VERSION 5.8 ;
BUSBITCHARS "[]" ;
DIVIDERCHAR "/" ;
UNITS
    DATABASE MICRONS 1000 ;
END UNITS

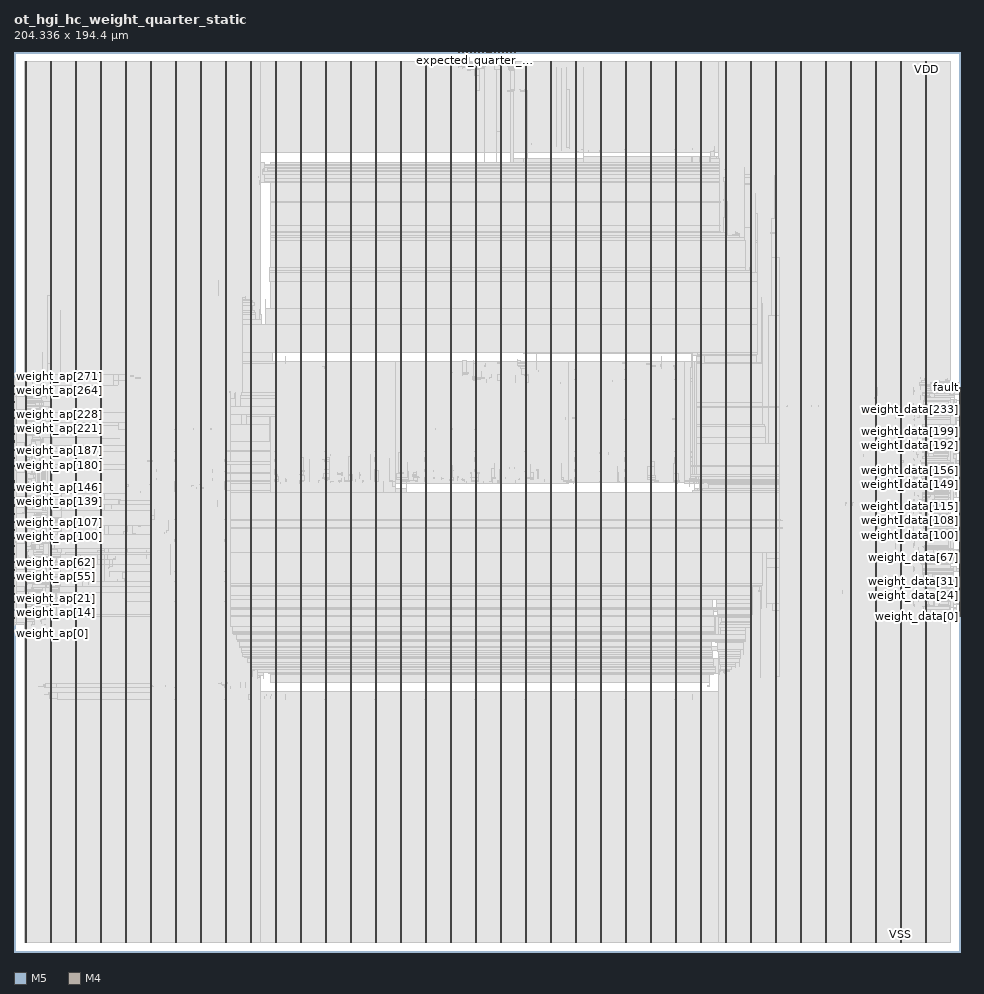
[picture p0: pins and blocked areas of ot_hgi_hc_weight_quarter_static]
MACRO ot_hgi_hc_weight_quarter_static
  FOREIGN ot_hgi_hc_weight_quarter_static 0 0 ;
  CLASS BLOCK ;
  SIZE 204.336 BY 194.4 ;
  PIN clk
    DIRECTION INPUT ;
    USE SIGNAL ;
    PORT
      LAYER M5 ;
        RECT  102.144 194.316 102.168 194.4 ;
    END
  END clk
  PIN expected_bank_id[0]
    DIRECTION INPUT ;
    USE SIGNAL ;
    PORT
      LAYER M5 ;
        RECT  96.096 194.316 96.12 194.4 ;
    END
  END expected_bank_id[0]
  PIN expected_bank_id[1]
    DIRECTION INPUT ;
    USE SIGNAL ;
    PORT
      LAYER M5 ;
        RECT  96.96 194.316 96.984 194.4 ;
    END
  END expected_bank_id[1]
  PIN expected_bank_id[2]
    DIRECTION INPUT ;
    USE SIGNAL ;
    PORT
      LAYER M5 ;
        RECT  97.824 194.316 97.848 194.4 ;
    END
  END expected_bank_id[2]
  PIN expected_quarter_id[0]
    DIRECTION INPUT ;
    USE SIGNAL ;
    PORT
      LAYER M5 ;
        RECT  98.688 194.316 98.712 194.4 ;
    END
  END expected_quarter_id[0]
  PIN expected_quarter_id[1]
    DIRECTION INPUT ;
    USE SIGNAL ;
    PORT
      LAYER M5 ;
        RECT  99.552 194.316 99.576 194.4 ;
    END
  END expected_quarter_id[1]
  PIN fault
    DIRECTION OUTPUT ;
    USE SIGNAL ;
    PORT
      LAYER M4 ;
        RECT  204.252 121.968 204.336 121.992 ;
    END
  END fault
  PIN read_row[0]
    DIRECTION INPUT ;
    USE SIGNAL ;
    PORT
      LAYER M5 ;
        RECT  102.576 194.316 102.6 194.4 ;
    END
  END read_row[0]
  PIN read_row[1]
    DIRECTION INPUT ;
    USE SIGNAL ;
    PORT
      LAYER M5 ;
        RECT  103.008 194.316 103.032 194.4 ;
    END
  END read_row[1]
  PIN read_row[2]
    DIRECTION INPUT ;
    USE SIGNAL ;
    PORT
      LAYER M5 ;
        RECT  103.872 194.316 103.896 194.4 ;
    END
  END read_row[2]
  PIN read_row[3]
    DIRECTION INPUT ;
    USE SIGNAL ;
    PORT
      LAYER M5 ;
        RECT  104.736 194.316 104.76 194.4 ;
    END
  END read_row[3]
  PIN read_row[4]
    DIRECTION INPUT ;
    USE SIGNAL ;
    PORT
      LAYER M5 ;
        RECT  105.6 194.316 105.624 194.4 ;
    END
  END read_row[4]
  PIN read_row[5]
    DIRECTION INPUT ;
    USE SIGNAL ;
    PORT
      LAYER M5 ;
        RECT  106.464 194.316 106.488 194.4 ;
    END
  END read_row[5]
  PIN read_row[6]
    DIRECTION INPUT ;
    USE SIGNAL ;
    PORT
      LAYER M5 ;
        RECT  107.328 194.316 107.352 194.4 ;
    END
  END read_row[6]
  PIN read_slot
    DIRECTION INPUT ;
    USE SIGNAL ;
    PORT
      LAYER M5 ;
        RECT  101.28 194.316 101.304 194.4 ;
    END
  END read_slot
  PIN read_v
    DIRECTION INPUT ;
    USE SIGNAL ;
    PORT
      LAYER M5 ;
        RECT  100.416 194.316 100.44 194.4 ;
    END
  END read_v
  PIN read_valid
    DIRECTION OUTPUT ;
    USE SIGNAL ;
    PORT
      LAYER M4 ;
        RECT  204.252 121.776 204.336 121.8 ;
    END
  END read_valid
  PIN rst_n
    DIRECTION INPUT ;
    USE SIGNAL ;
    PORT
      LAYER M5 ;
        RECT  108.192 194.316 108.216 194.4 ;
    END
  END rst_n
  PIN weight_ap[0]
    DIRECTION INPUT ;
    USE SIGNAL ;
    PORT
      LAYER M4 ;
        RECT  0 70.608 0.084 70.632 ;
    END
  END weight_ap[0]
  PIN weight_ap[100]
    DIRECTION INPUT ;
    USE SIGNAL ;
    PORT
      LAYER M4 ;
        RECT  0 89.808 0.084 89.832 ;
    END
  END weight_ap[100]
  PIN weight_ap[101]
    DIRECTION INPUT ;
    USE SIGNAL ;
    PORT
      LAYER M4 ;
        RECT  0 90 0.084 90.024 ;
    END
  END weight_ap[101]
  PIN weight_ap[102]
    DIRECTION INPUT ;
    USE SIGNAL ;
    PORT
      LAYER M4 ;
        RECT  0 90.192 0.084 90.216 ;
    END
  END weight_ap[102]
  PIN weight_ap[103]
    DIRECTION INPUT ;
    USE SIGNAL ;
    PORT
      LAYER M4 ;
        RECT  0 90.384 0.084 90.408 ;
    END
  END weight_ap[103]
  PIN weight_ap[104]
    DIRECTION INPUT ;
    USE SIGNAL ;
    PORT
      LAYER M4 ;
        RECT  0 90.576 0.084 90.6 ;
    END
  END weight_ap[104]
  PIN weight_ap[105]
    DIRECTION INPUT ;
    USE SIGNAL ;
    PORT
      LAYER M4 ;
        RECT  0 90.768 0.084 90.792 ;
    END
  END weight_ap[105]
  PIN weight_ap[106]
    DIRECTION INPUT ;
    USE SIGNAL ;
    PORT
      LAYER M4 ;
        RECT  0 90.96 0.084 90.984 ;
    END
  END weight_ap[106]
  PIN weight_ap[107]
    DIRECTION INPUT ;
    USE SIGNAL ;
    PORT
      LAYER M4 ;
        RECT  0 91.152 0.084 91.176 ;
    END
  END weight_ap[107]
  PIN weight_ap[108]
    DIRECTION INPUT ;
    USE SIGNAL ;
    PORT
      LAYER M4 ;
        RECT  0 91.344 0.084 91.368 ;
    END
  END weight_ap[108]
  PIN weight_ap[109]
    DIRECTION INPUT ;
    USE SIGNAL ;
    PORT
      LAYER M4 ;
        RECT  0 91.536 0.084 91.56 ;
    END
  END weight_ap[109]
  PIN weight_ap[10]
    DIRECTION INPUT ;
    USE SIGNAL ;
    PORT
      LAYER M4 ;
        RECT  0 72.528 0.084 72.552 ;
    END
  END weight_ap[10]
  PIN weight_ap[110]
    DIRECTION INPUT ;
    USE SIGNAL ;
    PORT
      LAYER M4 ;
        RECT  0 91.728 0.084 91.752 ;
    END
  END weight_ap[110]
  PIN weight_ap[111]
    DIRECTION INPUT ;
    USE SIGNAL ;
    PORT
      LAYER M4 ;
        RECT  0 91.92 0.084 91.944 ;
    END
  END weight_ap[111]
  PIN weight_ap[112]
    DIRECTION INPUT ;
    USE SIGNAL ;
    PORT
      LAYER M4 ;
        RECT  0 92.112 0.084 92.136 ;
    END
  END weight_ap[112]
  PIN weight_ap[113]
    DIRECTION INPUT ;
    USE SIGNAL ;
    PORT
      LAYER M4 ;
        RECT  0 92.304 0.084 92.328 ;
    END
  END weight_ap[113]
  PIN weight_ap[114]
    DIRECTION INPUT ;
    USE SIGNAL ;
    PORT
      LAYER M4 ;
        RECT  0 92.496 0.084 92.52 ;
    END
  END weight_ap[114]
  PIN weight_ap[115]
    DIRECTION INPUT ;
    USE SIGNAL ;
    PORT
      LAYER M4 ;
        RECT  0 92.688 0.084 92.712 ;
    END
  END weight_ap[115]
  PIN weight_ap[116]
    DIRECTION INPUT ;
    USE SIGNAL ;
    PORT
      LAYER M4 ;
        RECT  0 92.88 0.084 92.904 ;
    END
  END weight_ap[116]
  PIN weight_ap[117]
    DIRECTION INPUT ;
    USE SIGNAL ;
    PORT
      LAYER M4 ;
        RECT  0 93.072 0.084 93.096 ;
    END
  END weight_ap[117]
  PIN weight_ap[118]
    DIRECTION INPUT ;
    USE SIGNAL ;
    PORT
      LAYER M4 ;
        RECT  0 93.264 0.084 93.288 ;
    END
  END weight_ap[118]
  PIN weight_ap[119]
    DIRECTION INPUT ;
    USE SIGNAL ;
    PORT
      LAYER M4 ;
        RECT  0 93.456 0.084 93.48 ;
    END
  END weight_ap[119]
  PIN weight_ap[11]
    DIRECTION INPUT ;
    USE SIGNAL ;
    PORT
      LAYER M4 ;
        RECT  0 72.72 0.084 72.744 ;
    END
  END weight_ap[11]
  PIN weight_ap[120]
    DIRECTION INPUT ;
    USE SIGNAL ;
    PORT
      LAYER M4 ;
        RECT  0 93.648 0.084 93.672 ;
    END
  END weight_ap[120]
  PIN weight_ap[121]
    DIRECTION INPUT ;
    USE SIGNAL ;
    PORT
      LAYER M4 ;
        RECT  0 93.84 0.084 93.864 ;
    END
  END weight_ap[121]
  PIN weight_ap[122]
    DIRECTION INPUT ;
    USE SIGNAL ;
    PORT
      LAYER M4 ;
        RECT  0 94.032 0.084 94.056 ;
    END
  END weight_ap[122]
  PIN weight_ap[123]
    DIRECTION INPUT ;
    USE SIGNAL ;
    PORT
      LAYER M4 ;
        RECT  0 94.224 0.084 94.248 ;
    END
  END weight_ap[123]
  PIN weight_ap[124]
    DIRECTION INPUT ;
    USE SIGNAL ;
    PORT
      LAYER M4 ;
        RECT  0 94.416 0.084 94.44 ;
    END
  END weight_ap[124]
  PIN weight_ap[125]
    DIRECTION INPUT ;
    USE SIGNAL ;
    PORT
      LAYER M4 ;
        RECT  0 94.608 0.084 94.632 ;
    END
  END weight_ap[125]
  PIN weight_ap[126]
    DIRECTION INPUT ;
    USE SIGNAL ;
    PORT
      LAYER M4 ;
        RECT  0 94.8 0.084 94.824 ;
    END
  END weight_ap[126]
  PIN weight_ap[127]
    DIRECTION INPUT ;
    USE SIGNAL ;
    PORT
      LAYER M4 ;
        RECT  0 94.992 0.084 95.016 ;
    END
  END weight_ap[127]
  PIN weight_ap[128]
    DIRECTION INPUT ;
    USE SIGNAL ;
    PORT
      LAYER M4 ;
        RECT  0 95.184 0.084 95.208 ;
    END
  END weight_ap[128]
  PIN weight_ap[129]
    DIRECTION INPUT ;
    USE SIGNAL ;
    PORT
      LAYER M4 ;
        RECT  0 95.376 0.084 95.4 ;
    END
  END weight_ap[129]
  PIN weight_ap[12]
    DIRECTION INPUT ;
    USE SIGNAL ;
    PORT
      LAYER M4 ;
        RECT  0 72.912 0.084 72.936 ;
    END
  END weight_ap[12]
  PIN weight_ap[130]
    DIRECTION INPUT ;
    USE SIGNAL ;
    PORT
      LAYER M4 ;
        RECT  0 95.568 0.084 95.592 ;
    END
  END weight_ap[130]
  PIN weight_ap[131]
    DIRECTION INPUT ;
    USE SIGNAL ;
    PORT
      LAYER M4 ;
        RECT  0 95.76 0.084 95.784 ;
    END
  END weight_ap[131]
  PIN weight_ap[132]
    DIRECTION INPUT ;
    USE SIGNAL ;
    PORT
      LAYER M4 ;
        RECT  0 95.952 0.084 95.976 ;
    END
  END weight_ap[132]
  PIN weight_ap[133]
    DIRECTION INPUT ;
    USE SIGNAL ;
    PORT
      LAYER M4 ;
        RECT  0 96.144 0.084 96.168 ;
    END
  END weight_ap[133]
  PIN weight_ap[134]
    DIRECTION INPUT ;
    USE SIGNAL ;
    PORT
      LAYER M4 ;
        RECT  0 96.336 0.084 96.36 ;
    END
  END weight_ap[134]
  PIN weight_ap[135]
    DIRECTION INPUT ;
    USE SIGNAL ;
    PORT
      LAYER M4 ;
        RECT  0 96.528 0.084 96.552 ;
    END
  END weight_ap[135]
  PIN weight_ap[136]
    DIRECTION INPUT ;
    USE SIGNAL ;
    PORT
      LAYER M4 ;
        RECT  0 96.72 0.084 96.744 ;
    END
  END weight_ap[136]
  PIN weight_ap[137]
    DIRECTION INPUT ;
    USE SIGNAL ;
    PORT
      LAYER M4 ;
        RECT  0 96.912 0.084 96.936 ;
    END
  END weight_ap[137]
  PIN weight_ap[138]
    DIRECTION INPUT ;
    USE SIGNAL ;
    PORT
      LAYER M4 ;
        RECT  0 97.104 0.084 97.128 ;
    END
  END weight_ap[138]
  PIN weight_ap[139]
    DIRECTION INPUT ;
    USE SIGNAL ;
    PORT
      LAYER M4 ;
        RECT  0 97.296 0.084 97.32 ;
    END
  END weight_ap[139]
  PIN weight_ap[13]
    DIRECTION INPUT ;
    USE SIGNAL ;
    PORT
      LAYER M4 ;
        RECT  0 73.104 0.084 73.128 ;
    END
  END weight_ap[13]
  PIN weight_ap[140]
    DIRECTION INPUT ;
    USE SIGNAL ;
    PORT
      LAYER M4 ;
        RECT  0 97.488 0.084 97.512 ;
    END
  END weight_ap[140]
  PIN weight_ap[141]
    DIRECTION INPUT ;
    USE SIGNAL ;
    PORT
      LAYER M4 ;
        RECT  0 97.68 0.084 97.704 ;
    END
  END weight_ap[141]
  PIN weight_ap[142]
    DIRECTION INPUT ;
    USE SIGNAL ;
    PORT
      LAYER M4 ;
        RECT  0 97.872 0.084 97.896 ;
    END
  END weight_ap[142]
  PIN weight_ap[143]
    DIRECTION INPUT ;
    USE SIGNAL ;
    PORT
      LAYER M4 ;
        RECT  0 98.064 0.084 98.088 ;
    END
  END weight_ap[143]
  PIN weight_ap[144]
    DIRECTION INPUT ;
    USE SIGNAL ;
    PORT
      LAYER M4 ;
        RECT  0 98.256 0.084 98.28 ;
    END
  END weight_ap[144]
  PIN weight_ap[145]
    DIRECTION INPUT ;
    USE SIGNAL ;
    PORT
      LAYER M4 ;
        RECT  0 98.448 0.084 98.472 ;
    END
  END weight_ap[145]
  PIN weight_ap[146]
    DIRECTION INPUT ;
    USE SIGNAL ;
    PORT
      LAYER M4 ;
        RECT  0 98.64 0.084 98.664 ;
    END
  END weight_ap[146]
  PIN weight_ap[147]
    DIRECTION INPUT ;
    USE SIGNAL ;
    PORT
      LAYER M4 ;
        RECT  0 98.832 0.084 98.856 ;
    END
  END weight_ap[147]
  PIN weight_ap[148]
    DIRECTION INPUT ;
    USE SIGNAL ;
    PORT
      LAYER M4 ;
        RECT  0 99.024 0.084 99.048 ;
    END
  END weight_ap[148]
  PIN weight_ap[149]
    DIRECTION INPUT ;
    USE SIGNAL ;
    PORT
      LAYER M4 ;
        RECT  0 99.216 0.084 99.24 ;
    END
  END weight_ap[149]
  PIN weight_ap[14]
    DIRECTION INPUT ;
    USE SIGNAL ;
    PORT
      LAYER M4 ;
        RECT  0 73.296 0.084 73.32 ;
    END
  END weight_ap[14]
  PIN weight_ap[150]
    DIRECTION INPUT ;
    USE SIGNAL ;
    PORT
      LAYER M4 ;
        RECT  0 99.408 0.084 99.432 ;
    END
  END weight_ap[150]
  PIN weight_ap[151]
    DIRECTION INPUT ;
    USE SIGNAL ;
    PORT
      LAYER M4 ;
        RECT  0 99.6 0.084 99.624 ;
    END
  END weight_ap[151]
  PIN weight_ap[152]
    DIRECTION INPUT ;
    USE SIGNAL ;
    PORT
      LAYER M4 ;
        RECT  0 99.792 0.084 99.816 ;
    END
  END weight_ap[152]
  PIN weight_ap[153]
    DIRECTION INPUT ;
    USE SIGNAL ;
    PORT
      LAYER M4 ;
        RECT  0 99.984 0.084 100.008 ;
    END
  END weight_ap[153]
  PIN weight_ap[154]
    DIRECTION INPUT ;
    USE SIGNAL ;
    PORT
      LAYER M4 ;
        RECT  0 100.176 0.084 100.2 ;
    END
  END weight_ap[154]
  PIN weight_ap[155]
    DIRECTION INPUT ;
    USE SIGNAL ;
    PORT
      LAYER M4 ;
        RECT  0 100.368 0.084 100.392 ;
    END
  END weight_ap[155]
  PIN weight_ap[156]
    DIRECTION INPUT ;
    USE SIGNAL ;
    PORT
      LAYER M4 ;
        RECT  0 100.56 0.084 100.584 ;
    END
  END weight_ap[156]
  PIN weight_ap[157]
    DIRECTION INPUT ;
    USE SIGNAL ;
    PORT
      LAYER M4 ;
        RECT  0 100.752 0.084 100.776 ;
    END
  END weight_ap[157]
  PIN weight_ap[158]
    DIRECTION INPUT ;
    USE SIGNAL ;
    PORT
      LAYER M4 ;
        RECT  0 100.944 0.084 100.968 ;
    END
  END weight_ap[158]
  PIN weight_ap[159]
    DIRECTION INPUT ;
    USE SIGNAL ;
    PORT
      LAYER M4 ;
        RECT  0 101.136 0.084 101.16 ;
    END
  END weight_ap[159]
  PIN weight_ap[15]
    DIRECTION INPUT ;
    USE SIGNAL ;
    PORT
      LAYER M4 ;
        RECT  0 73.488 0.084 73.512 ;
    END
  END weight_ap[15]
  PIN weight_ap[160]
    DIRECTION INPUT ;
    USE SIGNAL ;
    PORT
      LAYER M4 ;
        RECT  0 101.328 0.084 101.352 ;
    END
  END weight_ap[160]
  PIN weight_ap[161]
    DIRECTION INPUT ;
    USE SIGNAL ;
    PORT
      LAYER M4 ;
        RECT  0 101.52 0.084 101.544 ;
    END
  END weight_ap[161]
  PIN weight_ap[162]
    DIRECTION INPUT ;
    USE SIGNAL ;
    PORT
      LAYER M4 ;
        RECT  0 101.712 0.084 101.736 ;
    END
  END weight_ap[162]
  PIN weight_ap[163]
    DIRECTION INPUT ;
    USE SIGNAL ;
    PORT
      LAYER M4 ;
        RECT  0 101.904 0.084 101.928 ;
    END
  END weight_ap[163]
  PIN weight_ap[164]
    DIRECTION INPUT ;
    USE SIGNAL ;
    PORT
      LAYER M4 ;
        RECT  0 102.096 0.084 102.12 ;
    END
  END weight_ap[164]
  PIN weight_ap[165]
    DIRECTION INPUT ;
    USE SIGNAL ;
    PORT
      LAYER M4 ;
        RECT  0 102.288 0.084 102.312 ;
    END
  END weight_ap[165]
  PIN weight_ap[166]
    DIRECTION INPUT ;
    USE SIGNAL ;
    PORT
      LAYER M4 ;
        RECT  0 102.48 0.084 102.504 ;
    END
  END weight_ap[166]
  PIN weight_ap[167]
    DIRECTION INPUT ;
    USE SIGNAL ;
    PORT
      LAYER M4 ;
        RECT  0 102.672 0.084 102.696 ;
    END
  END weight_ap[167]
  PIN weight_ap[168]
    DIRECTION INPUT ;
    USE SIGNAL ;
    PORT
      LAYER M4 ;
        RECT  0 102.864 0.084 102.888 ;
    END
  END weight_ap[168]
  PIN weight_ap[169]
    DIRECTION INPUT ;
    USE SIGNAL ;
    PORT
      LAYER M4 ;
        RECT  0 103.056 0.084 103.08 ;
    END
  END weight_ap[169]
  PIN weight_ap[16]
    DIRECTION INPUT ;
    USE SIGNAL ;
    PORT
      LAYER M4 ;
        RECT  0 73.68 0.084 73.704 ;
    END
  END weight_ap[16]
  PIN weight_ap[170]
    DIRECTION INPUT ;
    USE SIGNAL ;
    PORT
      LAYER M4 ;
        RECT  0 103.248 0.084 103.272 ;
    END
  END weight_ap[170]
  PIN weight_ap[171]
    DIRECTION INPUT ;
    USE SIGNAL ;
    PORT
      LAYER M4 ;
        RECT  0 103.44 0.084 103.464 ;
    END
  END weight_ap[171]
  PIN weight_ap[172]
    DIRECTION INPUT ;
    USE SIGNAL ;
    PORT
      LAYER M4 ;
        RECT  0 103.632 0.084 103.656 ;
    END
  END weight_ap[172]
  PIN weight_ap[173]
    DIRECTION INPUT ;
    USE SIGNAL ;
    PORT
      LAYER M4 ;
        RECT  0 103.824 0.084 103.848 ;
    END
  END weight_ap[173]
  PIN weight_ap[174]
    DIRECTION INPUT ;
    USE SIGNAL ;
    PORT
      LAYER M4 ;
        RECT  0 104.016 0.084 104.04 ;
    END
  END weight_ap[174]
  PIN weight_ap[175]
    DIRECTION INPUT ;
    USE SIGNAL ;
    PORT
      LAYER M4 ;
        RECT  0 104.208 0.084 104.232 ;
    END
  END weight_ap[175]
  PIN weight_ap[176]
    DIRECTION INPUT ;
    USE SIGNAL ;
    PORT
      LAYER M4 ;
        RECT  0 104.4 0.084 104.424 ;
    END
  END weight_ap[176]
  PIN weight_ap[177]
    DIRECTION INPUT ;
    USE SIGNAL ;
    PORT
      LAYER M4 ;
        RECT  0 104.592 0.084 104.616 ;
    END
  END weight_ap[177]
  PIN weight_ap[178]
    DIRECTION INPUT ;
    USE SIGNAL ;
    PORT
      LAYER M4 ;
        RECT  0 104.784 0.084 104.808 ;
    END
  END weight_ap[178]
  PIN weight_ap[179]
    DIRECTION INPUT ;
    USE SIGNAL ;
    PORT
      LAYER M4 ;
        RECT  0 104.976 0.084 105 ;
    END
  END weight_ap[179]
  PIN weight_ap[17]
    DIRECTION INPUT ;
    USE SIGNAL ;
    PORT
      LAYER M4 ;
        RECT  0 73.872 0.084 73.896 ;
    END
  END weight_ap[17]
  PIN weight_ap[180]
    DIRECTION INPUT ;
    USE SIGNAL ;
    PORT
      LAYER M4 ;
        RECT  0 105.168 0.084 105.192 ;
    END
  END weight_ap[180]
  PIN weight_ap[181]
    DIRECTION INPUT ;
    USE SIGNAL ;
    PORT
      LAYER M4 ;
        RECT  0 105.36 0.084 105.384 ;
    END
  END weight_ap[181]
  PIN weight_ap[182]
    DIRECTION INPUT ;
    USE SIGNAL ;
    PORT
      LAYER M4 ;
        RECT  0 105.552 0.084 105.576 ;
    END
  END weight_ap[182]
  PIN weight_ap[183]
    DIRECTION INPUT ;
    USE SIGNAL ;
    PORT
      LAYER M4 ;
        RECT  0 105.744 0.084 105.768 ;
    END
  END weight_ap[183]
  PIN weight_ap[184]
    DIRECTION INPUT ;
    USE SIGNAL ;
    PORT
      LAYER M4 ;
        RECT  0 105.936 0.084 105.96 ;
    END
  END weight_ap[184]
  PIN weight_ap[185]
    DIRECTION INPUT ;
    USE SIGNAL ;
    PORT
      LAYER M4 ;
        RECT  0 106.128 0.084 106.152 ;
    END
  END weight_ap[185]
  PIN weight_ap[186]
    DIRECTION INPUT ;
    USE SIGNAL ;
    PORT
      LAYER M4 ;
        RECT  0 106.32 0.084 106.344 ;
    END
  END weight_ap[186]
  PIN weight_ap[187]
    DIRECTION INPUT ;
    USE SIGNAL ;
    PORT
      LAYER M4 ;
        RECT  0 106.512 0.084 106.536 ;
    END
  END weight_ap[187]
  PIN weight_ap[188]
    DIRECTION INPUT ;
    USE SIGNAL ;
    PORT
      LAYER M4 ;
        RECT  0 106.704 0.084 106.728 ;
    END
  END weight_ap[188]
  PIN weight_ap[189]
    DIRECTION INPUT ;
    USE SIGNAL ;
    PORT
      LAYER M4 ;
        RECT  0 106.896 0.084 106.92 ;
    END
  END weight_ap[189]
  PIN weight_ap[18]
    DIRECTION INPUT ;
    USE SIGNAL ;
    PORT
      LAYER M4 ;
        RECT  0 74.064 0.084 74.088 ;
    END
  END weight_ap[18]
  PIN weight_ap[190]
    DIRECTION INPUT ;
    USE SIGNAL ;
    PORT
      LAYER M4 ;
        RECT  0 107.088 0.084 107.112 ;
    END
  END weight_ap[190]
  PIN weight_ap[191]
    DIRECTION INPUT ;
    USE SIGNAL ;
    PORT
      LAYER M4 ;
        RECT  0 107.28 0.084 107.304 ;
    END
  END weight_ap[191]
  PIN weight_ap[192]
    DIRECTION INPUT ;
    USE SIGNAL ;
    PORT
      LAYER M4 ;
        RECT  0 107.472 0.084 107.496 ;
    END
  END weight_ap[192]
  PIN weight_ap[193]
    DIRECTION INPUT ;
    USE SIGNAL ;
    PORT
      LAYER M4 ;
        RECT  0 107.664 0.084 107.688 ;
    END
  END weight_ap[193]
  PIN weight_ap[194]
    DIRECTION INPUT ;
    USE SIGNAL ;
    PORT
      LAYER M4 ;
        RECT  0 107.856 0.084 107.88 ;
    END
  END weight_ap[194]
  PIN weight_ap[195]
    DIRECTION INPUT ;
    USE SIGNAL ;
    PORT
      LAYER M4 ;
        RECT  0 108.048 0.084 108.072 ;
    END
  END weight_ap[195]
  PIN weight_ap[196]
    DIRECTION INPUT ;
    USE SIGNAL ;
    PORT
      LAYER M4 ;
        RECT  0 108.24 0.084 108.264 ;
    END
  END weight_ap[196]
  PIN weight_ap[197]
    DIRECTION INPUT ;
    USE SIGNAL ;
    PORT
      LAYER M4 ;
        RECT  0 108.432 0.084 108.456 ;
    END
  END weight_ap[197]
  PIN weight_ap[198]
    DIRECTION INPUT ;
    USE SIGNAL ;
    PORT
      LAYER M4 ;
        RECT  0 108.624 0.084 108.648 ;
    END
  END weight_ap[198]
  PIN weight_ap[199]
    DIRECTION INPUT ;
    USE SIGNAL ;
    PORT
      LAYER M4 ;
        RECT  0 108.816 0.084 108.84 ;
    END
  END weight_ap[199]
  PIN weight_ap[19]
    DIRECTION INPUT ;
    USE SIGNAL ;
    PORT
      LAYER M4 ;
        RECT  0 74.256 0.084 74.28 ;
    END
  END weight_ap[19]
  PIN weight_ap[1]
    DIRECTION INPUT ;
    USE SIGNAL ;
    PORT
      LAYER M4 ;
        RECT  0 70.8 0.084 70.824 ;
    END
  END weight_ap[1]
  PIN weight_ap[200]
    DIRECTION INPUT ;
    USE SIGNAL ;
    PORT
      LAYER M4 ;
        RECT  0 109.008 0.084 109.032 ;
    END
  END weight_ap[200]
  PIN weight_ap[201]
    DIRECTION INPUT ;
    USE SIGNAL ;
    PORT
      LAYER M4 ;
        RECT  0 109.2 0.084 109.224 ;
    END
  END weight_ap[201]
  PIN weight_ap[202]
    DIRECTION INPUT ;
    USE SIGNAL ;
    PORT
      LAYER M4 ;
        RECT  0 109.392 0.084 109.416 ;
    END
  END weight_ap[202]
  PIN weight_ap[203]
    DIRECTION INPUT ;
    USE SIGNAL ;
    PORT
      LAYER M4 ;
        RECT  0 109.584 0.084 109.608 ;
    END
  END weight_ap[203]
  PIN weight_ap[204]
    DIRECTION INPUT ;
    USE SIGNAL ;
    PORT
      LAYER M4 ;
        RECT  0 109.776 0.084 109.8 ;
    END
  END weight_ap[204]
  PIN weight_ap[205]
    DIRECTION INPUT ;
    USE SIGNAL ;
    PORT
      LAYER M4 ;
        RECT  0 109.968 0.084 109.992 ;
    END
  END weight_ap[205]
  PIN weight_ap[206]
    DIRECTION INPUT ;
    USE SIGNAL ;
    PORT
      LAYER M4 ;
        RECT  0 110.16 0.084 110.184 ;
    END
  END weight_ap[206]
  PIN weight_ap[207]
    DIRECTION INPUT ;
    USE SIGNAL ;
    PORT
      LAYER M4 ;
        RECT  0 110.352 0.084 110.376 ;
    END
  END weight_ap[207]
  PIN weight_ap[208]
    DIRECTION INPUT ;
    USE SIGNAL ;
    PORT
      LAYER M4 ;
        RECT  0 110.544 0.084 110.568 ;
    END
  END weight_ap[208]
  PIN weight_ap[209]
    DIRECTION INPUT ;
    USE SIGNAL ;
    PORT
      LAYER M4 ;
        RECT  0 110.736 0.084 110.76 ;
    END
  END weight_ap[209]
  PIN weight_ap[20]
    DIRECTION INPUT ;
    USE SIGNAL ;
    PORT
      LAYER M4 ;
        RECT  0 74.448 0.084 74.472 ;
    END
  END weight_ap[20]
  PIN weight_ap[210]
    DIRECTION INPUT ;
    USE SIGNAL ;
    PORT
      LAYER M4 ;
        RECT  0 110.928 0.084 110.952 ;
    END
  END weight_ap[210]
  PIN weight_ap[211]
    DIRECTION INPUT ;
    USE SIGNAL ;
    PORT
      LAYER M4 ;
        RECT  0 111.12 0.084 111.144 ;
    END
  END weight_ap[211]
  PIN weight_ap[212]
    DIRECTION INPUT ;
    USE SIGNAL ;
    PORT
      LAYER M4 ;
        RECT  0 111.312 0.084 111.336 ;
    END
  END weight_ap[212]
  PIN weight_ap[213]
    DIRECTION INPUT ;
    USE SIGNAL ;
    PORT
      LAYER M4 ;
        RECT  0 111.504 0.084 111.528 ;
    END
  END weight_ap[213]
  PIN weight_ap[214]
    DIRECTION INPUT ;
    USE SIGNAL ;
    PORT
      LAYER M4 ;
        RECT  0 111.696 0.084 111.72 ;
    END
  END weight_ap[214]
  PIN weight_ap[215]
    DIRECTION INPUT ;
    USE SIGNAL ;
    PORT
      LAYER M4 ;
        RECT  0 111.888 0.084 111.912 ;
    END
  END weight_ap[215]
  PIN weight_ap[216]
    DIRECTION INPUT ;
    USE SIGNAL ;
    PORT
      LAYER M4 ;
        RECT  0 112.08 0.084 112.104 ;
    END
  END weight_ap[216]
  PIN weight_ap[217]
    DIRECTION INPUT ;
    USE SIGNAL ;
    PORT
      LAYER M4 ;
        RECT  0 112.272 0.084 112.296 ;
    END
  END weight_ap[217]
  PIN weight_ap[218]
    DIRECTION INPUT ;
    USE SIGNAL ;
    PORT
      LAYER M4 ;
        RECT  0 112.464 0.084 112.488 ;
    END
  END weight_ap[218]
  PIN weight_ap[219]
    DIRECTION INPUT ;
    USE SIGNAL ;
    PORT
      LAYER M4 ;
        RECT  0 112.656 0.084 112.68 ;
    END
  END weight_ap[219]
  PIN weight_ap[21]
    DIRECTION INPUT ;
    USE SIGNAL ;
    PORT
      LAYER M4 ;
        RECT  0 74.64 0.084 74.664 ;
    END
  END weight_ap[21]
  PIN weight_ap[220]
    DIRECTION INPUT ;
    USE SIGNAL ;
    PORT
      LAYER M4 ;
        RECT  0 112.848 0.084 112.872 ;
    END
  END weight_ap[220]
  PIN weight_ap[221]
    DIRECTION INPUT ;
    USE SIGNAL ;
    PORT
      LAYER M4 ;
        RECT  0 113.04 0.084 113.064 ;
    END
  END weight_ap[221]
  PIN weight_ap[222]
    DIRECTION INPUT ;
    USE SIGNAL ;
    PORT
      LAYER M4 ;
        RECT  0 113.232 0.084 113.256 ;
    END
  END weight_ap[222]
  PIN weight_ap[223]
    DIRECTION INPUT ;
    USE SIGNAL ;
    PORT
      LAYER M4 ;
        RECT  0 113.424 0.084 113.448 ;
    END
  END weight_ap[223]
  PIN weight_ap[224]
    DIRECTION INPUT ;
    USE SIGNAL ;
    PORT
      LAYER M4 ;
        RECT  0 113.616 0.084 113.64 ;
    END
  END weight_ap[224]
  PIN weight_ap[225]
    DIRECTION INPUT ;
    USE SIGNAL ;
    PORT
      LAYER M4 ;
        RECT  0 113.808 0.084 113.832 ;
    END
  END weight_ap[225]
  PIN weight_ap[226]
    DIRECTION INPUT ;
    USE SIGNAL ;
    PORT
      LAYER M4 ;
        RECT  0 114 0.084 114.024 ;
    END
  END weight_ap[226]
  PIN weight_ap[227]
    DIRECTION INPUT ;
    USE SIGNAL ;
    PORT
      LAYER M4 ;
        RECT  0 114.192 0.084 114.216 ;
    END
  END weight_ap[227]
  PIN weight_ap[228]
    DIRECTION INPUT ;
    USE SIGNAL ;
    PORT
      LAYER M4 ;
        RECT  0 114.384 0.084 114.408 ;
    END
  END weight_ap[228]
  PIN weight_ap[229]
    DIRECTION INPUT ;
    USE SIGNAL ;
    PORT
      LAYER M4 ;
        RECT  0 114.576 0.084 114.6 ;
    END
  END weight_ap[229]
  PIN weight_ap[22]
    DIRECTION INPUT ;
    USE SIGNAL ;
    PORT
      LAYER M4 ;
        RECT  0 74.832 0.084 74.856 ;
    END
  END weight_ap[22]
  PIN weight_ap[230]
    DIRECTION INPUT ;
    USE SIGNAL ;
    PORT
      LAYER M4 ;
        RECT  0 114.768 0.084 114.792 ;
    END
  END weight_ap[230]
  PIN weight_ap[231]
    DIRECTION INPUT ;
    USE SIGNAL ;
    PORT
      LAYER M4 ;
        RECT  0 114.96 0.084 114.984 ;
    END
  END weight_ap[231]
  PIN weight_ap[232]
    DIRECTION INPUT ;
    USE SIGNAL ;
    PORT
      LAYER M4 ;
        RECT  0 115.152 0.084 115.176 ;
    END
  END weight_ap[232]
  PIN weight_ap[233]
    DIRECTION INPUT ;
    USE SIGNAL ;
    PORT
      LAYER M4 ;
        RECT  0 115.344 0.084 115.368 ;
    END
  END weight_ap[233]
  PIN weight_ap[234]
    DIRECTION INPUT ;
    USE SIGNAL ;
    PORT
      LAYER M4 ;
        RECT  0 115.536 0.084 115.56 ;
    END
  END weight_ap[234]
  PIN weight_ap[235]
    DIRECTION INPUT ;
    USE SIGNAL ;
    PORT
      LAYER M4 ;
        RECT  0 115.728 0.084 115.752 ;
    END
  END weight_ap[235]
  PIN weight_ap[236]
    DIRECTION INPUT ;
    USE SIGNAL ;
    PORT
      LAYER M4 ;
        RECT  0 115.92 0.084 115.944 ;
    END
  END weight_ap[236]
  PIN weight_ap[237]
    DIRECTION INPUT ;
    USE SIGNAL ;
    PORT
      LAYER M4 ;
        RECT  0 116.112 0.084 116.136 ;
    END
  END weight_ap[237]
  PIN weight_ap[238]
    DIRECTION INPUT ;
    USE SIGNAL ;
    PORT
      LAYER M4 ;
        RECT  0 116.304 0.084 116.328 ;
    END
  END weight_ap[238]
  PIN weight_ap[239]
    DIRECTION INPUT ;
    USE SIGNAL ;
    PORT
      LAYER M4 ;
        RECT  0 116.496 0.084 116.52 ;
    END
  END weight_ap[239]
  PIN weight_ap[23]
    DIRECTION INPUT ;
    USE SIGNAL ;
    PORT
      LAYER M4 ;
        RECT  0 75.024 0.084 75.048 ;
    END
  END weight_ap[23]
  PIN weight_ap[240]
    DIRECTION INPUT ;
    USE SIGNAL ;
    PORT
      LAYER M4 ;
        RECT  0 116.688 0.084 116.712 ;
    END
  END weight_ap[240]
  PIN weight_ap[241]
    DIRECTION INPUT ;
    USE SIGNAL ;
    PORT
      LAYER M4 ;
        RECT  0 116.88 0.084 116.904 ;
    END
  END weight_ap[241]
  PIN weight_ap[242]
    DIRECTION INPUT ;
    USE SIGNAL ;
    PORT
      LAYER M4 ;
        RECT  0 117.072 0.084 117.096 ;
    END
  END weight_ap[242]
  PIN weight_ap[243]
    DIRECTION INPUT ;
    USE SIGNAL ;
    PORT
      LAYER M4 ;
        RECT  0 117.264 0.084 117.288 ;
    END
  END weight_ap[243]
  PIN weight_ap[244]
    DIRECTION INPUT ;
    USE SIGNAL ;
    PORT
      LAYER M4 ;
        RECT  0 117.456 0.084 117.48 ;
    END
  END weight_ap[244]
  PIN weight_ap[245]
    DIRECTION INPUT ;
    USE SIGNAL ;
    PORT
      LAYER M4 ;
        RECT  0 117.648 0.084 117.672 ;
    END
  END weight_ap[245]
  PIN weight_ap[246]
    DIRECTION INPUT ;
    USE SIGNAL ;
    PORT
      LAYER M4 ;
        RECT  0 117.84 0.084 117.864 ;
    END
  END weight_ap[246]
  PIN weight_ap[247]
    DIRECTION INPUT ;
    USE SIGNAL ;
    PORT
      LAYER M4 ;
        RECT  0 118.032 0.084 118.056 ;
    END
  END weight_ap[247]
  PIN weight_ap[248]
    DIRECTION INPUT ;
    USE SIGNAL ;
    PORT
      LAYER M4 ;
        RECT  0 118.224 0.084 118.248 ;
    END
  END weight_ap[248]
  PIN weight_ap[249]
    DIRECTION INPUT ;
    USE SIGNAL ;
    PORT
      LAYER M4 ;
        RECT  0 118.416 0.084 118.44 ;
    END
  END weight_ap[249]
  PIN weight_ap[24]
    DIRECTION INPUT ;
    USE SIGNAL ;
    PORT
      LAYER M4 ;
        RECT  0 75.216 0.084 75.24 ;
    END
  END weight_ap[24]
  PIN weight_ap[250]
    DIRECTION INPUT ;
    USE SIGNAL ;
    PORT
      LAYER M4 ;
        RECT  0 118.608 0.084 118.632 ;
    END
  END weight_ap[250]
  PIN weight_ap[251]
    DIRECTION INPUT ;
    USE SIGNAL ;
    PORT
      LAYER M4 ;
        RECT  0 118.8 0.084 118.824 ;
    END
  END weight_ap[251]
  PIN weight_ap[252]
    DIRECTION INPUT ;
    USE SIGNAL ;
    PORT
      LAYER M4 ;
        RECT  0 118.992 0.084 119.016 ;
    END
  END weight_ap[252]
  PIN weight_ap[253]
    DIRECTION INPUT ;
    USE SIGNAL ;
    PORT
      LAYER M4 ;
        RECT  0 119.184 0.084 119.208 ;
    END
  END weight_ap[253]
  PIN weight_ap[254]
    DIRECTION INPUT ;
    USE SIGNAL ;
    PORT
      LAYER M4 ;
        RECT  0 119.376 0.084 119.4 ;
    END
  END weight_ap[254]
  PIN weight_ap[255]
    DIRECTION INPUT ;
    USE SIGNAL ;
    PORT
      LAYER M4 ;
        RECT  0 119.568 0.084 119.592 ;
    END
  END weight_ap[255]
  PIN weight_ap[256]
    DIRECTION INPUT ;
    USE SIGNAL ;
    PORT
      LAYER M4 ;
        RECT  0 119.76 0.084 119.784 ;
    END
  END weight_ap[256]
  PIN weight_ap[257]
    DIRECTION INPUT ;
    USE SIGNAL ;
    PORT
      LAYER M4 ;
        RECT  0 119.952 0.084 119.976 ;
    END
  END weight_ap[257]
  PIN weight_ap[258]
    DIRECTION INPUT ;
    USE SIGNAL ;
    PORT
      LAYER M4 ;
        RECT  0 120.144 0.084 120.168 ;
    END
  END weight_ap[258]
  PIN weight_ap[259]
    DIRECTION INPUT ;
    USE SIGNAL ;
    PORT
      LAYER M4 ;
        RECT  0 120.336 0.084 120.36 ;
    END
  END weight_ap[259]
  PIN weight_ap[25]
    DIRECTION INPUT ;
    USE SIGNAL ;
    PORT
      LAYER M4 ;
        RECT  0 75.408 0.084 75.432 ;
    END
  END weight_ap[25]
  PIN weight_ap[260]
    DIRECTION INPUT ;
    USE SIGNAL ;
    PORT
      LAYER M4 ;
        RECT  0 120.528 0.084 120.552 ;
    END
  END weight_ap[260]
  PIN weight_ap[261]
    DIRECTION INPUT ;
    USE SIGNAL ;
    PORT
      LAYER M4 ;
        RECT  0 120.72 0.084 120.744 ;
    END
  END weight_ap[261]
  PIN weight_ap[262]
    DIRECTION INPUT ;
    USE SIGNAL ;
    PORT
      LAYER M4 ;
        RECT  0 120.912 0.084 120.936 ;
    END
  END weight_ap[262]
  PIN weight_ap[263]
    DIRECTION INPUT ;
    USE SIGNAL ;
    PORT
      LAYER M4 ;
        RECT  0 121.104 0.084 121.128 ;
    END
  END weight_ap[263]
  PIN weight_ap[264]
    DIRECTION INPUT ;
    USE SIGNAL ;
    PORT
      LAYER M4 ;
        RECT  0 121.296 0.084 121.32 ;
    END
  END weight_ap[264]
  PIN weight_ap[265]
    DIRECTION INPUT ;
    USE SIGNAL ;
    PORT
      LAYER M4 ;
        RECT  0 121.488 0.084 121.512 ;
    END
  END weight_ap[265]
  PIN weight_ap[266]
    DIRECTION INPUT ;
    USE SIGNAL ;
    PORT
      LAYER M4 ;
        RECT  0 121.68 0.084 121.704 ;
    END
  END weight_ap[266]
  PIN weight_ap[267]
    DIRECTION INPUT ;
    USE SIGNAL ;
    PORT
      LAYER M4 ;
        RECT  0 121.872 0.084 121.896 ;
    END
  END weight_ap[267]
  PIN weight_ap[268]
    DIRECTION INPUT ;
    USE SIGNAL ;
    PORT
      LAYER M4 ;
        RECT  0 122.064 0.084 122.088 ;
    END
  END weight_ap[268]
  PIN weight_ap[269]
    DIRECTION INPUT ;
    USE SIGNAL ;
    PORT
      LAYER M4 ;
        RECT  0 122.256 0.084 122.28 ;
    END
  END weight_ap[269]
  PIN weight_ap[26]
    DIRECTION INPUT ;
    USE SIGNAL ;
    PORT
      LAYER M4 ;
        RECT  0 75.6 0.084 75.624 ;
    END
  END weight_ap[26]
  PIN weight_ap[270]
    DIRECTION INPUT ;
    USE SIGNAL ;
    PORT
      LAYER M4 ;
        RECT  0 122.448 0.084 122.472 ;
    END
  END weight_ap[270]
  PIN weight_ap[271]
    DIRECTION INPUT ;
    USE SIGNAL ;
    PORT
      LAYER M4 ;
        RECT  0 122.64 0.084 122.664 ;
    END
  END weight_ap[271]
  PIN weight_ap[272]
    DIRECTION INPUT ;
    USE SIGNAL ;
    PORT
      LAYER M4 ;
        RECT  0 122.832 0.084 122.856 ;
    END
  END weight_ap[272]
  PIN weight_ap[273]
    DIRECTION INPUT ;
    USE SIGNAL ;
    PORT
      LAYER M4 ;
        RECT  0 123.024 0.084 123.048 ;
    END
  END weight_ap[273]
  PIN weight_ap[274]
    DIRECTION INPUT ;
    USE SIGNAL ;
    PORT
      LAYER M4 ;
        RECT  0 123.216 0.084 123.24 ;
    END
  END weight_ap[274]
  PIN weight_ap[275]
    DIRECTION INPUT ;
    USE SIGNAL ;
    PORT
      LAYER M4 ;
        RECT  0 123.408 0.084 123.432 ;
    END
  END weight_ap[275]
  PIN weight_ap[276]
    DIRECTION INPUT ;
    USE SIGNAL ;
    PORT
      LAYER M4 ;
        RECT  0 123.6 0.084 123.624 ;
    END
  END weight_ap[276]
  PIN weight_ap[277]
    DIRECTION INPUT ;
    USE SIGNAL ;
    PORT
      LAYER M4 ;
        RECT  0 123.792 0.084 123.816 ;
    END
  END weight_ap[277]
  PIN weight_ap[27]
    DIRECTION INPUT ;
    USE SIGNAL ;
    PORT
      LAYER M4 ;
        RECT  0 75.792 0.084 75.816 ;
    END
  END weight_ap[27]
  PIN weight_ap[28]
    DIRECTION INPUT ;
    USE SIGNAL ;
    PORT
      LAYER M4 ;
        RECT  0 75.984 0.084 76.008 ;
    END
  END weight_ap[28]
  PIN weight_ap[29]
    DIRECTION INPUT ;
    USE SIGNAL ;
    PORT
      LAYER M4 ;
        RECT  0 76.176 0.084 76.2 ;
    END
  END weight_ap[29]
  PIN weight_ap[2]
    DIRECTION INPUT ;
    USE SIGNAL ;
    PORT
      LAYER M4 ;
        RECT  0 70.992 0.084 71.016 ;
    END
  END weight_ap[2]
  PIN weight_ap[30]
    DIRECTION INPUT ;
    USE SIGNAL ;
    PORT
      LAYER M4 ;
        RECT  0 76.368 0.084 76.392 ;
    END
  END weight_ap[30]
  PIN weight_ap[31]
    DIRECTION INPUT ;
    USE SIGNAL ;
    PORT
      LAYER M4 ;
        RECT  0 76.56 0.084 76.584 ;
    END
  END weight_ap[31]
  PIN weight_ap[32]
    DIRECTION INPUT ;
    USE SIGNAL ;
    PORT
      LAYER M4 ;
        RECT  0 76.752 0.084 76.776 ;
    END
  END weight_ap[32]
  PIN weight_ap[33]
    DIRECTION INPUT ;
    USE SIGNAL ;
    PORT
      LAYER M4 ;
        RECT  0 76.944 0.084 76.968 ;
    END
  END weight_ap[33]
  PIN weight_ap[34]
    DIRECTION INPUT ;
    USE SIGNAL ;
    PORT
      LAYER M4 ;
        RECT  0 77.136 0.084 77.16 ;
    END
  END weight_ap[34]
  PIN weight_ap[35]
    DIRECTION INPUT ;
    USE SIGNAL ;
    PORT
      LAYER M4 ;
        RECT  0 77.328 0.084 77.352 ;
    END
  END weight_ap[35]
  PIN weight_ap[36]
    DIRECTION INPUT ;
    USE SIGNAL ;
    PORT
      LAYER M4 ;
        RECT  0 77.52 0.084 77.544 ;
    END
  END weight_ap[36]
  PIN weight_ap[37]
    DIRECTION INPUT ;
    USE SIGNAL ;
    PORT
      LAYER M4 ;
        RECT  0 77.712 0.084 77.736 ;
    END
  END weight_ap[37]
  PIN weight_ap[38]
    DIRECTION INPUT ;
    USE SIGNAL ;
    PORT
      LAYER M4 ;
        RECT  0 77.904 0.084 77.928 ;
    END
  END weight_ap[38]
  PIN weight_ap[39]
    DIRECTION INPUT ;
    USE SIGNAL ;
    PORT
      LAYER M4 ;
        RECT  0 78.096 0.084 78.12 ;
    END
  END weight_ap[39]
  PIN weight_ap[3]
    DIRECTION INPUT ;
    USE SIGNAL ;
    PORT
      LAYER M4 ;
        RECT  0 71.184 0.084 71.208 ;
    END
  END weight_ap[3]
  PIN weight_ap[40]
    DIRECTION INPUT ;
    USE SIGNAL ;
    PORT
      LAYER M4 ;
        RECT  0 78.288 0.084 78.312 ;
    END
  END weight_ap[40]
  PIN weight_ap[41]
    DIRECTION INPUT ;
    USE SIGNAL ;
    PORT
      LAYER M4 ;
        RECT  0 78.48 0.084 78.504 ;
    END
  END weight_ap[41]
  PIN weight_ap[42]
    DIRECTION INPUT ;
    USE SIGNAL ;
    PORT
      LAYER M4 ;
        RECT  0 78.672 0.084 78.696 ;
    END
  END weight_ap[42]
  PIN weight_ap[43]
    DIRECTION INPUT ;
    USE SIGNAL ;
    PORT
      LAYER M4 ;
        RECT  0 78.864 0.084 78.888 ;
    END
  END weight_ap[43]
  PIN weight_ap[44]
    DIRECTION INPUT ;
    USE SIGNAL ;
    PORT
      LAYER M4 ;
        RECT  0 79.056 0.084 79.08 ;
    END
  END weight_ap[44]
  PIN weight_ap[45]
    DIRECTION INPUT ;
    USE SIGNAL ;
    PORT
      LAYER M4 ;
        RECT  0 79.248 0.084 79.272 ;
    END
  END weight_ap[45]
  PIN weight_ap[46]
    DIRECTION INPUT ;
    USE SIGNAL ;
    PORT
      LAYER M4 ;
        RECT  0 79.44 0.084 79.464 ;
    END
  END weight_ap[46]
  PIN weight_ap[47]
    DIRECTION INPUT ;
    USE SIGNAL ;
    PORT
      LAYER M4 ;
        RECT  0 79.632 0.084 79.656 ;
    END
  END weight_ap[47]
  PIN weight_ap[48]
    DIRECTION INPUT ;
    USE SIGNAL ;
    PORT
      LAYER M4 ;
        RECT  0 79.824 0.084 79.848 ;
    END
  END weight_ap[48]
  PIN weight_ap[49]
    DIRECTION INPUT ;
    USE SIGNAL ;
    PORT
      LAYER M4 ;
        RECT  0 80.016 0.084 80.04 ;
    END
  END weight_ap[49]
  PIN weight_ap[4]
    DIRECTION INPUT ;
    USE SIGNAL ;
    PORT
      LAYER M4 ;
        RECT  0 71.376 0.084 71.4 ;
    END
  END weight_ap[4]
  PIN weight_ap[50]
    DIRECTION INPUT ;
    USE SIGNAL ;
    PORT
      LAYER M4 ;
        RECT  0 80.208 0.084 80.232 ;
    END
  END weight_ap[50]
  PIN weight_ap[51]
    DIRECTION INPUT ;
    USE SIGNAL ;
    PORT
      LAYER M4 ;
        RECT  0 80.4 0.084 80.424 ;
    END
  END weight_ap[51]
  PIN weight_ap[52]
    DIRECTION INPUT ;
    USE SIGNAL ;
    PORT
      LAYER M4 ;
        RECT  0 80.592 0.084 80.616 ;
    END
  END weight_ap[52]
  PIN weight_ap[53]
    DIRECTION INPUT ;
    USE SIGNAL ;
    PORT
      LAYER M4 ;
        RECT  0 80.784 0.084 80.808 ;
    END
  END weight_ap[53]
  PIN weight_ap[54]
    DIRECTION INPUT ;
    USE SIGNAL ;
    PORT
      LAYER M4 ;
        RECT  0 80.976 0.084 81 ;
    END
  END weight_ap[54]
  PIN weight_ap[55]
    DIRECTION INPUT ;
    USE SIGNAL ;
    PORT
      LAYER M4 ;
        RECT  0 81.168 0.084 81.192 ;
    END
  END weight_ap[55]
  PIN weight_ap[56]
    DIRECTION INPUT ;
    USE SIGNAL ;
    PORT
      LAYER M4 ;
        RECT  0 81.36 0.084 81.384 ;
    END
  END weight_ap[56]
  PIN weight_ap[57]
    DIRECTION INPUT ;
    USE SIGNAL ;
    PORT
      LAYER M4 ;
        RECT  0 81.552 0.084 81.576 ;
    END
  END weight_ap[57]
  PIN weight_ap[58]
    DIRECTION INPUT ;
    USE SIGNAL ;
    PORT
      LAYER M4 ;
        RECT  0 81.744 0.084 81.768 ;
    END
  END weight_ap[58]
  PIN weight_ap[59]
    DIRECTION INPUT ;
    USE SIGNAL ;
    PORT
      LAYER M4 ;
        RECT  0 81.936 0.084 81.96 ;
    END
  END weight_ap[59]
  PIN weight_ap[5]
    DIRECTION INPUT ;
    USE SIGNAL ;
    PORT
      LAYER M4 ;
        RECT  0 71.568 0.084 71.592 ;
    END
  END weight_ap[5]
  PIN weight_ap[60]
    DIRECTION INPUT ;
    USE SIGNAL ;
    PORT
      LAYER M4 ;
        RECT  0 82.128 0.084 82.152 ;
    END
  END weight_ap[60]
  PIN weight_ap[61]
    DIRECTION INPUT ;
    USE SIGNAL ;
    PORT
      LAYER M4 ;
        RECT  0 82.32 0.084 82.344 ;
    END
  END weight_ap[61]
  PIN weight_ap[62]
    DIRECTION INPUT ;
    USE SIGNAL ;
    PORT
      LAYER M4 ;
        RECT  0 82.512 0.084 82.536 ;
    END
  END weight_ap[62]
  PIN weight_ap[63]
    DIRECTION INPUT ;
    USE SIGNAL ;
    PORT
      LAYER M4 ;
        RECT  0 82.704 0.084 82.728 ;
    END
  END weight_ap[63]
  PIN weight_ap[64]
    DIRECTION INPUT ;
    USE SIGNAL ;
    PORT
      LAYER M4 ;
        RECT  0 82.896 0.084 82.92 ;
    END
  END weight_ap[64]
  PIN weight_ap[65]
    DIRECTION INPUT ;
    USE SIGNAL ;
    PORT
      LAYER M4 ;
        RECT  0 83.088 0.084 83.112 ;
    END
  END weight_ap[65]
  PIN weight_ap[66]
    DIRECTION INPUT ;
    USE SIGNAL ;
    PORT
      LAYER M4 ;
        RECT  0 83.28 0.084 83.304 ;
    END
  END weight_ap[66]
  PIN weight_ap[67]
    DIRECTION INPUT ;
    USE SIGNAL ;
    PORT
      LAYER M4 ;
        RECT  0 83.472 0.084 83.496 ;
    END
  END weight_ap[67]
  PIN weight_ap[68]
    DIRECTION INPUT ;
    USE SIGNAL ;
    PORT
      LAYER M4 ;
        RECT  0 83.664 0.084 83.688 ;
    END
  END weight_ap[68]
  PIN weight_ap[69]
    DIRECTION INPUT ;
    USE SIGNAL ;
    PORT
      LAYER M4 ;
        RECT  0 83.856 0.084 83.88 ;
    END
  END weight_ap[69]
  PIN weight_ap[6]
    DIRECTION INPUT ;
    USE SIGNAL ;
    PORT
      LAYER M4 ;
        RECT  0 71.76 0.084 71.784 ;
    END
  END weight_ap[6]
  PIN weight_ap[70]
    DIRECTION INPUT ;
    USE SIGNAL ;
    PORT
      LAYER M4 ;
        RECT  0 84.048 0.084 84.072 ;
    END
  END weight_ap[70]
  PIN weight_ap[71]
    DIRECTION INPUT ;
    USE SIGNAL ;
    PORT
      LAYER M4 ;
        RECT  0 84.24 0.084 84.264 ;
    END
  END weight_ap[71]
  PIN weight_ap[72]
    DIRECTION INPUT ;
    USE SIGNAL ;
    PORT
      LAYER M4 ;
        RECT  0 84.432 0.084 84.456 ;
    END
  END weight_ap[72]
  PIN weight_ap[73]
    DIRECTION INPUT ;
    USE SIGNAL ;
    PORT
      LAYER M4 ;
        RECT  0 84.624 0.084 84.648 ;
    END
  END weight_ap[73]
  PIN weight_ap[74]
    DIRECTION INPUT ;
    USE SIGNAL ;
    PORT
      LAYER M4 ;
        RECT  0 84.816 0.084 84.84 ;
    END
  END weight_ap[74]
  PIN weight_ap[75]
    DIRECTION INPUT ;
    USE SIGNAL ;
    PORT
      LAYER M4 ;
        RECT  0 85.008 0.084 85.032 ;
    END
  END weight_ap[75]
  PIN weight_ap[76]
    DIRECTION INPUT ;
    USE SIGNAL ;
    PORT
      LAYER M4 ;
        RECT  0 85.2 0.084 85.224 ;
    END
  END weight_ap[76]
  PIN weight_ap[77]
    DIRECTION INPUT ;
    USE SIGNAL ;
    PORT
      LAYER M4 ;
        RECT  0 85.392 0.084 85.416 ;
    END
  END weight_ap[77]
  PIN weight_ap[78]
    DIRECTION INPUT ;
    USE SIGNAL ;
    PORT
      LAYER M4 ;
        RECT  0 85.584 0.084 85.608 ;
    END
  END weight_ap[78]
  PIN weight_ap[79]
    DIRECTION INPUT ;
    USE SIGNAL ;
    PORT
      LAYER M4 ;
        RECT  0 85.776 0.084 85.8 ;
    END
  END weight_ap[79]
  PIN weight_ap[7]
    DIRECTION INPUT ;
    USE SIGNAL ;
    PORT
      LAYER M4 ;
        RECT  0 71.952 0.084 71.976 ;
    END
  END weight_ap[7]
  PIN weight_ap[80]
    DIRECTION INPUT ;
    USE SIGNAL ;
    PORT
      LAYER M4 ;
        RECT  0 85.968 0.084 85.992 ;
    END
  END weight_ap[80]
  PIN weight_ap[81]
    DIRECTION INPUT ;
    USE SIGNAL ;
    PORT
      LAYER M4 ;
        RECT  0 86.16 0.084 86.184 ;
    END
  END weight_ap[81]
  PIN weight_ap[82]
    DIRECTION INPUT ;
    USE SIGNAL ;
    PORT
      LAYER M4 ;
        RECT  0 86.352 0.084 86.376 ;
    END
  END weight_ap[82]
  PIN weight_ap[83]
    DIRECTION INPUT ;
    USE SIGNAL ;
    PORT
      LAYER M4 ;
        RECT  0 86.544 0.084 86.568 ;
    END
  END weight_ap[83]
  PIN weight_ap[84]
    DIRECTION INPUT ;
    USE SIGNAL ;
    PORT
      LAYER M4 ;
        RECT  0 86.736 0.084 86.76 ;
    END
  END weight_ap[84]
  PIN weight_ap[85]
    DIRECTION INPUT ;
    USE SIGNAL ;
    PORT
      LAYER M4 ;
        RECT  0 86.928 0.084 86.952 ;
    END
  END weight_ap[85]
  PIN weight_ap[86]
    DIRECTION INPUT ;
    USE SIGNAL ;
    PORT
      LAYER M4 ;
        RECT  0 87.12 0.084 87.144 ;
    END
  END weight_ap[86]
  PIN weight_ap[87]
    DIRECTION INPUT ;
    USE SIGNAL ;
    PORT
      LAYER M4 ;
        RECT  0 87.312 0.084 87.336 ;
    END
  END weight_ap[87]
  PIN weight_ap[88]
    DIRECTION INPUT ;
    USE SIGNAL ;
    PORT
      LAYER M4 ;
        RECT  0 87.504 0.084 87.528 ;
    END
  END weight_ap[88]
  PIN weight_ap[89]
    DIRECTION INPUT ;
    USE SIGNAL ;
    PORT
      LAYER M4 ;
        RECT  0 87.696 0.084 87.72 ;
    END
  END weight_ap[89]
  PIN weight_ap[8]
    DIRECTION INPUT ;
    USE SIGNAL ;
    PORT
      LAYER M4 ;
        RECT  0 72.144 0.084 72.168 ;
    END
  END weight_ap[8]
  PIN weight_ap[90]
    DIRECTION INPUT ;
    USE SIGNAL ;
    PORT
      LAYER M4 ;
        RECT  0 87.888 0.084 87.912 ;
    END
  END weight_ap[90]
  PIN weight_ap[91]
    DIRECTION INPUT ;
    USE SIGNAL ;
    PORT
      LAYER M4 ;
        RECT  0 88.08 0.084 88.104 ;
    END
  END weight_ap[91]
  PIN weight_ap[92]
    DIRECTION INPUT ;
    USE SIGNAL ;
    PORT
      LAYER M4 ;
        RECT  0 88.272 0.084 88.296 ;
    END
  END weight_ap[92]
  PIN weight_ap[93]
    DIRECTION INPUT ;
    USE SIGNAL ;
    PORT
      LAYER M4 ;
        RECT  0 88.464 0.084 88.488 ;
    END
  END weight_ap[93]
  PIN weight_ap[94]
    DIRECTION INPUT ;
    USE SIGNAL ;
    PORT
      LAYER M4 ;
        RECT  0 88.656 0.084 88.68 ;
    END
  END weight_ap[94]
  PIN weight_ap[95]
    DIRECTION INPUT ;
    USE SIGNAL ;
    PORT
      LAYER M4 ;
        RECT  0 88.848 0.084 88.872 ;
    END
  END weight_ap[95]
  PIN weight_ap[96]
    DIRECTION INPUT ;
    USE SIGNAL ;
    PORT
      LAYER M4 ;
        RECT  0 89.04 0.084 89.064 ;
    END
  END weight_ap[96]
  PIN weight_ap[97]
    DIRECTION INPUT ;
    USE SIGNAL ;
    PORT
      LAYER M4 ;
        RECT  0 89.232 0.084 89.256 ;
    END
  END weight_ap[97]
  PIN weight_ap[98]
    DIRECTION INPUT ;
    USE SIGNAL ;
    PORT
      LAYER M4 ;
        RECT  0 89.424 0.084 89.448 ;
    END
  END weight_ap[98]
  PIN weight_ap[99]
    DIRECTION INPUT ;
    USE SIGNAL ;
    PORT
      LAYER M4 ;
        RECT  0 89.616 0.084 89.64 ;
    END
  END weight_ap[99]
  PIN weight_ap[9]
    DIRECTION INPUT ;
    USE SIGNAL ;
    PORT
      LAYER M4 ;
        RECT  0 72.336 0.084 72.36 ;
    END
  END weight_ap[9]
  PIN weight_data[0]
    DIRECTION OUTPUT ;
    USE SIGNAL ;
    PORT
      LAYER M4 ;
        RECT  204.252 72.432 204.336 72.456 ;
    END
  END weight_data[0]
  PIN weight_data[100]
    DIRECTION OUTPUT ;
    USE SIGNAL ;
    PORT
      LAYER M4 ;
        RECT  204.252 91.632 204.336 91.656 ;
    END
  END weight_data[100]
  PIN weight_data[101]
    DIRECTION OUTPUT ;
    USE SIGNAL ;
    PORT
      LAYER M4 ;
        RECT  204.252 91.824 204.336 91.848 ;
    END
  END weight_data[101]
  PIN weight_data[102]
    DIRECTION OUTPUT ;
    USE SIGNAL ;
    PORT
      LAYER M4 ;
        RECT  204.252 92.016 204.336 92.04 ;
    END
  END weight_data[102]
  PIN weight_data[103]
    DIRECTION OUTPUT ;
    USE SIGNAL ;
    PORT
      LAYER M4 ;
        RECT  204.252 92.208 204.336 92.232 ;
    END
  END weight_data[103]
  PIN weight_data[104]
    DIRECTION OUTPUT ;
    USE SIGNAL ;
    PORT
      LAYER M4 ;
        RECT  204.252 92.4 204.336 92.424 ;
    END
  END weight_data[104]
  PIN weight_data[105]
    DIRECTION OUTPUT ;
    USE SIGNAL ;
    PORT
      LAYER M4 ;
        RECT  204.252 92.592 204.336 92.616 ;
    END
  END weight_data[105]
  PIN weight_data[106]
    DIRECTION OUTPUT ;
    USE SIGNAL ;
    PORT
      LAYER M4 ;
        RECT  204.252 92.784 204.336 92.808 ;
    END
  END weight_data[106]
  PIN weight_data[107]
    DIRECTION OUTPUT ;
    USE SIGNAL ;
    PORT
      LAYER M4 ;
        RECT  204.252 92.976 204.336 93 ;
    END
  END weight_data[107]
  PIN weight_data[108]
    DIRECTION OUTPUT ;
    USE SIGNAL ;
    PORT
      LAYER M4 ;
        RECT  204.252 93.168 204.336 93.192 ;
    END
  END weight_data[108]
  PIN weight_data[109]
    DIRECTION OUTPUT ;
    USE SIGNAL ;
    PORT
      LAYER M4 ;
        RECT  204.252 93.36 204.336 93.384 ;
    END
  END weight_data[109]
  PIN weight_data[10]
    DIRECTION OUTPUT ;
    USE SIGNAL ;
    PORT
      LAYER M4 ;
        RECT  204.252 74.352 204.336 74.376 ;
    END
  END weight_data[10]
  PIN weight_data[110]
    DIRECTION OUTPUT ;
    USE SIGNAL ;
    PORT
      LAYER M4 ;
        RECT  204.252 93.552 204.336 93.576 ;
    END
  END weight_data[110]
  PIN weight_data[111]
    DIRECTION OUTPUT ;
    USE SIGNAL ;
    PORT
      LAYER M4 ;
        RECT  204.252 93.744 204.336 93.768 ;
    END
  END weight_data[111]
  PIN weight_data[112]
    DIRECTION OUTPUT ;
    USE SIGNAL ;
    PORT
      LAYER M4 ;
        RECT  204.252 93.936 204.336 93.96 ;
    END
  END weight_data[112]
  PIN weight_data[113]
    DIRECTION OUTPUT ;
    USE SIGNAL ;
    PORT
      LAYER M4 ;
        RECT  204.252 94.128 204.336 94.152 ;
    END
  END weight_data[113]
  PIN weight_data[114]
    DIRECTION OUTPUT ;
    USE SIGNAL ;
    PORT
      LAYER M4 ;
        RECT  204.252 94.32 204.336 94.344 ;
    END
  END weight_data[114]
  PIN weight_data[115]
    DIRECTION OUTPUT ;
    USE SIGNAL ;
    PORT
      LAYER M4 ;
        RECT  204.252 94.512 204.336 94.536 ;
    END
  END weight_data[115]
  PIN weight_data[116]
    DIRECTION OUTPUT ;
    USE SIGNAL ;
    PORT
      LAYER M4 ;
        RECT  204.252 94.704 204.336 94.728 ;
    END
  END weight_data[116]
  PIN weight_data[117]
    DIRECTION OUTPUT ;
    USE SIGNAL ;
    PORT
      LAYER M4 ;
        RECT  204.252 94.896 204.336 94.92 ;
    END
  END weight_data[117]
  PIN weight_data[118]
    DIRECTION OUTPUT ;
    USE SIGNAL ;
    PORT
      LAYER M4 ;
        RECT  204.252 95.088 204.336 95.112 ;
    END
  END weight_data[118]
  PIN weight_data[119]
    DIRECTION OUTPUT ;
    USE SIGNAL ;
    PORT
      LAYER M4 ;
        RECT  204.252 95.28 204.336 95.304 ;
    END
  END weight_data[119]
  PIN weight_data[11]
    DIRECTION OUTPUT ;
    USE SIGNAL ;
    PORT
      LAYER M4 ;
        RECT  204.252 74.544 204.336 74.568 ;
    END
  END weight_data[11]
  PIN weight_data[120]
    DIRECTION OUTPUT ;
    USE SIGNAL ;
    PORT
      LAYER M4 ;
        RECT  204.252 95.472 204.336 95.496 ;
    END
  END weight_data[120]
  PIN weight_data[121]
    DIRECTION OUTPUT ;
    USE SIGNAL ;
    PORT
      LAYER M4 ;
        RECT  204.252 95.664 204.336 95.688 ;
    END
  END weight_data[121]
  PIN weight_data[122]
    DIRECTION OUTPUT ;
    USE SIGNAL ;
    PORT
      LAYER M4 ;
        RECT  204.252 95.856 204.336 95.88 ;
    END
  END weight_data[122]
  PIN weight_data[123]
    DIRECTION OUTPUT ;
    USE SIGNAL ;
    PORT
      LAYER M4 ;
        RECT  204.252 96.048 204.336 96.072 ;
    END
  END weight_data[123]
  PIN weight_data[124]
    DIRECTION OUTPUT ;
    USE SIGNAL ;
    PORT
      LAYER M4 ;
        RECT  204.252 96.24 204.336 96.264 ;
    END
  END weight_data[124]
  PIN weight_data[125]
    DIRECTION OUTPUT ;
    USE SIGNAL ;
    PORT
      LAYER M4 ;
        RECT  204.252 96.432 204.336 96.456 ;
    END
  END weight_data[125]
  PIN weight_data[126]
    DIRECTION OUTPUT ;
    USE SIGNAL ;
    PORT
      LAYER M4 ;
        RECT  204.252 96.624 204.336 96.648 ;
    END
  END weight_data[126]
  PIN weight_data[127]
    DIRECTION OUTPUT ;
    USE SIGNAL ;
    PORT
      LAYER M4 ;
        RECT  204.252 96.816 204.336 96.84 ;
    END
  END weight_data[127]
  PIN weight_data[128]
    DIRECTION OUTPUT ;
    USE SIGNAL ;
    PORT
      LAYER M4 ;
        RECT  204.252 97.008 204.336 97.032 ;
    END
  END weight_data[128]
  PIN weight_data[129]
    DIRECTION OUTPUT ;
    USE SIGNAL ;
    PORT
      LAYER M4 ;
        RECT  204.252 97.2 204.336 97.224 ;
    END
  END weight_data[129]
  PIN weight_data[12]
    DIRECTION OUTPUT ;
    USE SIGNAL ;
    PORT
      LAYER M4 ;
        RECT  204.252 74.736 204.336 74.76 ;
    END
  END weight_data[12]
  PIN weight_data[130]
    DIRECTION OUTPUT ;
    USE SIGNAL ;
    PORT
      LAYER M4 ;
        RECT  204.252 97.392 204.336 97.416 ;
    END
  END weight_data[130]
  PIN weight_data[131]
    DIRECTION OUTPUT ;
    USE SIGNAL ;
    PORT
      LAYER M4 ;
        RECT  204.252 97.584 204.336 97.608 ;
    END
  END weight_data[131]
  PIN weight_data[132]
    DIRECTION OUTPUT ;
    USE SIGNAL ;
    PORT
      LAYER M4 ;
        RECT  204.252 97.776 204.336 97.8 ;
    END
  END weight_data[132]
  PIN weight_data[133]
    DIRECTION OUTPUT ;
    USE SIGNAL ;
    PORT
      LAYER M4 ;
        RECT  204.252 97.968 204.336 97.992 ;
    END
  END weight_data[133]
  PIN weight_data[134]
    DIRECTION OUTPUT ;
    USE SIGNAL ;
    PORT
      LAYER M4 ;
        RECT  204.252 98.16 204.336 98.184 ;
    END
  END weight_data[134]
  PIN weight_data[135]
    DIRECTION OUTPUT ;
    USE SIGNAL ;
    PORT
      LAYER M4 ;
        RECT  204.252 98.352 204.336 98.376 ;
    END
  END weight_data[135]
  PIN weight_data[136]
    DIRECTION OUTPUT ;
    USE SIGNAL ;
    PORT
      LAYER M4 ;
        RECT  204.252 98.544 204.336 98.568 ;
    END
  END weight_data[136]
  PIN weight_data[137]
    DIRECTION OUTPUT ;
    USE SIGNAL ;
    PORT
      LAYER M4 ;
        RECT  204.252 98.736 204.336 98.76 ;
    END
  END weight_data[137]
  PIN weight_data[138]
    DIRECTION OUTPUT ;
    USE SIGNAL ;
    PORT
      LAYER M4 ;
        RECT  204.252 98.928 204.336 98.952 ;
    END
  END weight_data[138]
  PIN weight_data[139]
    DIRECTION OUTPUT ;
    USE SIGNAL ;
    PORT
      LAYER M4 ;
        RECT  204.252 99.12 204.336 99.144 ;
    END
  END weight_data[139]
  PIN weight_data[13]
    DIRECTION OUTPUT ;
    USE SIGNAL ;
    PORT
      LAYER M4 ;
        RECT  204.252 74.928 204.336 74.952 ;
    END
  END weight_data[13]
  PIN weight_data[140]
    DIRECTION OUTPUT ;
    USE SIGNAL ;
    PORT
      LAYER M4 ;
        RECT  204.252 99.312 204.336 99.336 ;
    END
  END weight_data[140]
  PIN weight_data[141]
    DIRECTION OUTPUT ;
    USE SIGNAL ;
    PORT
      LAYER M4 ;
        RECT  204.252 99.504 204.336 99.528 ;
    END
  END weight_data[141]
  PIN weight_data[142]
    DIRECTION OUTPUT ;
    USE SIGNAL ;
    PORT
      LAYER M4 ;
        RECT  204.252 99.696 204.336 99.72 ;
    END
  END weight_data[142]
  PIN weight_data[143]
    DIRECTION OUTPUT ;
    USE SIGNAL ;
    PORT
      LAYER M4 ;
        RECT  204.252 99.888 204.336 99.912 ;
    END
  END weight_data[143]
  PIN weight_data[144]
    DIRECTION OUTPUT ;
    USE SIGNAL ;
    PORT
      LAYER M4 ;
        RECT  204.252 100.08 204.336 100.104 ;
    END
  END weight_data[144]
  PIN weight_data[145]
    DIRECTION OUTPUT ;
    USE SIGNAL ;
    PORT
      LAYER M4 ;
        RECT  204.252 100.272 204.336 100.296 ;
    END
  END weight_data[145]
  PIN weight_data[146]
    DIRECTION OUTPUT ;
    USE SIGNAL ;
    PORT
      LAYER M4 ;
        RECT  204.252 100.464 204.336 100.488 ;
    END
  END weight_data[146]
  PIN weight_data[147]
    DIRECTION OUTPUT ;
    USE SIGNAL ;
    PORT
      LAYER M4 ;
        RECT  204.252 100.656 204.336 100.68 ;
    END
  END weight_data[147]
  PIN weight_data[148]
    DIRECTION OUTPUT ;
    USE SIGNAL ;
    PORT
      LAYER M4 ;
        RECT  204.252 100.848 204.336 100.872 ;
    END
  END weight_data[148]
  PIN weight_data[149]
    DIRECTION OUTPUT ;
    USE SIGNAL ;
    PORT
      LAYER M4 ;
        RECT  204.252 101.04 204.336 101.064 ;
    END
  END weight_data[149]
  PIN weight_data[14]
    DIRECTION OUTPUT ;
    USE SIGNAL ;
    PORT
      LAYER M4 ;
        RECT  204.252 75.12 204.336 75.144 ;
    END
  END weight_data[14]
  PIN weight_data[150]
    DIRECTION OUTPUT ;
    USE SIGNAL ;
    PORT
      LAYER M4 ;
        RECT  204.252 101.232 204.336 101.256 ;
    END
  END weight_data[150]
  PIN weight_data[151]
    DIRECTION OUTPUT ;
    USE SIGNAL ;
    PORT
      LAYER M4 ;
        RECT  204.252 101.424 204.336 101.448 ;
    END
  END weight_data[151]
  PIN weight_data[152]
    DIRECTION OUTPUT ;
    USE SIGNAL ;
    PORT
      LAYER M4 ;
        RECT  204.252 101.616 204.336 101.64 ;
    END
  END weight_data[152]
  PIN weight_data[153]
    DIRECTION OUTPUT ;
    USE SIGNAL ;
    PORT
      LAYER M4 ;
        RECT  204.252 101.808 204.336 101.832 ;
    END
  END weight_data[153]
  PIN weight_data[154]
    DIRECTION OUTPUT ;
    USE SIGNAL ;
    PORT
      LAYER M4 ;
        RECT  204.252 102 204.336 102.024 ;
    END
  END weight_data[154]
  PIN weight_data[155]
    DIRECTION OUTPUT ;
    USE SIGNAL ;
    PORT
      LAYER M4 ;
        RECT  204.252 102.192 204.336 102.216 ;
    END
  END weight_data[155]
  PIN weight_data[156]
    DIRECTION OUTPUT ;
    USE SIGNAL ;
    PORT
      LAYER M4 ;
        RECT  204.252 102.384 204.336 102.408 ;
    END
  END weight_data[156]
  PIN weight_data[157]
    DIRECTION OUTPUT ;
    USE SIGNAL ;
    PORT
      LAYER M4 ;
        RECT  204.252 102.576 204.336 102.6 ;
    END
  END weight_data[157]
  PIN weight_data[158]
    DIRECTION OUTPUT ;
    USE SIGNAL ;
    PORT
      LAYER M4 ;
        RECT  204.252 102.768 204.336 102.792 ;
    END
  END weight_data[158]
  PIN weight_data[159]
    DIRECTION OUTPUT ;
    USE SIGNAL ;
    PORT
      LAYER M4 ;
        RECT  204.252 102.96 204.336 102.984 ;
    END
  END weight_data[159]
  PIN weight_data[15]
    DIRECTION OUTPUT ;
    USE SIGNAL ;
    PORT
      LAYER M4 ;
        RECT  204.252 75.312 204.336 75.336 ;
    END
  END weight_data[15]
  PIN weight_data[160]
    DIRECTION OUTPUT ;
    USE SIGNAL ;
    PORT
      LAYER M4 ;
        RECT  204.252 103.152 204.336 103.176 ;
    END
  END weight_data[160]
  PIN weight_data[161]
    DIRECTION OUTPUT ;
    USE SIGNAL ;
    PORT
      LAYER M4 ;
        RECT  204.252 103.344 204.336 103.368 ;
    END
  END weight_data[161]
  PIN weight_data[162]
    DIRECTION OUTPUT ;
    USE SIGNAL ;
    PORT
      LAYER M4 ;
        RECT  204.252 103.536 204.336 103.56 ;
    END
  END weight_data[162]
  PIN weight_data[163]
    DIRECTION OUTPUT ;
    USE SIGNAL ;
    PORT
      LAYER M4 ;
        RECT  204.252 103.728 204.336 103.752 ;
    END
  END weight_data[163]
  PIN weight_data[164]
    DIRECTION OUTPUT ;
    USE SIGNAL ;
    PORT
      LAYER M4 ;
        RECT  204.252 103.92 204.336 103.944 ;
    END
  END weight_data[164]
  PIN weight_data[165]
    DIRECTION OUTPUT ;
    USE SIGNAL ;
    PORT
      LAYER M4 ;
        RECT  204.252 104.112 204.336 104.136 ;
    END
  END weight_data[165]
  PIN weight_data[166]
    DIRECTION OUTPUT ;
    USE SIGNAL ;
    PORT
      LAYER M4 ;
        RECT  204.252 104.304 204.336 104.328 ;
    END
  END weight_data[166]
  PIN weight_data[167]
    DIRECTION OUTPUT ;
    USE SIGNAL ;
    PORT
      LAYER M4 ;
        RECT  204.252 104.496 204.336 104.52 ;
    END
  END weight_data[167]
  PIN weight_data[168]
    DIRECTION OUTPUT ;
    USE SIGNAL ;
    PORT
      LAYER M4 ;
        RECT  204.252 104.688 204.336 104.712 ;
    END
  END weight_data[168]
  PIN weight_data[169]
    DIRECTION OUTPUT ;
    USE SIGNAL ;
    PORT
      LAYER M4 ;
        RECT  204.252 104.88 204.336 104.904 ;
    END
  END weight_data[169]
  PIN weight_data[16]
    DIRECTION OUTPUT ;
    USE SIGNAL ;
    PORT
      LAYER M4 ;
        RECT  204.252 75.504 204.336 75.528 ;
    END
  END weight_data[16]
  PIN weight_data[170]
    DIRECTION OUTPUT ;
    USE SIGNAL ;
    PORT
      LAYER M4 ;
        RECT  204.252 105.072 204.336 105.096 ;
    END
  END weight_data[170]
  PIN weight_data[171]
    DIRECTION OUTPUT ;
    USE SIGNAL ;
    PORT
      LAYER M4 ;
        RECT  204.252 105.264 204.336 105.288 ;
    END
  END weight_data[171]
  PIN weight_data[172]
    DIRECTION OUTPUT ;
    USE SIGNAL ;
    PORT
      LAYER M4 ;
        RECT  204.252 105.456 204.336 105.48 ;
    END
  END weight_data[172]
  PIN weight_data[173]
    DIRECTION OUTPUT ;
    USE SIGNAL ;
    PORT
      LAYER M4 ;
        RECT  204.252 105.648 204.336 105.672 ;
    END
  END weight_data[173]
  PIN weight_data[174]
    DIRECTION OUTPUT ;
    USE SIGNAL ;
    PORT
      LAYER M4 ;
        RECT  204.252 105.84 204.336 105.864 ;
    END
  END weight_data[174]
  PIN weight_data[175]
    DIRECTION OUTPUT ;
    USE SIGNAL ;
    PORT
      LAYER M4 ;
        RECT  204.252 106.032 204.336 106.056 ;
    END
  END weight_data[175]
  PIN weight_data[176]
    DIRECTION OUTPUT ;
    USE SIGNAL ;
    PORT
      LAYER M4 ;
        RECT  204.252 106.224 204.336 106.248 ;
    END
  END weight_data[176]
  PIN weight_data[177]
    DIRECTION OUTPUT ;
    USE SIGNAL ;
    PORT
      LAYER M4 ;
        RECT  204.252 106.416 204.336 106.44 ;
    END
  END weight_data[177]
  PIN weight_data[178]
    DIRECTION OUTPUT ;
    USE SIGNAL ;
    PORT
      LAYER M4 ;
        RECT  204.252 106.608 204.336 106.632 ;
    END
  END weight_data[178]
  PIN weight_data[179]
    DIRECTION OUTPUT ;
    USE SIGNAL ;
    PORT
      LAYER M4 ;
        RECT  204.252 106.8 204.336 106.824 ;
    END
  END weight_data[179]
  PIN weight_data[17]
    DIRECTION OUTPUT ;
    USE SIGNAL ;
    PORT
      LAYER M4 ;
        RECT  204.252 75.696 204.336 75.72 ;
    END
  END weight_data[17]
  PIN weight_data[180]
    DIRECTION OUTPUT ;
    USE SIGNAL ;
    PORT
      LAYER M4 ;
        RECT  204.252 106.992 204.336 107.016 ;
    END
  END weight_data[180]
  PIN weight_data[181]
    DIRECTION OUTPUT ;
    USE SIGNAL ;
    PORT
      LAYER M4 ;
        RECT  204.252 107.184 204.336 107.208 ;
    END
  END weight_data[181]
  PIN weight_data[182]
    DIRECTION OUTPUT ;
    USE SIGNAL ;
    PORT
      LAYER M4 ;
        RECT  204.252 107.376 204.336 107.4 ;
    END
  END weight_data[182]
  PIN weight_data[183]
    DIRECTION OUTPUT ;
    USE SIGNAL ;
    PORT
      LAYER M4 ;
        RECT  204.252 107.568 204.336 107.592 ;
    END
  END weight_data[183]
  PIN weight_data[184]
    DIRECTION OUTPUT ;
    USE SIGNAL ;
    PORT
      LAYER M4 ;
        RECT  204.252 107.76 204.336 107.784 ;
    END
  END weight_data[184]
  PIN weight_data[185]
    DIRECTION OUTPUT ;
    USE SIGNAL ;
    PORT
      LAYER M4 ;
        RECT  204.252 107.952 204.336 107.976 ;
    END
  END weight_data[185]
  PIN weight_data[186]
    DIRECTION OUTPUT ;
    USE SIGNAL ;
    PORT
      LAYER M4 ;
        RECT  204.252 108.144 204.336 108.168 ;
    END
  END weight_data[186]
  PIN weight_data[187]
    DIRECTION OUTPUT ;
    USE SIGNAL ;
    PORT
      LAYER M4 ;
        RECT  204.252 108.336 204.336 108.36 ;
    END
  END weight_data[187]
  PIN weight_data[188]
    DIRECTION OUTPUT ;
    USE SIGNAL ;
    PORT
      LAYER M4 ;
        RECT  204.252 108.528 204.336 108.552 ;
    END
  END weight_data[188]
  PIN weight_data[189]
    DIRECTION OUTPUT ;
    USE SIGNAL ;
    PORT
      LAYER M4 ;
        RECT  204.252 108.72 204.336 108.744 ;
    END
  END weight_data[189]
  PIN weight_data[18]
    DIRECTION OUTPUT ;
    USE SIGNAL ;
    PORT
      LAYER M4 ;
        RECT  204.252 75.888 204.336 75.912 ;
    END
  END weight_data[18]
  PIN weight_data[190]
    DIRECTION OUTPUT ;
    USE SIGNAL ;
    PORT
      LAYER M4 ;
        RECT  204.252 108.912 204.336 108.936 ;
    END
  END weight_data[190]
  PIN weight_data[191]
    DIRECTION OUTPUT ;
    USE SIGNAL ;
    PORT
      LAYER M4 ;
        RECT  204.252 109.104 204.336 109.128 ;
    END
  END weight_data[191]
  PIN weight_data[192]
    DIRECTION OUTPUT ;
    USE SIGNAL ;
    PORT
      LAYER M4 ;
        RECT  204.252 109.296 204.336 109.32 ;
    END
  END weight_data[192]
  PIN weight_data[193]
    DIRECTION OUTPUT ;
    USE SIGNAL ;
    PORT
      LAYER M4 ;
        RECT  204.252 109.488 204.336 109.512 ;
    END
  END weight_data[193]
  PIN weight_data[194]
    DIRECTION OUTPUT ;
    USE SIGNAL ;
    PORT
      LAYER M4 ;
        RECT  204.252 109.68 204.336 109.704 ;
    END
  END weight_data[194]
  PIN weight_data[195]
    DIRECTION OUTPUT ;
    USE SIGNAL ;
    PORT
      LAYER M4 ;
        RECT  204.252 109.872 204.336 109.896 ;
    END
  END weight_data[195]
  PIN weight_data[196]
    DIRECTION OUTPUT ;
    USE SIGNAL ;
    PORT
      LAYER M4 ;
        RECT  204.252 110.064 204.336 110.088 ;
    END
  END weight_data[196]
  PIN weight_data[197]
    DIRECTION OUTPUT ;
    USE SIGNAL ;
    PORT
      LAYER M4 ;
        RECT  204.252 110.256 204.336 110.28 ;
    END
  END weight_data[197]
  PIN weight_data[198]
    DIRECTION OUTPUT ;
    USE SIGNAL ;
    PORT
      LAYER M4 ;
        RECT  204.252 110.448 204.336 110.472 ;
    END
  END weight_data[198]
  PIN weight_data[199]
    DIRECTION OUTPUT ;
    USE SIGNAL ;
    PORT
      LAYER M4 ;
        RECT  204.252 110.64 204.336 110.664 ;
    END
  END weight_data[199]
  PIN weight_data[19]
    DIRECTION OUTPUT ;
    USE SIGNAL ;
    PORT
      LAYER M4 ;
        RECT  204.252 76.08 204.336 76.104 ;
    END
  END weight_data[19]
  PIN weight_data[1]
    DIRECTION OUTPUT ;
    USE SIGNAL ;
    PORT
      LAYER M4 ;
        RECT  204.252 72.624 204.336 72.648 ;
    END
  END weight_data[1]
  PIN weight_data[200]
    DIRECTION OUTPUT ;
    USE SIGNAL ;
    PORT
      LAYER M4 ;
        RECT  204.252 110.832 204.336 110.856 ;
    END
  END weight_data[200]
  PIN weight_data[201]
    DIRECTION OUTPUT ;
    USE SIGNAL ;
    PORT
      LAYER M4 ;
        RECT  204.252 111.024 204.336 111.048 ;
    END
  END weight_data[201]
  PIN weight_data[202]
    DIRECTION OUTPUT ;
    USE SIGNAL ;
    PORT
      LAYER M4 ;
        RECT  204.252 111.216 204.336 111.24 ;
    END
  END weight_data[202]
  PIN weight_data[203]
    DIRECTION OUTPUT ;
    USE SIGNAL ;
    PORT
      LAYER M4 ;
        RECT  204.252 111.408 204.336 111.432 ;
    END
  END weight_data[203]
  PIN weight_data[204]
    DIRECTION OUTPUT ;
    USE SIGNAL ;
    PORT
      LAYER M4 ;
        RECT  204.252 111.6 204.336 111.624 ;
    END
  END weight_data[204]
  PIN weight_data[205]
    DIRECTION OUTPUT ;
    USE SIGNAL ;
    PORT
      LAYER M4 ;
        RECT  204.252 111.792 204.336 111.816 ;
    END
  END weight_data[205]
  PIN weight_data[206]
    DIRECTION OUTPUT ;
    USE SIGNAL ;
    PORT
      LAYER M4 ;
        RECT  204.252 111.984 204.336 112.008 ;
    END
  END weight_data[206]
  PIN weight_data[207]
    DIRECTION OUTPUT ;
    USE SIGNAL ;
    PORT
      LAYER M4 ;
        RECT  204.252 112.176 204.336 112.2 ;
    END
  END weight_data[207]
  PIN weight_data[208]
    DIRECTION OUTPUT ;
    USE SIGNAL ;
    PORT
      LAYER M4 ;
        RECT  204.252 112.368 204.336 112.392 ;
    END
  END weight_data[208]
  PIN weight_data[209]
    DIRECTION OUTPUT ;
    USE SIGNAL ;
    PORT
      LAYER M4 ;
        RECT  204.252 112.56 204.336 112.584 ;
    END
  END weight_data[209]
  PIN weight_data[20]
    DIRECTION OUTPUT ;
    USE SIGNAL ;
    PORT
      LAYER M4 ;
        RECT  204.252 76.272 204.336 76.296 ;
    END
  END weight_data[20]
  PIN weight_data[210]
    DIRECTION OUTPUT ;
    USE SIGNAL ;
    PORT
      LAYER M4 ;
        RECT  204.252 112.752 204.336 112.776 ;
    END
  END weight_data[210]
  PIN weight_data[211]
    DIRECTION OUTPUT ;
    USE SIGNAL ;
    PORT
      LAYER M4 ;
        RECT  204.252 112.944 204.336 112.968 ;
    END
  END weight_data[211]
  PIN weight_data[212]
    DIRECTION OUTPUT ;
    USE SIGNAL ;
    PORT
      LAYER M4 ;
        RECT  204.252 113.136 204.336 113.16 ;
    END
  END weight_data[212]
  PIN weight_data[213]
    DIRECTION OUTPUT ;
    USE SIGNAL ;
    PORT
      LAYER M4 ;
        RECT  204.252 113.328 204.336 113.352 ;
    END
  END weight_data[213]
  PIN weight_data[214]
    DIRECTION OUTPUT ;
    USE SIGNAL ;
    PORT
      LAYER M4 ;
        RECT  204.252 113.52 204.336 113.544 ;
    END
  END weight_data[214]
  PIN weight_data[215]
    DIRECTION OUTPUT ;
    USE SIGNAL ;
    PORT
      LAYER M4 ;
        RECT  204.252 113.712 204.336 113.736 ;
    END
  END weight_data[215]
  PIN weight_data[216]
    DIRECTION OUTPUT ;
    USE SIGNAL ;
    PORT
      LAYER M4 ;
        RECT  204.252 113.904 204.336 113.928 ;
    END
  END weight_data[216]
  PIN weight_data[217]
    DIRECTION OUTPUT ;
    USE SIGNAL ;
    PORT
      LAYER M4 ;
        RECT  204.252 114.096 204.336 114.12 ;
    END
  END weight_data[217]
  PIN weight_data[218]
    DIRECTION OUTPUT ;
    USE SIGNAL ;
    PORT
      LAYER M4 ;
        RECT  204.252 114.288 204.336 114.312 ;
    END
  END weight_data[218]
  PIN weight_data[219]
    DIRECTION OUTPUT ;
    USE SIGNAL ;
    PORT
      LAYER M4 ;
        RECT  204.252 114.48 204.336 114.504 ;
    END
  END weight_data[219]
  PIN weight_data[21]
    DIRECTION OUTPUT ;
    USE SIGNAL ;
    PORT
      LAYER M4 ;
        RECT  204.252 76.464 204.336 76.488 ;
    END
  END weight_data[21]
  PIN weight_data[220]
    DIRECTION OUTPUT ;
    USE SIGNAL ;
    PORT
      LAYER M4 ;
        RECT  204.252 114.672 204.336 114.696 ;
    END
  END weight_data[220]
  PIN weight_data[221]
    DIRECTION OUTPUT ;
    USE SIGNAL ;
    PORT
      LAYER M4 ;
        RECT  204.252 114.864 204.336 114.888 ;
    END
  END weight_data[221]
  PIN weight_data[222]
    DIRECTION OUTPUT ;
    USE SIGNAL ;
    PORT
      LAYER M4 ;
        RECT  204.252 115.056 204.336 115.08 ;
    END
  END weight_data[222]
  PIN weight_data[223]
    DIRECTION OUTPUT ;
    USE SIGNAL ;
    PORT
      LAYER M4 ;
        RECT  204.252 115.248 204.336 115.272 ;
    END
  END weight_data[223]
  PIN weight_data[224]
    DIRECTION OUTPUT ;
    USE SIGNAL ;
    PORT
      LAYER M4 ;
        RECT  204.252 115.44 204.336 115.464 ;
    END
  END weight_data[224]
  PIN weight_data[225]
    DIRECTION OUTPUT ;
    USE SIGNAL ;
    PORT
      LAYER M4 ;
        RECT  204.252 115.632 204.336 115.656 ;
    END
  END weight_data[225]
  PIN weight_data[226]
    DIRECTION OUTPUT ;
    USE SIGNAL ;
    PORT
      LAYER M4 ;
        RECT  204.252 115.824 204.336 115.848 ;
    END
  END weight_data[226]
  PIN weight_data[227]
    DIRECTION OUTPUT ;
    USE SIGNAL ;
    PORT
      LAYER M4 ;
        RECT  204.252 116.016 204.336 116.04 ;
    END
  END weight_data[227]
  PIN weight_data[228]
    DIRECTION OUTPUT ;
    USE SIGNAL ;
    PORT
      LAYER M4 ;
        RECT  204.252 116.208 204.336 116.232 ;
    END
  END weight_data[228]
  PIN weight_data[229]
    DIRECTION OUTPUT ;
    USE SIGNAL ;
    PORT
      LAYER M4 ;
        RECT  204.252 116.4 204.336 116.424 ;
    END
  END weight_data[229]
  PIN weight_data[22]
    DIRECTION OUTPUT ;
    USE SIGNAL ;
    PORT
      LAYER M4 ;
        RECT  204.252 76.656 204.336 76.68 ;
    END
  END weight_data[22]
  PIN weight_data[230]
    DIRECTION OUTPUT ;
    USE SIGNAL ;
    PORT
      LAYER M4 ;
        RECT  204.252 116.592 204.336 116.616 ;
    END
  END weight_data[230]
  PIN weight_data[231]
    DIRECTION OUTPUT ;
    USE SIGNAL ;
    PORT
      LAYER M4 ;
        RECT  204.252 116.784 204.336 116.808 ;
    END
  END weight_data[231]
  PIN weight_data[232]
    DIRECTION OUTPUT ;
    USE SIGNAL ;
    PORT
      LAYER M4 ;
        RECT  204.252 116.976 204.336 117 ;
    END
  END weight_data[232]
  PIN weight_data[233]
    DIRECTION OUTPUT ;
    USE SIGNAL ;
    PORT
      LAYER M4 ;
        RECT  204.252 117.168 204.336 117.192 ;
    END
  END weight_data[233]
  PIN weight_data[234]
    DIRECTION OUTPUT ;
    USE SIGNAL ;
    PORT
      LAYER M4 ;
        RECT  204.252 117.36 204.336 117.384 ;
    END
  END weight_data[234]
  PIN weight_data[235]
    DIRECTION OUTPUT ;
    USE SIGNAL ;
    PORT
      LAYER M4 ;
        RECT  204.252 117.552 204.336 117.576 ;
    END
  END weight_data[235]
  PIN weight_data[236]
    DIRECTION OUTPUT ;
    USE SIGNAL ;
    PORT
      LAYER M4 ;
        RECT  204.252 117.744 204.336 117.768 ;
    END
  END weight_data[236]
  PIN weight_data[237]
    DIRECTION OUTPUT ;
    USE SIGNAL ;
    PORT
      LAYER M4 ;
        RECT  204.252 117.936 204.336 117.96 ;
    END
  END weight_data[237]
  PIN weight_data[238]
    DIRECTION OUTPUT ;
    USE SIGNAL ;
    PORT
      LAYER M4 ;
        RECT  204.252 118.128 204.336 118.152 ;
    END
  END weight_data[238]
  PIN weight_data[239]
    DIRECTION OUTPUT ;
    USE SIGNAL ;
    PORT
      LAYER M4 ;
        RECT  204.252 118.32 204.336 118.344 ;
    END
  END weight_data[239]
  PIN weight_data[23]
    DIRECTION OUTPUT ;
    USE SIGNAL ;
    PORT
      LAYER M4 ;
        RECT  204.252 76.848 204.336 76.872 ;
    END
  END weight_data[23]
  PIN weight_data[240]
    DIRECTION OUTPUT ;
    USE SIGNAL ;
    PORT
      LAYER M4 ;
        RECT  204.252 118.512 204.336 118.536 ;
    END
  END weight_data[240]
  PIN weight_data[241]
    DIRECTION OUTPUT ;
    USE SIGNAL ;
    PORT
      LAYER M4 ;
        RECT  204.252 118.704 204.336 118.728 ;
    END
  END weight_data[241]
  PIN weight_data[242]
    DIRECTION OUTPUT ;
    USE SIGNAL ;
    PORT
      LAYER M4 ;
        RECT  204.252 118.896 204.336 118.92 ;
    END
  END weight_data[242]
  PIN weight_data[243]
    DIRECTION OUTPUT ;
    USE SIGNAL ;
    PORT
      LAYER M4 ;
        RECT  204.252 119.088 204.336 119.112 ;
    END
  END weight_data[243]
  PIN weight_data[244]
    DIRECTION OUTPUT ;
    USE SIGNAL ;
    PORT
      LAYER M4 ;
        RECT  204.252 119.28 204.336 119.304 ;
    END
  END weight_data[244]
  PIN weight_data[245]
    DIRECTION OUTPUT ;
    USE SIGNAL ;
    PORT
      LAYER M4 ;
        RECT  204.252 119.472 204.336 119.496 ;
    END
  END weight_data[245]
  PIN weight_data[246]
    DIRECTION OUTPUT ;
    USE SIGNAL ;
    PORT
      LAYER M4 ;
        RECT  204.252 119.664 204.336 119.688 ;
    END
  END weight_data[246]
  PIN weight_data[247]
    DIRECTION OUTPUT ;
    USE SIGNAL ;
    PORT
      LAYER M4 ;
        RECT  204.252 119.856 204.336 119.88 ;
    END
  END weight_data[247]
  PIN weight_data[248]
    DIRECTION OUTPUT ;
    USE SIGNAL ;
    PORT
      LAYER M4 ;
        RECT  204.252 120.048 204.336 120.072 ;
    END
  END weight_data[248]
  PIN weight_data[249]
    DIRECTION OUTPUT ;
    USE SIGNAL ;
    PORT
      LAYER M4 ;
        RECT  204.252 120.24 204.336 120.264 ;
    END
  END weight_data[249]
  PIN weight_data[24]
    DIRECTION OUTPUT ;
    USE SIGNAL ;
    PORT
      LAYER M4 ;
        RECT  204.252 77.04 204.336 77.064 ;
    END
  END weight_data[24]
  PIN weight_data[250]
    DIRECTION OUTPUT ;
    USE SIGNAL ;
    PORT
      LAYER M4 ;
        RECT  204.252 120.432 204.336 120.456 ;
    END
  END weight_data[250]
  PIN weight_data[251]
    DIRECTION OUTPUT ;
    USE SIGNAL ;
    PORT
      LAYER M4 ;
        RECT  204.252 120.624 204.336 120.648 ;
    END
  END weight_data[251]
  PIN weight_data[252]
    DIRECTION OUTPUT ;
    USE SIGNAL ;
    PORT
      LAYER M4 ;
        RECT  204.252 120.816 204.336 120.84 ;
    END
  END weight_data[252]
  PIN weight_data[253]
    DIRECTION OUTPUT ;
    USE SIGNAL ;
    PORT
      LAYER M4 ;
        RECT  204.252 121.008 204.336 121.032 ;
    END
  END weight_data[253]
  PIN weight_data[254]
    DIRECTION OUTPUT ;
    USE SIGNAL ;
    PORT
      LAYER M4 ;
        RECT  204.252 121.2 204.336 121.224 ;
    END
  END weight_data[254]
  PIN weight_data[255]
    DIRECTION OUTPUT ;
    USE SIGNAL ;
    PORT
      LAYER M4 ;
        RECT  204.252 121.392 204.336 121.416 ;
    END
  END weight_data[255]
  PIN weight_data[25]
    DIRECTION OUTPUT ;
    USE SIGNAL ;
    PORT
      LAYER M4 ;
        RECT  204.252 77.232 204.336 77.256 ;
    END
  END weight_data[25]
  PIN weight_data[26]
    DIRECTION OUTPUT ;
    USE SIGNAL ;
    PORT
      LAYER M4 ;
        RECT  204.252 77.424 204.336 77.448 ;
    END
  END weight_data[26]
  PIN weight_data[27]
    DIRECTION OUTPUT ;
    USE SIGNAL ;
    PORT
      LAYER M4 ;
        RECT  204.252 77.616 204.336 77.64 ;
    END
  END weight_data[27]
  PIN weight_data[28]
    DIRECTION OUTPUT ;
    USE SIGNAL ;
    PORT
      LAYER M4 ;
        RECT  204.252 77.808 204.336 77.832 ;
    END
  END weight_data[28]
  PIN weight_data[29]
    DIRECTION OUTPUT ;
    USE SIGNAL ;
    PORT
      LAYER M4 ;
        RECT  204.252 78 204.336 78.024 ;
    END
  END weight_data[29]
  PIN weight_data[2]
    DIRECTION OUTPUT ;
    USE SIGNAL ;
    PORT
      LAYER M4 ;
        RECT  204.252 72.816 204.336 72.84 ;
    END
  END weight_data[2]
  PIN weight_data[30]
    DIRECTION OUTPUT ;
    USE SIGNAL ;
    PORT
      LAYER M4 ;
        RECT  204.252 78.192 204.336 78.216 ;
    END
  END weight_data[30]
  PIN weight_data[31]
    DIRECTION OUTPUT ;
    USE SIGNAL ;
    PORT
      LAYER M4 ;
        RECT  204.252 78.384 204.336 78.408 ;
    END
  END weight_data[31]
  PIN weight_data[32]
    DIRECTION OUTPUT ;
    USE SIGNAL ;
    PORT
      LAYER M4 ;
        RECT  204.252 78.576 204.336 78.6 ;
    END
  END weight_data[32]
  PIN weight_data[33]
    DIRECTION OUTPUT ;
    USE SIGNAL ;
    PORT
      LAYER M4 ;
        RECT  204.252 78.768 204.336 78.792 ;
    END
  END weight_data[33]
  PIN weight_data[34]
    DIRECTION OUTPUT ;
    USE SIGNAL ;
    PORT
      LAYER M4 ;
        RECT  204.252 78.96 204.336 78.984 ;
    END
  END weight_data[34]
  PIN weight_data[35]
    DIRECTION OUTPUT ;
    USE SIGNAL ;
    PORT
      LAYER M4 ;
        RECT  204.252 79.152 204.336 79.176 ;
    END
  END weight_data[35]
  PIN weight_data[36]
    DIRECTION OUTPUT ;
    USE SIGNAL ;
    PORT
      LAYER M4 ;
        RECT  204.252 79.344 204.336 79.368 ;
    END
  END weight_data[36]
  PIN weight_data[37]
    DIRECTION OUTPUT ;
    USE SIGNAL ;
    PORT
      LAYER M4 ;
        RECT  204.252 79.536 204.336 79.56 ;
    END
  END weight_data[37]
  PIN weight_data[38]
    DIRECTION OUTPUT ;
    USE SIGNAL ;
    PORT
      LAYER M4 ;
        RECT  204.252 79.728 204.336 79.752 ;
    END
  END weight_data[38]
  PIN weight_data[39]
    DIRECTION OUTPUT ;
    USE SIGNAL ;
    PORT
      LAYER M4 ;
        RECT  204.252 79.92 204.336 79.944 ;
    END
  END weight_data[39]
  PIN weight_data[3]
    DIRECTION OUTPUT ;
    USE SIGNAL ;
    PORT
      LAYER M4 ;
        RECT  204.252 73.008 204.336 73.032 ;
    END
  END weight_data[3]
  PIN weight_data[40]
    DIRECTION OUTPUT ;
    USE SIGNAL ;
    PORT
      LAYER M4 ;
        RECT  204.252 80.112 204.336 80.136 ;
    END
  END weight_data[40]
  PIN weight_data[41]
    DIRECTION OUTPUT ;
    USE SIGNAL ;
    PORT
      LAYER M4 ;
        RECT  204.252 80.304 204.336 80.328 ;
    END
  END weight_data[41]
  PIN weight_data[42]
    DIRECTION OUTPUT ;
    USE SIGNAL ;
    PORT
      LAYER M4 ;
        RECT  204.252 80.496 204.336 80.52 ;
    END
  END weight_data[42]
  PIN weight_data[43]
    DIRECTION OUTPUT ;
    USE SIGNAL ;
    PORT
      LAYER M4 ;
        RECT  204.252 80.688 204.336 80.712 ;
    END
  END weight_data[43]
  PIN weight_data[44]
    DIRECTION OUTPUT ;
    USE SIGNAL ;
    PORT
      LAYER M4 ;
        RECT  204.252 80.88 204.336 80.904 ;
    END
  END weight_data[44]
  PIN weight_data[45]
    DIRECTION OUTPUT ;
    USE SIGNAL ;
    PORT
      LAYER M4 ;
        RECT  204.252 81.072 204.336 81.096 ;
    END
  END weight_data[45]
  PIN weight_data[46]
    DIRECTION OUTPUT ;
    USE SIGNAL ;
    PORT
      LAYER M4 ;
        RECT  204.252 81.264 204.336 81.288 ;
    END
  END weight_data[46]
  PIN weight_data[47]
    DIRECTION OUTPUT ;
    USE SIGNAL ;
    PORT
      LAYER M4 ;
        RECT  204.252 81.456 204.336 81.48 ;
    END
  END weight_data[47]
  PIN weight_data[48]
    DIRECTION OUTPUT ;
    USE SIGNAL ;
    PORT
      LAYER M4 ;
        RECT  204.252 81.648 204.336 81.672 ;
    END
  END weight_data[48]
  PIN weight_data[49]
    DIRECTION OUTPUT ;
    USE SIGNAL ;
    PORT
      LAYER M4 ;
        RECT  204.252 81.84 204.336 81.864 ;
    END
  END weight_data[49]
  PIN weight_data[4]
    DIRECTION OUTPUT ;
    USE SIGNAL ;
    PORT
      LAYER M4 ;
        RECT  204.252 73.2 204.336 73.224 ;
    END
  END weight_data[4]
  PIN weight_data[50]
    DIRECTION OUTPUT ;
    USE SIGNAL ;
    PORT
      LAYER M4 ;
        RECT  204.252 82.032 204.336 82.056 ;
    END
  END weight_data[50]
  PIN weight_data[51]
    DIRECTION OUTPUT ;
    USE SIGNAL ;
    PORT
      LAYER M4 ;
        RECT  204.252 82.224 204.336 82.248 ;
    END
  END weight_data[51]
  PIN weight_data[52]
    DIRECTION OUTPUT ;
    USE SIGNAL ;
    PORT
      LAYER M4 ;
        RECT  204.252 82.416 204.336 82.44 ;
    END
  END weight_data[52]
  PIN weight_data[53]
    DIRECTION OUTPUT ;
    USE SIGNAL ;
    PORT
      LAYER M4 ;
        RECT  204.252 82.608 204.336 82.632 ;
    END
  END weight_data[53]
  PIN weight_data[54]
    DIRECTION OUTPUT ;
    USE SIGNAL ;
    PORT
      LAYER M4 ;
        RECT  204.252 82.8 204.336 82.824 ;
    END
  END weight_data[54]
  PIN weight_data[55]
    DIRECTION OUTPUT ;
    USE SIGNAL ;
    PORT
      LAYER M4 ;
        RECT  204.252 82.992 204.336 83.016 ;
    END
  END weight_data[55]
  PIN weight_data[56]
    DIRECTION OUTPUT ;
    USE SIGNAL ;
    PORT
      LAYER M4 ;
        RECT  204.252 83.184 204.336 83.208 ;
    END
  END weight_data[56]
  PIN weight_data[57]
    DIRECTION OUTPUT ;
    USE SIGNAL ;
    PORT
      LAYER M4 ;
        RECT  204.252 83.376 204.336 83.4 ;
    END
  END weight_data[57]
  PIN weight_data[58]
    DIRECTION OUTPUT ;
    USE SIGNAL ;
    PORT
      LAYER M4 ;
        RECT  204.252 83.568 204.336 83.592 ;
    END
  END weight_data[58]
  PIN weight_data[59]
    DIRECTION OUTPUT ;
    USE SIGNAL ;
    PORT
      LAYER M4 ;
        RECT  204.252 83.76 204.336 83.784 ;
    END
  END weight_data[59]
  PIN weight_data[5]
    DIRECTION OUTPUT ;
    USE SIGNAL ;
    PORT
      LAYER M4 ;
        RECT  204.252 73.392 204.336 73.416 ;
    END
  END weight_data[5]
  PIN weight_data[60]
    DIRECTION OUTPUT ;
    USE SIGNAL ;
    PORT
      LAYER M4 ;
        RECT  204.252 83.952 204.336 83.976 ;
    END
  END weight_data[60]
  PIN weight_data[61]
    DIRECTION OUTPUT ;
    USE SIGNAL ;
    PORT
      LAYER M4 ;
        RECT  204.252 84.144 204.336 84.168 ;
    END
  END weight_data[61]
  PIN weight_data[62]
    DIRECTION OUTPUT ;
    USE SIGNAL ;
    PORT
      LAYER M4 ;
        RECT  204.252 84.336 204.336 84.36 ;
    END
  END weight_data[62]
  PIN weight_data[63]
    DIRECTION OUTPUT ;
    USE SIGNAL ;
    PORT
      LAYER M4 ;
        RECT  204.252 84.528 204.336 84.552 ;
    END
  END weight_data[63]
  PIN weight_data[64]
    DIRECTION OUTPUT ;
    USE SIGNAL ;
    PORT
      LAYER M4 ;
        RECT  204.252 84.72 204.336 84.744 ;
    END
  END weight_data[64]
  PIN weight_data[65]
    DIRECTION OUTPUT ;
    USE SIGNAL ;
    PORT
      LAYER M4 ;
        RECT  204.252 84.912 204.336 84.936 ;
    END
  END weight_data[65]
  PIN weight_data[66]
    DIRECTION OUTPUT ;
    USE SIGNAL ;
    PORT
      LAYER M4 ;
        RECT  204.252 85.104 204.336 85.128 ;
    END
  END weight_data[66]
  PIN weight_data[67]
    DIRECTION OUTPUT ;
    USE SIGNAL ;
    PORT
      LAYER M4 ;
        RECT  204.252 85.296 204.336 85.32 ;
    END
  END weight_data[67]
  PIN weight_data[68]
    DIRECTION OUTPUT ;
    USE SIGNAL ;
    PORT
      LAYER M4 ;
        RECT  204.252 85.488 204.336 85.512 ;
    END
  END weight_data[68]
  PIN weight_data[69]
    DIRECTION OUTPUT ;
    USE SIGNAL ;
    PORT
      LAYER M4 ;
        RECT  204.252 85.68 204.336 85.704 ;
    END
  END weight_data[69]
  PIN weight_data[6]
    DIRECTION OUTPUT ;
    USE SIGNAL ;
    PORT
      LAYER M4 ;
        RECT  204.252 73.584 204.336 73.608 ;
    END
  END weight_data[6]
  PIN weight_data[70]
    DIRECTION OUTPUT ;
    USE SIGNAL ;
    PORT
      LAYER M4 ;
        RECT  204.252 85.872 204.336 85.896 ;
    END
  END weight_data[70]
  PIN weight_data[71]
    DIRECTION OUTPUT ;
    USE SIGNAL ;
    PORT
      LAYER M4 ;
        RECT  204.252 86.064 204.336 86.088 ;
    END
  END weight_data[71]
  PIN weight_data[72]
    DIRECTION OUTPUT ;
    USE SIGNAL ;
    PORT
      LAYER M4 ;
        RECT  204.252 86.256 204.336 86.28 ;
    END
  END weight_data[72]
  PIN weight_data[73]
    DIRECTION OUTPUT ;
    USE SIGNAL ;
    PORT
      LAYER M4 ;
        RECT  204.252 86.448 204.336 86.472 ;
    END
  END weight_data[73]
  PIN weight_data[74]
    DIRECTION OUTPUT ;
    USE SIGNAL ;
    PORT
      LAYER M4 ;
        RECT  204.252 86.64 204.336 86.664 ;
    END
  END weight_data[74]
  PIN weight_data[75]
    DIRECTION OUTPUT ;
    USE SIGNAL ;
    PORT
      LAYER M4 ;
        RECT  204.252 86.832 204.336 86.856 ;
    END
  END weight_data[75]
  PIN weight_data[76]
    DIRECTION OUTPUT ;
    USE SIGNAL ;
    PORT
      LAYER M4 ;
        RECT  204.252 87.024 204.336 87.048 ;
    END
  END weight_data[76]
  PIN weight_data[77]
    DIRECTION OUTPUT ;
    USE SIGNAL ;
    PORT
      LAYER M4 ;
        RECT  204.252 87.216 204.336 87.24 ;
    END
  END weight_data[77]
  PIN weight_data[78]
    DIRECTION OUTPUT ;
    USE SIGNAL ;
    PORT
      LAYER M4 ;
        RECT  204.252 87.408 204.336 87.432 ;
    END
  END weight_data[78]
  PIN weight_data[79]
    DIRECTION OUTPUT ;
    USE SIGNAL ;
    PORT
      LAYER M4 ;
        RECT  204.252 87.6 204.336 87.624 ;
    END
  END weight_data[79]
  PIN weight_data[7]
    DIRECTION OUTPUT ;
    USE SIGNAL ;
    PORT
      LAYER M4 ;
        RECT  204.252 73.776 204.336 73.8 ;
    END
  END weight_data[7]
  PIN weight_data[80]
    DIRECTION OUTPUT ;
    USE SIGNAL ;
    PORT
      LAYER M4 ;
        RECT  204.252 87.792 204.336 87.816 ;
    END
  END weight_data[80]
  PIN weight_data[81]
    DIRECTION OUTPUT ;
    USE SIGNAL ;
    PORT
      LAYER M4 ;
        RECT  204.252 87.984 204.336 88.008 ;
    END
  END weight_data[81]
  PIN weight_data[82]
    DIRECTION OUTPUT ;
    USE SIGNAL ;
    PORT
      LAYER M4 ;
        RECT  204.252 88.176 204.336 88.2 ;
    END
  END weight_data[82]
  PIN weight_data[83]
    DIRECTION OUTPUT ;
    USE SIGNAL ;
    PORT
      LAYER M4 ;
        RECT  204.252 88.368 204.336 88.392 ;
    END
  END weight_data[83]
  PIN weight_data[84]
    DIRECTION OUTPUT ;
    USE SIGNAL ;
    PORT
      LAYER M4 ;
        RECT  204.252 88.56 204.336 88.584 ;
    END
  END weight_data[84]
  PIN weight_data[85]
    DIRECTION OUTPUT ;
    USE SIGNAL ;
    PORT
      LAYER M4 ;
        RECT  204.252 88.752 204.336 88.776 ;
    END
  END weight_data[85]
  PIN weight_data[86]
    DIRECTION OUTPUT ;
    USE SIGNAL ;
    PORT
      LAYER M4 ;
        RECT  204.252 88.944 204.336 88.968 ;
    END
  END weight_data[86]
  PIN weight_data[87]
    DIRECTION OUTPUT ;
    USE SIGNAL ;
    PORT
      LAYER M4 ;
        RECT  204.252 89.136 204.336 89.16 ;
    END
  END weight_data[87]
  PIN weight_data[88]
    DIRECTION OUTPUT ;
    USE SIGNAL ;
    PORT
      LAYER M4 ;
        RECT  204.252 89.328 204.336 89.352 ;
    END
  END weight_data[88]
  PIN weight_data[89]
    DIRECTION OUTPUT ;
    USE SIGNAL ;
    PORT
      LAYER M4 ;
        RECT  204.252 89.52 204.336 89.544 ;
    END
  END weight_data[89]
  PIN weight_data[8]
    DIRECTION OUTPUT ;
    USE SIGNAL ;
    PORT
      LAYER M4 ;
        RECT  204.252 73.968 204.336 73.992 ;
    END
  END weight_data[8]
  PIN weight_data[90]
    DIRECTION OUTPUT ;
    USE SIGNAL ;
    PORT
      LAYER M4 ;
        RECT  204.252 89.712 204.336 89.736 ;
    END
  END weight_data[90]
  PIN weight_data[91]
    DIRECTION OUTPUT ;
    USE SIGNAL ;
    PORT
      LAYER M4 ;
        RECT  204.252 89.904 204.336 89.928 ;
    END
  END weight_data[91]
  PIN weight_data[92]
    DIRECTION OUTPUT ;
    USE SIGNAL ;
    PORT
      LAYER M4 ;
        RECT  204.252 90.096 204.336 90.12 ;
    END
  END weight_data[92]
  PIN weight_data[93]
    DIRECTION OUTPUT ;
    USE SIGNAL ;
    PORT
      LAYER M4 ;
        RECT  204.252 90.288 204.336 90.312 ;
    END
  END weight_data[93]
  PIN weight_data[94]
    DIRECTION OUTPUT ;
    USE SIGNAL ;
    PORT
      LAYER M4 ;
        RECT  204.252 90.48 204.336 90.504 ;
    END
  END weight_data[94]
  PIN weight_data[95]
    DIRECTION OUTPUT ;
    USE SIGNAL ;
    PORT
      LAYER M4 ;
        RECT  204.252 90.672 204.336 90.696 ;
    END
  END weight_data[95]
  PIN weight_data[96]
    DIRECTION OUTPUT ;
    USE SIGNAL ;
    PORT
      LAYER M4 ;
        RECT  204.252 90.864 204.336 90.888 ;
    END
  END weight_data[96]
  PIN weight_data[97]
    DIRECTION OUTPUT ;
    USE SIGNAL ;
    PORT
      LAYER M4 ;
        RECT  204.252 91.056 204.336 91.08 ;
    END
  END weight_data[97]
  PIN weight_data[98]
    DIRECTION OUTPUT ;
    USE SIGNAL ;
    PORT
      LAYER M4 ;
        RECT  204.252 91.248 204.336 91.272 ;
    END
  END weight_data[98]
  PIN weight_data[99]
    DIRECTION OUTPUT ;
    USE SIGNAL ;
    PORT
      LAYER M4 ;
        RECT  204.252 91.44 204.336 91.464 ;
    END
  END weight_data[99]
  PIN weight_data[9]
    DIRECTION OUTPUT ;
    USE SIGNAL ;
    PORT
      LAYER M4 ;
        RECT  204.252 74.16 204.336 74.184 ;
    END
  END weight_data[9]
  PIN write_done
    DIRECTION OUTPUT ;
    USE SIGNAL ;
    PORT
      LAYER M4 ;
        RECT  204.252 121.584 204.336 121.608 ;
    END
  END write_done
  PIN VDD
    DIRECTION INOUT ;
    USE POWER ;
    PORT
      LAYER M5 ;
        RECT  196.992 2.151 197.112 192.249 ;
        RECT  191.592 2.151 191.712 192.249 ;
        RECT  186.192 2.151 186.312 192.249 ;
        RECT  180.792 2.151 180.912 192.249 ;
        RECT  175.392 2.151 175.512 192.249 ;
        RECT  169.992 2.151 170.112 192.249 ;
        RECT  164.592 2.151 164.712 192.249 ;
        RECT  159.192 2.151 159.312 192.249 ;
        RECT  153.792 2.151 153.912 192.249 ;
        RECT  148.392 2.151 148.512 192.249 ;
        RECT  142.992 2.151 143.112 192.249 ;
        RECT  137.592 2.151 137.712 192.249 ;
        RECT  132.192 2.151 132.312 192.249 ;
        RECT  126.792 2.151 126.912 192.249 ;
        RECT  121.392 2.151 121.512 192.249 ;
        RECT  115.992 2.151 116.112 192.249 ;
        RECT  110.592 2.151 110.712 192.249 ;
        RECT  105.192 2.151 105.312 192.249 ;
        RECT  99.792 2.151 99.912 192.249 ;
        RECT  94.392 2.151 94.512 192.249 ;
        RECT  88.992 2.151 89.112 192.249 ;
        RECT  83.592 2.151 83.712 192.249 ;
        RECT  78.192 2.151 78.312 192.249 ;
        RECT  72.792 2.151 72.912 192.249 ;
        RECT  67.392 2.151 67.512 192.249 ;
        RECT  61.992 2.151 62.112 192.249 ;
        RECT  56.592 2.151 56.712 192.249 ;
        RECT  51.192 2.151 51.312 192.249 ;
        RECT  45.792 2.151 45.912 192.249 ;
        RECT  40.392 2.151 40.512 192.249 ;
        RECT  34.992 2.151 35.112 192.249 ;
        RECT  29.592 2.151 29.712 192.249 ;
        RECT  24.192 2.151 24.312 192.249 ;
        RECT  18.792 2.151 18.912 192.249 ;
        RECT  13.392 2.151 13.512 192.249 ;
        RECT  7.992 2.151 8.112 192.249 ;
        RECT  2.592 2.151 2.712 192.249 ;
    END
  END VDD
  PIN VSS
    DIRECTION INOUT ;
    USE GROUND ;
    PORT
      LAYER M5 ;
        RECT  196.8 2.137 196.92 192.263 ;
        RECT  191.4 2.137 191.52 192.263 ;
        RECT  186 2.137 186.12 192.263 ;
        RECT  180.6 2.137 180.72 192.263 ;
        RECT  175.2 2.137 175.32 192.263 ;
        RECT  169.8 2.137 169.92 192.263 ;
        RECT  164.4 2.137 164.52 192.263 ;
        RECT  159 2.137 159.12 192.263 ;
        RECT  153.6 2.137 153.72 192.263 ;
        RECT  148.2 2.137 148.32 192.263 ;
        RECT  142.8 2.137 142.92 192.263 ;
        RECT  137.4 2.137 137.52 192.263 ;
        RECT  132 2.137 132.12 192.263 ;
        RECT  126.6 2.137 126.72 192.263 ;
        RECT  121.2 2.137 121.32 192.263 ;
        RECT  115.8 2.137 115.92 192.263 ;
        RECT  110.4 2.137 110.52 192.263 ;
        RECT  105 2.137 105.12 192.263 ;
        RECT  99.6 2.137 99.72 192.263 ;
        RECT  94.2 2.137 94.32 192.263 ;
        RECT  88.8 2.137 88.92 192.263 ;
        RECT  83.4 2.137 83.52 192.263 ;
        RECT  78 2.137 78.12 192.263 ;
        RECT  72.6 2.137 72.72 192.263 ;
        RECT  67.2 2.137 67.32 192.263 ;
        RECT  61.8 2.137 61.92 192.263 ;
        RECT  56.4 2.137 56.52 192.263 ;
        RECT  51 2.137 51.12 192.263 ;
        RECT  45.6 2.137 45.72 192.263 ;
        RECT  40.2 2.137 40.32 192.263 ;
        RECT  34.8 2.137 34.92 192.263 ;
        RECT  29.4 2.137 29.52 192.263 ;
        RECT  24 2.137 24.12 192.263 ;
        RECT  18.6 2.137 18.72 192.263 ;
        RECT  13.2 2.137 13.32 192.263 ;
        RECT  7.8 2.137 7.92 192.263 ;
        RECT  2.4 2.137 2.52 192.263 ;
    END
  END VSS
  # OT_OBS_CLOSED layer=M5 d_um=1.536 added=107
  OBS
    LAYER RVTN ;
     RECT  2.16 2.16 202.176 2.295 ;
     RECT  2.16 2.565 202.176 2.835 ;
     RECT  2.16 3.105 202.176 3.375 ;
     RECT  2.16 3.645 202.176 3.915 ;
     RECT  2.16 4.185 202.176 4.455 ;
     RECT  2.16 4.725 202.176 4.995 ;
     RECT  2.16 5.265 202.176 5.535 ;
     RECT  2.16 5.805 202.176 6.075 ;
     RECT  2.16 6.345 202.176 6.615 ;
     RECT  2.16 6.885 202.176 7.155 ;
     RECT  2.16 7.425 202.176 7.695 ;
     RECT  2.16 7.965 202.176 8.235 ;
     RECT  2.16 8.505 202.176 8.775 ;
     RECT  2.16 9.045 202.176 9.315 ;
     RECT  2.16 9.585 202.176 9.855 ;
     RECT  2.16 10.125 202.176 10.395 ;
     RECT  2.16 10.665 202.176 10.935 ;
     RECT  2.16 11.205 202.176 11.475 ;
     RECT  2.16 11.745 202.176 12.015 ;
     RECT  2.16 12.285 202.176 12.555 ;
     RECT  2.16 12.825 202.176 13.095 ;
     RECT  2.16 13.365 202.176 13.635 ;
     RECT  2.16 13.905 202.176 14.175 ;
     RECT  2.16 14.445 202.176 14.715 ;
     RECT  2.16 14.985 202.176 15.255 ;
     RECT  2.16 15.525 202.176 15.795 ;
     RECT  2.16 16.065 202.176 16.335 ;
     RECT  2.16 16.605 202.176 16.875 ;
     RECT  2.16 17.145 202.176 17.415 ;
     RECT  2.16 17.685 202.176 17.955 ;
     RECT  2.16 18.225 202.176 18.495 ;
     RECT  2.16 18.765 202.176 19.035 ;
     RECT  2.16 19.305 202.176 19.575 ;
     RECT  2.16 19.845 202.176 20.115 ;
     RECT  2.16 20.385 202.176 20.655 ;
     RECT  2.16 20.925 202.176 21.195 ;
     RECT  2.16 21.465 202.176 21.735 ;
     RECT  2.16 22.005 202.176 22.275 ;
     RECT  2.16 22.545 202.176 22.815 ;
     RECT  2.16 23.085 202.176 23.355 ;
     RECT  2.16 23.625 202.176 23.895 ;
     RECT  2.16 24.165 202.176 24.435 ;
     RECT  2.16 24.705 202.176 24.975 ;
     RECT  2.16 25.245 202.176 25.515 ;
     RECT  2.16 25.785 202.176 26.055 ;
     RECT  2.16 26.325 202.176 26.595 ;
     RECT  2.16 26.865 202.176 27.135 ;
     RECT  2.16 27.405 202.176 27.675 ;
     RECT  2.16 27.945 202.176 28.215 ;
     RECT  2.16 28.485 202.176 28.755 ;
     RECT  2.16 29.025 202.176 29.295 ;
     RECT  2.16 29.565 202.176 29.835 ;
     RECT  2.16 30.105 202.176 30.375 ;
     RECT  2.16 30.645 202.176 30.915 ;
     RECT  2.16 31.185 202.176 31.455 ;
     RECT  2.16 31.725 202.176 31.995 ;
     RECT  2.16 32.265 202.176 32.535 ;
     RECT  2.16 32.805 202.176 33.075 ;
     RECT  2.16 33.345 202.176 33.615 ;
     RECT  2.16 33.885 202.176 34.155 ;
     RECT  2.16 34.425 202.176 34.695 ;
     RECT  2.16 34.965 202.176 35.235 ;
     RECT  2.16 35.505 202.176 35.775 ;
     RECT  2.16 36.045 202.176 36.315 ;
     RECT  2.16 36.585 202.176 36.855 ;
     RECT  2.16 37.125 202.176 37.395 ;
     RECT  2.16 37.665 202.176 37.935 ;
     RECT  2.16 38.205 202.176 38.475 ;
     RECT  2.16 38.745 202.176 39.015 ;
     RECT  2.16 39.285 202.176 39.555 ;
     RECT  2.16 39.825 202.176 40.095 ;
     RECT  2.16 40.365 202.176 40.635 ;
     RECT  2.16 40.905 202.176 41.175 ;
     RECT  2.16 41.445 202.176 41.715 ;
     RECT  2.16 41.985 202.176 42.255 ;
     RECT  2.16 42.525 202.176 42.795 ;
     RECT  2.16 43.065 202.176 43.335 ;
     RECT  2.16 43.605 202.176 43.875 ;
     RECT  2.16 44.145 202.176 44.415 ;
     RECT  2.16 44.685 202.176 44.955 ;
     RECT  2.16 45.225 202.176 45.495 ;
     RECT  2.16 45.765 202.176 46.035 ;
     RECT  2.16 46.305 202.176 46.575 ;
     RECT  2.16 46.845 202.176 47.115 ;
     RECT  2.16 47.385 202.176 47.655 ;
     RECT  2.16 47.925 202.176 48.195 ;
     RECT  2.16 48.465 202.176 48.735 ;
     RECT  2.16 49.005 202.176 49.275 ;
     RECT  2.16 49.545 202.176 49.815 ;
     RECT  2.16 50.085 202.176 50.355 ;
     RECT  2.16 50.625 202.176 50.895 ;
     RECT  2.16 51.165 202.176 51.435 ;
     RECT  2.16 51.705 202.176 51.975 ;
     RECT  2.16 52.245 202.176 52.515 ;
     RECT  2.16 52.785 202.176 53.055 ;
     RECT  2.16 53.325 202.176 53.595 ;
     RECT  2.16 53.865 202.176 54.135 ;
     RECT  2.16 54.405 202.176 54.675 ;
     RECT  2.16 54.945 202.176 55.215 ;
     RECT  2.16 55.485 202.176 55.755 ;
     RECT  2.16 56.025 202.176 56.16 ;
     RECT  2.16 56.16 53.244 56.295 ;
     RECT  152.172 56.16 202.176 56.295 ;
     RECT  2.16 56.565 53.244 56.835 ;
     RECT  152.172 56.565 202.176 56.835 ;
     RECT  2.16 57.105 53.244 57.375 ;
     RECT  152.172 57.105 202.176 57.375 ;
     RECT  2.16 57.645 53.244 57.915 ;
     RECT  152.172 57.645 202.176 57.915 ;
     RECT  2.16 58.185 53.244 58.455 ;
     RECT  152.172 58.185 202.176 58.455 ;
     RECT  2.16 58.725 53.244 58.995 ;
     RECT  152.172 58.725 202.176 58.995 ;
     RECT  2.16 59.265 53.244 59.535 ;
     RECT  152.172 59.265 202.176 59.535 ;
     RECT  2.16 59.805 53.244 60.075 ;
     RECT  152.172 59.805 202.176 60.075 ;
     RECT  2.16 60.345 53.244 60.615 ;
     RECT  152.172 60.345 202.176 60.615 ;
     RECT  2.16 60.885 53.244 61.155 ;
     RECT  152.172 60.885 202.176 61.155 ;
     RECT  2.16 61.425 53.244 61.695 ;
     RECT  152.172 61.425 202.176 61.695 ;
     RECT  2.16 61.965 53.244 62.235 ;
     RECT  152.172 61.965 202.176 62.235 ;
     RECT  2.16 62.505 53.244 62.775 ;
     RECT  152.172 62.505 202.176 62.775 ;
     RECT  2.16 63.045 53.244 63.315 ;
     RECT  152.172 63.045 202.176 63.315 ;
     RECT  2.16 63.585 53.244 63.855 ;
     RECT  152.172 63.585 202.176 63.855 ;
     RECT  2.16 64.125 53.244 64.395 ;
     RECT  152.172 64.125 202.176 64.395 ;
     RECT  2.16 64.665 53.244 64.935 ;
     RECT  152.172 64.665 202.176 64.935 ;
     RECT  2.16 65.205 53.244 65.475 ;
     RECT  152.172 65.205 202.176 65.475 ;
     RECT  2.16 65.745 53.244 66.015 ;
     RECT  152.172 65.745 202.176 66.015 ;
     RECT  2.16 66.285 53.244 66.555 ;
     RECT  152.172 66.285 202.176 66.555 ;
     RECT  2.16 66.825 53.244 67.095 ;
     RECT  152.172 66.825 202.176 67.095 ;
     RECT  2.16 67.365 53.244 67.635 ;
     RECT  152.172 67.365 202.176 67.635 ;
     RECT  2.16 67.905 53.244 68.175 ;
     RECT  152.172 67.905 202.176 68.175 ;
     RECT  2.16 68.445 53.244 68.715 ;
     RECT  152.172 68.445 202.176 68.715 ;
     RECT  2.16 68.985 53.244 69.255 ;
     RECT  152.172 68.985 202.176 69.255 ;
     RECT  2.16 69.525 53.244 69.795 ;
     RECT  152.172 69.525 202.176 69.795 ;
     RECT  2.16 70.065 53.244 70.335 ;
     RECT  152.172 70.065 202.176 70.335 ;
     RECT  2.16 70.605 53.244 70.875 ;
     RECT  152.172 70.605 202.176 70.875 ;
     RECT  2.16 71.145 53.244 71.415 ;
     RECT  152.172 71.145 202.176 71.415 ;
     RECT  2.16 71.685 53.244 71.955 ;
     RECT  152.172 71.685 202.176 71.955 ;
     RECT  2.16 72.225 53.244 72.495 ;
     RECT  152.172 72.225 202.176 72.495 ;
     RECT  2.16 72.765 53.244 73.035 ;
     RECT  152.172 72.765 202.176 73.035 ;
     RECT  2.16 73.305 53.244 73.575 ;
     RECT  152.172 73.305 202.176 73.575 ;
     RECT  2.16 73.845 53.244 74.115 ;
     RECT  152.172 73.845 202.176 74.115 ;
     RECT  2.16 74.385 53.244 74.655 ;
     RECT  152.172 74.385 202.176 74.655 ;
     RECT  2.16 74.925 53.244 75.195 ;
     RECT  152.172 74.925 202.176 75.195 ;
     RECT  2.16 75.465 53.244 75.735 ;
     RECT  152.172 75.465 202.176 75.735 ;
     RECT  2.16 76.005 53.244 76.275 ;
     RECT  152.172 76.005 202.176 76.275 ;
     RECT  2.16 76.545 53.244 76.815 ;
     RECT  152.172 76.545 202.176 76.815 ;
     RECT  2.16 77.085 53.244 77.355 ;
     RECT  152.172 77.085 202.176 77.355 ;
     RECT  2.16 77.625 53.244 77.895 ;
     RECT  152.172 77.625 202.176 77.895 ;
     RECT  2.16 78.165 53.244 78.435 ;
     RECT  152.172 78.165 202.176 78.435 ;
     RECT  2.16 78.705 53.244 78.975 ;
     RECT  152.172 78.705 202.176 78.975 ;
     RECT  2.16 79.245 53.244 79.515 ;
     RECT  152.172 79.245 202.176 79.515 ;
     RECT  2.16 79.785 53.244 80.055 ;
     RECT  152.172 79.785 202.176 80.055 ;
     RECT  2.16 80.325 53.244 80.595 ;
     RECT  152.172 80.325 202.176 80.595 ;
     RECT  2.16 80.865 53.244 81.135 ;
     RECT  152.172 80.865 202.176 81.135 ;
     RECT  2.16 81.405 53.244 81.675 ;
     RECT  152.172 81.405 202.176 81.675 ;
     RECT  2.16 81.945 53.244 82.215 ;
     RECT  152.172 81.945 202.176 82.215 ;
     RECT  2.16 82.485 53.244 82.755 ;
     RECT  152.172 82.485 202.176 82.755 ;
     RECT  2.16 83.025 53.244 83.295 ;
     RECT  152.172 83.025 202.176 83.295 ;
     RECT  2.16 83.565 53.244 83.835 ;
     RECT  152.172 83.565 202.176 83.835 ;
     RECT  2.16 84.105 53.244 84.375 ;
     RECT  152.172 84.105 202.176 84.375 ;
     RECT  2.16 84.645 53.244 84.915 ;
     RECT  152.172 84.645 202.176 84.915 ;
     RECT  2.16 85.185 53.244 85.455 ;
     RECT  152.172 85.185 202.176 85.455 ;
     RECT  2.16 85.725 53.244 85.995 ;
     RECT  152.172 85.725 202.176 85.995 ;
     RECT  2.16 86.265 53.244 86.535 ;
     RECT  152.172 86.265 202.176 86.535 ;
     RECT  2.16 86.805 53.244 87.075 ;
     RECT  152.172 86.805 202.176 87.075 ;
     RECT  2.16 87.345 53.244 87.615 ;
     RECT  152.172 87.345 202.176 87.615 ;
     RECT  2.16 87.885 53.244 88.155 ;
     RECT  152.172 87.885 202.176 88.155 ;
     RECT  2.16 88.425 53.244 88.695 ;
     RECT  152.172 88.425 202.176 88.695 ;
     RECT  2.16 88.965 53.244 89.235 ;
     RECT  152.172 88.965 202.176 89.235 ;
     RECT  2.16 89.505 53.244 89.775 ;
     RECT  152.172 89.505 202.176 89.775 ;
     RECT  2.16 90.045 53.244 90.315 ;
     RECT  152.172 90.045 202.176 90.315 ;
     RECT  2.16 90.585 53.244 90.855 ;
     RECT  152.172 90.585 202.176 90.855 ;
     RECT  2.16 91.125 53.244 91.395 ;
     RECT  152.172 91.125 202.176 91.395 ;
     RECT  2.16 91.665 53.244 91.935 ;
     RECT  152.172 91.665 202.176 91.935 ;
     RECT  2.16 92.205 53.244 92.475 ;
     RECT  152.172 92.205 202.176 92.475 ;
     RECT  2.16 92.745 53.244 93.015 ;
     RECT  152.172 92.745 202.176 93.015 ;
     RECT  2.16 93.285 53.244 93.555 ;
     RECT  152.172 93.285 202.176 93.555 ;
     RECT  2.16 93.825 53.244 94.095 ;
     RECT  152.172 93.825 202.176 94.095 ;
     RECT  2.16 94.365 53.244 94.635 ;
     RECT  152.172 94.365 202.176 94.635 ;
     RECT  2.16 94.905 53.244 95.175 ;
     RECT  152.172 94.905 202.176 95.175 ;
     RECT  2.16 95.445 53.244 95.715 ;
     RECT  152.172 95.445 202.176 95.715 ;
     RECT  2.16 95.985 53.244 96.255 ;
     RECT  152.172 95.985 202.176 96.255 ;
     RECT  2.16 96.525 53.244 96.795 ;
     RECT  152.172 96.525 202.176 96.795 ;
     RECT  2.16 97.065 53.244 97.335 ;
     RECT  152.172 97.065 202.176 97.335 ;
     RECT  2.16 97.605 53.244 97.875 ;
     RECT  152.172 97.605 202.176 97.875 ;
     RECT  2.16 98.145 53.244 98.415 ;
     RECT  152.172 98.145 202.176 98.415 ;
     RECT  2.16 98.685 53.244 98.955 ;
     RECT  152.172 98.685 202.176 98.955 ;
     RECT  2.16 99.225 53.244 99.495 ;
     RECT  152.172 99.225 202.176 99.495 ;
     RECT  2.16 99.765 53.244 100.035 ;
     RECT  152.172 99.765 202.176 100.035 ;
     RECT  2.16 100.305 53.244 100.575 ;
     RECT  152.172 100.305 202.176 100.575 ;
     RECT  2.16 100.845 53.244 101.115 ;
     RECT  152.172 100.845 202.176 101.115 ;
     RECT  2.16 101.385 53.244 101.52 ;
     RECT  152.172 101.385 202.176 101.52 ;
     RECT  2.16 101.52 202.176 101.655 ;
     RECT  2.16 101.925 202.176 102.195 ;
     RECT  2.16 102.465 202.176 102.735 ;
     RECT  2.16 103.005 202.176 103.275 ;
     RECT  2.16 103.545 202.176 103.815 ;
     RECT  2.16 104.085 202.176 104.355 ;
     RECT  2.16 104.625 202.176 104.895 ;
     RECT  2.16 105.165 202.176 105.435 ;
     RECT  2.16 105.705 202.176 105.975 ;
     RECT  2.16 106.245 202.176 106.515 ;
     RECT  2.16 106.785 202.176 107.055 ;
     RECT  2.16 107.325 202.176 107.595 ;
     RECT  2.16 107.865 202.176 108.135 ;
     RECT  2.16 108.405 202.176 108.675 ;
     RECT  2.16 108.945 202.176 109.215 ;
     RECT  2.16 109.485 202.176 109.755 ;
     RECT  2.16 110.025 202.176 110.295 ;
     RECT  2.16 110.565 202.176 110.835 ;
     RECT  2.16 111.105 202.176 111.375 ;
     RECT  2.16 111.645 202.176 111.915 ;
     RECT  2.16 112.185 202.176 112.455 ;
     RECT  2.16 112.725 202.176 112.995 ;
     RECT  2.16 113.265 202.176 113.535 ;
     RECT  2.16 113.805 202.176 114.075 ;
     RECT  2.16 114.345 202.176 114.615 ;
     RECT  2.16 114.885 202.176 115.155 ;
     RECT  2.16 115.425 202.176 115.695 ;
     RECT  2.16 115.965 202.176 116.235 ;
     RECT  2.16 116.505 202.176 116.775 ;
     RECT  2.16 117.045 202.176 117.315 ;
     RECT  2.16 117.585 202.176 117.855 ;
     RECT  2.16 118.125 202.176 118.395 ;
     RECT  2.16 118.665 202.176 118.935 ;
     RECT  2.16 119.205 202.176 119.475 ;
     RECT  2.16 119.745 202.176 120.015 ;
     RECT  2.16 120.285 202.176 120.555 ;
     RECT  2.16 120.825 202.176 121.095 ;
     RECT  2.16 121.365 202.176 121.635 ;
     RECT  2.16 121.905 202.176 122.175 ;
     RECT  2.16 122.445 202.176 122.715 ;
     RECT  2.16 122.985 202.176 123.255 ;
     RECT  2.16 123.525 202.176 123.795 ;
     RECT  2.16 124.065 202.176 124.335 ;
     RECT  2.16 124.605 202.176 124.875 ;
     RECT  2.16 125.145 202.176 125.415 ;
     RECT  2.16 125.685 202.176 125.955 ;
     RECT  2.16 126.225 202.176 126.495 ;
     RECT  2.16 126.765 202.176 127.035 ;
     RECT  2.16 127.305 202.176 127.44 ;
     RECT  2.16 127.44 53.244 127.575 ;
     RECT  152.172 127.44 202.176 127.575 ;
     RECT  2.16 127.845 53.244 128.115 ;
     RECT  152.172 127.845 202.176 128.115 ;
     RECT  2.16 128.385 53.244 128.655 ;
     RECT  152.172 128.385 202.176 128.655 ;
     RECT  2.16 128.925 53.244 129.195 ;
     RECT  152.172 128.925 202.176 129.195 ;
     RECT  2.16 129.465 53.244 129.735 ;
     RECT  152.172 129.465 202.176 129.735 ;
     RECT  2.16 130.005 53.244 130.275 ;
     RECT  152.172 130.005 202.176 130.275 ;
     RECT  2.16 130.545 53.244 130.815 ;
     RECT  152.172 130.545 202.176 130.815 ;
     RECT  2.16 131.085 53.244 131.355 ;
     RECT  152.172 131.085 202.176 131.355 ;
     RECT  2.16 131.625 53.244 131.895 ;
     RECT  152.172 131.625 202.176 131.895 ;
     RECT  2.16 132.165 53.244 132.435 ;
     RECT  152.172 132.165 202.176 132.435 ;
     RECT  2.16 132.705 53.244 132.975 ;
     RECT  152.172 132.705 202.176 132.975 ;
     RECT  2.16 133.245 53.244 133.515 ;
     RECT  152.172 133.245 202.176 133.515 ;
     RECT  2.16 133.785 53.244 134.055 ;
     RECT  152.172 133.785 202.176 134.055 ;
     RECT  2.16 134.325 53.244 134.595 ;
     RECT  152.172 134.325 202.176 134.595 ;
     RECT  2.16 134.865 53.244 135.135 ;
     RECT  152.172 134.865 202.176 135.135 ;
     RECT  2.16 135.405 53.244 135.675 ;
     RECT  152.172 135.405 202.176 135.675 ;
     RECT  2.16 135.945 53.244 136.215 ;
     RECT  152.172 135.945 202.176 136.215 ;
     RECT  2.16 136.485 53.244 136.755 ;
     RECT  152.172 136.485 202.176 136.755 ;
     RECT  2.16 137.025 53.244 137.295 ;
     RECT  152.172 137.025 202.176 137.295 ;
     RECT  2.16 137.565 53.244 137.835 ;
     RECT  152.172 137.565 202.176 137.835 ;
     RECT  2.16 138.105 53.244 138.375 ;
     RECT  152.172 138.105 202.176 138.375 ;
     RECT  2.16 138.645 53.244 138.915 ;
     RECT  152.172 138.645 202.176 138.915 ;
     RECT  2.16 139.185 53.244 139.455 ;
     RECT  152.172 139.185 202.176 139.455 ;
     RECT  2.16 139.725 53.244 139.995 ;
     RECT  152.172 139.725 202.176 139.995 ;
     RECT  2.16 140.265 53.244 140.535 ;
     RECT  152.172 140.265 202.176 140.535 ;
     RECT  2.16 140.805 53.244 141.075 ;
     RECT  152.172 140.805 202.176 141.075 ;
     RECT  2.16 141.345 53.244 141.615 ;
     RECT  152.172 141.345 202.176 141.615 ;
     RECT  2.16 141.885 53.244 142.155 ;
     RECT  152.172 141.885 202.176 142.155 ;
     RECT  2.16 142.425 53.244 142.695 ;
     RECT  152.172 142.425 202.176 142.695 ;
     RECT  2.16 142.965 53.244 143.235 ;
     RECT  152.172 142.965 202.176 143.235 ;
     RECT  2.16 143.505 53.244 143.775 ;
     RECT  152.172 143.505 202.176 143.775 ;
     RECT  2.16 144.045 53.244 144.315 ;
     RECT  152.172 144.045 202.176 144.315 ;
     RECT  2.16 144.585 53.244 144.855 ;
     RECT  152.172 144.585 202.176 144.855 ;
     RECT  2.16 145.125 53.244 145.395 ;
     RECT  152.172 145.125 202.176 145.395 ;
     RECT  2.16 145.665 53.244 145.935 ;
     RECT  152.172 145.665 202.176 145.935 ;
     RECT  2.16 146.205 53.244 146.475 ;
     RECT  152.172 146.205 202.176 146.475 ;
     RECT  2.16 146.745 53.244 147.015 ;
     RECT  152.172 146.745 202.176 147.015 ;
     RECT  2.16 147.285 53.244 147.555 ;
     RECT  152.172 147.285 202.176 147.555 ;
     RECT  2.16 147.825 53.244 148.095 ;
     RECT  152.172 147.825 202.176 148.095 ;
     RECT  2.16 148.365 53.244 148.635 ;
     RECT  152.172 148.365 202.176 148.635 ;
     RECT  2.16 148.905 53.244 149.175 ;
     RECT  152.172 148.905 202.176 149.175 ;
     RECT  2.16 149.445 53.244 149.715 ;
     RECT  152.172 149.445 202.176 149.715 ;
     RECT  2.16 149.985 53.244 150.255 ;
     RECT  152.172 149.985 202.176 150.255 ;
     RECT  2.16 150.525 53.244 150.795 ;
     RECT  152.172 150.525 202.176 150.795 ;
     RECT  2.16 151.065 53.244 151.335 ;
     RECT  152.172 151.065 202.176 151.335 ;
     RECT  2.16 151.605 53.244 151.875 ;
     RECT  152.172 151.605 202.176 151.875 ;
     RECT  2.16 152.145 53.244 152.415 ;
     RECT  152.172 152.145 202.176 152.415 ;
     RECT  2.16 152.685 53.244 152.955 ;
     RECT  152.172 152.685 202.176 152.955 ;
     RECT  2.16 153.225 53.244 153.495 ;
     RECT  152.172 153.225 202.176 153.495 ;
     RECT  2.16 153.765 53.244 154.035 ;
     RECT  152.172 153.765 202.176 154.035 ;
     RECT  2.16 154.305 53.244 154.575 ;
     RECT  152.172 154.305 202.176 154.575 ;
     RECT  2.16 154.845 53.244 155.115 ;
     RECT  152.172 154.845 202.176 155.115 ;
     RECT  2.16 155.385 53.244 155.655 ;
     RECT  152.172 155.385 202.176 155.655 ;
     RECT  2.16 155.925 53.244 156.195 ;
     RECT  152.172 155.925 202.176 156.195 ;
     RECT  2.16 156.465 53.244 156.735 ;
     RECT  152.172 156.465 202.176 156.735 ;
     RECT  2.16 157.005 53.244 157.275 ;
     RECT  152.172 157.005 202.176 157.275 ;
     RECT  2.16 157.545 53.244 157.815 ;
     RECT  152.172 157.545 202.176 157.815 ;
     RECT  2.16 158.085 53.244 158.355 ;
     RECT  152.172 158.085 202.176 158.355 ;
     RECT  2.16 158.625 53.244 158.895 ;
     RECT  152.172 158.625 202.176 158.895 ;
     RECT  2.16 159.165 53.244 159.435 ;
     RECT  152.172 159.165 202.176 159.435 ;
     RECT  2.16 159.705 53.244 159.975 ;
     RECT  152.172 159.705 202.176 159.975 ;
     RECT  2.16 160.245 53.244 160.515 ;
     RECT  152.172 160.245 202.176 160.515 ;
     RECT  2.16 160.785 53.244 161.055 ;
     RECT  152.172 160.785 202.176 161.055 ;
     RECT  2.16 161.325 53.244 161.595 ;
     RECT  152.172 161.325 202.176 161.595 ;
     RECT  2.16 161.865 53.244 162.135 ;
     RECT  152.172 161.865 202.176 162.135 ;
     RECT  2.16 162.405 53.244 162.675 ;
     RECT  152.172 162.405 202.176 162.675 ;
     RECT  2.16 162.945 53.244 163.215 ;
     RECT  152.172 162.945 202.176 163.215 ;
     RECT  2.16 163.485 53.244 163.755 ;
     RECT  152.172 163.485 202.176 163.755 ;
     RECT  2.16 164.025 53.244 164.295 ;
     RECT  152.172 164.025 202.176 164.295 ;
     RECT  2.16 164.565 53.244 164.835 ;
     RECT  152.172 164.565 202.176 164.835 ;
     RECT  2.16 165.105 53.244 165.375 ;
     RECT  152.172 165.105 202.176 165.375 ;
     RECT  2.16 165.645 53.244 165.915 ;
     RECT  152.172 165.645 202.176 165.915 ;
     RECT  2.16 166.185 53.244 166.455 ;
     RECT  152.172 166.185 202.176 166.455 ;
     RECT  2.16 166.725 53.244 166.995 ;
     RECT  152.172 166.725 202.176 166.995 ;
     RECT  2.16 167.265 53.244 167.535 ;
     RECT  152.172 167.265 202.176 167.535 ;
     RECT  2.16 167.805 53.244 168.075 ;
     RECT  152.172 167.805 202.176 168.075 ;
     RECT  2.16 168.345 53.244 168.615 ;
     RECT  152.172 168.345 202.176 168.615 ;
     RECT  2.16 168.885 53.244 169.155 ;
     RECT  152.172 168.885 202.176 169.155 ;
     RECT  2.16 169.425 53.244 169.695 ;
     RECT  152.172 169.425 202.176 169.695 ;
     RECT  2.16 169.965 53.244 170.235 ;
     RECT  152.172 169.965 202.176 170.235 ;
     RECT  2.16 170.505 53.244 170.775 ;
     RECT  152.172 170.505 202.176 170.775 ;
     RECT  2.16 171.045 53.244 171.315 ;
     RECT  152.172 171.045 202.176 171.315 ;
     RECT  2.16 171.585 53.244 171.855 ;
     RECT  152.172 171.585 202.176 171.855 ;
     RECT  2.16 172.125 53.244 172.395 ;
     RECT  152.172 172.125 202.176 172.395 ;
     RECT  2.16 172.665 53.244 172.8 ;
     RECT  152.172 172.665 202.176 172.8 ;
     RECT  2.16 172.8 202.176 172.935 ;
     RECT  2.16 173.205 202.176 173.475 ;
     RECT  2.16 173.745 202.176 174.015 ;
     RECT  2.16 174.285 202.176 174.555 ;
     RECT  2.16 174.825 202.176 175.095 ;
     RECT  2.16 175.365 202.176 175.635 ;
     RECT  2.16 175.905 202.176 176.175 ;
     RECT  2.16 176.445 202.176 176.715 ;
     RECT  2.16 176.985 202.176 177.255 ;
     RECT  2.16 177.525 202.176 177.795 ;
     RECT  2.16 178.065 202.176 178.335 ;
     RECT  2.16 178.605 202.176 178.875 ;
     RECT  2.16 179.145 202.176 179.415 ;
     RECT  2.16 179.685 202.176 179.955 ;
     RECT  2.16 180.225 202.176 180.495 ;
     RECT  2.16 180.765 202.176 181.035 ;
     RECT  2.16 181.305 202.176 181.575 ;
     RECT  2.16 181.845 202.176 182.115 ;
     RECT  2.16 182.385 202.176 182.655 ;
     RECT  2.16 182.925 202.176 183.195 ;
     RECT  2.16 183.465 202.176 183.735 ;
     RECT  2.16 184.005 202.176 184.275 ;
     RECT  2.16 184.545 202.176 184.815 ;
     RECT  2.16 185.085 202.176 185.355 ;
     RECT  2.16 185.625 202.176 185.895 ;
     RECT  2.16 186.165 202.176 186.435 ;
     RECT  2.16 186.705 202.176 186.975 ;
     RECT  2.16 187.245 202.176 187.515 ;
     RECT  2.16 187.785 202.176 188.055 ;
     RECT  2.16 188.325 202.176 188.595 ;
     RECT  2.16 188.865 202.176 189.135 ;
     RECT  2.16 189.405 202.176 189.675 ;
     RECT  2.16 189.945 202.176 190.215 ;
     RECT  2.16 190.485 202.176 190.755 ;
     RECT  2.16 191.025 202.176 191.295 ;
     RECT  2.16 191.565 202.176 191.835 ;
     RECT  2.16 192.105 202.176 192.24 ;
    LAYER RVTP ;
     RECT  2.16 2.295 202.176 2.565 ;
     RECT  2.16 2.835 202.176 3.105 ;
     RECT  2.16 3.375 202.176 3.645 ;
     RECT  2.16 3.915 202.176 4.185 ;
     RECT  2.16 4.455 202.176 4.725 ;
     RECT  2.16 4.995 202.176 5.265 ;
     RECT  2.16 5.535 202.176 5.805 ;
     RECT  2.16 6.075 202.176 6.345 ;
     RECT  2.16 6.615 202.176 6.885 ;
     RECT  2.16 7.155 202.176 7.425 ;
     RECT  2.16 7.695 202.176 7.965 ;
     RECT  2.16 8.235 202.176 8.505 ;
     RECT  2.16 8.775 202.176 9.045 ;
     RECT  2.16 9.315 202.176 9.585 ;
     RECT  2.16 9.855 202.176 10.125 ;
     RECT  2.16 10.395 202.176 10.665 ;
     RECT  2.16 10.935 202.176 11.205 ;
     RECT  2.16 11.475 202.176 11.745 ;
     RECT  2.16 12.015 202.176 12.285 ;
     RECT  2.16 12.555 202.176 12.825 ;
     RECT  2.16 13.095 202.176 13.365 ;
     RECT  2.16 13.635 202.176 13.905 ;
     RECT  2.16 14.175 202.176 14.445 ;
     RECT  2.16 14.715 202.176 14.985 ;
     RECT  2.16 15.255 202.176 15.525 ;
     RECT  2.16 15.795 202.176 16.065 ;
     RECT  2.16 16.335 202.176 16.605 ;
     RECT  2.16 16.875 202.176 17.145 ;
     RECT  2.16 17.415 202.176 17.685 ;
     RECT  2.16 17.955 202.176 18.225 ;
     RECT  2.16 18.495 202.176 18.765 ;
     RECT  2.16 19.035 202.176 19.305 ;
     RECT  2.16 19.575 202.176 19.845 ;
     RECT  2.16 20.115 202.176 20.385 ;
     RECT  2.16 20.655 202.176 20.925 ;
     RECT  2.16 21.195 202.176 21.465 ;
     RECT  2.16 21.735 202.176 22.005 ;
     RECT  2.16 22.275 202.176 22.545 ;
     RECT  2.16 22.815 202.176 23.085 ;
     RECT  2.16 23.355 202.176 23.625 ;
     RECT  2.16 23.895 202.176 24.165 ;
     RECT  2.16 24.435 202.176 24.705 ;
     RECT  2.16 24.975 202.176 25.245 ;
     RECT  2.16 25.515 202.176 25.785 ;
     RECT  2.16 26.055 202.176 26.325 ;
     RECT  2.16 26.595 202.176 26.865 ;
     RECT  2.16 27.135 202.176 27.405 ;
     RECT  2.16 27.675 202.176 27.945 ;
     RECT  2.16 28.215 202.176 28.485 ;
     RECT  2.16 28.755 202.176 29.025 ;
     RECT  2.16 29.295 202.176 29.565 ;
     RECT  2.16 29.835 202.176 30.105 ;
     RECT  2.16 30.375 202.176 30.645 ;
     RECT  2.16 30.915 202.176 31.185 ;
     RECT  2.16 31.455 202.176 31.725 ;
     RECT  2.16 31.995 202.176 32.265 ;
     RECT  2.16 32.535 202.176 32.805 ;
     RECT  2.16 33.075 202.176 33.345 ;
     RECT  2.16 33.615 202.176 33.885 ;
     RECT  2.16 34.155 202.176 34.425 ;
     RECT  2.16 34.695 202.176 34.965 ;
     RECT  2.16 35.235 202.176 35.505 ;
     RECT  2.16 35.775 202.176 36.045 ;
     RECT  2.16 36.315 202.176 36.585 ;
     RECT  2.16 36.855 202.176 37.125 ;
     RECT  2.16 37.395 202.176 37.665 ;
     RECT  2.16 37.935 202.176 38.205 ;
     RECT  2.16 38.475 202.176 38.745 ;
     RECT  2.16 39.015 202.176 39.285 ;
     RECT  2.16 39.555 202.176 39.825 ;
     RECT  2.16 40.095 202.176 40.365 ;
     RECT  2.16 40.635 202.176 40.905 ;
     RECT  2.16 41.175 202.176 41.445 ;
     RECT  2.16 41.715 202.176 41.985 ;
     RECT  2.16 42.255 202.176 42.525 ;
     RECT  2.16 42.795 202.176 43.065 ;
     RECT  2.16 43.335 202.176 43.605 ;
     RECT  2.16 43.875 202.176 44.145 ;
     RECT  2.16 44.415 202.176 44.685 ;
     RECT  2.16 44.955 202.176 45.225 ;
     RECT  2.16 45.495 202.176 45.765 ;
     RECT  2.16 46.035 202.176 46.305 ;
     RECT  2.16 46.575 202.176 46.845 ;
     RECT  2.16 47.115 202.176 47.385 ;
     RECT  2.16 47.655 202.176 47.925 ;
     RECT  2.16 48.195 202.176 48.465 ;
     RECT  2.16 48.735 202.176 49.005 ;
     RECT  2.16 49.275 202.176 49.545 ;
     RECT  2.16 49.815 202.176 50.085 ;
     RECT  2.16 50.355 202.176 50.625 ;
     RECT  2.16 50.895 202.176 51.165 ;
     RECT  2.16 51.435 202.176 51.705 ;
     RECT  2.16 51.975 202.176 52.245 ;
     RECT  2.16 52.515 202.176 52.785 ;
     RECT  2.16 53.055 202.176 53.325 ;
     RECT  2.16 53.595 202.176 53.865 ;
     RECT  2.16 54.135 202.176 54.405 ;
     RECT  2.16 54.675 202.176 54.945 ;
     RECT  2.16 55.215 202.176 55.485 ;
     RECT  2.16 55.755 202.176 56.025 ;
     RECT  2.16 56.295 53.244 56.565 ;
     RECT  152.172 56.295 202.176 56.565 ;
     RECT  2.16 56.835 53.244 57.105 ;
     RECT  152.172 56.835 202.176 57.105 ;
     RECT  2.16 57.375 53.244 57.645 ;
     RECT  152.172 57.375 202.176 57.645 ;
     RECT  2.16 57.915 53.244 58.185 ;
     RECT  152.172 57.915 202.176 58.185 ;
     RECT  2.16 58.455 53.244 58.725 ;
     RECT  152.172 58.455 202.176 58.725 ;
     RECT  2.16 58.995 53.244 59.265 ;
     RECT  152.172 58.995 202.176 59.265 ;
     RECT  2.16 59.535 53.244 59.805 ;
     RECT  152.172 59.535 202.176 59.805 ;
     RECT  2.16 60.075 53.244 60.345 ;
     RECT  152.172 60.075 202.176 60.345 ;
     RECT  2.16 60.615 53.244 60.885 ;
     RECT  152.172 60.615 202.176 60.885 ;
     RECT  2.16 61.155 53.244 61.425 ;
     RECT  152.172 61.155 202.176 61.425 ;
     RECT  2.16 61.695 53.244 61.965 ;
     RECT  152.172 61.695 202.176 61.965 ;
     RECT  2.16 62.235 53.244 62.505 ;
     RECT  152.172 62.235 202.176 62.505 ;
     RECT  2.16 62.775 53.244 63.045 ;
     RECT  152.172 62.775 202.176 63.045 ;
     RECT  2.16 63.315 53.244 63.585 ;
     RECT  152.172 63.315 202.176 63.585 ;
     RECT  2.16 63.855 53.244 64.125 ;
     RECT  152.172 63.855 202.176 64.125 ;
     RECT  2.16 64.395 53.244 64.665 ;
     RECT  152.172 64.395 202.176 64.665 ;
     RECT  2.16 64.935 53.244 65.205 ;
     RECT  152.172 64.935 202.176 65.205 ;
     RECT  2.16 65.475 53.244 65.745 ;
     RECT  152.172 65.475 202.176 65.745 ;
     RECT  2.16 66.015 53.244 66.285 ;
     RECT  152.172 66.015 202.176 66.285 ;
     RECT  2.16 66.555 53.244 66.825 ;
     RECT  152.172 66.555 202.176 66.825 ;
     RECT  2.16 67.095 53.244 67.365 ;
     RECT  152.172 67.095 202.176 67.365 ;
     RECT  2.16 67.635 53.244 67.905 ;
     RECT  152.172 67.635 202.176 67.905 ;
     RECT  2.16 68.175 53.244 68.445 ;
     RECT  152.172 68.175 202.176 68.445 ;
     RECT  2.16 68.715 53.244 68.985 ;
     RECT  152.172 68.715 202.176 68.985 ;
     RECT  2.16 69.255 53.244 69.525 ;
     RECT  152.172 69.255 202.176 69.525 ;
     RECT  2.16 69.795 53.244 70.065 ;
     RECT  152.172 69.795 202.176 70.065 ;
     RECT  2.16 70.335 53.244 70.605 ;
     RECT  152.172 70.335 202.176 70.605 ;
     RECT  2.16 70.875 53.244 71.145 ;
     RECT  152.172 70.875 202.176 71.145 ;
     RECT  2.16 71.415 53.244 71.685 ;
     RECT  152.172 71.415 202.176 71.685 ;
     RECT  2.16 71.955 53.244 72.225 ;
     RECT  152.172 71.955 202.176 72.225 ;
     RECT  2.16 72.495 53.244 72.765 ;
     RECT  152.172 72.495 202.176 72.765 ;
     RECT  2.16 73.035 53.244 73.305 ;
     RECT  152.172 73.035 202.176 73.305 ;
     RECT  2.16 73.575 53.244 73.845 ;
     RECT  152.172 73.575 202.176 73.845 ;
     RECT  2.16 74.115 53.244 74.385 ;
     RECT  152.172 74.115 202.176 74.385 ;
     RECT  2.16 74.655 53.244 74.925 ;
     RECT  152.172 74.655 202.176 74.925 ;
     RECT  2.16 75.195 53.244 75.465 ;
     RECT  152.172 75.195 202.176 75.465 ;
     RECT  2.16 75.735 53.244 76.005 ;
     RECT  152.172 75.735 202.176 76.005 ;
     RECT  2.16 76.275 53.244 76.545 ;
     RECT  152.172 76.275 202.176 76.545 ;
     RECT  2.16 76.815 53.244 77.085 ;
     RECT  152.172 76.815 202.176 77.085 ;
     RECT  2.16 77.355 53.244 77.625 ;
     RECT  152.172 77.355 202.176 77.625 ;
     RECT  2.16 77.895 53.244 78.165 ;
     RECT  152.172 77.895 202.176 78.165 ;
     RECT  2.16 78.435 53.244 78.705 ;
     RECT  152.172 78.435 202.176 78.705 ;
     RECT  2.16 78.975 53.244 79.245 ;
     RECT  152.172 78.975 202.176 79.245 ;
     RECT  2.16 79.515 53.244 79.785 ;
     RECT  152.172 79.515 202.176 79.785 ;
     RECT  2.16 80.055 53.244 80.325 ;
     RECT  152.172 80.055 202.176 80.325 ;
     RECT  2.16 80.595 53.244 80.865 ;
     RECT  152.172 80.595 202.176 80.865 ;
     RECT  2.16 81.135 53.244 81.405 ;
     RECT  152.172 81.135 202.176 81.405 ;
     RECT  2.16 81.675 53.244 81.945 ;
     RECT  152.172 81.675 202.176 81.945 ;
     RECT  2.16 82.215 53.244 82.485 ;
     RECT  152.172 82.215 202.176 82.485 ;
     RECT  2.16 82.755 53.244 83.025 ;
     RECT  152.172 82.755 202.176 83.025 ;
     RECT  2.16 83.295 53.244 83.565 ;
     RECT  152.172 83.295 202.176 83.565 ;
     RECT  2.16 83.835 53.244 84.105 ;
     RECT  152.172 83.835 202.176 84.105 ;
     RECT  2.16 84.375 53.244 84.645 ;
     RECT  152.172 84.375 202.176 84.645 ;
     RECT  2.16 84.915 53.244 85.185 ;
     RECT  152.172 84.915 202.176 85.185 ;
     RECT  2.16 85.455 53.244 85.725 ;
     RECT  152.172 85.455 202.176 85.725 ;
     RECT  2.16 85.995 53.244 86.265 ;
     RECT  152.172 85.995 202.176 86.265 ;
     RECT  2.16 86.535 53.244 86.805 ;
     RECT  152.172 86.535 202.176 86.805 ;
     RECT  2.16 87.075 53.244 87.345 ;
     RECT  152.172 87.075 202.176 87.345 ;
     RECT  2.16 87.615 53.244 87.885 ;
     RECT  152.172 87.615 202.176 87.885 ;
     RECT  2.16 88.155 53.244 88.425 ;
     RECT  152.172 88.155 202.176 88.425 ;
     RECT  2.16 88.695 53.244 88.965 ;
     RECT  152.172 88.695 202.176 88.965 ;
     RECT  2.16 89.235 53.244 89.505 ;
     RECT  152.172 89.235 202.176 89.505 ;
     RECT  2.16 89.775 53.244 90.045 ;
     RECT  152.172 89.775 202.176 90.045 ;
     RECT  2.16 90.315 53.244 90.585 ;
     RECT  152.172 90.315 202.176 90.585 ;
     RECT  2.16 90.855 53.244 91.125 ;
     RECT  152.172 90.855 202.176 91.125 ;
     RECT  2.16 91.395 53.244 91.665 ;
     RECT  152.172 91.395 202.176 91.665 ;
     RECT  2.16 91.935 53.244 92.205 ;
     RECT  152.172 91.935 202.176 92.205 ;
     RECT  2.16 92.475 53.244 92.745 ;
     RECT  152.172 92.475 202.176 92.745 ;
     RECT  2.16 93.015 53.244 93.285 ;
     RECT  152.172 93.015 202.176 93.285 ;
     RECT  2.16 93.555 53.244 93.825 ;
     RECT  152.172 93.555 202.176 93.825 ;
     RECT  2.16 94.095 53.244 94.365 ;
     RECT  152.172 94.095 202.176 94.365 ;
     RECT  2.16 94.635 53.244 94.905 ;
     RECT  152.172 94.635 202.176 94.905 ;
     RECT  2.16 95.175 53.244 95.445 ;
     RECT  152.172 95.175 202.176 95.445 ;
     RECT  2.16 95.715 53.244 95.985 ;
     RECT  152.172 95.715 202.176 95.985 ;
     RECT  2.16 96.255 53.244 96.525 ;
     RECT  152.172 96.255 202.176 96.525 ;
     RECT  2.16 96.795 53.244 97.065 ;
     RECT  152.172 96.795 202.176 97.065 ;
     RECT  2.16 97.335 53.244 97.605 ;
     RECT  152.172 97.335 202.176 97.605 ;
     RECT  2.16 97.875 53.244 98.145 ;
     RECT  152.172 97.875 202.176 98.145 ;
     RECT  2.16 98.415 53.244 98.685 ;
     RECT  152.172 98.415 202.176 98.685 ;
     RECT  2.16 98.955 53.244 99.225 ;
     RECT  152.172 98.955 202.176 99.225 ;
     RECT  2.16 99.495 53.244 99.765 ;
     RECT  152.172 99.495 202.176 99.765 ;
     RECT  2.16 100.035 53.244 100.305 ;
     RECT  152.172 100.035 202.176 100.305 ;
     RECT  2.16 100.575 53.244 100.845 ;
     RECT  152.172 100.575 202.176 100.845 ;
     RECT  2.16 101.115 53.244 101.385 ;
     RECT  152.172 101.115 202.176 101.385 ;
     RECT  2.16 101.655 202.176 101.925 ;
     RECT  2.16 102.195 202.176 102.465 ;
     RECT  2.16 102.735 202.176 103.005 ;
     RECT  2.16 103.275 202.176 103.545 ;
     RECT  2.16 103.815 202.176 104.085 ;
     RECT  2.16 104.355 202.176 104.625 ;
     RECT  2.16 104.895 202.176 105.165 ;
     RECT  2.16 105.435 202.176 105.705 ;
     RECT  2.16 105.975 202.176 106.245 ;
     RECT  2.16 106.515 202.176 106.785 ;
     RECT  2.16 107.055 202.176 107.325 ;
     RECT  2.16 107.595 202.176 107.865 ;
     RECT  2.16 108.135 202.176 108.405 ;
     RECT  2.16 108.675 202.176 108.945 ;
     RECT  2.16 109.215 202.176 109.485 ;
     RECT  2.16 109.755 202.176 110.025 ;
     RECT  2.16 110.295 202.176 110.565 ;
     RECT  2.16 110.835 202.176 111.105 ;
     RECT  2.16 111.375 202.176 111.645 ;
     RECT  2.16 111.915 202.176 112.185 ;
     RECT  2.16 112.455 202.176 112.725 ;
     RECT  2.16 112.995 202.176 113.265 ;
     RECT  2.16 113.535 202.176 113.805 ;
     RECT  2.16 114.075 202.176 114.345 ;
     RECT  2.16 114.615 202.176 114.885 ;
     RECT  2.16 115.155 202.176 115.425 ;
     RECT  2.16 115.695 202.176 115.965 ;
     RECT  2.16 116.235 202.176 116.505 ;
     RECT  2.16 116.775 202.176 117.045 ;
     RECT  2.16 117.315 202.176 117.585 ;
     RECT  2.16 117.855 202.176 118.125 ;
     RECT  2.16 118.395 202.176 118.665 ;
     RECT  2.16 118.935 202.176 119.205 ;
     RECT  2.16 119.475 202.176 119.745 ;
     RECT  2.16 120.015 202.176 120.285 ;
     RECT  2.16 120.555 202.176 120.825 ;
     RECT  2.16 121.095 202.176 121.365 ;
     RECT  2.16 121.635 202.176 121.905 ;
     RECT  2.16 122.175 202.176 122.445 ;
     RECT  2.16 122.715 202.176 122.985 ;
     RECT  2.16 123.255 202.176 123.525 ;
     RECT  2.16 123.795 202.176 124.065 ;
     RECT  2.16 124.335 202.176 124.605 ;
     RECT  2.16 124.875 202.176 125.145 ;
     RECT  2.16 125.415 202.176 125.685 ;
     RECT  2.16 125.955 202.176 126.225 ;
     RECT  2.16 126.495 202.176 126.765 ;
     RECT  2.16 127.035 202.176 127.305 ;
     RECT  2.16 127.575 53.244 127.845 ;
     RECT  152.172 127.575 202.176 127.845 ;
     RECT  2.16 128.115 53.244 128.385 ;
     RECT  152.172 128.115 202.176 128.385 ;
     RECT  2.16 128.655 53.244 128.925 ;
     RECT  152.172 128.655 202.176 128.925 ;
     RECT  2.16 129.195 53.244 129.465 ;
     RECT  152.172 129.195 202.176 129.465 ;
     RECT  2.16 129.735 53.244 130.005 ;
     RECT  152.172 129.735 202.176 130.005 ;
     RECT  2.16 130.275 53.244 130.545 ;
     RECT  152.172 130.275 202.176 130.545 ;
     RECT  2.16 130.815 53.244 131.085 ;
     RECT  152.172 130.815 202.176 131.085 ;
     RECT  2.16 131.355 53.244 131.625 ;
     RECT  152.172 131.355 202.176 131.625 ;
     RECT  2.16 131.895 53.244 132.165 ;
     RECT  152.172 131.895 202.176 132.165 ;
     RECT  2.16 132.435 53.244 132.705 ;
     RECT  152.172 132.435 202.176 132.705 ;
     RECT  2.16 132.975 53.244 133.245 ;
     RECT  152.172 132.975 202.176 133.245 ;
     RECT  2.16 133.515 53.244 133.785 ;
     RECT  152.172 133.515 202.176 133.785 ;
     RECT  2.16 134.055 53.244 134.325 ;
     RECT  152.172 134.055 202.176 134.325 ;
     RECT  2.16 134.595 53.244 134.865 ;
     RECT  152.172 134.595 202.176 134.865 ;
     RECT  2.16 135.135 53.244 135.405 ;
     RECT  152.172 135.135 202.176 135.405 ;
     RECT  2.16 135.675 53.244 135.945 ;
     RECT  152.172 135.675 202.176 135.945 ;
     RECT  2.16 136.215 53.244 136.485 ;
     RECT  152.172 136.215 202.176 136.485 ;
     RECT  2.16 136.755 53.244 137.025 ;
     RECT  152.172 136.755 202.176 137.025 ;
     RECT  2.16 137.295 53.244 137.565 ;
     RECT  152.172 137.295 202.176 137.565 ;
     RECT  2.16 137.835 53.244 138.105 ;
     RECT  152.172 137.835 202.176 138.105 ;
     RECT  2.16 138.375 53.244 138.645 ;
     RECT  152.172 138.375 202.176 138.645 ;
     RECT  2.16 138.915 53.244 139.185 ;
     RECT  152.172 138.915 202.176 139.185 ;
     RECT  2.16 139.455 53.244 139.725 ;
     RECT  152.172 139.455 202.176 139.725 ;
     RECT  2.16 139.995 53.244 140.265 ;
     RECT  152.172 139.995 202.176 140.265 ;
     RECT  2.16 140.535 53.244 140.805 ;
     RECT  152.172 140.535 202.176 140.805 ;
     RECT  2.16 141.075 53.244 141.345 ;
     RECT  152.172 141.075 202.176 141.345 ;
     RECT  2.16 141.615 53.244 141.885 ;
     RECT  152.172 141.615 202.176 141.885 ;
     RECT  2.16 142.155 53.244 142.425 ;
     RECT  152.172 142.155 202.176 142.425 ;
     RECT  2.16 142.695 53.244 142.965 ;
     RECT  152.172 142.695 202.176 142.965 ;
     RECT  2.16 143.235 53.244 143.505 ;
     RECT  152.172 143.235 202.176 143.505 ;
     RECT  2.16 143.775 53.244 144.045 ;
     RECT  152.172 143.775 202.176 144.045 ;
     RECT  2.16 144.315 53.244 144.585 ;
     RECT  152.172 144.315 202.176 144.585 ;
     RECT  2.16 144.855 53.244 145.125 ;
     RECT  152.172 144.855 202.176 145.125 ;
     RECT  2.16 145.395 53.244 145.665 ;
     RECT  152.172 145.395 202.176 145.665 ;
     RECT  2.16 145.935 53.244 146.205 ;
     RECT  152.172 145.935 202.176 146.205 ;
     RECT  2.16 146.475 53.244 146.745 ;
     RECT  152.172 146.475 202.176 146.745 ;
     RECT  2.16 147.015 53.244 147.285 ;
     RECT  152.172 147.015 202.176 147.285 ;
     RECT  2.16 147.555 53.244 147.825 ;
     RECT  152.172 147.555 202.176 147.825 ;
     RECT  2.16 148.095 53.244 148.365 ;
     RECT  152.172 148.095 202.176 148.365 ;
     RECT  2.16 148.635 53.244 148.905 ;
     RECT  152.172 148.635 202.176 148.905 ;
     RECT  2.16 149.175 53.244 149.445 ;
     RECT  152.172 149.175 202.176 149.445 ;
     RECT  2.16 149.715 53.244 149.985 ;
     RECT  152.172 149.715 202.176 149.985 ;
     RECT  2.16 150.255 53.244 150.525 ;
     RECT  152.172 150.255 202.176 150.525 ;
     RECT  2.16 150.795 53.244 151.065 ;
     RECT  152.172 150.795 202.176 151.065 ;
     RECT  2.16 151.335 53.244 151.605 ;
     RECT  152.172 151.335 202.176 151.605 ;
     RECT  2.16 151.875 53.244 152.145 ;
     RECT  152.172 151.875 202.176 152.145 ;
     RECT  2.16 152.415 53.244 152.685 ;
     RECT  152.172 152.415 202.176 152.685 ;
     RECT  2.16 152.955 53.244 153.225 ;
     RECT  152.172 152.955 202.176 153.225 ;
     RECT  2.16 153.495 53.244 153.765 ;
     RECT  152.172 153.495 202.176 153.765 ;
     RECT  2.16 154.035 53.244 154.305 ;
     RECT  152.172 154.035 202.176 154.305 ;
     RECT  2.16 154.575 53.244 154.845 ;
     RECT  152.172 154.575 202.176 154.845 ;
     RECT  2.16 155.115 53.244 155.385 ;
     RECT  152.172 155.115 202.176 155.385 ;
     RECT  2.16 155.655 53.244 155.925 ;
     RECT  152.172 155.655 202.176 155.925 ;
     RECT  2.16 156.195 53.244 156.465 ;
     RECT  152.172 156.195 202.176 156.465 ;
     RECT  2.16 156.735 53.244 157.005 ;
     RECT  152.172 156.735 202.176 157.005 ;
     RECT  2.16 157.275 53.244 157.545 ;
     RECT  152.172 157.275 202.176 157.545 ;
     RECT  2.16 157.815 53.244 158.085 ;
     RECT  152.172 157.815 202.176 158.085 ;
     RECT  2.16 158.355 53.244 158.625 ;
     RECT  152.172 158.355 202.176 158.625 ;
     RECT  2.16 158.895 53.244 159.165 ;
     RECT  152.172 158.895 202.176 159.165 ;
     RECT  2.16 159.435 53.244 159.705 ;
     RECT  152.172 159.435 202.176 159.705 ;
     RECT  2.16 159.975 53.244 160.245 ;
     RECT  152.172 159.975 202.176 160.245 ;
     RECT  2.16 160.515 53.244 160.785 ;
     RECT  152.172 160.515 202.176 160.785 ;
     RECT  2.16 161.055 53.244 161.325 ;
     RECT  152.172 161.055 202.176 161.325 ;
     RECT  2.16 161.595 53.244 161.865 ;
     RECT  152.172 161.595 202.176 161.865 ;
     RECT  2.16 162.135 53.244 162.405 ;
     RECT  152.172 162.135 202.176 162.405 ;
     RECT  2.16 162.675 53.244 162.945 ;
     RECT  152.172 162.675 202.176 162.945 ;
     RECT  2.16 163.215 53.244 163.485 ;
     RECT  152.172 163.215 202.176 163.485 ;
     RECT  2.16 163.755 53.244 164.025 ;
     RECT  152.172 163.755 202.176 164.025 ;
     RECT  2.16 164.295 53.244 164.565 ;
     RECT  152.172 164.295 202.176 164.565 ;
     RECT  2.16 164.835 53.244 165.105 ;
     RECT  152.172 164.835 202.176 165.105 ;
     RECT  2.16 165.375 53.244 165.645 ;
     RECT  152.172 165.375 202.176 165.645 ;
     RECT  2.16 165.915 53.244 166.185 ;
     RECT  152.172 165.915 202.176 166.185 ;
     RECT  2.16 166.455 53.244 166.725 ;
     RECT  152.172 166.455 202.176 166.725 ;
     RECT  2.16 166.995 53.244 167.265 ;
     RECT  152.172 166.995 202.176 167.265 ;
     RECT  2.16 167.535 53.244 167.805 ;
     RECT  152.172 167.535 202.176 167.805 ;
     RECT  2.16 168.075 53.244 168.345 ;
     RECT  152.172 168.075 202.176 168.345 ;
     RECT  2.16 168.615 53.244 168.885 ;
     RECT  152.172 168.615 202.176 168.885 ;
     RECT  2.16 169.155 53.244 169.425 ;
     RECT  152.172 169.155 202.176 169.425 ;
     RECT  2.16 169.695 53.244 169.965 ;
     RECT  152.172 169.695 202.176 169.965 ;
     RECT  2.16 170.235 53.244 170.505 ;
     RECT  152.172 170.235 202.176 170.505 ;
     RECT  2.16 170.775 53.244 171.045 ;
     RECT  152.172 170.775 202.176 171.045 ;
     RECT  2.16 171.315 53.244 171.585 ;
     RECT  152.172 171.315 202.176 171.585 ;
     RECT  2.16 171.855 53.244 172.125 ;
     RECT  152.172 171.855 202.176 172.125 ;
     RECT  2.16 172.395 53.244 172.665 ;
     RECT  152.172 172.395 202.176 172.665 ;
     RECT  2.16 172.935 202.176 173.205 ;
     RECT  2.16 173.475 202.176 173.745 ;
     RECT  2.16 174.015 202.176 174.285 ;
     RECT  2.16 174.555 202.176 174.825 ;
     RECT  2.16 175.095 202.176 175.365 ;
     RECT  2.16 175.635 202.176 175.905 ;
     RECT  2.16 176.175 202.176 176.445 ;
     RECT  2.16 176.715 202.176 176.985 ;
     RECT  2.16 177.255 202.176 177.525 ;
     RECT  2.16 177.795 202.176 178.065 ;
     RECT  2.16 178.335 202.176 178.605 ;
     RECT  2.16 178.875 202.176 179.145 ;
     RECT  2.16 179.415 202.176 179.685 ;
     RECT  2.16 179.955 202.176 180.225 ;
     RECT  2.16 180.495 202.176 180.765 ;
     RECT  2.16 181.035 202.176 181.305 ;
     RECT  2.16 181.575 202.176 181.845 ;
     RECT  2.16 182.115 202.176 182.385 ;
     RECT  2.16 182.655 202.176 182.925 ;
     RECT  2.16 183.195 202.176 183.465 ;
     RECT  2.16 183.735 202.176 184.005 ;
     RECT  2.16 184.275 202.176 184.545 ;
     RECT  2.16 184.815 202.176 185.085 ;
     RECT  2.16 185.355 202.176 185.625 ;
     RECT  2.16 185.895 202.176 186.165 ;
     RECT  2.16 186.435 202.176 186.705 ;
     RECT  2.16 186.975 202.176 187.245 ;
     RECT  2.16 187.515 202.176 187.785 ;
     RECT  2.16 188.055 202.176 188.325 ;
     RECT  2.16 188.595 202.176 188.865 ;
     RECT  2.16 189.135 202.176 189.405 ;
     RECT  2.16 189.675 202.176 189.945 ;
     RECT  2.16 190.215 202.176 190.485 ;
     RECT  2.16 190.755 202.176 191.025 ;
     RECT  2.16 191.295 202.176 191.565 ;
     RECT  2.16 191.835 202.176 192.105 ;
    LAYER M1 ;
     RECT  2.16 2.151 202.176 56.169 ;
     RECT  55.296 58.32 150.12 99.36 ;
     RECT  2.16 56.169 53.244 101.511 ;
     RECT  152.172 56.169 202.176 101.511 ;
     RECT  2.16 101.511 202.176 127.449 ;
     RECT  55.296 129.6 150.12 170.64 ;
     RECT  2.16 127.449 53.244 172.791 ;
     RECT  152.172 127.449 202.176 172.791 ;
     RECT  2.16 172.791 202.176 192.249 ;
    LAYER M2 ;
     RECT  0.103 70.812 0.139 72.72 ;
     RECT  0.103 73.512 0.139 78.93 ;
     RECT  0.103 106.992 0.139 123.48 ;
     RECT  0.139 70.65 0.535 72.72 ;
     RECT  0.139 73.476 0.535 78.93 ;
     RECT  0.103 79.722 0.535 90.81 ;
     RECT  0.103 92.142 0.535 99.99 ;
     RECT  0.103 100.782 0.535 105.93 ;
     RECT  0.139 106.992 0.535 123.858 ;
     RECT  0.535 70.65 2.16 90.81 ;
     RECT  0.535 92.142 2.16 123.858 ;
     RECT  2.16 2.151 53.244 192.249 ;
     RECT  53.244 89.712 53.699 100.224 ;
     RECT  53.244 101.088 53.879 127.449 ;
     RECT  53.699 90.9 53.915 100.224 ;
     RECT  53.244 76.176 53.951 76.644 ;
     RECT  53.915 91.296 53.951 100.224 ;
     RECT  53.951 93.762 54.023 100.224 ;
     RECT  53.244 88.776 54.059 88.956 ;
     RECT  54.023 93.762 54.095 98.64 ;
     RECT  53.244 166.194 54.131 170.46 ;
     RECT  54.095 95.994 54.167 98.64 ;
     RECT  54.095 93.762 54.383 95.166 ;
     RECT  53.244 81.378 54.455 81.9 ;
     RECT  54.455 81.378 54.491 81.396 ;
     RECT  53.244 82.836 54.527 83.754 ;
     RECT  53.244 85.968 54.563 86.526 ;
     RECT  54.023 99.468 54.679 100.224 ;
     RECT  54.059 88.776 54.823 88.884 ;
     RECT  53.951 91.296 54.859 92.664 ;
     RECT  54.167 96.804 54.859 98.64 ;
     RECT  54.679 99.468 54.859 100.296 ;
     RECT  54.859 96.804 55.111 100.296 ;
     RECT  53.879 101.16 55.111 127.449 ;
     RECT  53.244 70.686 55.296 71.208 ;
     RECT  53.244 73.512 55.296 73.53 ;
     RECT  53.244 74.322 55.296 74.34 ;
     RECT  53.951 76.626 55.296 76.644 ;
     RECT  53.244 77.562 55.296 77.58 ;
     RECT  53.244 79.686 55.296 79.704 ;
     RECT  53.244 80.532 55.296 80.55 ;
     RECT  54.527 82.836 55.296 83.52 ;
     RECT  53.244 84.546 55.296 84.564 ;
     RECT  54.563 85.968 55.296 86.49 ;
     RECT  54.823 88.776 55.296 88.956 ;
     RECT  53.699 89.712 55.296 89.766 ;
     RECT  54.859 91.296 55.296 92.889 ;
     RECT  54.383 93.996 55.296 95.166 ;
     RECT  54.167 95.994 55.296 96.012 ;
     RECT  55.111 96.804 55.296 127.449 ;
     RECT  54.679 129.096 55.296 129.114 ;
     RECT  55.075 130.554 55.296 130.644 ;
     RECT  55.075 134.298 55.296 134.316 ;
     RECT  54.131 166.194 55.296 170.154 ;
     RECT  55.296 129.096 55.895 170.64 ;
     RECT  55.296 58.32 82.499 127.449 ;
     RECT  82.499 58.32 83.687 100.062 ;
     RECT  83.687 58.32 84.875 100.026 ;
     RECT  55.895 129.6 107.167 170.64 ;
     RECT  107.167 129.6 107.851 171.306 ;
     RECT  107.851 129.6 109.975 171.342 ;
     RECT  82.499 101.16 119.759 127.449 ;
     RECT  109.975 129.366 123.079 171.342 ;
     RECT  119.759 101.394 144.823 127.449 ;
     RECT  144.823 101.322 144.895 127.449 ;
     RECT  123.079 129.366 146.335 171.846 ;
     RECT  146.335 128.781 146.471 171.846 ;
     RECT  84.875 58.32 146.479 99.36 ;
     RECT  144.895 101.286 146.911 127.449 ;
     RECT  146.479 58.32 146.983 99.684 ;
     RECT  146.911 101.16 147.487 127.449 ;
     RECT  146.983 58.32 147.631 99.792 ;
     RECT  147.487 101.16 147.991 127.566 ;
     RECT  147.991 100.89 148.099 127.566 ;
     RECT  147.631 58.32 148.135 100.062 ;
     RECT  148.099 100.854 148.135 127.566 ;
     RECT  148.135 58.32 148.171 127.566 ;
     RECT  146.471 128.826 148.171 171.846 ;
     RECT  148.171 58.32 150.12 171.846 ;
     RECT  149.791 57.456 150.251 57.474 ;
     RECT  150.12 91.332 150.287 93.159 ;
     RECT  150.12 88.47 150.323 89.802 ;
     RECT  150.12 134.991 150.323 137.754 ;
     RECT  150.12 142.056 150.323 142.614 ;
     RECT  150.12 153.972 150.323 153.99 ;
     RECT  150.12 71.658 150.359 72.522 ;
     RECT  150.12 74.511 150.359 74.88 ;
     RECT  150.12 77.058 150.359 77.076 ;
     RECT  150.287 92.871 150.359 93.159 ;
     RECT  150.12 130.941 150.359 131.652 ;
     RECT  150.12 133.956 150.359 134.118 ;
     RECT  150.12 149.724 150.359 149.814 ;
     RECT  150.12 84.852 150.395 85.518 ;
     RECT  150.12 87.354 150.395 87.444 ;
     RECT  150.323 134.991 150.395 137.709 ;
     RECT  150.12 144.756 150.395 144.774 ;
     RECT  150.395 84.924 150.431 85.518 ;
     RECT  150.287 91.332 150.431 91.656 ;
     RECT  150.12 94.14 150.431 98.406 ;
     RECT  150.12 80.946 150.467 81.162 ;
     RECT  150.431 84.924 150.467 85.014 ;
     RECT  150.323 88.506 150.467 89.802 ;
     RECT  150.359 92.916 150.467 93.159 ;
     RECT  150.395 134.991 150.467 135.936 ;
     RECT  150.467 80.946 150.503 81.054 ;
     RECT  150.467 89.361 150.503 89.802 ;
     RECT  150.12 99.396 150.503 129.834 ;
     RECT  150.395 136.692 150.503 137.709 ;
     RECT  150.503 80.946 150.539 80.964 ;
     RECT  150.12 60.048 150.575 61.794 ;
     RECT  150.503 99.396 150.575 127.674 ;
     RECT  150.359 74.862 150.611 74.88 ;
     RECT  150.12 156.744 150.611 156.762 ;
     RECT  150.12 164.691 150.611 164.709 ;
     RECT  150.575 99.621 150.827 127.674 ;
     RECT  150.12 148.176 150.827 148.932 ;
     RECT  150.431 96.381 150.863 98.406 ;
     RECT  150.12 82.386 150.871 82.404 ;
     RECT  150.12 140.778 150.871 140.796 ;
     RECT  150.467 92.916 150.899 93.006 ;
     RECT  150.827 99.621 150.899 127.602 ;
     RECT  150.467 134.991 150.907 135.324 ;
     RECT  150.899 92.916 150.935 92.934 ;
     RECT  150.323 142.596 150.943 142.614 ;
     RECT  150.12 146.916 150.979 147.204 ;
     RECT  150.943 152.622 150.979 152.64 ;
     RECT  150.12 145.836 151.015 146.034 ;
     RECT  150.359 149.796 151.015 149.814 ;
     RECT  150.943 150.876 151.015 150.894 ;
     RECT  150.979 152.622 151.043 152.874 ;
     RECT  150.12 62.946 151.051 63.504 ;
     RECT  150.503 128.592 151.051 129.834 ;
     RECT  150.575 60.156 151.087 61.794 ;
     RECT  151.051 62.676 151.087 63.504 ;
     RECT  150.12 69.156 151.087 69.174 ;
     RECT  151.051 70.776 151.087 70.794 ;
     RECT  150.359 71.856 151.087 72.522 ;
     RECT  151.051 73.656 151.087 73.674 ;
     RECT  150.359 131.292 151.087 131.652 ;
     RECT  150.12 132.516 151.087 132.804 ;
     RECT  151.051 68.346 151.123 68.364 ;
     RECT  151.087 69.156 151.123 69.624 ;
     RECT  151.087 70.776 151.159 72.522 ;
     RECT  151.123 68.346 151.195 69.714 ;
     RECT  150.863 96.381 151.195 98.244 ;
     RECT  150.395 87.354 151.231 87.372 ;
     RECT  150.467 88.506 151.231 88.524 ;
     RECT  150.907 134.874 151.231 135.324 ;
     RECT  151.195 68.346 151.267 69.984 ;
     RECT  151.159 70.776 151.267 72.756 ;
     RECT  151.015 145.17 151.339 146.034 ;
     RECT  151.231 134.766 151.367 135.36 ;
     RECT  150.359 133.956 151.375 133.974 ;
     RECT  151.367 134.766 151.375 135.324 ;
     RECT  151.267 84.654 151.411 85.014 ;
     RECT  151.231 87.354 151.411 88.524 ;
     RECT  151.411 87.084 151.483 88.524 ;
     RECT  150.907 83.196 151.519 83.214 ;
     RECT  151.267 68.346 151.591 72.756 ;
     RECT  151.087 131.292 151.591 132.804 ;
     RECT  151.375 133.956 151.591 135.324 ;
     RECT  150.12 143.856 151.591 143.964 ;
     RECT  151.483 86.346 151.663 88.524 ;
     RECT  150.899 99.621 151.771 127.566 ;
     RECT  151.735 92.871 151.807 92.889 ;
     RECT  150.12 79.488 151.843 79.506 ;
     RECT  150.503 136.692 151.879 137.214 ;
     RECT  151.807 92.286 151.915 92.889 ;
     RECT  151.771 99.576 151.915 127.566 ;
     RECT  151.519 156.978 151.915 156.996 ;
     RECT  151.915 92.286 151.951 93.006 ;
     RECT  151.339 145.17 151.951 146.124 ;
     RECT  151.915 76.986 151.987 77.004 ;
     RECT  151.879 77.904 151.987 77.922 ;
     RECT  150.431 91.332 151.987 91.35 ;
     RECT  151.519 83.196 152.023 83.862 ;
     RECT  151.411 84.654 152.023 85.059 ;
     RECT  151.987 90.666 152.023 91.35 ;
     RECT  150.943 142.596 152.023 142.884 ;
     RECT  151.591 143.856 152.023 144.036 ;
     RECT  151.843 79.146 152.059 79.506 ;
     RECT  151.879 136.494 152.059 137.214 ;
     RECT  151.987 139.896 152.059 139.914 ;
     RECT  150.871 140.778 152.059 141.264 ;
     RECT  150.12 154.926 152.059 155.304 ;
     RECT  152.023 83.196 152.095 85.446 ;
     RECT  152.023 89.946 152.095 91.35 ;
     RECT  151.591 131.292 152.095 135.324 ;
     RECT  152.059 136.296 152.095 137.214 ;
     RECT  152.023 138.042 152.095 138.06 ;
     RECT  150.979 146.916 152.095 147.348 ;
     RECT  150.827 148.176 152.095 148.464 ;
     RECT  152.095 89.856 152.131 91.35 ;
     RECT  150.431 94.14 152.131 95.238 ;
     RECT  151.195 96.3 152.131 98.244 ;
     RECT  151.015 149.796 152.131 150.894 ;
     RECT  151.043 152.766 152.131 152.874 ;
     RECT  150.871 81.846 152.167 82.404 ;
     RECT  152.095 83.196 152.167 85.518 ;
     RECT  151.663 86.346 152.167 88.758 ;
     RECT  152.131 152.766 152.167 153.414 ;
     RECT  152.059 154.512 152.167 155.304 ;
     RECT  53.244 2.151 152.172 56.169 ;
     RECT  151.087 60.156 152.172 63.504 ;
     RECT  150.12 65.106 152.172 65.934 ;
     RECT  150.12 67.032 152.172 67.05 ;
     RECT  151.591 68.256 152.172 72.756 ;
     RECT  151.087 73.656 152.172 74.412 ;
     RECT  151.987 76.986 152.172 77.922 ;
     RECT  152.059 79.146 152.172 79.704 ;
     RECT  151.699 80.946 152.172 80.964 ;
     RECT  152.167 81.846 152.172 88.758 ;
     RECT  152.131 89.586 152.172 91.35 ;
     RECT  151.951 92.178 152.172 93.006 ;
     RECT  152.131 94.14 152.172 98.244 ;
     RECT  151.915 99.126 152.172 127.566 ;
     RECT  151.051 128.592 152.172 129.996 ;
     RECT  152.095 131.292 152.172 137.214 ;
     RECT  152.095 138.042 152.172 138.132 ;
     RECT  151.879 138.996 152.172 139.014 ;
     RECT  152.059 139.896 152.172 141.264 ;
     RECT  152.023 142.596 152.172 144.036 ;
     RECT  151.951 145.026 152.172 146.124 ;
     RECT  152.095 146.916 152.172 148.464 ;
     RECT  152.131 149.796 152.172 151.164 ;
     RECT  152.167 151.956 152.172 151.974 ;
     RECT  152.167 152.766 152.172 155.304 ;
     RECT  151.915 156.906 152.172 156.996 ;
     RECT  150.12 158.436 152.172 158.454 ;
     RECT  151.519 160.722 152.172 160.74 ;
     RECT  150.12 167.616 152.172 167.634 ;
     RECT  151.627 168.696 152.172 168.714 ;
     RECT  150.12 171.288 152.172 171.846 ;
     RECT  53.244 172.791 152.172 192.249 ;
     RECT  152.172 2.151 202.176 192.249 ;
     RECT  202.176 122.652 202.271 123.444 ;
     RECT  202.176 74.394 202.343 96.822 ;
     RECT  202.176 120.186 202.343 121.122 ;
     RECT  202.271 122.652 202.343 123.282 ;
     RECT  202.343 74.394 202.379 88.92 ;
     RECT  202.343 120.456 202.883 121.122 ;
     RECT  202.379 74.394 202.919 83.214 ;
     RECT  202.379 84.006 202.919 88.92 ;
     RECT  202.343 89.676 202.919 94.194 ;
     RECT  202.343 95.256 202.919 96.822 ;
     RECT  202.176 97.578 202.919 100.026 ;
     RECT  202.176 101.286 202.919 104.274 ;
     RECT  202.176 117.558 202.919 119.394 ;
     RECT  202.343 122.652 202.919 123.174 ;
     RECT  202.176 71.892 202.955 73.224 ;
     RECT  202.919 81.576 202.955 83.214 ;
     RECT  202.919 85.266 202.955 88.92 ;
     RECT  202.919 96.156 202.955 96.822 ;
     RECT  202.919 97.776 202.955 99.684 ;
     RECT  202.883 120.456 202.955 121.014 ;
     RECT  202.955 96.696 202.991 96.714 ;
     RECT  202.919 89.676 203.459 93.816 ;
     RECT  202.919 103.716 203.459 104.274 ;
     RECT  202.176 105.174 203.459 116.694 ;
     RECT  202.919 75.006 203.495 76.608 ;
     RECT  202.919 77.634 203.495 80.784 ;
     RECT  202.955 82.296 203.495 83.214 ;
     RECT  202.955 85.266 203.495 86.994 ;
     RECT  202.955 88.776 203.495 88.884 ;
     RECT  203.459 89.676 203.495 93.744 ;
     RECT  202.919 95.256 203.495 95.364 ;
     RECT  202.955 98.118 203.495 99.684 ;
     RECT  202.919 101.286 203.495 101.754 ;
     RECT  203.459 103.716 203.495 103.734 ;
     RECT  203.459 105.174 203.495 106.434 ;
     RECT  203.459 107.406 203.495 116.694 ;
     RECT  202.919 117.666 203.495 119.394 ;
     RECT  202.955 71.892 203.531 72.864 ;
     RECT  203.495 75.096 203.531 76.032 ;
     RECT  203.495 79.326 203.531 80.244 ;
     RECT  203.495 85.266 203.531 85.644 ;
     RECT  203.495 91.944 203.531 92.736 ;
     RECT  203.495 98.118 203.531 98.244 ;
     RECT  203.495 107.946 203.531 113.454 ;
     RECT  203.495 116.586 203.531 116.604 ;
     RECT  203.531 71.892 203.567 72.45 ;
     RECT  203.567 72.432 203.603 72.45 ;
     RECT  203.495 77.634 204.179 78.354 ;
     RECT  203.495 101.466 204.179 101.754 ;
     RECT  202.919 102.636 204.179 102.924 ;
     RECT  203.531 108.306 204.179 111.024 ;
     RECT  203.531 75.816 204.215 76.032 ;
     RECT  204.179 77.634 204.215 78.084 ;
     RECT  203.531 79.326 204.215 80.154 ;
     RECT  203.495 82.296 204.215 82.782 ;
     RECT  202.919 84.006 204.215 84.204 ;
     RECT  203.531 85.356 204.215 85.644 ;
     RECT  203.495 86.778 204.215 86.994 ;
     RECT  203.495 90.216 204.215 90.846 ;
     RECT  203.531 91.98 204.215 92.394 ;
     RECT  204.179 101.466 204.215 101.484 ;
     RECT  204.179 102.636 204.215 102.726 ;
     RECT  204.179 108.306 204.215 108.396 ;
     RECT  204.179 109.566 204.215 111.024 ;
     RECT  203.531 111.816 204.215 113.454 ;
     RECT  202.955 120.456 204.215 120.924 ;
     RECT  202.919 122.652 204.215 123.012 ;
     RECT  204.215 75.816 204.251 75.834 ;
     RECT  204.215 78.066 204.251 78.084 ;
     RECT  204.215 79.326 204.251 79.344 ;
     RECT  204.215 80.136 204.251 80.154 ;
     RECT  204.215 82.296 204.251 82.314 ;
     RECT  204.215 84.006 204.251 84.024 ;
     RECT  204.215 85.356 204.251 85.374 ;
     RECT  204.215 86.976 204.251 86.994 ;
     RECT  203.495 88.776 204.251 88.794 ;
     RECT  204.215 90.216 204.251 90.234 ;
     RECT  204.215 92.376 204.251 92.394 ;
     RECT  203.495 95.256 204.251 95.274 ;
     RECT  203.531 98.118 204.251 98.136 ;
     RECT  204.215 102.708 204.251 102.726 ;
     RECT  203.495 105.516 204.251 106.164 ;
     RECT  204.215 108.378 204.251 108.396 ;
     RECT  204.215 109.566 204.251 110.124 ;
     RECT  204.215 111.006 204.251 111.024 ;
     RECT  204.215 112.086 204.251 113.454 ;
     RECT  203.495 114.786 204.251 115.524 ;
     RECT  203.495 117.756 204.251 117.774 ;
     RECT  203.495 119.106 204.251 119.124 ;
     RECT  204.215 120.906 204.251 120.924 ;
     RECT  204.215 122.994 204.251 123.012 ;
    LAYER M3 ;
     RECT  2.415 2.143 2.505 2.413 ;
     RECT  7.815 2.143 7.905 2.413 ;
     RECT  13.215 2.143 13.305 2.413 ;
     RECT  18.615 2.143 18.705 2.413 ;
     RECT  24.015 2.143 24.105 2.413 ;
     RECT  29.415 2.143 29.505 2.413 ;
     RECT  34.815 2.143 34.905 2.413 ;
     RECT  40.215 2.143 40.305 2.413 ;
     RECT  45.615 2.143 45.705 2.413 ;
     RECT  51.015 2.143 51.105 2.413 ;
     RECT  56.415 2.143 56.505 2.413 ;
     RECT  61.815 2.143 61.905 2.413 ;
     RECT  67.215 2.143 67.305 2.413 ;
     RECT  72.615 2.143 72.705 2.413 ;
     RECT  78.015 2.143 78.105 2.413 ;
     RECT  83.415 2.143 83.505 2.413 ;
     RECT  88.815 2.143 88.905 2.413 ;
     RECT  94.215 2.143 94.305 2.413 ;
     RECT  99.615 2.143 99.705 2.413 ;
     RECT  105.015 2.143 105.105 2.413 ;
     RECT  110.415 2.143 110.505 2.413 ;
     RECT  115.815 2.143 115.905 2.413 ;
     RECT  121.215 2.143 121.305 2.413 ;
     RECT  126.615 2.143 126.705 2.413 ;
     RECT  132.015 2.143 132.105 2.413 ;
     RECT  137.415 2.143 137.505 2.413 ;
     RECT  142.815 2.143 142.905 2.413 ;
     RECT  148.215 2.143 148.305 2.413 ;
     RECT  153.615 2.143 153.705 2.413 ;
     RECT  159.015 2.143 159.105 2.413 ;
     RECT  164.415 2.143 164.505 2.413 ;
     RECT  169.815 2.143 169.905 2.413 ;
     RECT  175.215 2.143 175.305 2.413 ;
     RECT  180.615 2.143 180.705 2.413 ;
     RECT  186.015 2.143 186.105 2.413 ;
     RECT  191.415 2.143 191.505 2.413 ;
     RECT  196.815 2.143 196.905 2.413 ;
     RECT  34.815 2.413 35.097 54.565 ;
     RECT  110.415 2.413 110.697 54.565 ;
     RECT  13.215 2.413 13.497 54.571 ;
     RECT  24.015 2.413 24.297 54.571 ;
     RECT  45.615 2.413 45.897 54.571 ;
     RECT  51.015 2.413 51.297 54.571 ;
     RECT  67.215 2.413 67.497 54.571 ;
     RECT  78.015 2.413 78.297 54.571 ;
     RECT  88.815 2.413 89.097 54.571 ;
     RECT  99.615 2.413 99.897 54.571 ;
     RECT  121.215 2.413 121.497 54.571 ;
     RECT  132.015 2.413 132.297 54.571 ;
     RECT  142.815 2.413 143.097 54.571 ;
     RECT  34.704 54.565 35.097 54.605 ;
     RECT  110.304 54.565 110.697 54.605 ;
     RECT  13.104 54.571 13.497 54.608 ;
     RECT  23.904 54.571 24.297 54.608 ;
     RECT  45.504 54.571 45.897 54.608 ;
     RECT  67.104 54.571 67.497 54.608 ;
     RECT  77.904 54.571 78.297 54.608 ;
     RECT  88.704 54.571 89.097 54.608 ;
     RECT  99.504 54.571 99.897 54.608 ;
     RECT  121.104 54.571 121.497 54.608 ;
     RECT  131.904 54.571 132.297 54.608 ;
     RECT  142.704 54.571 143.097 54.608 ;
     RECT  54.144 54.667 54.162 55.184 ;
     RECT  55.368 54.667 55.386 55.184 ;
     RECT  50.724 54.571 51.297 55.517 ;
     RECT  58.68 54.571 58.698 55.517 ;
     RECT  146.484 54.571 146.502 55.517 ;
     RECT  54.468 55.483 54.486 55.709 ;
     RECT  55.584 55.48 55.602 55.715 ;
     RECT  56.415 2.413 56.697 55.907 ;
     RECT  61.815 2.413 62.097 55.907 ;
     RECT  67.215 54.608 67.497 55.907 ;
     RECT  72.615 2.413 72.897 55.907 ;
     RECT  78.015 54.608 78.297 55.907 ;
     RECT  83.415 2.413 83.697 55.907 ;
     RECT  88.815 54.608 89.097 55.907 ;
     RECT  94.215 2.413 94.497 55.907 ;
     RECT  99.615 54.608 99.897 55.907 ;
     RECT  105.015 2.413 105.297 55.907 ;
     RECT  110.415 54.605 110.697 55.907 ;
     RECT  115.815 2.413 116.097 55.907 ;
     RECT  121.215 54.608 121.497 55.907 ;
     RECT  126.615 2.413 126.897 55.907 ;
     RECT  132.015 54.608 132.297 55.907 ;
     RECT  137.415 2.413 137.697 55.907 ;
     RECT  142.815 54.608 143.097 55.907 ;
     RECT  148.215 2.413 148.497 55.907 ;
     RECT  54.144 55.957 54.162 55.997 ;
     RECT  55.368 55.957 55.386 55.997 ;
     RECT  56.415 55.907 56.505 56.177 ;
     RECT  61.815 55.907 61.905 56.177 ;
     RECT  67.215 55.907 67.305 56.177 ;
     RECT  72.615 55.907 72.705 56.177 ;
     RECT  78.015 55.907 78.105 56.177 ;
     RECT  83.415 55.907 83.505 56.177 ;
     RECT  88.815 55.907 88.905 56.177 ;
     RECT  94.215 55.907 94.305 56.177 ;
     RECT  99.615 55.907 99.705 56.177 ;
     RECT  105.015 55.907 105.105 56.177 ;
     RECT  110.415 55.907 110.505 56.177 ;
     RECT  115.815 55.907 115.905 56.177 ;
     RECT  121.215 55.907 121.305 56.177 ;
     RECT  126.615 55.907 126.705 56.177 ;
     RECT  132.015 55.907 132.105 56.177 ;
     RECT  137.415 55.907 137.505 56.177 ;
     RECT  142.815 55.907 142.905 56.177 ;
     RECT  148.215 55.907 148.305 56.177 ;
     RECT  13.215 54.608 13.497 57.163 ;
     RECT  24.015 54.608 24.297 57.163 ;
     RECT  34.815 54.605 35.097 57.163 ;
     RECT  45.615 54.608 45.897 57.163 ;
     RECT  13.104 57.163 13.497 57.209 ;
     RECT  23.904 57.163 24.297 57.209 ;
     RECT  34.704 57.163 35.097 57.209 ;
     RECT  29.415 2.413 29.697 57.271 ;
     RECT  46.764 56.827 46.782 57.299 ;
     RECT  29.415 57.271 30.042 57.307 ;
     RECT  28.908 57.307 30.042 57.341 ;
     RECT  30.852 57.343 30.87 57.389 ;
     RECT  31.968 57.271 31.986 57.389 ;
     RECT  33.876 57.403 33.894 57.443 ;
     RECT  32.76 57.403 32.778 57.479 ;
     RECT  149.796 57.451 150.246 57.488 ;
     RECT  28.908 57.341 29.934 57.541 ;
     RECT  28.8 57.541 29.934 57.581 ;
     RECT  45.504 57.163 45.897 57.595 ;
     RECT  44.964 57.595 45.897 57.691 ;
     RECT  50.076 57.067 50.094 57.811 ;
     RECT  44.748 57.691 45.897 57.839 ;
     RECT  48.168 57.811 48.186 57.869 ;
     RECT  47.052 57.835 47.07 57.875 ;
     RECT  48.96 57.163 48.978 57.883 ;
     RECT  50.004 57.811 50.094 57.917 ;
     RECT  44.748 57.839 44.766 57.919 ;
     RECT  48.888 57.883 48.978 57.92 ;
     RECT  45.615 57.839 45.897 57.931 ;
     RECT  44.244 57.919 44.766 57.965 ;
     RECT  150.192 57.488 150.246 58.075 ;
     RECT  44.748 57.965 44.766 58.109 ;
     RECT  45.615 57.931 46.17 58.109 ;
     RECT  48.96 57.92 48.978 58.109 ;
     RECT  50.076 57.917 50.094 58.109 ;
     RECT  150.192 58.075 150.282 58.32 ;
     RECT  52.596 59.179 52.614 59.275 ;
     RECT  51.015 55.517 51.297 59.467 ;
     RECT  51.015 59.467 51.39 59.563 ;
     RECT  164.415 2.413 164.697 59.563 ;
     RECT  52.596 59.275 52.938 59.755 ;
     RECT  53.856 59.083 53.874 59.755 ;
     RECT  55.296 58.32 150.282 60.037 ;
     RECT  151.056 59.947 151.074 60.037 ;
     RECT  153.615 2.413 153.897 60.151 ;
     RECT  55.296 60.037 151.074 60.235 ;
     RECT  55.044 60.235 151.614 60.331 ;
     RECT  153.432 60.151 153.897 60.331 ;
     RECT  153.432 60.331 153.954 60.385 ;
     RECT  52.596 59.755 53.874 60.427 ;
     RECT  54.684 60.331 151.614 60.427 ;
     RECT  153.324 60.385 153.954 60.619 ;
     RECT  152.424 60.007 152.442 60.691 ;
     RECT  51.015 59.563 51.57 60.811 ;
     RECT  152.424 60.691 152.586 60.907 ;
     RECT  153.324 60.619 154.494 60.907 ;
     RECT  152.424 60.907 154.494 60.961 ;
     RECT  152.424 60.961 154.926 61.079 ;
     RECT  51.015 60.811 51.858 61.099 ;
     RECT  52.596 60.427 151.614 61.099 ;
     RECT  152.496 61.079 154.926 61.099 ;
     RECT  51.015 61.099 151.614 61.529 ;
     RECT  51.015 61.529 151.578 61.691 ;
     RECT  152.496 61.099 155.07 61.735 ;
     RECT  155.808 61.501 155.826 61.735 ;
     RECT  51.015 61.691 151.11 62.159 ;
     RECT  152.496 61.735 155.826 62.203 ;
     RECT  51.015 62.159 151.074 62.491 ;
     RECT  50.472 62.491 151.074 62.539 ;
     RECT  152.388 62.203 155.826 62.581 ;
     RECT  156.672 61.771 156.69 62.581 ;
     RECT  152.388 62.581 156.69 63.391 ;
     RECT  50.4 62.539 151.074 63.419 ;
     RECT  50.4 63.419 150.786 63.547 ;
     RECT  152.388 63.391 156.834 63.787 ;
     RECT  49.824 63.547 150.786 63.883 ;
     RECT  152.208 63.787 156.834 64.171 ;
     RECT  49.284 63.883 150.786 64.363 ;
     RECT  49.248 64.363 150.786 64.603 ;
     RECT  152.208 64.171 156.87 64.939 ;
     RECT  49.212 64.603 150.786 65.129 ;
     RECT  151.884 64.939 156.87 65.371 ;
     RECT  157.644 64.327 157.662 65.371 ;
     RECT  49.212 65.129 150.75 65.755 ;
     RECT  48.708 65.755 150.75 66.043 ;
     RECT  151.884 65.371 157.662 66.859 ;
     RECT  48.636 66.043 150.75 67.051 ;
     RECT  151.596 66.859 157.662 67.051 ;
     RECT  48.636 67.051 157.662 67.147 ;
     RECT  48.204 67.147 157.662 67.171 ;
     RECT  48.204 67.171 158.094 67.339 ;
     RECT  48.168 67.339 158.094 67.579 ;
     RECT  48.132 67.579 158.094 68.477 ;
     RECT  48.132 68.477 151.29 68.683 ;
     RECT  47.484 68.683 151.29 68.875 ;
     RECT  47.232 68.875 151.29 68.923 ;
     RECT  47.124 68.923 151.29 69.259 ;
     RECT  152.532 68.477 158.094 69.359 ;
     RECT  152.604 69.359 158.094 70.069 ;
     RECT  159.015 2.413 159.297 70.069 ;
     RECT  152.604 70.069 159.297 70.123 ;
     RECT  47.088 69.259 151.326 70.219 ;
     RECT  3.708 70.501 3.726 70.637 ;
     RECT  152.208 70.123 159.297 70.709 ;
     RECT  0.144 70.603 0.162 70.795 ;
     RECT  152.64 70.709 159.297 71.213 ;
     RECT  0.108 70.795 0.162 71.371 ;
     RECT  152.712 71.213 159.297 71.375 ;
     RECT  3.888 70.645 4.482 71.455 ;
     RECT  2.415 2.413 2.697 71.491 ;
     RECT  3.636 71.455 4.482 71.491 ;
     RECT  5.976 70.951 5.994 71.491 ;
     RECT  0.108 71.371 0.558 71.717 ;
     RECT  2.415 71.491 4.482 71.755 ;
     RECT  5.652 71.491 5.994 71.761 ;
     RECT  7.815 2.413 8.097 71.761 ;
     RECT  201.24 71.491 201.834 71.761 ;
     RECT  5.652 71.761 6.714 71.887 ;
     RECT  200.988 71.761 201.834 71.995 ;
     RECT  2.304 71.755 4.482 72.031 ;
     RECT  203.544 71.887 203.562 72.031 ;
     RECT  2.304 72.031 4.626 72.265 ;
     RECT  5.58 71.887 6.714 72.265 ;
     RECT  199.728 72.031 199.746 72.265 ;
     RECT  2.304 72.265 6.714 72.301 ;
     RECT  152.748 71.375 159.297 72.331 ;
     RECT  152.388 72.331 159.297 72.379 ;
     RECT  199.548 72.265 199.746 72.379 ;
     RECT  46.656 70.219 151.326 72.427 ;
     RECT  152.316 72.379 159.297 72.427 ;
     RECT  200.52 71.995 201.834 72.427 ;
     RECT  202.932 72.031 203.562 72.427 ;
     RECT  0.108 71.717 0.126 72.523 ;
     RECT  46.656 72.427 159.297 72.761 ;
     RECT  198.972 72.379 199.746 72.769 ;
     RECT  200.52 72.427 201.87 72.769 ;
     RECT  196.815 2.413 197.097 72.841 ;
     RECT  151.848 72.761 159.297 72.931 ;
     RECT  196.488 72.841 197.097 72.931 ;
     RECT  198.972 72.769 201.87 72.931 ;
     RECT  9.216 72.571 9.234 72.955 ;
     RECT  195.084 72.955 195.102 72.995 ;
     RECT  198.864 72.931 201.87 73.003 ;
     RECT  198.036 72.931 198.054 73.075 ;
     RECT  196.092 72.931 197.097 73.265 ;
     RECT  196.344 73.265 197.097 73.345 ;
     RECT  197.82 73.075 198.054 73.345 ;
     RECT  0.108 72.523 0.558 73.373 ;
     RECT  198.864 73.003 201.942 73.381 ;
     RECT  193.824 72.931 193.842 73.409 ;
     RECT  202.932 72.427 203.598 73.421 ;
     RECT  0.108 73.373 0.162 73.517 ;
     RECT  2.304 72.301 6.966 73.531 ;
     RECT  2.304 73.531 7.002 73.607 ;
     RECT  164.415 59.563 165.33 73.849 ;
     RECT  196.344 73.345 198.054 73.885 ;
     RECT  198.864 73.381 202.05 73.885 ;
     RECT  2.376 73.607 7.002 73.921 ;
     RECT  7.815 71.761 8.406 73.921 ;
     RECT  46.656 72.761 151.11 73.921 ;
     RECT  151.848 72.931 159.426 73.921 ;
     RECT  161.136 59.275 161.154 74.119 ;
     RECT  202.932 73.421 203.526 74.155 ;
     RECT  46.656 73.921 159.426 74.281 ;
     RECT  46.656 74.281 159.462 74.417 ;
     RECT  202.896 74.155 203.526 74.417 ;
     RECT  151.632 74.417 159.462 74.453 ;
     RECT  196.344 73.885 202.05 74.573 ;
     RECT  196.344 74.573 201.978 74.587 ;
     RECT  9.216 72.955 9.27 74.623 ;
     RECT  2.376 73.921 8.406 74.635 ;
     RECT  196.164 74.587 201.978 74.669 ;
     RECT  9.18 74.623 9.27 74.683 ;
     RECT  196.815 74.669 201.978 74.687 ;
     RECT  199.584 74.687 201.978 74.765 ;
     RECT  9.18 74.683 9.414 74.849 ;
     RECT  196.815 74.687 198.81 74.849 ;
     RECT  9.18 74.849 9.27 74.885 ;
     RECT  194.436 74.731 194.454 74.929 ;
     RECT  199.584 74.765 201.87 74.957 ;
     RECT  2.304 74.635 8.406 75.001 ;
     RECT  9.18 74.885 9.234 75.001 ;
     RECT  194.364 74.929 194.454 75.029 ;
     RECT  203.472 74.417 203.526 75.115 ;
     RECT  196.815 74.849 197.802 75.119 ;
     RECT  162.54 74.425 162.558 75.235 ;
     RECT  163.728 73.849 165.33 75.235 ;
     RECT  203.472 75.115 204.246 75.341 ;
     RECT  151.632 74.453 159.426 75.361 ;
     RECT  24.015 57.209 24.297 75.631 ;
     RECT  34.815 57.209 35.097 75.631 ;
     RECT  45.615 58.109 45.897 75.631 ;
     RECT  2.304 75.001 9.234 75.659 ;
     RECT  24.015 75.631 24.822 75.677 ;
     RECT  34.704 75.631 35.097 75.677 ;
     RECT  45.504 75.631 45.897 75.677 ;
     RECT  199.944 74.957 201.87 75.775 ;
     RECT  190.404 75.667 190.422 75.803 ;
     RECT  196.815 75.119 197.622 75.811 ;
     RECT  199.62 75.775 201.87 75.811 ;
     RECT  204.192 75.341 204.246 75.839 ;
     RECT  199.584 75.811 201.978 75.929 ;
     RECT  2.304 75.659 4.77 75.965 ;
     RECT  196.632 75.811 197.622 76.009 ;
     RECT  0.108 73.517 0.126 76.027 ;
     RECT  204.192 75.839 204.21 76.037 ;
     RECT  46.656 74.417 150.894 76.075 ;
     RECT  151.632 75.361 159.462 76.075 ;
     RECT  202.896 75.499 202.914 76.075 ;
     RECT  194.364 75.029 194.382 76.081 ;
     RECT  198.612 74.849 198.81 76.081 ;
     RECT  199.584 75.929 201.87 76.081 ;
     RECT  194.364 76.081 194.454 76.109 ;
     RECT  25.776 76.081 25.794 76.199 ;
     RECT  2.415 75.965 4.77 76.235 ;
     RECT  194.436 76.109 194.454 76.235 ;
     RECT  195.3 75.775 195.318 76.315 ;
     RECT  5.508 75.659 9.234 76.363 ;
     RECT  5.508 76.363 9.918 76.469 ;
     RECT  202.896 76.075 203.49 76.613 ;
     RECT  3.708 76.235 4.77 76.621 ;
     RECT  5.508 76.469 9.234 76.621 ;
     RECT  196.632 76.009 197.802 76.621 ;
     RECT  202.896 76.613 202.914 76.651 ;
     RECT  0.108 76.027 0.198 76.747 ;
     RECT  3.708 76.621 9.234 76.811 ;
     RECT  0.108 76.747 0.558 76.847 ;
     RECT  195.3 76.315 195.462 76.891 ;
     RECT  196.236 76.621 197.802 76.891 ;
     RECT  195.3 76.891 197.802 76.981 ;
     RECT  198.612 76.081 201.87 76.981 ;
     RECT  202.86 76.651 202.914 77.009 ;
     RECT  46.656 76.075 159.462 77.017 ;
     RECT  2.415 76.235 2.862 77.089 ;
     RECT  194.436 76.981 194.454 77.089 ;
     RECT  195.3 76.981 201.87 77.117 ;
     RECT  194.436 77.089 194.49 77.125 ;
     RECT  202.86 77.009 202.878 77.153 ;
     RECT  2.415 77.089 3.15 77.323 ;
     RECT  204.228 76.843 204.246 77.419 ;
     RECT  194.364 77.125 194.49 77.515 ;
     RECT  195.3 77.117 201.834 77.515 ;
     RECT  194.364 77.515 201.834 77.549 ;
     RECT  204.192 77.419 204.246 77.611 ;
     RECT  4.032 76.811 9.234 77.701 ;
     RECT  2.376 77.323 3.15 77.791 ;
     RECT  4.032 77.701 9.738 77.791 ;
     RECT  194.364 77.549 195.21 77.819 ;
     RECT  196.704 77.549 201.834 77.819 ;
     RECT  161.136 74.119 161.442 77.863 ;
     RECT  199.872 77.819 201.834 77.899 ;
     RECT  202.896 77.803 202.914 77.899 ;
     RECT  160.704 77.863 161.442 77.999 ;
     RECT  178.992 77.395 179.01 77.999 ;
     RECT  194.436 77.819 195.21 77.999 ;
     RECT  199.872 77.899 202.914 78.029 ;
     RECT  2.376 77.791 9.738 78.125 ;
     RECT  202.896 78.029 202.914 78.187 ;
     RECT  204.156 77.611 204.246 78.187 ;
     RECT  2.415 78.125 9.738 78.359 ;
     RECT  202.896 78.187 204.246 78.359 ;
     RECT  195.192 77.999 195.21 78.395 ;
     RECT  199.872 78.029 202.05 78.601 ;
     RECT  196.704 77.819 199.098 78.619 ;
     RECT  3.816 78.359 9.738 78.629 ;
     RECT  3.816 78.629 8.097 78.665 ;
     RECT  0.108 76.847 0.126 78.667 ;
     RECT  196.596 78.619 199.098 78.745 ;
     RECT  3.816 78.665 6.966 78.773 ;
     RECT  196.488 78.745 199.098 78.781 ;
     RECT  199.836 78.601 202.05 78.781 ;
     RECT  202.896 78.359 203.49 78.781 ;
     RECT  3.852 78.773 6.966 78.809 ;
     RECT  196.488 78.781 203.49 78.899 ;
     RECT  46.656 77.017 159.498 78.979 ;
     RECT  2.415 78.359 2.697 79.051 ;
     RECT  46.656 78.979 160.218 79.051 ;
     RECT  161.1 77.999 161.442 79.051 ;
     RECT  8.928 78.629 9.738 79.141 ;
     RECT  191.415 2.413 191.697 79.177 ;
     RECT  196.596 78.899 202.95 79.181 ;
     RECT  196.596 79.181 201.906 79.205 ;
     RECT  8.928 79.141 9.954 79.229 ;
     RECT  46.656 79.051 161.442 79.249 ;
     RECT  202.932 79.181 202.95 79.373 ;
     RECT  2.304 79.051 2.697 79.411 ;
     RECT  2.304 79.411 2.934 79.475 ;
     RECT  4.068 78.809 6.966 79.483 ;
     RECT  7.704 78.665 8.097 79.483 ;
     RECT  0.108 78.667 0.558 79.547 ;
     RECT  2.376 79.475 2.934 79.591 ;
     RECT  4.068 79.483 8.097 79.591 ;
     RECT  8.928 79.229 9.738 79.591 ;
     RECT  46.656 79.249 161.622 79.591 ;
     RECT  2.376 79.591 9.738 79.619 ;
     RECT  190.944 79.177 191.697 79.619 ;
     RECT  196.74 79.205 201.906 79.709 ;
     RECT  204.228 78.359 204.246 79.723 ;
     RECT  0.108 79.547 0.162 79.757 ;
     RECT  3.42 79.619 9.738 79.757 ;
     RECT  13.215 57.209 13.497 79.951 ;
     RECT  24.015 75.677 24.297 79.951 ;
     RECT  34.815 75.677 35.097 79.951 ;
     RECT  45.615 75.677 45.897 79.951 ;
     RECT  198.396 79.709 201.906 79.951 ;
     RECT  196.74 79.709 197.55 79.987 ;
     RECT  13.104 79.951 13.497 79.997 ;
     RECT  34.704 79.951 35.097 79.997 ;
     RECT  45.504 79.951 45.897 79.997 ;
     RECT  14.832 78.871 14.85 80.015 ;
     RECT  204.192 79.723 204.246 80.107 ;
     RECT  18.615 2.413 18.897 80.131 ;
     RECT  198.396 79.951 201.942 80.131 ;
     RECT  203.472 80.107 204.246 80.159 ;
     RECT  195.948 79.987 197.55 80.285 ;
     RECT  22.392 80.221 22.41 80.519 ;
     RECT  203.472 80.159 203.526 80.525 ;
     RECT  2.376 79.619 2.697 80.555 ;
     RECT  23.904 79.951 24.297 80.671 ;
     RECT  196.344 80.285 197.55 80.671 ;
     RECT  198.396 80.131 201.978 80.671 ;
     RECT  188.676 80.023 188.694 80.699 ;
     RECT  196.344 80.671 201.978 80.789 ;
     RECT  203.472 80.525 203.49 80.789 ;
     RECT  3.564 79.757 9.738 80.905 ;
     RECT  2.415 80.555 2.697 80.941 ;
     RECT  3.564 80.905 9.99 80.941 ;
     RECT  184.68 80.401 184.698 80.969 ;
     RECT  2.415 80.941 9.99 81.211 ;
     RECT  10.836 80.941 10.854 81.329 ;
     RECT  14.832 81.211 14.85 81.329 ;
     RECT  15.984 79.483 16.002 81.365 ;
     RECT  198.324 80.789 201.978 81.451 ;
     RECT  202.896 81.259 202.914 81.451 ;
     RECT  2.415 81.211 10.026 81.485 ;
     RECT  194.436 81.409 194.454 81.509 ;
     RECT  198.324 81.451 202.914 81.571 ;
     RECT  196.344 80.789 197.586 81.607 ;
     RECT  198.324 81.571 202.95 81.677 ;
     RECT  196.308 81.607 197.586 81.715 ;
     RECT  198.324 81.677 202.914 81.715 ;
     RECT  23.4 80.671 24.297 81.905 ;
     RECT  196.308 81.715 202.914 81.985 ;
     RECT  23.652 81.905 24.297 82.049 ;
     RECT  13.215 79.997 13.497 82.111 ;
     RECT  20.592 81.211 20.61 82.111 ;
     RECT  34.815 79.997 35.097 82.111 ;
     RECT  45.615 79.997 45.897 82.111 ;
     RECT  20.592 82.111 20.862 82.157 ;
     RECT  23.904 82.049 24.297 82.157 ;
     RECT  34.704 82.111 35.097 82.157 ;
     RECT  45.504 82.111 45.897 82.157 ;
     RECT  20.592 82.157 20.61 82.175 ;
     RECT  204.228 82.027 204.246 82.219 ;
     RECT  204.192 82.219 204.246 82.319 ;
     RECT  194.364 82.291 194.382 82.381 ;
     RECT  196.164 81.985 202.914 82.411 ;
     RECT  196.164 82.411 202.95 82.517 ;
     RECT  2.415 81.485 9.99 82.699 ;
     RECT  196.308 82.517 202.95 82.751 ;
     RECT  204.192 82.319 204.21 82.787 ;
     RECT  20.34 82.831 20.358 82.949 ;
     RECT  162.54 75.235 165.33 82.957 ;
     RECT  0.108 79.757 0.126 83.029 ;
     RECT  162.504 82.957 165.33 83.057 ;
     RECT  0.108 83.029 0.558 83.117 ;
     RECT  194.364 82.381 194.454 83.129 ;
     RECT  20.52 83.101 20.538 83.191 ;
     RECT  17.1 82.381 17.118 83.219 ;
     RECT  194.364 83.129 194.382 83.219 ;
     RECT  203.472 82.987 203.49 83.219 ;
     RECT  2.304 82.699 9.99 83.255 ;
     RECT  204.228 83.179 204.246 83.563 ;
     RECT  2.415 83.255 7.038 83.597 ;
     RECT  10.764 83.497 10.782 83.597 ;
     RECT  18.615 80.131 19.458 83.641 ;
     RECT  20.52 83.191 21.222 83.641 ;
     RECT  196.308 82.751 202.338 83.641 ;
     RECT  7.776 83.255 9.99 83.731 ;
     RECT  196.308 83.641 202.374 83.767 ;
     RECT  20.52 83.641 21.438 83.789 ;
     RECT  196.056 83.767 202.374 83.789 ;
     RECT  2.415 83.597 3.294 83.795 ;
     RECT  14.832 82.651 14.85 83.795 ;
     RECT  196.056 83.789 201.942 83.875 ;
     RECT  12.564 82.111 13.497 83.939 ;
     RECT  0.108 83.117 0.162 84.077 ;
     RECT  195.84 83.875 201.942 84.145 ;
     RECT  195.732 84.145 201.942 84.173 ;
     RECT  4.068 83.597 7.038 84.181 ;
     RECT  7.776 83.731 10.206 84.181 ;
     RECT  194.436 84.109 194.454 84.181 ;
     RECT  194.364 84.181 194.454 84.271 ;
     RECT  195.732 84.173 195.858 84.299 ;
     RECT  4.068 84.181 10.206 84.331 ;
     RECT  4.068 84.331 10.458 84.365 ;
     RECT  9.972 84.365 10.458 84.371 ;
     RECT  192.672 84.307 192.69 84.479 ;
     RECT  4.068 84.365 9.234 84.605 ;
     RECT  2.415 83.795 3.258 84.619 ;
     RECT  20.52 83.789 21.222 84.677 ;
     RECT  194.364 84.271 194.958 84.713 ;
     RECT  2.304 84.619 3.258 84.721 ;
     RECT  4.068 84.605 4.482 84.721 ;
     RECT  17.928 83.641 19.458 84.721 ;
     RECT  20.52 84.677 20.538 84.721 ;
     RECT  21.456 84.685 21.474 84.721 ;
     RECT  17.928 84.721 20.538 84.749 ;
     RECT  194.364 84.713 194.454 84.749 ;
     RECT  2.304 84.721 4.482 84.839 ;
     RECT  17.928 84.749 20.286 84.839 ;
     RECT  194.364 84.749 194.382 84.839 ;
     RECT  196.668 84.173 201.942 84.875 ;
     RECT  196.704 84.875 201.942 84.907 ;
     RECT  202.896 83.947 202.914 84.911 ;
     RECT  21.456 84.721 21.978 84.941 ;
     RECT  162.54 83.057 165.33 84.955 ;
     RECT  2.304 84.839 3.654 85.145 ;
     RECT  0.108 84.077 0.126 85.195 ;
     RECT  5.292 84.605 9.234 85.261 ;
     RECT  9.972 84.371 9.99 85.261 ;
     RECT  204.192 83.563 204.246 85.261 ;
     RECT  2.415 85.145 3.654 85.289 ;
     RECT  2.415 85.289 3.222 85.379 ;
     RECT  0.108 85.195 0.162 85.415 ;
     RECT  21.96 84.941 21.978 85.415 ;
     RECT  4.392 84.839 4.482 85.423 ;
     RECT  5.292 85.261 9.99 85.423 ;
     RECT  2.415 85.379 3.186 85.649 ;
     RECT  14.256 85.387 14.274 85.649 ;
     RECT  195.516 85.531 195.534 85.657 ;
     RECT  203.508 85.261 204.246 85.675 ;
     RECT  196.704 84.907 202.05 85.757 ;
     RECT  4.392 85.423 9.99 85.765 ;
     RECT  190.404 85.657 190.422 85.793 ;
     RECT  17.928 84.839 19.458 85.801 ;
     RECT  20.268 84.839 20.286 85.801 ;
     RECT  202.896 85.675 204.246 85.829 ;
     RECT  2.415 85.649 2.826 85.963 ;
     RECT  196.704 85.757 201.942 85.991 ;
     RECT  24.015 82.157 24.297 86.071 ;
     RECT  17.928 85.801 20.286 86.197 ;
     RECT  17.928 86.197 20.358 86.225 ;
     RECT  11.196 86.197 11.214 86.237 ;
     RECT  46.656 79.591 161.766 86.251 ;
     RECT  162.54 84.955 165.366 86.251 ;
     RECT  4.14 85.765 9.99 86.297 ;
     RECT  195.3 85.657 195.534 86.305 ;
     RECT  20.34 86.225 20.358 86.341 ;
     RECT  20.34 86.341 20.43 86.369 ;
     RECT  10.188 86.341 10.206 86.431 ;
     RECT  195.3 86.305 195.57 86.459 ;
     RECT  202.932 85.829 204.246 86.459 ;
     RECT  24.015 86.071 24.57 86.495 ;
     RECT  2.376 85.963 2.826 86.539 ;
     RECT  2.304 86.539 2.826 86.611 ;
     RECT  202.932 86.459 202.95 86.669 ;
     RECT  10.188 86.431 10.278 86.729 ;
     RECT  28.512 85.081 28.53 86.729 ;
     RECT  17.928 86.225 19.458 86.765 ;
     RECT  4.14 86.297 9.306 86.837 ;
     RECT  204.156 86.459 204.246 86.873 ;
     RECT  2.304 86.611 3.042 86.881 ;
     RECT  4.14 86.837 4.698 86.881 ;
     RECT  199.404 85.991 201.942 86.881 ;
     RECT  202.896 86.827 202.914 86.881 ;
     RECT  196.704 85.991 198.594 86.971 ;
     RECT  199.404 86.881 202.914 86.971 ;
     RECT  204.228 86.873 204.246 86.999 ;
     RECT  11.628 86.881 11.646 87.035 ;
     RECT  196.704 86.971 202.914 87.053 ;
     RECT  24.015 86.495 24.534 87.305 ;
     RECT  196.704 87.053 201.87 87.307 ;
     RECT  195.3 86.459 195.318 87.341 ;
     RECT  190.44 87.241 190.458 87.413 ;
     RECT  0.108 85.415 0.126 87.499 ;
     RECT  196.344 87.307 201.87 87.511 ;
     RECT  2.304 86.881 4.698 87.539 ;
     RECT  202.896 87.053 202.914 87.583 ;
     RECT  0.108 87.499 0.162 87.611 ;
     RECT  196.272 87.511 201.87 87.611 ;
     RECT  5.508 86.837 9.306 87.691 ;
     RECT  194.364 87.349 194.382 87.781 ;
     RECT  3.456 87.539 4.698 87.809 ;
     RECT  196.704 87.611 201.87 87.869 ;
     RECT  3.744 87.809 4.698 87.961 ;
     RECT  33.876 81.607 33.894 88.079 ;
     RECT  194.364 87.781 194.454 88.187 ;
     RECT  5.508 87.691 9.414 88.231 ;
     RECT  10.188 86.729 10.206 88.231 ;
     RECT  40.215 2.413 40.497 88.231 ;
     RECT  190.404 87.547 190.422 88.259 ;
     RECT  202.896 87.583 202.95 88.259 ;
     RECT  5.508 88.231 10.206 88.349 ;
     RECT  3.744 87.961 4.734 88.393 ;
     RECT  5.508 88.349 9.414 88.393 ;
     RECT  0.108 87.611 0.126 88.459 ;
     RECT  10.188 88.349 10.206 88.591 ;
     RECT  13.215 83.939 13.497 88.591 ;
     RECT  24.015 87.305 24.297 88.591 ;
     RECT  34.815 82.157 35.097 88.591 ;
     RECT  45.615 82.157 45.897 88.591 ;
     RECT  2.304 87.539 2.697 88.655 ;
     RECT  25.56 87.421 25.578 88.663 ;
     RECT  10.188 88.591 10.854 88.691 ;
     RECT  22.824 88.591 22.842 88.691 ;
     RECT  0.108 88.459 0.558 88.727 ;
     RECT  202.932 88.259 202.95 88.747 ;
     RECT  3.744 88.393 9.414 88.771 ;
     RECT  194.436 88.187 194.454 88.799 ;
     RECT  204.228 88.171 204.246 88.799 ;
     RECT  40.215 88.231 40.554 88.889 ;
     RECT  2.376 88.655 2.697 88.925 ;
     RECT  202.932 88.747 203.49 88.973 ;
     RECT  196.815 87.869 201.87 89.005 ;
     RECT  2.415 88.925 2.697 89.041 ;
     RECT  3.636 88.771 9.414 89.041 ;
     RECT  34.704 88.591 35.097 89.165 ;
     RECT  13.104 88.591 13.497 89.168 ;
     RECT  23.904 88.591 24.297 89.168 ;
     RECT  45.504 88.591 45.897 89.168 ;
     RECT  0.108 88.727 0.162 89.261 ;
     RECT  195.084 89.269 195.102 89.309 ;
     RECT  196.815 89.005 201.942 89.515 ;
     RECT  196.815 89.515 202.338 89.581 ;
     RECT  196.668 89.581 202.338 89.609 ;
     RECT  2.415 89.041 9.414 89.707 ;
     RECT  10.188 88.691 10.206 89.707 ;
     RECT  2.415 89.707 10.206 89.744 ;
     RECT  25.56 88.663 25.65 89.779 ;
     RECT  194.364 89.707 194.382 89.879 ;
     RECT  24.015 89.168 24.297 90.013 ;
     RECT  2.415 89.744 9.414 90.077 ;
     RECT  203.472 88.973 203.49 90.091 ;
     RECT  204.228 89.899 204.246 90.091 ;
     RECT  13.215 89.168 13.497 90.211 ;
     RECT  196.668 89.609 202.05 90.235 ;
     RECT  2.415 90.077 6.606 90.239 ;
     RECT  203.472 90.091 204.246 90.239 ;
     RECT  196.596 90.235 202.05 90.391 ;
     RECT  25.56 89.779 26.262 90.419 ;
     RECT  196.164 90.391 202.05 90.419 ;
     RECT  196.164 90.419 201.87 90.481 ;
     RECT  5.652 90.239 6.606 90.509 ;
     RECT  2.415 90.239 4.914 90.545 ;
     RECT  32.58 90.391 32.598 90.545 ;
     RECT  2.415 90.545 4.806 90.617 ;
     RECT  196.092 90.481 201.87 90.653 ;
     RECT  11.412 89.851 11.43 90.689 ;
     RECT  193.248 90.553 193.266 90.689 ;
     RECT  23.724 90.013 24.297 90.787 ;
     RECT  0.108 89.261 0.126 90.815 ;
     RECT  14.832 89.473 14.85 90.815 ;
     RECT  195.084 90.619 195.102 90.815 ;
     RECT  203.472 90.239 204.21 90.851 ;
     RECT  7.776 90.077 9.414 90.895 ;
     RECT  23.724 90.787 24.498 90.923 ;
     RECT  7.704 90.895 9.414 90.931 ;
     RECT  10.188 89.744 10.206 90.931 ;
     RECT  2.415 90.617 2.898 90.955 ;
     RECT  5.76 90.509 6.606 91.021 ;
     RECT  7.524 90.931 10.206 91.021 ;
     RECT  33.012 90.661 33.03 91.021 ;
     RECT  186.015 2.413 186.297 91.057 ;
     RECT  5.76 91.021 10.206 91.085 ;
     RECT  13.215 90.211 13.698 91.085 ;
     RECT  33.012 91.021 33.282 91.085 ;
     RECT  196.02 90.931 196.038 91.085 ;
     RECT  186.015 91.057 187.002 91.229 ;
     RECT  196.815 90.653 201.87 91.243 ;
     RECT  3.744 90.617 4.806 91.291 ;
     RECT  5.76 91.085 6.858 91.291 ;
     RECT  17.676 90.553 17.694 91.355 ;
     RECT  46.656 86.251 165.366 91.387 ;
     RECT  2.304 90.955 2.898 91.435 ;
     RECT  3.744 91.291 6.858 91.435 ;
     RECT  196.815 91.243 202.338 91.435 ;
     RECT  203.472 90.851 203.49 91.435 ;
     RECT  196.815 91.435 203.49 91.471 ;
     RECT  46.656 91.387 165.618 91.561 ;
     RECT  2.304 91.435 6.858 91.625 ;
     RECT  46.656 91.561 165.906 91.661 ;
     RECT  196.488 91.471 203.49 91.819 ;
     RECT  204.228 91.627 204.246 91.819 ;
     RECT  14.256 91.669 14.274 91.895 ;
     RECT  27.36 91.903 27.378 92.011 ;
     RECT  5.544 91.625 6.858 92.039 ;
     RECT  0.108 91.627 0.126 92.107 ;
     RECT  5.544 92.039 6.822 92.129 ;
     RECT  196.488 91.819 204.246 92.237 ;
     RECT  196.488 92.237 201.834 92.245 ;
     RECT  24.015 90.923 24.498 92.371 ;
     RECT  203.436 92.237 204.246 92.399 ;
     RECT  196.308 92.245 201.834 92.435 ;
     RECT  24.015 92.371 24.75 92.471 ;
     RECT  186.015 91.229 186.426 92.471 ;
     RECT  0.108 92.107 0.162 92.491 ;
     RECT  188.676 92.137 188.694 92.543 ;
     RECT  194.364 91.057 194.382 92.579 ;
     RECT  2.304 91.625 4.806 92.669 ;
     RECT  26.784 92.011 27.378 92.705 ;
     RECT  0.108 92.491 0.558 92.777 ;
     RECT  203.436 92.399 203.526 92.813 ;
     RECT  27.36 92.705 27.378 92.939 ;
     RECT  25.56 90.419 25.578 92.947 ;
     RECT  203.436 92.813 203.49 92.971 ;
     RECT  5.544 92.129 6.606 92.983 ;
     RECT  7.632 91.085 10.206 92.983 ;
     RECT  29.415 57.581 29.697 92.983 ;
     RECT  196.815 92.435 201.834 92.983 ;
     RECT  7.488 92.983 10.206 93.019 ;
     RECT  34.815 89.165 35.097 93.019 ;
     RECT  3.564 92.669 4.806 93.055 ;
     RECT  5.544 92.983 6.678 93.055 ;
     RECT  3.564 93.055 6.678 93.091 ;
     RECT  7.488 93.019 10.854 93.091 ;
     RECT  196.815 92.983 201.87 93.091 ;
     RECT  2.304 92.669 2.826 93.119 ;
     RECT  3.564 93.091 10.854 93.119 ;
     RECT  46.656 91.661 165.366 93.181 ;
     RECT  196.815 93.091 201.942 93.181 ;
     RECT  33.264 91.085 33.282 93.209 ;
     RECT  196.668 93.181 201.942 93.209 ;
     RECT  195.66 93.055 195.678 93.217 ;
     RECT  28.62 93.091 28.638 93.245 ;
     RECT  196.668 93.209 201.87 93.253 ;
     RECT  46.656 93.181 165.906 93.293 ;
     RECT  3.564 93.119 10.242 93.317 ;
     RECT  194.436 93.091 194.454 93.325 ;
     RECT  46.656 93.293 165.618 93.341 ;
     RECT  194.364 93.325 194.454 93.353 ;
     RECT  29.415 92.983 29.754 93.361 ;
     RECT  202.896 92.971 203.49 93.389 ;
     RECT  34.776 93.019 35.097 93.445 ;
     RECT  13.215 91.085 13.497 93.451 ;
     RECT  24.015 92.471 24.297 93.451 ;
     RECT  45.615 89.168 45.897 93.451 ;
     RECT  194.364 93.353 194.382 93.479 ;
     RECT  196.488 93.253 201.87 93.479 ;
     RECT  34.704 93.445 35.097 93.485 ;
     RECT  13.104 93.451 13.497 93.488 ;
     RECT  23.904 93.451 24.297 93.488 ;
     RECT  45.504 93.451 45.897 93.488 ;
     RECT  3.636 93.317 10.242 93.515 ;
     RECT  196.668 93.479 201.87 93.515 ;
     RECT  3.852 93.515 10.242 93.587 ;
     RECT  187.524 93.325 187.542 93.659 ;
     RECT  25.56 92.947 25.686 93.749 ;
     RECT  203.436 93.389 203.49 93.749 ;
     RECT  4.032 93.587 10.242 93.785 ;
     RECT  25.56 93.749 25.578 93.785 ;
     RECT  203.436 93.749 203.454 93.821 ;
     RECT  0.108 92.777 0.126 93.835 ;
     RECT  195.516 93.217 195.678 93.901 ;
     RECT  4.212 93.785 10.242 93.931 ;
     RECT  196.704 93.515 201.87 93.965 ;
     RECT  195.516 93.901 195.858 94.019 ;
     RECT  0.108 93.835 0.162 94.055 ;
     RECT  34.776 93.485 35.097 94.055 ;
     RECT  196.812 93.965 201.87 94.135 ;
     RECT  202.896 94.123 202.914 94.135 ;
     RECT  4.212 93.931 10.854 94.199 ;
     RECT  196.812 94.135 202.914 94.199 ;
     RECT  29.415 93.361 30.438 94.289 ;
     RECT  196.812 94.199 202.374 94.325 ;
     RECT  196.815 94.325 202.374 94.349 ;
     RECT  2.304 93.119 2.697 94.411 ;
     RECT  4.32 94.199 10.854 94.469 ;
     RECT  196.815 94.349 202.338 94.559 ;
     RECT  2.304 94.411 2.754 94.567 ;
     RECT  32.508 94.441 32.526 94.595 ;
     RECT  195.66 94.019 195.858 94.675 ;
     RECT  198.36 94.559 202.338 94.739 ;
     RECT  1.728 94.567 2.754 94.829 ;
     RECT  195.66 94.675 196.074 94.829 ;
     RECT  196.815 94.559 197.406 94.829 ;
     RECT  2.415 94.829 2.754 94.909 ;
     RECT  20.412 86.369 20.43 94.925 ;
     RECT  4.32 94.469 10.206 94.939 ;
     RECT  4.104 94.939 10.206 94.945 ;
     RECT  194.364 94.711 194.382 94.973 ;
     RECT  2.415 94.909 2.862 94.981 ;
     RECT  4.068 94.945 10.206 94.981 ;
     RECT  0.108 94.055 0.126 95.179 ;
     RECT  204.228 95.083 204.246 95.279 ;
     RECT  196.815 94.829 197.37 95.369 ;
     RECT  203.472 94.891 203.49 95.369 ;
     RECT  0.108 95.179 0.558 95.477 ;
     RECT  198.36 94.739 201.798 95.485 ;
     RECT  30.42 94.289 30.438 95.513 ;
     RECT  198.36 95.485 201.834 95.521 ;
     RECT  198.144 95.521 201.834 95.639 ;
     RECT  198.144 95.639 201.798 95.647 ;
     RECT  2.415 94.981 10.206 95.675 ;
     RECT  196.815 95.369 197.19 95.683 ;
     RECT  3.924 95.675 10.206 95.945 ;
     RECT  194.436 95.791 194.454 95.953 ;
     RECT  195.66 94.829 195.858 95.989 ;
     RECT  196.668 95.683 197.19 95.989 ;
     RECT  194.364 95.953 194.454 96.025 ;
     RECT  194.364 96.025 194.49 96.089 ;
     RECT  202.896 95.851 202.914 96.151 ;
     RECT  195.66 95.989 197.19 96.179 ;
     RECT  194.472 96.089 194.49 96.215 ;
     RECT  196.02 96.179 197.19 96.221 ;
     RECT  196.815 96.221 197.19 96.331 ;
     RECT  198 95.647 201.798 96.331 ;
     RECT  196.815 96.331 201.798 96.365 ;
     RECT  180.615 2.413 180.897 96.421 ;
     RECT  198.468 96.365 201.798 96.421 ;
     RECT  198.468 96.421 201.978 96.485 ;
     RECT  198.684 96.485 201.978 96.493 ;
     RECT  202.896 96.151 202.95 96.493 ;
     RECT  198.684 96.493 202.95 96.653 ;
     RECT  202.896 96.653 202.95 96.691 ;
     RECT  0.108 95.477 0.126 96.715 ;
     RECT  198.684 96.653 201.978 96.791 ;
     RECT  2.415 95.675 2.862 96.871 ;
     RECT  179.532 96.421 179.55 96.871 ;
     RECT  0.108 96.715 0.162 96.907 ;
     RECT  2.415 96.871 3.186 96.907 ;
     RECT  4.176 95.945 10.206 96.907 ;
     RECT  2.415 96.907 10.206 96.989 ;
     RECT  21.096 95.881 21.114 96.989 ;
     RECT  196.815 96.365 197.658 96.989 ;
     RECT  180.615 96.421 181.098 96.997 ;
     RECT  179.532 96.871 179.838 97.037 ;
     RECT  202.896 96.691 202.986 97.037 ;
     RECT  24.015 93.488 24.297 97.051 ;
     RECT  178.488 96.997 178.506 97.069 ;
     RECT  180.615 96.997 181.17 97.069 ;
     RECT  24.015 97.051 24.39 97.097 ;
     RECT  178.416 97.069 178.506 97.097 ;
     RECT  192.672 96.529 192.69 97.133 ;
     RECT  178.416 97.097 178.434 97.169 ;
     RECT  180.615 97.069 181.242 97.169 ;
     RECT  13.215 93.488 13.497 97.231 ;
     RECT  198.684 96.791 201.87 97.231 ;
     RECT  196.815 96.989 197.514 97.259 ;
     RECT  2.415 96.989 2.697 97.291 ;
     RECT  195.336 96.997 195.354 97.375 ;
     RECT  22.968 97.231 22.986 97.411 ;
     RECT  196.815 97.259 197.37 97.411 ;
     RECT  195.192 97.375 195.354 97.435 ;
     RECT  195.192 97.435 195.642 97.469 ;
     RECT  195.624 97.469 195.642 97.501 ;
     RECT  196.668 97.411 197.37 97.501 ;
     RECT  43.884 96.187 43.902 97.529 ;
     RECT  2.376 97.291 2.697 97.565 ;
     RECT  194.364 97.501 194.382 97.609 ;
     RECT  198.324 97.231 201.87 97.673 ;
     RECT  194.364 97.609 194.454 97.709 ;
     RECT  22.644 97.411 22.986 97.765 ;
     RECT  202.896 97.037 202.914 97.765 ;
     RECT  22.572 97.765 22.986 97.799 ;
     RECT  22.572 97.799 22.59 97.805 ;
     RECT  202.896 97.765 202.95 97.805 ;
     RECT  13.104 97.231 13.497 97.808 ;
     RECT  3.528 96.989 10.206 97.835 ;
     RECT  195.624 97.501 197.37 97.835 ;
     RECT  0.108 96.907 0.558 97.901 ;
     RECT  2.415 97.565 2.697 97.951 ;
     RECT  3.528 97.835 4.986 97.951 ;
     RECT  204.228 97.963 204.246 98.141 ;
     RECT  196.164 97.835 197.37 98.149 ;
     RECT  198.9 97.673 201.87 98.149 ;
     RECT  203.472 98.155 203.49 98.221 ;
     RECT  198.9 98.149 202.338 98.249 ;
     RECT  203.472 98.221 203.526 98.381 ;
     RECT  198.9 98.249 201.87 98.419 ;
     RECT  2.415 97.951 4.986 98.443 ;
     RECT  196.164 98.149 197.838 98.491 ;
     RECT  195.3 98.491 195.318 98.581 ;
     RECT  195.156 98.581 195.318 98.609 ;
     RECT  195.156 98.609 195.174 98.621 ;
     RECT  2.304 98.443 4.986 98.635 ;
     RECT  5.724 97.835 10.206 98.635 ;
     RECT  196.164 98.491 197.91 98.725 ;
     RECT  198.72 98.419 201.87 98.725 ;
     RECT  203.472 98.381 203.49 98.731 ;
     RECT  0.108 97.901 0.126 98.827 ;
     RECT  0.108 98.827 0.162 98.987 ;
     RECT  196.164 98.725 201.87 99.031 ;
     RECT  196.164 99.031 202.374 99.149 ;
     RECT  2.304 98.635 10.206 99.157 ;
     RECT  196.164 99.149 201.87 99.185 ;
     RECT  1.728 99.157 10.206 99.245 ;
     RECT  2.304 99.245 10.206 99.257 ;
     RECT  194.436 98.653 194.454 99.329 ;
     RECT  46.656 93.341 165.366 99.36 ;
     RECT  13.215 97.808 13.497 99.391 ;
     RECT  24.015 97.097 24.297 99.391 ;
     RECT  34.815 94.055 35.097 99.391 ;
     RECT  27.252 99.259 27.27 99.419 ;
     RECT  28.368 99.451 28.386 99.491 ;
     RECT  196.815 99.185 201.87 99.491 ;
     RECT  42.768 99.403 42.786 99.533 ;
     RECT  46.656 99.36 55.494 99.599 ;
     RECT  45.615 93.488 45.897 99.661 ;
     RECT  46.656 99.599 55.422 99.661 ;
     RECT  203.436 98.731 203.49 99.689 ;
     RECT  45.615 99.661 55.422 99.725 ;
     RECT  146.484 99.36 165.366 99.725 ;
     RECT  198.54 99.491 201.87 99.725 ;
     RECT  146.988 99.725 165.366 99.761 ;
     RECT  2.415 99.257 10.206 99.773 ;
     RECT  202.896 99.691 202.914 99.883 ;
     RECT  45.615 99.725 45.897 99.931 ;
     RECT  2.415 99.773 10.062 99.979 ;
     RECT  2.304 99.979 10.062 99.995 ;
     RECT  202.86 99.883 202.914 100.031 ;
     RECT  146.988 99.761 147.654 100.067 ;
     RECT  40.215 88.889 40.497 100.075 ;
     RECT  148.788 99.761 165.366 100.109 ;
     RECT  0.108 98.987 0.126 100.111 ;
     RECT  149.904 100.109 165.366 100.157 ;
     RECT  0.108 100.111 0.558 100.205 ;
     RECT  148.788 100.109 148.806 100.205 ;
     RECT  2.304 99.995 9.306 100.229 ;
     RECT  39.348 100.075 39.366 100.229 ;
     RECT  40.215 100.075 41.022 100.229 ;
     RECT  2.304 100.229 4.806 100.237 ;
     RECT  195.012 100.201 195.03 100.237 ;
     RECT  20.988 100.201 21.006 100.253 ;
     RECT  5.544 100.229 9.306 100.265 ;
     RECT  22.104 100.219 22.122 100.265 ;
     RECT  196.815 99.491 197.802 100.267 ;
     RECT  204.228 100.075 204.246 100.267 ;
     RECT  1.728 100.237 4.806 100.301 ;
     RECT  146.988 100.067 147.042 100.301 ;
     RECT  195.012 100.237 195.102 100.373 ;
     RECT  1.728 100.301 2.697 100.397 ;
     RECT  204.192 100.267 204.246 100.459 ;
     RECT  196.272 100.267 197.802 100.507 ;
     RECT  3.6 100.301 4.806 100.535 ;
     RECT  23.904 99.391 24.297 100.555 ;
     RECT  195.3 100.381 195.318 100.571 ;
     RECT  82.476 100.579 82.494 100.615 ;
     RECT  196.164 100.507 197.802 100.651 ;
     RECT  198.576 99.725 201.87 100.651 ;
     RECT  22.824 100.555 22.986 100.685 ;
     RECT  38.304 100.603 38.322 100.699 ;
     RECT  22.896 100.685 22.986 100.733 ;
     RECT  38.304 100.699 38.754 100.769 ;
     RECT  196.164 100.651 202.338 100.805 ;
     RECT  148.14 100.603 148.194 100.849 ;
     RECT  22.896 100.733 22.914 100.877 ;
     RECT  23.904 100.555 24.714 100.877 ;
     RECT  148.104 100.849 148.194 100.885 ;
     RECT  18.615 86.765 19.458 100.921 ;
     RECT  29.415 94.289 29.697 100.921 ;
     RECT  40.215 100.229 40.497 100.921 ;
     RECT  0.108 100.205 0.126 100.939 ;
     RECT  18.504 100.921 19.458 100.973 ;
     RECT  29.304 100.921 29.697 100.973 ;
     RECT  40.104 100.921 40.497 100.973 ;
     RECT  3.6 100.535 4.662 101.039 ;
     RECT  149.94 100.157 165.366 101.083 ;
     RECT  147.996 100.885 148.194 101.131 ;
     RECT  2.304 100.397 2.697 101.155 ;
     RECT  147.024 100.301 147.042 101.155 ;
     RECT  5.868 100.265 9.306 101.219 ;
     RECT  149.904 101.083 165.366 101.236 ;
     RECT  5.868 101.219 9.198 101.281 ;
     RECT  46.656 99.725 55.422 101.281 ;
     RECT  203.472 100.459 204.246 101.309 ;
     RECT  144.9 101.281 144.918 101.317 ;
     RECT  147.996 101.131 148.914 101.371 ;
     RECT  149.868 101.236 165.366 101.371 ;
     RECT  3.852 101.039 4.662 101.389 ;
     RECT  119.736 101.155 119.754 101.389 ;
     RECT  120.852 101.131 120.87 101.389 ;
     RECT  3.852 101.389 4.734 101.416 ;
     RECT  2.304 101.155 2.79 101.425 ;
     RECT  119.736 101.389 120.87 101.425 ;
     RECT  119.304 101.425 120.87 101.461 ;
     RECT  147.996 101.371 165.366 101.461 ;
     RECT  61.56 101.236 61.578 101.467 ;
     RECT  146.916 101.155 147.042 101.467 ;
     RECT  57.564 101.191 57.582 101.489 ;
     RECT  61.56 101.467 61.686 101.503 ;
     RECT  67.356 100.795 67.374 101.503 ;
     RECT  83.664 99.36 83.682 101.503 ;
     RECT  104.4 101.461 104.418 101.503 ;
     RECT  143.28 101.227 143.298 101.503 ;
     RECT  56.415 101.503 56.505 101.551 ;
     RECT  61.56 101.503 61.905 101.551 ;
     RECT  68.436 101.467 68.454 101.551 ;
     RECT  72.615 101.503 72.705 101.551 ;
     RECT  78.015 101.503 78.105 101.551 ;
     RECT  88.815 101.503 88.905 101.551 ;
     RECT  99.615 101.503 99.705 101.551 ;
     RECT  126.615 101.503 126.705 101.551 ;
     RECT  132.015 101.503 132.105 101.551 ;
     RECT  67.215 101.503 67.374 101.563 ;
     RECT  2.304 101.425 3.114 101.579 ;
     RECT  65.736 101.467 65.754 101.579 ;
     RECT  68.436 101.551 69.066 101.579 ;
     RECT  79.812 99.36 79.83 101.579 ;
     RECT  81.792 100.615 82.494 101.579 ;
     RECT  97.668 101.323 97.686 101.579 ;
     RECT  101.412 101.461 101.43 101.579 ;
     RECT  119.304 101.461 121.41 101.579 ;
     RECT  196.524 100.805 202.338 101.579 ;
     RECT  75.312 101.461 75.33 101.587 ;
     RECT  77.904 101.551 78.21 101.587 ;
     RECT  103.284 101.275 103.302 101.587 ;
     RECT  196.524 101.579 197.514 101.587 ;
     RECT  13.104 99.391 13.497 101.597 ;
     RECT  23.904 100.877 24.297 101.597 ;
     RECT  34.704 99.391 35.097 101.597 ;
     RECT  45.504 99.931 45.897 101.597 ;
     RECT  60.624 101.551 60.642 101.597 ;
     RECT  64.62 101.551 64.638 101.597 ;
     RECT  144.828 101.317 144.918 101.611 ;
     RECT  198.36 101.579 202.338 101.611 ;
     RECT  196.272 101.587 197.514 101.615 ;
     RECT  130.68 101.551 130.698 101.623 ;
     RECT  138.312 101.551 138.33 101.623 ;
     RECT  139.104 101.461 139.194 101.623 ;
     RECT  145.908 100.651 145.926 101.623 ;
     RECT  146.808 101.467 147.042 101.623 ;
     RECT  69.048 101.579 69.066 101.645 ;
     RECT  126.54 101.551 126.705 101.651 ;
     RECT  130.608 101.623 130.698 101.651 ;
     RECT  198.36 101.611 202.914 101.651 ;
     RECT  45.615 101.597 45.897 101.659 ;
     RECT  46.656 101.281 55.458 101.659 ;
     RECT  70.344 101.515 70.362 101.659 ;
     RECT  83.415 101.503 83.682 101.659 ;
     RECT  84.852 99.36 84.87 101.659 ;
     RECT  104.4 101.503 105.105 101.659 ;
     RECT  144.828 101.611 145.062 101.659 ;
     RECT  145.908 101.623 147.042 101.659 ;
     RECT  102.672 101.587 103.302 101.687 ;
     RECT  70.344 101.659 70.722 101.695 ;
     RECT  72.576 101.551 72.705 101.695 ;
     RECT  142.815 101.503 143.298 101.695 ;
     RECT  99.504 101.551 99.81 101.707 ;
     RECT  144.828 101.659 147.042 101.707 ;
     RECT  147.888 101.461 165.366 101.707 ;
     RECT  126.612 101.651 126.705 101.723 ;
     RECT  130.608 101.651 130.626 101.723 ;
     RECT  138.312 101.623 139.266 101.723 ;
     RECT  58.716 101.587 58.734 101.731 ;
     RECT  72.072 101.695 72.705 101.731 ;
     RECT  81.792 101.579 81.81 101.731 ;
     RECT  83.415 101.659 84.87 101.731 ;
     RECT  87.084 101.587 87.102 101.731 ;
     RECT  88.704 101.551 89.01 101.731 ;
     RECT  94.215 101.503 94.305 101.731 ;
     RECT  99.504 101.707 100.314 101.731 ;
     RECT  119.304 101.579 120.366 101.731 ;
     RECT  142.815 101.695 143.406 101.731 ;
     RECT  67.215 101.563 67.41 101.755 ;
     RECT  61.56 101.551 62.55 101.759 ;
     RECT  104.328 101.659 105.105 101.759 ;
     RECT  204.156 101.309 204.246 101.759 ;
     RECT  104.832 101.759 105.105 101.773 ;
     RECT  110.415 101.503 110.505 101.773 ;
     RECT  115.815 101.503 115.905 101.773 ;
     RECT  121.104 101.579 121.41 101.773 ;
     RECT  126.615 101.723 126.705 101.773 ;
     RECT  131.904 101.551 132.21 101.773 ;
     RECT  137.415 101.503 137.505 101.773 ;
     RECT  138.312 101.723 139.122 101.773 ;
     RECT  144.828 101.707 165.366 101.789 ;
     RECT  24.015 101.597 24.297 101.803 ;
     RECT  29.415 100.973 29.697 101.803 ;
     RECT  34.815 101.597 35.097 101.803 ;
     RECT  40.215 100.973 40.497 101.803 ;
     RECT  67.215 101.755 67.59 101.803 ;
     RECT  71.46 101.731 72.99 101.803 ;
     RECT  83.415 101.731 85.482 101.821 ;
     RECT  86.688 101.731 87.21 101.821 ;
     RECT  97.2 101.731 97.218 101.821 ;
     RECT  18.615 100.973 19.458 101.837 ;
     RECT  137.415 101.773 139.122 101.837 ;
     RECT  65.808 101.731 65.826 101.848 ;
     RECT  24.015 101.803 24.39 101.849 ;
     RECT  29.415 101.803 29.79 101.849 ;
     RECT  34.815 101.803 35.19 101.849 ;
     RECT  40.215 101.803 40.59 101.849 ;
     RECT  45.615 101.659 55.458 101.849 ;
     RECT  70.02 101.695 70.722 101.849 ;
     RECT  71.46 101.803 73.062 101.849 ;
     RECT  81.18 101.731 81.81 101.849 ;
     RECT  98.856 101.731 100.314 101.849 ;
     RECT  108.252 101.179 108.27 101.849 ;
     RECT  118.584 101.731 120.366 101.849 ;
     RECT  137.415 101.837 138.618 101.849 ;
     RECT  142.488 101.731 143.73 101.849 ;
     RECT  114.588 101.731 114.606 101.857 ;
     RECT  144.828 101.789 145.134 101.857 ;
     RECT  64.944 101.821 64.962 101.885 ;
     RECT  65.808 101.848 66.078 101.885 ;
     RECT  70.164 101.849 70.722 101.885 ;
     RECT  75.312 101.587 75.402 101.885 ;
     RECT  83.415 101.821 87.21 101.885 ;
     RECT  119.844 101.849 120.366 101.885 ;
     RECT  144.792 101.857 145.134 101.885 ;
     RECT  196.272 101.615 197.442 101.885 ;
     RECT  42.912 101.857 42.93 101.899 ;
     RECT  46.656 101.849 55.458 101.921 ;
     RECT  65.808 101.885 65.826 101.921 ;
     RECT  61.815 101.759 62.55 101.929 ;
     RECT  94.215 101.731 94.59 101.929 ;
     RECT  144.792 101.885 144.99 101.933 ;
     RECT  0.108 100.939 0.558 101.957 ;
     RECT  42.768 101.899 42.93 101.957 ;
     RECT  58.716 101.731 58.77 101.957 ;
     RECT  96.804 101.821 97.218 101.957 ;
     RECT  114.588 101.857 114.678 101.957 ;
     RECT  120.276 101.885 120.366 101.957 ;
     RECT  144.792 101.933 144.918 101.957 ;
     RECT  73.836 101.731 73.854 101.981 ;
     RECT  3.852 101.416 4.77 102.001 ;
     RECT  67.215 101.803 67.662 102.001 ;
     RECT  83.415 101.885 85.158 102.001 ;
     RECT  94.104 101.929 94.842 102.001 ;
     RECT  96.804 101.957 96.966 102.001 ;
     RECT  118.584 101.849 118.602 102.001 ;
     RECT  137.415 101.849 138.582 102.001 ;
     RECT  42.768 101.957 42.858 102.029 ;
     RECT  94.104 102.001 94.986 102.029 ;
     RECT  120.348 101.957 120.366 102.029 ;
     RECT  145.908 101.789 165.366 102.029 ;
     RECT  199.584 101.651 202.914 102.029 ;
     RECT  3.636 102.001 4.77 102.043 ;
     RECT  5.508 101.281 9.198 102.043 ;
     RECT  67.215 102.001 68.13 102.043 ;
     RECT  108.936 102.001 108.954 102.091 ;
     RECT  112.248 102.091 112.266 102.127 ;
     RECT  56.304 101.551 57.042 102.128 ;
     RECT  10.836 101.119 10.854 102.155 ;
     RECT  96.732 102.001 96.966 102.155 ;
     RECT  108.936 102.091 109.206 102.155 ;
     RECT  3.636 102.043 9.198 102.173 ;
     RECT  110.415 101.773 110.697 102.187 ;
     RECT  111.636 102.127 112.266 102.187 ;
     RECT  92.412 102.127 92.43 102.199 ;
     RECT  2.304 101.579 2.898 102.221 ;
     RECT  30.78 102.091 30.798 102.221 ;
     RECT  42.768 102.029 42.786 102.221 ;
     RECT  199.584 102.029 202.374 102.221 ;
     RECT  109.188 102.155 109.206 102.227 ;
     RECT  194.436 102.163 194.454 102.235 ;
     RECT  196.272 101.885 197.097 102.235 ;
     RECT  67.104 102.043 68.13 102.271 ;
     RECT  90.684 102.187 90.702 102.271 ;
     RECT  92.34 102.199 92.43 102.271 ;
     RECT  95.76 101.821 95.778 102.271 ;
     RECT  194.436 102.235 195.102 102.271 ;
     RECT  58.716 101.957 58.734 102.299 ;
     RECT  70.704 101.885 70.722 102.299 ;
     RECT  96.876 102.155 96.966 102.299 ;
     RECT  145.908 102.029 147.114 102.299 ;
     RECT  88.704 101.731 89.19 102.317 ;
     RECT  92.34 102.271 92.826 102.317 ;
     RECT  103.212 101.687 103.302 102.361 ;
     RECT  196.164 102.235 197.097 102.361 ;
     RECT  74.664 102.199 74.682 102.379 ;
     RECT  92.34 102.317 92.43 102.389 ;
     RECT  94.215 102.029 94.986 102.389 ;
     RECT  110.415 102.187 112.266 102.389 ;
     RECT  86.184 101.885 87.21 102.397 ;
     RECT  106.092 102.235 106.11 102.397 ;
     RECT  71.46 101.849 71.478 102.413 ;
     RECT  4.248 102.173 9.198 102.425 ;
     RECT  90.684 102.271 90.81 102.425 ;
     RECT  95.724 102.271 95.778 102.425 ;
     RECT  194.364 102.271 195.102 102.425 ;
     RECT  95.76 102.425 95.778 102.433 ;
     RECT  98.856 101.849 100.278 102.433 ;
     RECT  106.092 102.397 106.182 102.433 ;
     RECT  113.112 102.361 113.31 102.433 ;
     RECT  82.584 102.001 85.158 102.461 ;
     RECT  110.415 102.389 110.79 102.497 ;
     RECT  198.36 101.651 198.738 102.505 ;
     RECT  66.708 102.271 68.13 102.509 ;
     RECT  0.108 101.957 0.162 102.533 ;
     RECT  198.144 102.505 198.738 102.541 ;
     RECT  199.584 102.221 201.978 102.541 ;
     RECT  74.628 102.379 74.682 102.557 ;
     RECT  86.184 102.397 87.534 102.569 ;
     RECT  88.704 102.317 89.097 102.569 ;
     RECT  90.684 102.425 90.702 102.569 ;
     RECT  98.604 102.433 100.278 102.569 ;
     RECT  103.212 102.361 103.95 102.569 ;
     RECT  106.092 102.433 106.254 102.569 ;
     RECT  113.112 102.433 113.346 102.569 ;
     RECT  118.224 102.001 118.602 102.569 ;
     RECT  121.104 101.773 121.497 102.569 ;
     RECT  131.904 101.773 132.297 102.569 ;
     RECT  134.532 102.433 134.55 102.569 ;
     RECT  136.8 102.001 138.582 102.569 ;
     RECT  204.192 101.759 204.246 102.571 ;
     RECT  110.415 102.497 110.754 102.605 ;
     RECT  113.112 102.569 113.31 102.605 ;
     RECT  86.184 102.569 87.39 102.619 ;
     RECT  5.508 102.425 9.198 102.659 ;
     RECT  198.144 102.541 201.978 102.659 ;
     RECT  196.092 102.361 197.097 102.667 ;
     RECT  198.144 102.659 201.87 102.667 ;
     RECT  196.092 102.667 201.87 102.695 ;
     RECT  95.76 102.433 95.994 102.731 ;
     RECT  204.156 102.571 204.246 102.731 ;
     RECT  56.415 102.128 57.042 102.767 ;
     RECT  95.76 102.731 95.778 102.767 ;
     RECT  86.112 102.619 87.39 102.803 ;
     RECT  144.792 101.957 144.882 102.811 ;
     RECT  146.196 102.299 147.114 102.811 ;
     RECT  147.888 102.029 165.366 102.811 ;
     RECT  136.8 102.569 138.474 102.845 ;
     RECT  61.815 101.929 62.73 102.859 ;
     RECT  74.664 102.557 74.682 102.859 ;
     RECT  86.112 102.803 86.922 102.901 ;
     RECT  204.156 102.731 204.174 102.929 ;
     RECT  72.324 101.849 73.062 102.955 ;
     RECT  74.664 102.859 74.79 102.973 ;
     RECT  58.896 102.859 58.914 102.989 ;
     RECT  61.815 102.859 62.802 102.989 ;
     RECT  10.8 102.901 10.818 103.001 ;
     RECT  18.615 101.837 18.897 103.009 ;
     RECT  86.076 102.901 86.922 103.037 ;
     RECT  72.324 102.955 73.098 103.051 ;
     RECT  144.792 102.811 144.918 103.073 ;
     RECT  196.164 102.695 201.87 103.073 ;
     RECT  4.248 102.425 4.626 103.081 ;
     RECT  56.415 102.767 57.006 103.081 ;
     RECT  61.815 102.989 62.55 103.081 ;
     RECT  74.664 102.973 74.826 103.085 ;
     RECT  86.112 103.037 86.922 103.085 ;
     RECT  98.856 102.569 98.874 103.085 ;
     RECT  56.304 103.081 57.006 103.109 ;
     RECT  72.324 103.051 73.206 103.109 ;
     RECT  144.792 103.073 144.846 103.109 ;
     RECT  146.196 102.811 165.366 103.109 ;
     RECT  202.896 102.955 202.914 103.147 ;
     RECT  4.14 103.081 4.626 103.171 ;
     RECT  130.428 101.731 130.59 103.171 ;
     RECT  61.704 103.081 62.55 103.181 ;
     RECT  74.664 103.085 74.682 103.181 ;
     RECT  70.74 102.859 70.866 103.243 ;
     RECT  82.584 102.461 83.697 103.271 ;
     RECT  66.744 102.509 68.13 103.277 ;
     RECT  99.615 102.569 100.278 103.291 ;
     RECT  142.488 101.849 143.478 103.307 ;
     RECT  202.896 103.147 203.49 103.307 ;
     RECT  82.944 103.271 83.697 103.315 ;
     RECT  144.792 103.109 144.81 103.325 ;
     RECT  74.628 103.291 74.646 103.339 ;
     RECT  66.852 103.277 68.13 103.373 ;
     RECT  69.912 103.243 70.866 103.373 ;
     RECT  194.364 102.425 194.454 103.379 ;
     RECT  0.108 102.533 0.126 103.435 ;
     RECT  3.564 103.171 4.626 103.441 ;
     RECT  5.652 102.659 9.198 103.441 ;
     RECT  45.615 101.849 45.897 103.441 ;
     RECT  46.656 101.921 55.422 103.441 ;
     RECT  69.912 103.373 69.93 103.469 ;
     RECT  82.944 103.315 84.078 103.469 ;
     RECT  86.256 103.085 86.922 103.469 ;
     RECT  70.704 103.373 70.866 103.477 ;
     RECT  111.636 102.389 112.266 103.505 ;
     RECT  196.344 103.073 201.87 103.513 ;
     RECT  45.615 103.441 55.422 103.517 ;
     RECT  70.704 103.477 71.046 103.517 ;
     RECT  74.52 103.339 74.646 103.517 ;
     RECT  98.604 103.291 98.73 103.517 ;
     RECT  99.615 103.291 100.458 103.517 ;
     RECT  130.428 103.171 130.626 103.541 ;
     RECT  2.304 102.221 2.826 103.621 ;
     RECT  3.564 103.441 9.198 103.621 ;
     RECT  86.652 103.469 86.922 103.649 ;
     RECT  13.215 101.597 13.497 103.711 ;
     RECT  24.015 101.849 24.297 103.711 ;
     RECT  45.615 103.517 45.897 103.711 ;
     RECT  88.815 102.569 89.097 103.711 ;
     RECT  99.615 103.517 99.897 103.711 ;
     RECT  121.215 102.569 121.497 103.711 ;
     RECT  132.015 102.569 132.297 103.711 ;
     RECT  61.815 103.181 62.55 103.723 ;
     RECT  110.415 102.605 110.697 103.723 ;
     RECT  126.615 101.773 126.897 103.723 ;
     RECT  13.104 103.711 13.497 103.757 ;
     RECT  23.904 103.711 24.297 103.757 ;
     RECT  45.504 103.711 45.897 103.757 ;
     RECT  196.344 103.513 202.374 103.757 ;
     RECT  94.215 102.389 94.662 103.771 ;
     RECT  2.304 103.621 9.198 103.775 ;
     RECT  10.044 99.995 10.062 103.775 ;
     RECT  86.904 103.649 86.922 103.811 ;
     RECT  110.304 103.723 110.697 103.811 ;
     RECT  126.504 103.723 126.897 103.811 ;
     RECT  18.615 103.009 19.422 103.847 ;
     RECT  84.888 102.461 85.158 103.847 ;
     RECT  61.815 103.723 62.73 103.901 ;
     RECT  77.904 101.587 78.678 103.901 ;
     RECT  90.648 103.771 90.666 103.901 ;
     RECT  94.215 103.771 94.698 103.963 ;
     RECT  94.215 103.963 94.986 104.009 ;
     RECT  31.68 103.981 31.698 104.045 ;
     RECT  32.796 104.008 32.814 104.045 ;
     RECT  95.76 104.053 95.778 104.093 ;
     RECT  113.112 102.605 113.202 104.107 ;
     RECT  0.108 103.435 0.558 104.117 ;
     RECT  104.832 101.773 105.297 104.141 ;
     RECT  196.668 103.757 202.374 104.141 ;
     RECT  67.215 103.373 68.13 104.152 ;
     RECT  10.836 104.059 10.854 104.189 ;
     RECT  22.824 104.059 22.842 104.189 ;
     RECT  30.78 103.723 30.798 104.189 ;
     RECT  42.768 103.477 42.786 104.189 ;
     RECT  112.86 104.107 113.202 104.285 ;
     RECT  56.304 103.109 56.697 104.288 ;
     RECT  67.104 104.152 68.13 104.288 ;
     RECT  77.904 103.901 78.297 104.288 ;
     RECT  88.704 103.711 89.097 104.288 ;
     RECT  99.504 103.711 99.897 104.288 ;
     RECT  121.104 103.711 121.497 104.288 ;
     RECT  131.904 103.711 132.297 104.288 ;
     RECT  2.415 103.775 9.198 104.323 ;
     RECT  103.212 102.569 103.734 104.423 ;
     RECT  2.415 104.323 9.234 104.477 ;
     RECT  4.536 104.477 9.234 104.549 ;
     RECT  106.956 104.395 106.974 104.549 ;
     RECT  108.072 104.395 108.09 104.549 ;
     RECT  196.668 104.141 201.87 104.557 ;
     RECT  4.536 104.549 8.694 104.657 ;
     RECT  196.488 104.557 201.87 104.657 ;
     RECT  0.108 104.117 0.162 104.729 ;
     RECT  146.196 103.109 146.466 104.923 ;
     RECT  147.312 103.109 165.366 104.923 ;
     RECT  136.8 102.845 138.33 104.927 ;
     RECT  196.488 104.657 197.406 104.935 ;
     RECT  130.428 103.541 130.446 104.963 ;
     RECT  94.215 104.009 94.662 104.971 ;
     RECT  94.215 104.971 94.734 105.089 ;
     RECT  194.436 103.379 194.454 105.097 ;
     RECT  146.196 104.923 165.366 105.101 ;
     RECT  2.415 104.477 3.618 105.125 ;
     RECT  194.436 105.097 194.49 105.169 ;
     RECT  111.636 103.505 111.654 105.197 ;
     RECT  203.436 103.307 203.49 105.197 ;
     RECT  198.36 104.657 201.87 105.259 ;
     RECT  4.536 104.657 8.514 105.269 ;
     RECT  194.364 105.169 194.49 105.269 ;
     RECT  4.536 105.269 4.734 105.331 ;
     RECT  45.615 103.757 45.897 105.331 ;
     RECT  46.656 103.517 55.422 105.331 ;
     RECT  2.415 105.125 2.862 105.355 ;
     RECT  194.94 105.307 194.958 105.359 ;
     RECT  203.436 105.197 203.454 105.359 ;
     RECT  198.36 105.259 202.338 105.451 ;
     RECT  5.472 105.269 8.514 105.467 ;
     RECT  142.488 103.307 143.097 105.467 ;
     RECT  5.472 105.467 8.118 105.503 ;
     RECT  118.224 102.569 118.242 105.503 ;
     RECT  195.912 104.935 197.406 105.511 ;
     RECT  198.36 105.451 202.914 105.511 ;
     RECT  103.716 104.423 103.734 105.533 ;
     RECT  188.352 102.163 188.37 105.539 ;
     RECT  195.912 105.511 202.914 105.665 ;
     RECT  84.888 103.847 84.906 105.737 ;
     RECT  7.815 105.503 8.118 105.773 ;
     RECT  191.415 79.619 191.697 105.781 ;
     RECT  196.776 105.665 202.914 105.809 ;
     RECT  13.215 103.757 13.497 105.871 ;
     RECT  24.015 103.757 24.297 105.871 ;
     RECT  29.415 101.849 29.697 105.871 ;
     RECT  34.815 101.849 35.097 105.871 ;
     RECT  45.615 105.331 55.422 105.871 ;
     RECT  56.415 104.288 56.697 105.871 ;
     RECT  67.215 104.288 68.13 105.871 ;
     RECT  78.015 104.288 78.297 105.871 ;
     RECT  88.815 104.288 89.097 105.871 ;
     RECT  99.615 104.288 99.897 105.871 ;
     RECT  121.215 104.288 121.497 105.871 ;
     RECT  132.015 104.288 132.297 105.871 ;
     RECT  3.672 105.331 4.734 105.899 ;
     RECT  45.504 105.871 55.422 105.899 ;
     RECT  146.196 105.101 146.502 105.917 ;
     RECT  2.376 105.355 2.862 105.931 ;
     RECT  0.108 104.729 0.126 105.935 ;
     RECT  5.472 105.503 6.858 106.027 ;
     RECT  137.415 104.927 138.33 106.043 ;
     RECT  3.672 105.899 4.626 106.061 ;
     RECT  191.415 105.781 192.114 106.079 ;
     RECT  196.776 105.809 202.338 106.079 ;
     RECT  196.776 106.079 201.798 106.157 ;
     RECT  5.4 106.027 6.858 106.169 ;
     RECT  10.8 106.051 10.818 106.169 ;
     RECT  196.776 106.157 201.654 106.169 ;
     RECT  204.228 105.067 204.246 106.169 ;
     RECT  195.876 106.051 195.894 106.171 ;
     RECT  28.764 105.871 29.898 106.205 ;
     RECT  195.732 106.171 195.894 106.211 ;
     RECT  0.54 106.123 0.558 106.277 ;
     RECT  5.436 106.169 6.858 106.285 ;
     RECT  63.72 101.731 63.738 106.301 ;
     RECT  2.304 105.931 2.862 106.321 ;
     RECT  5.436 106.285 6.966 106.321 ;
     RECT  7.815 105.773 8.097 106.321 ;
     RECT  194.436 106.249 194.454 106.321 ;
     RECT  194.364 106.321 194.454 106.349 ;
     RECT  67.104 105.871 68.13 106.411 ;
     RECT  34.704 105.871 35.097 106.445 ;
     RECT  13.104 105.871 13.497 106.448 ;
     RECT  23.904 105.871 24.297 106.448 ;
     RECT  45.504 105.899 45.897 106.448 ;
     RECT  56.304 105.871 56.697 106.448 ;
     RECT  66.6 106.411 68.13 106.448 ;
     RECT  5.436 106.321 8.097 106.475 ;
     RECT  81.18 101.849 81.198 106.493 ;
     RECT  194.364 106.349 194.382 106.511 ;
     RECT  196.776 106.169 201.546 106.591 ;
     RECT  203.436 106.219 203.49 106.603 ;
     RECT  61.815 103.901 62.55 106.781 ;
     RECT  146.196 105.917 146.466 106.843 ;
     RECT  2.304 106.321 3.402 106.861 ;
     RECT  67.215 106.448 68.13 106.877 ;
     RECT  77.904 105.871 78.297 106.889 ;
     RECT  88.704 105.871 89.097 106.889 ;
     RECT  99.504 105.871 99.897 106.889 ;
     RECT  121.104 105.871 121.497 106.889 ;
     RECT  131.904 105.871 132.297 106.889 ;
     RECT  142.704 105.467 143.097 106.889 ;
     RECT  190.44 106.717 190.458 106.889 ;
     RECT  5.472 106.475 8.097 106.979 ;
     RECT  196.2 106.591 201.546 107.015 ;
     RECT  146.196 106.843 146.502 107.021 ;
     RECT  72.324 103.109 72.897 107.069 ;
     RECT  198.612 107.015 201.546 107.095 ;
     RECT  2.304 106.861 3.51 107.131 ;
     RECT  4.284 106.061 4.626 107.131 ;
     RECT  78.015 106.889 78.297 107.227 ;
     RECT  198.612 107.095 201.798 107.249 ;
     RECT  0.108 106.699 0.126 107.365 ;
     RECT  202.896 106.603 203.49 107.393 ;
     RECT  195.228 106.747 195.246 107.401 ;
     RECT  77.076 102.001 77.094 107.405 ;
     RECT  78.015 107.227 78.39 107.405 ;
     RECT  5.544 106.979 8.097 107.429 ;
     RECT  183.564 106.951 183.582 107.429 ;
     RECT  195.228 107.401 195.426 107.491 ;
     RECT  0.108 107.365 0.558 107.501 ;
     RECT  68.364 107.323 68.382 107.519 ;
     RECT  194.904 107.491 195.426 107.519 ;
     RECT  2.304 107.131 4.662 107.555 ;
     RECT  67.215 106.877 67.59 107.555 ;
     RECT  194.904 107.519 195.246 107.555 ;
     RECT  202.932 107.393 203.49 107.597 ;
     RECT  5.544 107.429 6.318 107.741 ;
     RECT  3.852 107.555 4.662 107.755 ;
     RECT  5.544 107.741 6.066 107.755 ;
     RECT  203.436 107.597 203.49 107.755 ;
     RECT  204.228 106.987 204.246 107.755 ;
     RECT  126.615 103.811 126.897 107.761 ;
     RECT  196.704 107.015 197.622 107.761 ;
     RECT  198.612 107.249 201.762 107.761 ;
     RECT  128.376 107.371 128.394 107.789 ;
     RECT  126.54 107.761 126.897 107.837 ;
     RECT  203.436 107.755 204.246 107.861 ;
     RECT  196.704 107.761 201.762 107.869 ;
     RECT  82.944 103.469 83.697 107.885 ;
     RECT  146.196 107.021 146.466 107.899 ;
     RECT  196.56 107.869 201.762 107.899 ;
     RECT  194.904 107.555 194.922 107.969 ;
     RECT  13.215 106.448 13.497 108.031 ;
     RECT  24.015 106.448 24.297 108.031 ;
     RECT  34.815 106.445 35.097 108.031 ;
     RECT  56.415 106.448 56.697 108.031 ;
     RECT  67.215 107.555 67.497 108.031 ;
     RECT  78.015 107.405 78.297 108.031 ;
     RECT  88.815 106.889 89.097 108.031 ;
     RECT  99.615 106.889 99.897 108.031 ;
     RECT  110.415 103.811 110.697 108.031 ;
     RECT  121.215 106.889 121.497 108.031 ;
     RECT  132.015 106.889 132.297 108.031 ;
     RECT  142.815 106.889 143.097 108.031 ;
     RECT  196.308 107.899 201.762 108.059 ;
     RECT  13.104 108.031 13.497 108.077 ;
     RECT  23.904 108.031 24.297 108.077 ;
     RECT  34.704 108.031 35.097 108.077 ;
     RECT  56.304 108.031 56.697 108.077 ;
     RECT  67.104 108.031 67.497 108.077 ;
     RECT  77.904 108.031 78.297 108.077 ;
     RECT  88.704 108.031 89.097 108.077 ;
     RECT  99.504 108.031 99.897 108.077 ;
     RECT  110.304 108.031 110.697 108.077 ;
     RECT  121.104 108.031 121.497 108.077 ;
     RECT  131.904 108.031 132.297 108.077 ;
     RECT  142.704 108.031 143.097 108.077 ;
     RECT  146.196 107.899 146.502 108.077 ;
     RECT  191.415 106.079 191.697 108.103 ;
     RECT  45.615 106.448 45.897 108.139 ;
     RECT  46.656 105.899 55.422 108.139 ;
     RECT  42.768 108.043 42.786 108.173 ;
     RECT  198.36 108.059 201.762 108.211 ;
     RECT  45.615 108.139 55.422 108.239 ;
     RECT  194.364 108.103 194.382 108.239 ;
     RECT  2.304 107.555 2.697 108.301 ;
     RECT  3.852 107.755 6.066 108.301 ;
     RECT  46.656 108.239 55.422 108.329 ;
     RECT  186.015 92.471 186.297 108.409 ;
     RECT  190.944 108.103 191.697 108.509 ;
     RECT  7.092 107.429 8.097 108.619 ;
     RECT  6.84 108.619 8.37 108.749 ;
     RECT  196.308 108.059 197.622 108.841 ;
     RECT  198.36 108.211 201.87 108.841 ;
     RECT  7.128 108.749 8.37 108.869 ;
     RECT  9.144 108.751 9.162 108.869 ;
     RECT  2.304 108.301 6.066 108.905 ;
     RECT  203.472 107.861 204.246 108.907 ;
     RECT  2.415 108.905 6.066 109.139 ;
     RECT  203.436 108.907 204.246 109.139 ;
     RECT  5.58 109.139 6.066 109.175 ;
     RECT  0.108 107.501 0.126 109.195 ;
     RECT  0.108 109.195 0.162 109.291 ;
     RECT  196.308 108.841 201.87 109.291 ;
     RECT  0.108 109.291 0.558 109.421 ;
     RECT  0.108 109.421 0.162 109.445 ;
     RECT  2.415 109.139 4.806 109.445 ;
     RECT  196.308 109.291 202.302 109.445 ;
     RECT  196.308 109.445 201.87 109.561 ;
     RECT  186.015 108.409 187.002 109.589 ;
     RECT  3.42 109.445 4.77 109.679 ;
     RECT  203.436 109.139 203.454 109.679 ;
     RECT  196.092 109.561 201.87 109.787 ;
     RECT  147.312 105.101 165.366 109.823 ;
     RECT  196.092 109.787 201.762 109.859 ;
     RECT  13.215 108.077 13.497 110.191 ;
     RECT  195.12 109.993 195.138 110.219 ;
     RECT  13.104 110.191 13.497 110.237 ;
     RECT  202.896 110.059 202.914 110.251 ;
     RECT  46.656 108.329 55.35 110.291 ;
     RECT  17.856 110.183 17.874 110.335 ;
     RECT  18.615 103.847 18.897 110.335 ;
     RECT  6.984 110.371 7.002 110.488 ;
     RECT  7.815 108.869 8.097 110.488 ;
     RECT  6.984 110.488 8.097 110.525 ;
     RECT  3.708 109.679 4.734 110.587 ;
     RECT  5.688 109.175 6.066 110.587 ;
     RECT  202.824 110.251 202.914 110.597 ;
     RECT  3.708 110.587 6.066 110.621 ;
     RECT  196.815 109.859 201.762 110.641 ;
     RECT  204.192 109.139 204.246 110.731 ;
     RECT  3.708 110.621 5.814 110.795 ;
     RECT  196.308 110.641 201.762 110.803 ;
     RECT  196.308 110.803 202.374 110.861 ;
     RECT  196.308 110.861 201.87 110.869 ;
     RECT  196.164 110.869 201.87 110.909 ;
     RECT  6.804 110.641 6.93 111.029 ;
     RECT  17.856 110.335 18.897 111.053 ;
     RECT  3.96 110.795 5.814 111.065 ;
     RECT  2.415 109.445 2.697 111.115 ;
     RECT  6.912 111.029 6.93 111.137 ;
     RECT  147.312 109.823 162.27 111.137 ;
     RECT  196.815 110.909 201.87 111.299 ;
     RECT  3.96 111.065 5.598 111.541 ;
     RECT  191.415 108.509 191.697 111.541 ;
     RECT  195.048 110.227 195.066 111.577 ;
     RECT  196.815 111.299 201.798 111.641 ;
     RECT  2.304 111.115 2.697 111.649 ;
     RECT  3.78 111.541 5.598 111.649 ;
     RECT  191.415 111.541 191.754 111.713 ;
     RECT  203.508 110.731 204.246 111.787 ;
     RECT  2.304 111.649 5.598 111.811 ;
     RECT  2.304 111.811 5.742 111.839 ;
     RECT  195.048 111.577 195.102 111.847 ;
     RECT  2.304 111.839 4.698 111.875 ;
     RECT  5.436 111.839 5.742 111.875 ;
     RECT  194.436 111.847 195.102 111.991 ;
     RECT  203.472 111.787 204.246 112.013 ;
     RECT  2.304 111.875 3.114 112.019 ;
     RECT  0.108 109.445 0.126 112.075 ;
     RECT  0.108 112.075 0.162 112.217 ;
     RECT  5.472 111.875 5.742 112.261 ;
     RECT  6.84 111.991 6.858 112.261 ;
     RECT  203.472 112.013 203.49 112.363 ;
     RECT  4.068 111.875 4.698 112.379 ;
     RECT  203.436 112.363 203.49 112.379 ;
     RECT  2.304 112.019 2.697 112.415 ;
     RECT  4.068 112.379 4.59 112.415 ;
     RECT  196.815 111.641 201.69 112.415 ;
     RECT  194.364 111.991 195.102 112.423 ;
     RECT  198.288 112.415 201.69 112.495 ;
     RECT  196.815 112.415 197.514 112.621 ;
     RECT  5.472 112.261 6.858 112.651 ;
     RECT  7.815 110.525 8.097 112.651 ;
     RECT  204.228 112.013 204.246 112.747 ;
     RECT  194.364 112.423 195.21 112.793 ;
     RECT  4.068 112.415 4.554 112.801 ;
     RECT  34.815 108.077 35.097 112.885 ;
     RECT  24.015 108.077 24.297 112.891 ;
     RECT  94.215 105.089 94.497 112.891 ;
     RECT  99.615 108.077 99.897 112.891 ;
     RECT  34.704 112.885 35.097 112.925 ;
     RECT  3.96 112.801 4.554 112.927 ;
     RECT  42.732 112.891 42.75 112.927 ;
     RECT  23.904 112.891 24.297 112.928 ;
     RECT  99.504 112.891 99.897 112.928 ;
     RECT  198.288 112.495 201.834 112.939 ;
     RECT  5.472 112.651 8.097 112.955 ;
     RECT  204.192 112.747 204.246 112.955 ;
     RECT  42.408 112.927 42.75 112.973 ;
     RECT  91.008 112.927 91.026 112.973 ;
     RECT  196.092 112.621 197.514 112.999 ;
     RECT  94.215 112.891 94.626 113.021 ;
     RECT  38.772 112.891 38.79 113.069 ;
     RECT  42.732 112.973 42.75 113.069 ;
     RECT  92.556 112.987 92.574 113.099 ;
     RECT  203.436 112.379 203.454 113.131 ;
     RECT  3.78 112.927 4.554 113.197 ;
     RECT  198.288 112.939 201.87 113.233 ;
     RECT  195.444 112.999 197.514 113.269 ;
     RECT  198.252 113.233 201.87 113.269 ;
     RECT  5.472 112.955 6.714 113.297 ;
     RECT  7.704 112.955 8.097 113.333 ;
     RECT  2.415 112.415 2.697 113.341 ;
     RECT  3.78 113.197 4.59 113.341 ;
     RECT  5.472 113.297 6.318 113.341 ;
     RECT  194.364 112.793 194.382 113.369 ;
     RECT  195.444 113.269 201.87 113.405 ;
     RECT  204.228 112.955 204.246 113.459 ;
     RECT  2.415 113.341 6.318 113.495 ;
     RECT  202.896 113.131 203.454 113.515 ;
     RECT  3.852 113.495 6.318 113.531 ;
     RECT  147.312 111.137 162.234 113.597 ;
     RECT  2.415 113.495 3.042 113.729 ;
     RECT  3.852 113.531 6.21 113.729 ;
     RECT  2.415 113.729 2.862 113.803 ;
     RECT  194.436 113.701 194.454 113.873 ;
     RECT  196.164 113.405 201.87 113.885 ;
     RECT  196.815 113.885 201.87 113.899 ;
     RECT  202.896 113.515 203.49 113.899 ;
     RECT  196.815 113.899 203.49 113.909 ;
     RECT  147.312 113.597 162.162 113.981 ;
     RECT  46.656 110.291 55.242 114.035 ;
     RECT  6.984 114.151 7.002 114.269 ;
     RECT  2.304 113.803 2.862 114.511 ;
     RECT  3.852 113.729 6.174 114.511 ;
     RECT  203.472 113.909 203.49 114.539 ;
     RECT  2.304 114.511 6.174 114.571 ;
     RECT  0.108 112.217 0.126 114.763 ;
     RECT  2.304 114.571 6.894 114.845 ;
     RECT  140.544 114.781 140.562 114.893 ;
     RECT  194.472 114.781 194.49 114.925 ;
     RECT  0.108 114.763 0.558 114.953 ;
     RECT  142.815 108.077 143.097 114.961 ;
     RECT  194.364 114.925 194.49 114.962 ;
     RECT  132.015 108.077 132.297 115.051 ;
     RECT  196.815 113.909 202.374 115.051 ;
     RECT  194.364 114.962 194.454 115.079 ;
     RECT  131.904 115.051 132.297 115.088 ;
     RECT  0.108 114.953 0.162 115.115 ;
     RECT  194.436 115.079 194.454 115.151 ;
     RECT  142.164 114.961 143.097 115.181 ;
     RECT  121.215 108.077 121.497 115.339 ;
     RECT  119.052 115.051 119.07 115.349 ;
     RECT  120.6 115.339 121.497 115.385 ;
     RECT  196.668 115.051 202.374 115.457 ;
     RECT  195.228 115.465 195.246 115.501 ;
     RECT  195.228 115.501 195.498 115.517 ;
     RECT  190.404 115.321 190.422 115.529 ;
     RECT  204.228 114.475 204.246 115.529 ;
     RECT  50.148 114.035 55.242 115.591 ;
     RECT  56.415 108.077 56.697 115.591 ;
     RECT  2.415 114.845 6.822 115.624 ;
     RECT  2.415 115.624 6.894 115.691 ;
     RECT  7.815 113.333 8.097 115.723 ;
     RECT  6.876 115.691 6.894 115.757 ;
     RECT  7.815 115.723 8.478 115.771 ;
     RECT  195.48 115.517 195.498 115.799 ;
     RECT  196.704 115.457 202.374 115.819 ;
     RECT  203.472 115.435 203.49 115.819 ;
     RECT  2.415 115.691 5.922 115.915 ;
     RECT  194.508 115.735 194.526 115.969 ;
     RECT  2.304 115.915 5.922 115.997 ;
     RECT  46.656 114.035 49.158 116.005 ;
     RECT  50.148 115.591 56.697 116.005 ;
     RECT  194.436 115.969 194.526 116.005 ;
     RECT  7.38 115.771 8.478 116.033 ;
     RECT  194.4 116.005 194.526 116.033 ;
     RECT  194.4 116.033 194.454 116.041 ;
     RECT  194.364 116.041 194.454 116.069 ;
     RECT  2.304 115.997 5.85 116.159 ;
     RECT  9.396 116.041 9.414 116.159 ;
     RECT  7.815 116.033 8.478 116.195 ;
     RECT  0.108 115.115 0.126 116.299 ;
     RECT  196.704 115.819 203.49 116.429 ;
     RECT  2.304 116.159 5.778 116.465 ;
     RECT  195.768 116.545 195.786 116.581 ;
     RECT  196.704 116.429 201.834 116.581 ;
     RECT  202.896 116.429 203.49 116.581 ;
     RECT  202.896 116.581 203.526 116.587 ;
     RECT  194.364 116.069 194.418 116.609 ;
     RECT  195.768 116.581 201.834 116.735 ;
     RECT  202.896 116.587 204.246 116.813 ;
     RECT  0.108 116.299 0.558 116.843 ;
     RECT  195.768 116.735 195.786 116.851 ;
     RECT  195.3 116.851 195.786 116.875 ;
     RECT  195.084 116.875 195.786 117.005 ;
     RECT  190.404 116.941 190.422 117.113 ;
     RECT  2.415 116.465 5.778 117.121 ;
     RECT  195.3 117.005 195.786 117.149 ;
     RECT  196.815 116.735 201.834 117.163 ;
     RECT  196.815 117.163 201.87 117.275 ;
     RECT  2.415 117.121 5.922 117.481 ;
     RECT  2.415 117.481 6.174 117.499 ;
     RECT  195.948 117.499 195.966 117.545 ;
     RECT  202.896 116.813 203.49 117.581 ;
     RECT  7.815 116.195 8.097 117.589 ;
     RECT  196.815 117.275 197.37 117.589 ;
     RECT  184.68 117.355 184.698 117.617 ;
     RECT  0.108 116.843 0.126 117.643 ;
     RECT  147.312 113.981 161.766 117.643 ;
     RECT  163.044 109.823 165.366 117.643 ;
     RECT  194.436 117.589 194.454 117.661 ;
     RECT  194.364 117.661 194.454 117.689 ;
     RECT  2.415 117.499 6.426 117.751 ;
     RECT  7.38 117.589 8.097 117.751 ;
     RECT  196.092 117.589 197.37 117.779 ;
     RECT  167.004 117.751 167.022 117.781 ;
     RECT  0.108 117.643 0.162 117.815 ;
     RECT  46.656 116.005 56.697 117.821 ;
     RECT  166.824 117.781 167.022 117.821 ;
     RECT  147.312 117.643 165.366 117.917 ;
     RECT  186.015 109.589 186.297 117.931 ;
     RECT  2.415 117.751 8.097 117.959 ;
     RECT  5.472 117.959 8.097 117.965 ;
     RECT  167.004 117.821 167.022 118.049 ;
     RECT  172.224 117.787 172.242 118.061 ;
     RECT  173.772 117.751 173.79 118.061 ;
     RECT  193.248 117.859 193.266 118.157 ;
     RECT  198.18 117.275 201.87 118.157 ;
     RECT  196.488 117.779 197.37 118.165 ;
     RECT  198.18 118.157 201.834 118.165 ;
     RECT  186.015 117.931 187.002 118.229 ;
     RECT  2.415 117.959 4.554 118.411 ;
     RECT  194.364 117.689 194.382 118.499 ;
     RECT  147.312 117.917 161.766 118.589 ;
     RECT  202.932 117.581 203.49 118.661 ;
     RECT  2.304 118.411 4.554 118.741 ;
     RECT  5.472 117.965 6.03 118.741 ;
     RECT  6.804 117.965 6.822 118.741 ;
     RECT  2.304 118.741 6.03 118.795 ;
     RECT  6.804 118.741 6.93 118.829 ;
     RECT  2.304 118.795 6.066 119.011 ;
     RECT  196.488 118.165 201.834 119.011 ;
     RECT  196.416 119.011 201.834 119.083 ;
     RECT  2.304 119.011 6.21 119.129 ;
     RECT  196.416 119.083 202.338 119.129 ;
     RECT  0.108 117.815 0.126 119.371 ;
     RECT  203.184 118.661 203.49 119.399 ;
     RECT  46.656 117.821 47.826 119.471 ;
     RECT  2.304 119.129 6.03 119.479 ;
     RECT  186.015 118.229 186.297 119.515 ;
     RECT  48.96 117.821 56.697 119.579 ;
     RECT  0.108 119.371 0.162 119.705 ;
     RECT  196.668 119.129 202.338 119.741 ;
     RECT  185.832 119.515 186.297 119.849 ;
     RECT  198.828 119.741 202.338 119.851 ;
     RECT  203.184 119.399 203.202 119.851 ;
     RECT  196.668 119.741 198.054 119.975 ;
     RECT  2.268 119.479 6.03 119.981 ;
     RECT  204.228 116.813 204.246 120.043 ;
     RECT  2.415 119.981 6.03 120.091 ;
     RECT  6.984 119.515 7.002 120.091 ;
     RECT  195.732 119.245 195.894 120.125 ;
     RECT  2.415 120.091 7.002 120.181 ;
     RECT  2.415 120.181 7.074 120.209 ;
     RECT  198.828 119.851 203.202 120.209 ;
     RECT  186.015 119.849 186.297 120.217 ;
     RECT  6.876 120.209 7.074 120.269 ;
     RECT  48.996 119.579 56.697 120.281 ;
     RECT  196.668 119.975 197.838 120.289 ;
     RECT  204.192 120.043 204.246 120.479 ;
     RECT  0.108 119.705 0.126 120.514 ;
     RECT  47.52 119.471 47.826 120.557 ;
     RECT  198.828 120.209 201.978 120.631 ;
     RECT  0.108 120.514 0.162 120.659 ;
     RECT  196.272 120.289 197.838 120.721 ;
     RECT  198.612 120.631 201.978 120.721 ;
     RECT  2.415 120.209 6.03 120.749 ;
     RECT  47.808 120.557 47.826 120.749 ;
     RECT  196.272 120.721 201.978 120.797 ;
     RECT  49.032 120.281 56.697 120.821 ;
     RECT  46.656 119.471 46.746 120.829 ;
     RECT  194.364 120.523 194.382 120.991 ;
     RECT  46.62 120.829 46.746 121.127 ;
     RECT  46.62 121.127 46.638 121.163 ;
     RECT  194.364 120.991 194.454 121.199 ;
     RECT  6.876 120.269 6.894 121.261 ;
     RECT  7.815 117.965 8.097 121.261 ;
     RECT  6.876 121.261 8.097 121.289 ;
     RECT  196.815 120.797 201.978 121.361 ;
     RECT  7.38 121.289 8.097 121.373 ;
     RECT  199.008 121.361 201.978 121.387 ;
     RECT  202.86 120.209 203.202 121.387 ;
     RECT  204.228 120.479 204.246 121.579 ;
     RECT  0.108 120.659 0.126 121.675 ;
     RECT  196.815 121.361 197.946 121.711 ;
     RECT  186.015 120.217 186.426 121.829 ;
     RECT  2.415 120.749 5.598 121.867 ;
     RECT  194.364 121.199 194.382 121.973 ;
     RECT  0.108 121.675 0.162 122.251 ;
     RECT  2.304 121.867 5.598 122.251 ;
     RECT  6.804 122.245 6.822 122.251 ;
     RECT  7.815 121.373 8.097 122.251 ;
     RECT  196.776 121.711 197.946 122.251 ;
     RECT  199.008 121.387 203.202 122.251 ;
     RECT  2.304 122.251 6.966 122.285 ;
     RECT  195.84 121.435 195.858 122.377 ;
     RECT  196.776 122.251 203.202 122.377 ;
     RECT  22.32 122.341 22.338 122.381 ;
     RECT  7.74 122.251 8.154 122.429 ;
     RECT  195.84 122.377 203.202 122.449 ;
     RECT  0.108 122.251 0.558 122.477 ;
     RECT  195.66 122.449 203.202 122.521 ;
     RECT  22.5 122.491 22.518 122.549 ;
     RECT  195.624 122.521 203.202 122.587 ;
     RECT  195.48 122.587 203.202 122.675 ;
     RECT  204.192 121.579 204.246 122.675 ;
     RECT  197.928 122.675 203.202 122.819 ;
     RECT  195.48 122.675 197.097 122.909 ;
     RECT  197.928 122.819 202.914 122.909 ;
     RECT  9 122.251 9.018 122.945 ;
     RECT  197.928 122.909 198.81 122.945 ;
     RECT  199.728 122.909 202.914 122.945 ;
     RECT  117.972 122.881 117.99 122.957 ;
     RECT  102.24 122.923 102.258 122.981 ;
     RECT  198.108 122.945 198.522 122.981 ;
     RECT  118.656 122.971 118.674 123.017 ;
     RECT  204.228 122.675 204.246 123.017 ;
     RECT  2.304 122.285 2.79 123.061 ;
     RECT  3.636 122.285 6.966 123.061 ;
     RECT  7.74 122.429 8.097 123.061 ;
     RECT  110.415 108.077 110.697 123.061 ;
     RECT  195.624 122.909 197.097 123.089 ;
     RECT  198.108 122.981 198.126 123.089 ;
     RECT  2.304 123.061 8.097 123.149 ;
     RECT  199.872 122.945 202.914 123.179 ;
     RECT  9.144 123.061 9.162 123.215 ;
     RECT  201.096 123.179 202.338 123.287 ;
     RECT  3.708 123.149 8.097 123.331 ;
     RECT  146.196 108.077 146.466 123.331 ;
     RECT  196.092 123.089 197.097 123.359 ;
     RECT  0.108 122.477 0.126 123.403 ;
     RECT  21.456 123.307 21.474 123.421 ;
     RECT  21.456 123.421 22.158 123.449 ;
     RECT  129.24 123.331 129.258 123.449 ;
     RECT  199.872 123.179 199.998 123.449 ;
     RECT  201.096 123.287 202.266 123.449 ;
     RECT  105.015 104.141 105.297 123.457 ;
     RECT  0.108 123.403 0.558 123.485 ;
     RECT  30.708 123.421 30.726 123.485 ;
     RECT  31.824 123.448 31.842 123.485 ;
     RECT  99.615 112.928 99.897 123.499 ;
     RECT  199.872 123.449 199.89 123.521 ;
     RECT  22.14 123.449 22.158 123.533 ;
     RECT  0.144 123.485 0.558 123.557 ;
     RECT  99.288 123.499 99.897 123.565 ;
     RECT  13.215 110.237 13.497 123.691 ;
     RECT  121.215 115.385 121.497 123.691 ;
     RECT  132.015 115.088 132.297 123.691 ;
     RECT  142.815 115.181 143.097 123.691 ;
     RECT  102.06 123.061 102.078 123.719 ;
     RECT  201.24 123.449 201.618 123.719 ;
     RECT  99.18 123.565 99.897 123.727 ;
     RECT  13.104 123.691 13.497 123.728 ;
     RECT  121.104 123.691 121.497 123.728 ;
     RECT  131.904 123.691 132.297 123.728 ;
     RECT  142.704 123.691 143.097 123.728 ;
     RECT  98.964 123.727 99.897 123.739 ;
     RECT  100.8 123.691 100.818 123.739 ;
     RECT  3.708 123.331 8.19 123.755 ;
     RECT  196.632 123.359 197.097 123.791 ;
     RECT  98.964 123.739 100.818 123.799 ;
     RECT  108.288 122.917 108.306 123.821 ;
     RECT  146.196 123.331 146.502 123.821 ;
     RECT  0.144 123.557 0.162 123.863 ;
     RECT  201.6 123.719 201.618 123.863 ;
     RECT  22.824 123.691 22.842 123.869 ;
     RECT  2.304 123.149 2.697 123.871 ;
     RECT  3.708 123.755 4.194 123.871 ;
     RECT  26.28 123.835 26.298 123.871 ;
     RECT  29.415 106.205 29.697 123.871 ;
     RECT  26.28 123.871 26.802 123.979 ;
     RECT  2.304 123.871 4.194 123.989 ;
     RECT  5.364 123.755 8.19 123.989 ;
     RECT  26.28 123.979 27.414 123.989 ;
     RECT  98.964 123.799 101.61 123.989 ;
     RECT  2.304 123.989 2.697 124.025 ;
     RECT  5.508 123.989 8.19 124.025 ;
     RECT  26.784 123.989 27.414 124.025 ;
     RECT  26.784 124.025 26.802 124.061 ;
     RECT  29.415 123.871 29.754 124.061 ;
     RECT  100.764 123.989 100.998 124.061 ;
     RECT  102.6 123.871 102.618 124.069 ;
     RECT  5.796 124.025 8.19 124.109 ;
     RECT  102.6 124.069 103.194 124.109 ;
     RECT  102.6 124.109 103.086 124.133 ;
     RECT  195.876 123.871 195.894 124.133 ;
     RECT  28.548 124.075 28.566 124.169 ;
     RECT  98.964 123.989 99.897 124.253 ;
     RECT  3.6 123.989 4.194 124.259 ;
     RECT  5.94 124.109 8.19 124.259 ;
     RECT  3.6 124.259 4.122 124.295 ;
     RECT  25.884 124.267 25.902 124.363 ;
     RECT  4.104 124.295 4.122 124.403 ;
     RECT  6.048 124.259 8.19 124.439 ;
     RECT  108.324 123.961 108.342 124.439 ;
     RECT  25.2 124.363 25.902 124.529 ;
     RECT  110.415 123.061 111.042 124.537 ;
     RECT  96.912 124.507 96.93 124.681 ;
     RECT  110.34 124.537 111.042 124.681 ;
     RECT  104.328 123.457 105.297 124.709 ;
     RECT  19.836 124.501 19.854 124.771 ;
     RECT  96.912 124.681 97.11 124.771 ;
     RECT  97.92 124.681 97.938 124.771 ;
     RECT  19.836 124.771 20.43 124.795 ;
     RECT  103.068 124.133 103.086 124.799 ;
     RECT  110.304 124.681 111.042 124.799 ;
     RECT  96.912 124.771 97.938 124.807 ;
     RECT  110.304 124.799 110.697 124.807 ;
     RECT  19.728 124.795 20.43 124.829 ;
     RECT  19.728 124.829 19.746 124.835 ;
     RECT  96.804 124.807 97.938 124.915 ;
     RECT  96.804 124.915 98.082 125.069 ;
     RECT  94.215 113.021 94.497 125.113 ;
     RECT  94.215 125.113 94.662 125.213 ;
     RECT  100.98 124.061 100.998 125.311 ;
     RECT  100.908 125.311 100.998 125.339 ;
     RECT  100.908 125.339 100.926 125.405 ;
     RECT  113.184 125.419 113.202 125.609 ;
     RECT  121.215 123.728 121.497 125.851 ;
     RECT  132.015 123.728 132.297 125.851 ;
     RECT  142.815 123.728 143.097 125.851 ;
     RECT  121.104 125.851 121.497 125.888 ;
     RECT  131.904 125.851 132.297 125.888 ;
     RECT  144.792 125.851 144.81 125.981 ;
     RECT  67.215 108.077 67.497 125.995 ;
     RECT  109.512 124.807 110.697 125.995 ;
     RECT  112.788 125.761 112.95 126.221 ;
     RECT  146.196 123.821 146.466 126.269 ;
     RECT  67.068 125.995 67.497 126.463 ;
     RECT  66.708 126.463 67.497 126.509 ;
     RECT  137.415 106.043 137.697 126.523 ;
     RECT  142.704 125.851 143.097 126.523 ;
     RECT  101.556 126.391 101.574 126.571 ;
     RECT  109.44 125.995 110.697 126.571 ;
     RECT  139.896 126.121 139.914 126.571 ;
     RECT  101.556 126.571 101.862 126.605 ;
     RECT  137.415 126.523 138.546 126.653 ;
     RECT  142.488 126.523 143.097 126.653 ;
     RECT  137.415 126.653 138.366 126.689 ;
     RECT  142.704 126.653 143.097 126.749 ;
     RECT  101.844 126.605 101.862 126.763 ;
     RECT  109.008 126.571 110.697 126.769 ;
     RECT  139.608 126.571 139.914 126.797 ;
     RECT  137.415 126.689 137.697 126.805 ;
     RECT  101.844 126.763 101.934 126.995 ;
     RECT  101.916 126.995 101.934 127.037 ;
     RECT  136.692 126.805 137.697 127.037 ;
     RECT  105.015 124.709 105.297 127.099 ;
     RECT  132.015 125.888 132.297 127.099 ;
     RECT  7.308 124.439 8.19 127.139 ;
     RECT  49.248 120.821 56.697 127.187 ;
     RECT  61.815 106.781 62.097 127.187 ;
     RECT  67.215 126.509 67.497 127.187 ;
     RECT  72.615 107.069 72.897 127.187 ;
     RECT  78.015 108.077 78.297 127.187 ;
     RECT  83.415 107.885 83.697 127.187 ;
     RECT  88.815 108.077 89.097 127.187 ;
     RECT  94.215 125.213 94.497 127.187 ;
     RECT  99.18 124.253 99.897 127.187 ;
     RECT  104.4 127.099 105.297 127.187 ;
     RECT  108.828 126.769 110.697 127.187 ;
     RECT  115.815 101.773 116.097 127.187 ;
     RECT  121.215 125.888 121.497 127.187 ;
     RECT  126.615 107.837 126.897 127.187 ;
     RECT  131.328 127.099 132.297 127.187 ;
     RECT  137.415 127.037 137.697 127.187 ;
     RECT  142.815 126.749 143.097 127.187 ;
     RECT  147.312 118.589 161.73 127.187 ;
     RECT  104.4 127.187 105.105 127.229 ;
     RECT  131.328 127.187 132.105 127.229 ;
     RECT  104.076 127.237 104.094 127.277 ;
     RECT  130.968 127.291 130.986 127.337 ;
     RECT  149.184 127.187 161.73 127.409 ;
     RECT  108.828 127.187 110.505 127.421 ;
     RECT  147.312 127.187 148.41 127.421 ;
     RECT  49.248 127.187 56.505 127.457 ;
     RECT  61.815 127.187 61.905 127.457 ;
     RECT  67.215 127.187 67.305 127.457 ;
     RECT  72.615 127.187 72.705 127.457 ;
     RECT  78.015 127.187 78.105 127.457 ;
     RECT  83.415 127.187 83.505 127.457 ;
     RECT  88.815 127.187 88.905 127.457 ;
     RECT  94.215 127.187 94.305 127.457 ;
     RECT  99.18 127.187 99.705 127.457 ;
     RECT  105.015 127.229 105.105 127.457 ;
     RECT  110.415 127.421 110.505 127.457 ;
     RECT  115.815 127.187 115.905 127.457 ;
     RECT  121.215 127.187 121.305 127.457 ;
     RECT  126.615 127.187 126.705 127.457 ;
     RECT  132.015 127.229 132.105 127.457 ;
     RECT  137.415 127.187 137.505 127.457 ;
     RECT  142.815 127.187 142.905 127.457 ;
     RECT  147.312 127.421 148.305 127.457 ;
     RECT  146.34 126.269 146.466 127.613 ;
     RECT  96.804 125.069 97.794 127.709 ;
     RECT  99.18 127.457 99.198 127.709 ;
     RECT  108.828 127.421 109.458 127.709 ;
     RECT  97.776 127.709 97.794 127.757 ;
     RECT  108.828 127.709 108.846 127.949 ;
     RECT  58.716 127.201 58.734 128.525 ;
     RECT  139.896 126.797 139.914 128.525 ;
     RECT  147.312 127.457 148.194 128.669 ;
     RECT  146.376 127.613 146.466 128.776 ;
     RECT  146.34 128.776 146.466 128.812 ;
     RECT  147.6 128.669 148.194 128.821 ;
     RECT  149.184 127.409 160.434 128.821 ;
     RECT  146.34 128.812 146.43 128.849 ;
     RECT  147.6 128.821 160.434 129.163 ;
     RECT  6.048 124.439 6.066 129.425 ;
     RECT  49.248 127.457 55.89 129.6 ;
     RECT  109.98 129.355 109.998 129.6 ;
     RECT  112.932 126.221 112.95 129.6 ;
     RECT  146.34 128.849 146.358 129.6 ;
     RECT  147.6 129.163 160.506 129.6 ;
     RECT  161.352 127.409 161.73 133.079 ;
     RECT  49.248 129.6 160.506 135.485 ;
     RECT  49.248 135.485 53.442 136.637 ;
     RECT  163.044 117.917 165.366 137.489 ;
     RECT  49.248 136.637 52.11 137.693 ;
     RECT  52.992 136.637 53.442 137.789 ;
     RECT  49.248 137.693 52.074 138.173 ;
     RECT  10.116 123.331 10.134 138.569 ;
     RECT  49.248 138.173 52.038 138.605 ;
     RECT  52.992 137.789 53.01 138.845 ;
     RECT  54.36 135.485 160.506 139.037 ;
     RECT  49.248 138.605 51.57 139.723 ;
     RECT  161.352 133.079 161.586 140.099 ;
     RECT  49.248 139.723 52.038 140.189 ;
     RECT  49.248 140.189 51.57 140.765 ;
     RECT  49.248 140.765 51.39 140.861 ;
     RECT  54.36 139.037 54.378 140.957 ;
     RECT  161.352 140.099 161.514 141.035 ;
     RECT  161.352 141.035 161.37 141.377 ;
     RECT  49.248 140.861 49.986 141.389 ;
     RECT  49.86 141.389 49.986 141.437 ;
     RECT  49.896 141.437 49.986 141.581 ;
     RECT  49.968 141.581 49.986 141.629 ;
     RECT  7.308 127.139 8.097 141.845 ;
     RECT  50.976 140.861 51.39 141.869 ;
     RECT  55.296 139.037 160.506 144.859 ;
     RECT  44.136 141.781 44.154 145.049 ;
     RECT  49.32 145.201 49.338 145.325 ;
     RECT  55.188 144.859 160.506 146.849 ;
     RECT  55.188 146.849 159.297 147.209 ;
     RECT  55.188 147.209 158.094 147.869 ;
     RECT  158.868 147.209 159.297 147.929 ;
     RECT  163.584 137.489 165.366 149.909 ;
     RECT  160.2 146.849 160.506 153.355 ;
     RECT  55.296 147.869 158.094 153.689 ;
     RECT  160.2 153.355 160.65 153.689 ;
     RECT  55.296 153.689 157.806 154.373 ;
     RECT  55.296 154.373 156.618 154.679 ;
     RECT  155.16 154.679 156.618 154.949 ;
     RECT  155.808 154.949 156.618 155.219 ;
     RECT  163.584 149.909 164.697 155.281 ;
     RECT  155.808 155.219 156.366 155.309 ;
     RECT  163.332 155.281 164.697 155.357 ;
     RECT  55.296 154.679 154.098 155.453 ;
     RECT  153.324 155.453 154.098 155.489 ;
     RECT  155.808 155.309 155.826 155.579 ;
     RECT  55.296 155.453 152.586 155.645 ;
     RECT  157.788 154.373 157.806 156.427 ;
     RECT  159.015 147.929 159.297 156.427 ;
     RECT  157.788 156.427 159.297 156.557 ;
     RECT  55.296 155.645 152.478 156.859 ;
     RECT  159.015 156.557 159.297 156.859 ;
     RECT  55.296 156.859 152.55 156.929 ;
     RECT  159.015 156.859 159.39 156.929 ;
     RECT  163.584 155.357 164.697 158.429 ;
     RECT  164.196 158.429 164.697 158.459 ;
     RECT  153.324 155.489 154.026 158.549 ;
     RECT  160.2 153.689 160.506 159.485 ;
     RECT  55.296 156.929 152.478 161.899 ;
     RECT  55.296 161.899 152.55 162.077 ;
     RECT  153.396 158.549 154.026 162.173 ;
     RECT  153.396 162.173 153.897 162.331 ;
     RECT  153.324 162.331 153.897 162.461 ;
     RECT  160.2 159.485 160.218 163.757 ;
     RECT  157.788 156.557 157.806 165.883 ;
     RECT  159.015 156.929 159.297 165.883 ;
     RECT  157.788 165.883 159.297 166.013 ;
     RECT  55.296 162.077 152.478 166.189 ;
     RECT  54.108 166.261 54.126 166.351 ;
     RECT  54.108 166.351 54.162 166.397 ;
     RECT  54.144 166.397 54.162 166.423 ;
     RECT  55.188 166.189 152.478 166.423 ;
     RECT  153.396 162.461 153.897 166.423 ;
     RECT  53.1 165.847 53.118 166.685 ;
     RECT  54.144 166.423 152.478 167.131 ;
     RECT  157.788 166.013 157.806 167.227 ;
     RECT  159.015 166.013 159.297 167.227 ;
     RECT  153.324 166.423 153.897 167.261 ;
     RECT  153.504 167.261 153.897 167.369 ;
     RECT  52.704 167.341 52.722 167.459 ;
     RECT  164.232 158.459 164.697 167.639 ;
     RECT  157.788 167.227 159.297 167.837 ;
     RECT  54.108 167.131 152.478 167.881 ;
     RECT  53.604 167.881 152.478 168.029 ;
     RECT  53.712 168.029 152.478 168.611 ;
     RECT  54.684 168.611 152.478 168.893 ;
     RECT  153.615 167.369 153.897 168.952 ;
     RECT  53.712 168.611 53.802 168.955 ;
     RECT  153.504 168.952 153.897 168.989 ;
     RECT  53.604 168.955 53.802 168.995 ;
     RECT  53.784 168.995 53.802 169.151 ;
     RECT  54.684 168.893 152.334 169.339 ;
     RECT  157.788 167.837 157.806 169.373 ;
     RECT  54.648 169.339 152.334 169.531 ;
     RECT  54.108 169.531 152.334 169.925 ;
     RECT  55.152 169.925 152.334 170.159 ;
     RECT  54.108 169.925 54.126 170.465 ;
     RECT  55.296 170.159 152.334 170.64 ;
     RECT  146.484 170.64 146.502 170.861 ;
     RECT  150.48 170.64 152.334 171.311 ;
     RECT  150.48 171.311 152.262 171.347 ;
     RECT  150.48 171.347 151.65 171.851 ;
     RECT  110.844 171.547 110.862 172.783 ;
     RECT  121.968 172.699 121.986 172.783 ;
     RECT  121.215 172.783 121.986 172.859 ;
     RECT  126.615 172.783 126.705 172.975 ;
     RECT  150.48 171.851 151.218 173.003 ;
     RECT  151.128 173.003 151.218 173.039 ;
     RECT  56.415 172.783 56.505 173.053 ;
     RECT  61.815 172.783 61.905 173.053 ;
     RECT  67.215 172.783 67.305 173.053 ;
     RECT  72.615 172.783 72.705 173.053 ;
     RECT  78.015 172.783 78.105 173.053 ;
     RECT  83.415 172.783 83.505 173.053 ;
     RECT  88.815 172.783 88.905 173.053 ;
     RECT  94.215 172.783 94.305 173.053 ;
     RECT  99.615 172.783 99.705 173.053 ;
     RECT  105.015 172.783 105.105 173.053 ;
     RECT  115.815 172.783 115.905 173.053 ;
     RECT  126.504 172.975 126.705 173.053 ;
     RECT  132.015 172.783 132.105 173.053 ;
     RECT  137.415 172.783 137.505 173.053 ;
     RECT  142.815 172.783 142.905 173.053 ;
     RECT  148.215 172.783 148.305 173.053 ;
     RECT  124.056 173.011 124.074 173.129 ;
     RECT  126.504 173.053 126.897 173.201 ;
     RECT  123.084 171.823 123.102 173.281 ;
     RECT  122.94 173.281 123.102 173.371 ;
     RECT  132.015 173.053 132.297 173.371 ;
     RECT  142.815 173.053 143.097 173.371 ;
     RECT  122.472 173.371 123.102 173.408 ;
     RECT  131.904 173.371 132.297 173.408 ;
     RECT  142.704 173.371 143.097 173.408 ;
     RECT  146.484 173.371 146.502 173.501 ;
     RECT  122.94 173.408 123.102 173.669 ;
     RECT  119.952 173.551 119.97 173.821 ;
     RECT  151.2 173.039 151.218 173.939 ;
     RECT  112.248 174.427 112.266 174.479 ;
     RECT  111.744 174.523 111.762 174.56 ;
     RECT  104.184 170.64 104.202 177.211 ;
     RECT  105.015 173.053 105.297 177.211 ;
     RECT  110.415 172.783 110.862 185.803 ;
     RECT  107.172 170.64 107.874 185.971 ;
     RECT  109.44 185.803 110.862 186.089 ;
     RECT  110.196 186.089 110.862 186.125 ;
     RECT  99.615 173.053 99.897 186.133 ;
     RECT  106.596 185.971 107.874 186.133 ;
     RECT  106.596 186.133 108.126 186.161 ;
     RECT  107.172 186.161 108.126 186.205 ;
     RECT  109.44 186.089 109.458 186.205 ;
     RECT  109.224 186.205 109.458 186.233 ;
     RECT  110.196 186.125 110.697 186.269 ;
     RECT  109.224 186.233 109.242 186.359 ;
     RECT  119.376 173.821 119.97 186.359 ;
     RECT  99.615 186.133 100.566 189.259 ;
     RECT  98.604 190.363 98.622 190.411 ;
     RECT  107.172 186.205 108.198 190.411 ;
     RECT  97.92 190.411 98.622 190.525 ;
     RECT  99.432 189.259 100.566 190.525 ;
     RECT  104.184 177.211 105.297 190.525 ;
     RECT  107.064 190.411 108.198 190.687 ;
     RECT  106.884 190.687 108.198 190.831 ;
     RECT  118.26 173.101 118.278 190.859 ;
     RECT  96.912 190.831 96.93 190.939 ;
     RECT  97.848 190.525 100.566 190.939 ;
     RECT  101.664 170.64 101.682 190.939 ;
     RECT  97.848 190.939 101.682 190.949 ;
     RECT  122.94 173.669 122.958 191.057 ;
     RECT  106.884 190.831 108.342 191.065 ;
     RECT  117.108 173.947 117.126 191.093 ;
     RECT  96.912 190.939 96.966 191.101 ;
     RECT  119.376 186.359 119.394 191.129 ;
     RECT  96.012 191.065 96.03 191.219 ;
     RECT  106.884 191.065 108.882 191.219 ;
     RECT  106.884 191.219 108.378 191.263 ;
     RECT  98.172 190.949 101.682 191.335 ;
     RECT  96.912 191.101 97.362 191.371 ;
     RECT  106.596 191.263 108.378 191.399 ;
     RECT  103.716 190.525 105.297 191.461 ;
     RECT  103.716 191.461 105.642 191.489 ;
     RECT  106.884 191.399 108.378 191.489 ;
     RECT  102.672 191.641 102.69 191.759 ;
     RECT  96.048 191.371 97.362 191.911 ;
     RECT  98.172 191.335 101.754 191.911 ;
     RECT  104.292 191.489 105.642 191.911 ;
     RECT  2.415 124.025 2.697 191.987 ;
     RECT  7.815 141.845 8.097 191.987 ;
     RECT  13.215 123.728 13.497 191.987 ;
     RECT  18.615 111.053 18.897 191.987 ;
     RECT  24.015 112.928 24.297 191.987 ;
     RECT  29.415 124.061 29.697 191.987 ;
     RECT  34.815 112.925 35.097 191.987 ;
     RECT  40.215 101.849 40.497 191.987 ;
     RECT  45.615 108.239 45.897 191.987 ;
     RECT  51.015 141.869 51.297 191.987 ;
     RECT  56.415 173.053 56.697 191.987 ;
     RECT  61.815 173.053 62.097 191.987 ;
     RECT  67.215 173.053 67.497 191.987 ;
     RECT  72.615 173.053 72.897 191.987 ;
     RECT  78.015 173.053 78.297 191.987 ;
     RECT  83.415 173.053 83.697 191.987 ;
     RECT  88.815 173.053 89.097 191.987 ;
     RECT  94.215 173.053 94.497 191.987 ;
     RECT  110.415 186.269 110.697 191.987 ;
     RECT  115.815 173.053 116.097 191.987 ;
     RECT  121.215 172.859 121.497 191.987 ;
     RECT  126.615 173.201 126.897 191.987 ;
     RECT  132.015 173.408 132.297 191.987 ;
     RECT  137.415 173.053 137.697 191.987 ;
     RECT  142.815 173.408 143.097 191.987 ;
     RECT  148.215 173.053 148.497 191.987 ;
     RECT  153.615 168.989 153.897 191.987 ;
     RECT  159.015 167.837 159.297 191.987 ;
     RECT  164.415 167.639 164.697 191.987 ;
     RECT  169.815 2.413 170.097 191.987 ;
     RECT  175.215 2.413 175.497 191.987 ;
     RECT  180.615 97.169 180.897 191.987 ;
     RECT  186.015 121.829 186.297 191.987 ;
     RECT  191.415 111.713 191.697 191.987 ;
     RECT  196.815 123.791 197.097 191.987 ;
     RECT  96.048 191.911 101.754 192.029 ;
     RECT  107.136 191.489 108.378 192.029 ;
     RECT  96.048 192.029 98.478 192.065 ;
     RECT  99.252 192.029 101.61 192.065 ;
     RECT  104.292 191.911 106.002 192.077 ;
     RECT  99.252 192.065 101.07 192.101 ;
     RECT  95.868 192.073 95.886 192.125 ;
     RECT  97.704 192.065 97.722 192.125 ;
     RECT  99.324 192.101 101.07 192.125 ;
     RECT  107.172 192.029 108.27 192.173 ;
     RECT  99.324 192.125 100.422 192.209 ;
     RECT  2.415 191.987 2.505 192.257 ;
     RECT  7.815 191.987 7.905 192.257 ;
     RECT  13.215 191.987 13.305 192.257 ;
     RECT  18.615 191.987 18.705 192.257 ;
     RECT  24.015 191.987 24.105 192.257 ;
     RECT  29.415 191.987 29.505 192.257 ;
     RECT  34.815 191.987 34.905 192.257 ;
     RECT  40.215 191.987 40.305 192.257 ;
     RECT  45.615 191.987 45.705 192.257 ;
     RECT  51.015 191.987 51.105 192.257 ;
     RECT  56.415 191.987 56.505 192.257 ;
     RECT  61.815 191.987 61.905 192.257 ;
     RECT  67.215 191.987 67.305 192.257 ;
     RECT  72.615 191.987 72.705 192.257 ;
     RECT  78.015 191.987 78.105 192.257 ;
     RECT  83.415 191.987 83.505 192.257 ;
     RECT  88.815 191.987 88.905 192.257 ;
     RECT  94.215 191.987 94.305 192.257 ;
     RECT  99.324 192.209 99.705 192.257 ;
     RECT  104.292 192.077 105.714 192.257 ;
     RECT  110.415 191.987 110.505 192.257 ;
     RECT  115.815 191.987 115.905 192.257 ;
     RECT  121.215 191.987 121.305 192.257 ;
     RECT  126.615 191.987 126.705 192.257 ;
     RECT  132.015 191.987 132.105 192.257 ;
     RECT  137.415 191.987 137.505 192.257 ;
     RECT  142.815 191.987 142.905 192.257 ;
     RECT  148.215 191.987 148.305 192.257 ;
     RECT  153.615 191.987 153.705 192.257 ;
     RECT  159.015 191.987 159.105 192.257 ;
     RECT  164.415 191.987 164.505 192.257 ;
     RECT  169.815 191.987 169.905 192.257 ;
     RECT  175.215 191.987 175.305 192.257 ;
     RECT  180.615 191.987 180.705 192.257 ;
     RECT  186.015 191.987 186.105 192.257 ;
     RECT  191.415 191.987 191.505 192.257 ;
     RECT  196.815 191.987 196.905 192.257 ;
     RECT  99.324 192.257 99.342 192.413 ;
     RECT  104.292 192.257 104.31 192.653 ;
     RECT  105.696 192.257 105.714 192.653 ;
     RECT  107.172 192.173 107.19 192.653 ;
     RECT  108.252 192.173 108.27 192.653 ;
     RECT  96.732 192.065 96.75 193.277 ;
     RECT  98.46 192.065 98.478 193.277 ;
    LAYER M4 ;
     RECT  0.06 70.608 0.137 123.816 ;
     RECT  0.137 70.608 0.173 89.256 ;
     RECT  0.137 90.576 0.173 120.552 ;
     RECT  0.137 121.68 0.173 123.816 ;
     RECT  0.173 71.184 0.569 83.112 ;
     RECT  0.173 84.624 0.569 88.488 ;
     RECT  0.173 90.576 0.569 104.04 ;
     RECT  0.173 105.36 0.569 119.976 ;
     RECT  0.569 71.184 2.408 72.936 ;
     RECT  0.569 74.064 2.408 76.056 ;
     RECT  0.569 77.328 2.408 77.928 ;
     RECT  0.569 79.056 2.408 82.728 ;
     RECT  0.569 84.624 2.408 88.296 ;
     RECT  0.569 90.576 2.408 94.824 ;
     RECT  0.569 95.952 2.408 95.976 ;
     RECT  0.569 97.296 2.408 97.32 ;
     RECT  0.569 98.448 2.408 103.656 ;
     RECT  0.569 105.36 2.408 108.84 ;
     RECT  0.569 109.968 2.408 115.944 ;
     RECT  0.569 117.264 2.408 119.976 ;
     RECT  0.173 121.872 2.408 123.624 ;
     RECT  2.408 2.148 2.512 192.252 ;
     RECT  2.512 2.418 2.704 191.982 ;
     RECT  2.704 81.216 2.765 82.536 ;
     RECT  2.704 84.864 2.765 85.416 ;
     RECT  2.704 90.576 2.765 90.6 ;
     RECT  2.704 94.416 2.765 94.44 ;
     RECT  2.704 114.528 2.765 118.152 ;
     RECT  2.765 114.528 2.837 116.712 ;
     RECT  2.704 72.048 3.395 72.984 ;
     RECT  2.704 79.728 3.449 79.752 ;
     RECT  2.765 118.128 3.449 118.152 ;
     RECT  2.837 114.528 3.673 114.552 ;
     RECT  2.704 103.248 3.769 105.096 ;
     RECT  2.704 106.848 3.769 107.352 ;
     RECT  2.704 102.096 3.841 102.216 ;
     RECT  2.704 76.032 3.913 76.056 ;
     RECT  3.769 103.248 3.949 107.352 ;
     RECT  2.704 108.336 3.949 108.888 ;
     RECT  3.841 113.424 3.949 113.448 ;
     RECT  2.704 119.664 3.949 119.688 ;
     RECT  2.704 120.864 3.949 123.144 ;
     RECT  3.913 75.792 3.957 76.056 ;
     RECT  2.704 92.304 3.971 92.328 ;
     RECT  3.697 74.736 3.973 74.76 ;
     RECT  3.913 77.808 3.973 77.832 ;
     RECT  3.973 77.808 3.985 78.312 ;
     RECT  3.973 74.448 4.019 74.76 ;
     RECT  3.957 75.792 4.019 76.392 ;
     RECT  3.985 77.808 4.019 78.744 ;
     RECT  3.949 119.664 4.021 123.192 ;
     RECT  4.019 74.448 4.061 74.664 ;
     RECT  4.019 78.288 4.241 78.744 ;
     RECT  3.769 110.208 4.381 110.232 ;
     RECT  3.697 87.264 4.385 87.288 ;
     RECT  2.837 115.728 4.421 116.712 ;
     RECT  2.704 96.912 4.453 96.936 ;
     RECT  2.704 98.208 4.453 98.232 ;
     RECT  3.949 103.248 4.493 108.888 ;
     RECT  4.093 94.944 4.517 94.968 ;
     RECT  3.913 88.896 4.561 88.92 ;
     RECT  3.841 101.424 4.561 102.216 ;
     RECT  4.493 103.248 4.561 106.056 ;
     RECT  2.765 81.216 4.565 82.152 ;
     RECT  4.381 110.208 4.565 110.664 ;
     RECT  4.241 78.72 4.601 78.744 ;
     RECT  4.561 87.936 4.601 88.92 ;
     RECT  3.769 91.152 4.601 91.176 ;
     RECT  3.925 93.504 4.601 93.528 ;
     RECT  4.453 96.912 4.601 98.232 ;
     RECT  4.549 90 4.637 90.024 ;
     RECT  2.704 100.272 4.673 100.296 ;
     RECT  4.517 94.56 4.853 94.968 ;
     RECT  4.565 82.08 4.885 82.152 ;
     RECT  4.421 116.688 4.889 116.712 ;
     RECT  3.395 72.96 4.993 72.984 ;
     RECT  4.993 72.96 5.029 73.512 ;
     RECT  4.561 101.424 5.077 106.056 ;
     RECT  5.077 101.376 5.249 106.056 ;
     RECT  4.061 74.64 5.317 74.664 ;
     RECT  4.601 97.392 5.317 98.232 ;
     RECT  5.317 74.64 5.401 75.288 ;
     RECT  5.401 74.64 5.465 74.664 ;
     RECT  2.765 84.864 5.465 84.888 ;
     RECT  5.249 101.376 5.468 104.808 ;
     RECT  5.029 72.768 5.497 73.512 ;
     RECT  3.949 112.848 5.509 113.448 ;
     RECT  3.769 111.744 5.533 111.768 ;
     RECT  5.509 112.848 5.533 113.736 ;
     RECT  5.533 111.744 5.573 113.736 ;
     RECT  5.573 112.272 5.609 113.736 ;
     RECT  4.019 76.368 5.612 76.392 ;
     RECT  5.249 106.032 5.641 106.056 ;
     RECT  4.493 107.184 5.641 108.888 ;
     RECT  5.609 113.376 5.677 113.736 ;
     RECT  5.497 72.48 5.699 73.512 ;
     RECT  5.612 76.368 5.699 77.256 ;
     RECT  5.317 97.392 5.701 98.664 ;
     RECT  4.741 91.824 5.708 91.848 ;
     RECT  5.641 106.032 5.713 108.888 ;
     RECT  4.957 86.448 5.749 86.472 ;
     RECT  5.569 116.448 5.749 116.472 ;
     RECT  4.021 119.664 5.785 124.008 ;
     RECT  5.708 91.008 5.795 91.848 ;
     RECT  5.425 93.072 5.821 93.096 ;
     RECT  4.853 94.656 5.821 94.968 ;
     RECT  5.701 97.248 5.821 98.664 ;
     RECT  5.821 93.072 5.861 94.968 ;
     RECT  5.713 106.032 5.941 109.416 ;
     RECT  4.565 110.592 5.941 110.664 ;
     RECT  4.885 82.08 5.957 82.44 ;
     RECT  5.468 101.328 5.989 104.808 ;
     RECT  4.601 87.936 6.001 87.96 ;
     RECT  5.785 119.664 6.037 124.104 ;
     RECT  6.037 118.8 6.041 124.536 ;
     RECT  5.699 76.368 6.044 76.392 ;
     RECT  5.569 96.144 6.109 96.168 ;
     RECT  6.044 75.792 6.131 76.392 ;
     RECT  5.941 106.032 6.133 110.664 ;
     RECT  5.749 86.448 6.173 86.616 ;
     RECT  5.699 72.48 6.217 72.84 ;
     RECT  6.073 78.672 6.217 78.696 ;
     RECT  6.173 85.488 6.257 86.616 ;
     RECT  5.989 101.04 6.257 104.808 ;
     RECT  6.001 87.936 6.325 88.248 ;
     RECT  6.133 106.032 6.325 111.048 ;
     RECT  6.217 79.728 6.361 79.752 ;
     RECT  6.257 101.04 6.373 104.328 ;
     RECT  6.041 120.24 6.373 124.536 ;
     RECT  5.605 117.504 6.397 117.528 ;
     RECT  6.041 118.8 6.397 118.824 ;
     RECT  6.397 117.504 6.437 118.824 ;
     RECT  6.325 87.936 6.467 88.92 ;
     RECT  5.317 57.312 6.469 57.336 ;
     RECT  6.257 85.92 6.469 86.616 ;
     RECT  6.467 87.936 6.469 88.248 ;
     RECT  5.795 91.632 6.469 91.848 ;
     RECT  5.861 93.072 6.469 94.392 ;
     RECT  6.109 95.376 6.469 96.168 ;
     RECT  5.821 97.248 6.469 99.192 ;
     RECT  6.433 74.688 6.505 74.712 ;
     RECT  6.505 74.112 6.517 74.712 ;
     RECT  6.433 84.912 6.517 84.936 ;
     RECT  6.373 100.32 6.517 104.328 ;
     RECT  6.469 91.632 6.545 94.392 ;
     RECT  6.517 74.112 6.589 74.136 ;
     RECT  6.131 75.84 6.625 76.392 ;
     RECT  6.469 57.312 6.661 57.864 ;
     RECT  6.217 72.432 6.661 72.84 ;
     RECT  6.661 71.808 6.685 72.84 ;
     RECT  6.217 77.52 6.716 78.696 ;
     RECT  6.361 79.728 6.716 80.376 ;
     RECT  6.685 71.808 6.748 73.608 ;
     RECT  6.469 95.376 6.757 99.192 ;
     RECT  6.517 100.224 6.757 104.328 ;
     RECT  5.957 82.032 6.793 82.44 ;
     RECT  6.661 70.704 6.803 70.728 ;
     RECT  6.716 77.52 6.803 80.376 ;
     RECT  6.625 76.368 6.829 76.392 ;
     RECT  6.803 77.52 6.829 78.648 ;
     RECT  6.541 90.24 6.853 90.264 ;
     RECT  6.545 91.632 6.853 92.424 ;
     RECT  5.609 112.272 6.853 112.344 ;
     RECT  5.677 113.376 6.853 114.312 ;
     RECT  6.661 57.168 6.901 57.864 ;
     RECT  6.793 81.552 6.901 82.44 ;
     RECT  6.325 83.616 6.901 83.64 ;
     RECT  6.901 81.552 6.973 83.64 ;
     RECT  6.853 90.24 7.045 92.424 ;
     RECT  6.803 79.728 7.081 80.376 ;
     RECT  6.973 81.456 7.081 83.64 ;
     RECT  6.545 93.792 7.196 94.392 ;
     RECT  6.757 95.376 7.196 104.328 ;
     RECT  6.565 55.68 7.429 55.704 ;
     RECT  6.469 85.92 7.549 88.248 ;
     RECT  7.429 55.68 7.621 55.992 ;
     RECT  7.045 89.76 7.621 92.424 ;
     RECT  6.829 76.368 7.765 78.648 ;
     RECT  7.081 79.728 7.765 83.64 ;
     RECT  7.621 54.864 7.808 55.992 ;
     RECT  6.901 57.168 7.808 57.912 ;
     RECT  6.748 72.432 7.808 73.608 ;
     RECT  7.405 75.264 7.808 75.288 ;
     RECT  7.765 76.368 7.808 83.64 ;
     RECT  7.549 85.488 7.808 88.248 ;
     RECT  7.621 89.472 7.808 92.424 ;
     RECT  7.196 93.792 7.808 104.328 ;
     RECT  6.325 105.36 7.808 111.048 ;
     RECT  6.853 112.272 7.808 114.6 ;
     RECT  5.749 115.632 7.808 116.472 ;
     RECT  6.437 117.936 7.808 118.824 ;
     RECT  6.373 120.24 7.808 124.824 ;
     RECT  7.808 2.148 7.912 192.252 ;
     RECT  7.912 2.418 8.104 191.982 ;
     RECT  8.104 72.432 8.201 72.84 ;
     RECT  8.104 75.264 8.243 75.432 ;
     RECT  8.104 93.792 8.309 104.328 ;
     RECT  8.104 105.36 8.381 111.048 ;
     RECT  8.104 115.728 8.489 116.472 ;
     RECT  8.104 87.168 8.723 90.264 ;
     RECT  8.243 75.264 8.785 75.288 ;
     RECT  8.104 76.896 8.857 77.592 ;
     RECT  8.104 83.184 9.037 83.64 ;
     RECT  8.104 57.168 9.157 57.912 ;
     RECT  8.201 72.48 9.241 72.84 ;
     RECT  9.241 72.48 9.325 72.984 ;
     RECT  8.104 54.864 9.397 55.992 ;
     RECT  9.385 74.688 9.469 74.712 ;
     RECT  8.857 77.568 9.673 77.592 ;
     RECT  8.104 78.912 9.673 78.936 ;
     RECT  9.673 77.568 9.757 78.936 ;
     RECT  9.037 83.616 9.817 83.64 ;
     RECT  9.757 78.912 9.925 78.936 ;
     RECT  8.104 79.968 9.925 79.992 ;
     RECT  9.133 76.368 9.973 76.392 ;
     RECT  9.925 78.912 10.009 79.992 ;
     RECT  9.997 81.456 10.081 81.48 ;
     RECT  8.104 92.16 10.213 92.712 ;
     RECT  8.309 93.792 10.213 95.4 ;
     RECT  9.817 83.616 10.513 84.36 ;
     RECT  8.104 85.92 11.185 85.944 ;
     RECT  9.397 54.576 13.208 55.992 ;
     RECT  9.157 57.168 13.208 58.008 ;
     RECT  9.325 72.48 13.208 72.84 ;
     RECT  9.757 77.568 13.208 77.592 ;
     RECT  10.009 78.912 13.208 78.936 ;
     RECT  10.009 79.968 13.208 79.992 ;
     RECT  10.513 83.616 13.208 83.64 ;
     RECT  11.185 85.92 13.208 86.232 ;
     RECT  8.723 87.264 13.208 90.264 ;
     RECT  10.213 92.16 13.208 95.4 ;
     RECT  8.309 96.768 13.208 97.8 ;
     RECT  8.309 99.024 13.208 104.328 ;
     RECT  8.381 105.36 13.208 108.12 ;
     RECT  8.381 109.392 13.208 111.048 ;
     RECT  8.104 113.712 13.208 114.312 ;
     RECT  8.489 116.448 13.208 116.472 ;
     RECT  8.104 122.352 13.208 124.824 ;
     RECT  13.208 2.148 13.312 192.252 ;
     RECT  13.312 2.418 13.504 191.982 ;
     RECT  13.504 54.576 18.608 55.992 ;
     RECT  13.504 57.168 18.608 58.008 ;
     RECT  13.504 72.48 18.608 72.84 ;
     RECT  13.504 77.568 18.608 77.592 ;
     RECT  13.504 78.912 18.608 78.936 ;
     RECT  13.504 79.968 18.608 79.992 ;
     RECT  13.504 83.616 18.608 83.64 ;
     RECT  13.504 85.92 18.608 86.232 ;
     RECT  13.504 87.264 18.608 90.264 ;
     RECT  13.504 92.16 18.608 95.4 ;
     RECT  13.504 96.768 18.608 97.8 ;
     RECT  13.504 99.024 18.608 104.328 ;
     RECT  13.504 105.36 18.608 108.12 ;
     RECT  13.504 109.392 18.608 111.048 ;
     RECT  13.504 113.712 18.608 114.312 ;
     RECT  13.504 116.448 18.608 116.472 ;
     RECT  13.504 122.352 18.608 124.824 ;
     RECT  18.608 2.148 18.712 192.252 ;
     RECT  18.712 2.418 18.904 191.982 ;
     RECT  18.904 83.616 21.365 83.64 ;
     RECT  21.365 83.616 21.449 83.784 ;
     RECT  18.904 122.352 21.485 124.824 ;
     RECT  21.445 84.912 21.529 84.936 ;
     RECT  21.485 122.352 22.349 122.376 ;
     RECT  21.485 123.456 22.489 124.824 ;
     RECT  22.489 122.496 22.573 124.824 ;
     RECT  18.904 96.768 22.605 97.8 ;
     RECT  18.904 113.712 22.645 114.312 ;
     RECT  22.605 96.768 22.691 97.752 ;
     RECT  18.904 110.88 22.691 110.904 ;
     RECT  18.904 54.576 24.008 55.992 ;
     RECT  18.904 57.168 24.008 58.008 ;
     RECT  18.904 72.48 24.008 72.84 ;
     RECT  18.904 77.568 24.008 77.592 ;
     RECT  18.904 78.912 24.008 78.936 ;
     RECT  18.904 79.968 24.008 79.992 ;
     RECT  20.833 82.128 24.008 82.152 ;
     RECT  21.449 83.616 24.008 83.64 ;
     RECT  18.904 85.92 24.008 86.232 ;
     RECT  18.904 87.264 24.008 90.264 ;
     RECT  18.904 92.16 24.008 95.448 ;
     RECT  22.691 96.768 24.008 97.608 ;
     RECT  18.904 99.024 24.008 104.328 ;
     RECT  18.904 105.36 24.008 108.12 ;
     RECT  18.904 109.392 24.008 109.416 ;
     RECT  22.645 112.896 24.008 114.312 ;
     RECT  18.904 116.448 24.008 116.472 ;
     RECT  22.573 123.456 24.008 124.824 ;
     RECT  24.008 2.148 24.112 192.252 ;
     RECT  24.112 2.418 24.304 191.982 ;
     RECT  24.304 54.576 29.408 55.992 ;
     RECT  24.304 57.168 29.408 58.008 ;
     RECT  24.304 72.48 29.408 72.84 ;
     RECT  24.304 75.648 29.408 75.672 ;
     RECT  24.304 77.568 29.408 77.592 ;
     RECT  24.304 78.912 29.408 78.936 ;
     RECT  24.304 79.968 29.408 79.992 ;
     RECT  24.304 82.128 29.408 82.152 ;
     RECT  24.304 83.616 29.408 83.64 ;
     RECT  24.304 85.92 29.408 86.232 ;
     RECT  24.304 87.264 29.408 90.264 ;
     RECT  24.304 92.16 29.408 95.448 ;
     RECT  24.304 96.768 29.408 97.608 ;
     RECT  24.304 99.024 29.408 104.328 ;
     RECT  24.304 105.36 29.408 108.12 ;
     RECT  24.304 109.392 29.408 109.416 ;
     RECT  24.304 112.896 29.408 114.312 ;
     RECT  24.304 116.448 29.408 116.472 ;
     RECT  24.304 123.456 29.408 124.824 ;
     RECT  29.408 2.148 29.512 192.252 ;
     RECT  29.512 2.418 29.704 191.982 ;
     RECT  29.704 123.456 30.737 124.824 ;
     RECT  30.737 123.504 31.813 124.824 ;
     RECT  29.704 54.576 34.808 55.992 ;
     RECT  29.704 57.168 34.808 58.008 ;
     RECT  29.704 72.48 34.808 72.84 ;
     RECT  29.704 75.648 34.808 75.672 ;
     RECT  29.704 77.568 34.808 77.592 ;
     RECT  29.704 78.912 34.808 78.936 ;
     RECT  29.704 79.968 34.808 79.992 ;
     RECT  29.704 82.128 34.808 82.152 ;
     RECT  29.704 83.616 34.808 83.64 ;
     RECT  29.704 85.92 34.808 86.232 ;
     RECT  29.704 87.264 34.808 90.264 ;
     RECT  29.704 92.16 34.808 95.448 ;
     RECT  29.704 96.768 34.808 97.608 ;
     RECT  29.704 99.024 34.808 104.328 ;
     RECT  29.704 105.36 34.808 108.12 ;
     RECT  29.704 109.392 34.808 109.416 ;
     RECT  29.704 112.896 34.808 114.312 ;
     RECT  29.704 116.448 34.808 116.472 ;
     RECT  31.813 123.456 34.808 124.824 ;
     RECT  34.808 2.148 34.912 192.252 ;
     RECT  34.912 2.418 35.104 191.982 ;
     RECT  35.104 112.896 38.801 114.312 ;
     RECT  35.104 54.576 40.208 55.992 ;
     RECT  35.104 57.168 40.208 58.008 ;
     RECT  35.104 72.48 40.208 72.84 ;
     RECT  35.104 75.648 40.208 75.672 ;
     RECT  35.104 77.568 40.208 77.592 ;
     RECT  35.104 78.912 40.208 78.936 ;
     RECT  35.104 79.968 40.208 79.992 ;
     RECT  35.104 82.128 40.208 82.152 ;
     RECT  35.104 83.616 40.208 83.64 ;
     RECT  35.104 85.92 40.208 86.232 ;
     RECT  35.104 87.264 40.208 90.264 ;
     RECT  35.104 92.16 40.208 95.448 ;
     RECT  35.104 96.768 40.208 97.608 ;
     RECT  35.104 99.024 40.208 104.328 ;
     RECT  35.104 105.36 40.208 108.12 ;
     RECT  35.104 109.392 40.208 109.416 ;
     RECT  38.801 113.04 40.208 114.312 ;
     RECT  35.104 116.448 40.208 116.472 ;
     RECT  35.104 123.456 40.208 124.824 ;
     RECT  40.208 2.148 40.312 192.252 ;
     RECT  40.312 2.418 40.504 191.982 ;
     RECT  40.504 72.48 40.739 72.84 ;
     RECT  40.739 72.48 40.835 72.504 ;
     RECT  40.504 113.04 42.397 114.312 ;
     RECT  40.504 105.36 42.757 108.12 ;
     RECT  40.504 54.576 44.965 55.992 ;
     RECT  40.504 57.168 44.965 58.008 ;
     RECT  44.965 54.576 45.608 58.008 ;
     RECT  40.504 75.648 45.608 75.672 ;
     RECT  40.504 77.568 45.608 77.592 ;
     RECT  40.504 78.912 45.608 78.936 ;
     RECT  40.504 79.968 45.608 79.992 ;
     RECT  40.504 82.128 45.608 82.152 ;
     RECT  40.504 83.616 45.608 83.64 ;
     RECT  40.504 85.92 45.608 86.232 ;
     RECT  40.504 87.264 45.608 90.264 ;
     RECT  40.504 92.16 45.608 95.448 ;
     RECT  40.504 96.768 45.608 97.608 ;
     RECT  40.504 99.024 45.608 104.328 ;
     RECT  42.757 105.36 45.608 108.168 ;
     RECT  40.504 109.392 45.608 109.416 ;
     RECT  42.397 112.944 45.608 114.312 ;
     RECT  40.504 116.448 45.608 116.472 ;
     RECT  40.504 123.456 45.608 124.824 ;
     RECT  45.608 2.148 45.712 192.252 ;
     RECT  45.712 2.418 45.904 191.982 ;
     RECT  45.904 105.36 46.505 108.168 ;
     RECT  45.904 112.944 46.829 114.312 ;
     RECT  45.904 70.224 47.077 70.44 ;
     RECT  47.077 69.264 47.113 70.44 ;
     RECT  47.113 68.928 47.221 70.44 ;
     RECT  47.221 68.88 47.473 70.44 ;
     RECT  46.505 105.888 47.581 108.12 ;
     RECT  48.121 67.584 48.157 67.608 ;
     RECT  48.157 67.344 48.193 67.608 ;
     RECT  48.193 67.152 48.229 67.608 ;
     RECT  48.229 67.152 48.265 67.656 ;
     RECT  47.473 68.688 48.265 70.44 ;
     RECT  47.113 117.648 48.409 117.672 ;
     RECT  48.625 66.048 48.661 66.072 ;
     RECT  48.265 67.152 48.661 70.44 ;
     RECT  48.661 66.048 48.697 70.44 ;
     RECT  45.904 54.576 48.989 58.008 ;
     RECT  49.201 64.608 49.237 64.632 ;
     RECT  49.237 64.368 49.273 64.632 ;
     RECT  47.581 105.36 49.273 108.12 ;
     RECT  45.904 109.392 49.273 109.416 ;
     RECT  49.237 141.36 49.273 141.384 ;
     RECT  49.273 63.888 49.309 64.632 ;
     RECT  48.697 65.76 49.309 70.44 ;
     RECT  49.273 105.36 49.345 109.416 ;
     RECT  49.309 139.968 49.345 139.992 ;
     RECT  49.345 139.776 49.381 139.992 ;
     RECT  49.273 141.12 49.381 141.384 ;
     RECT  49.309 145.296 49.393 145.32 ;
     RECT  49.381 139.776 49.453 141.384 ;
     RECT  49.453 139.68 49.489 141.384 ;
     RECT  49.489 139.392 49.525 141.384 ;
     RECT  49.525 139.2 49.561 141.384 ;
     RECT  49.309 63.888 49.813 70.44 ;
     RECT  49.561 139.104 49.849 141.384 ;
     RECT  49.849 139.104 49.885 141.432 ;
     RECT  47.509 120.528 49.957 120.552 ;
     RECT  49.885 139.104 49.957 141.576 ;
     RECT  49.957 139.104 50.353 141.624 ;
     RECT  50.353 138.432 50.389 141.624 ;
     RECT  50.389 62.544 50.425 62.568 ;
     RECT  49.813 63.552 50.425 70.44 ;
     RECT  50.425 62.544 50.461 70.44 ;
     RECT  50.389 138.144 50.533 141.624 ;
     RECT  46.829 113.04 50.605 114.312 ;
     RECT  45.904 85.92 50.629 86.232 ;
     RECT  45.904 87.264 50.629 90.264 ;
     RECT  45.904 99.024 50.629 104.328 ;
     RECT  49.345 105.36 50.629 110.28 ;
     RECT  50.533 137.28 50.677 141.624 ;
     RECT  45.904 75.648 50.713 75.672 ;
     RECT  45.904 79.968 50.713 79.992 ;
     RECT  50.629 99.024 50.713 110.28 ;
     RECT  50.713 98.928 50.773 110.28 ;
     RECT  48.409 117.648 50.893 117.816 ;
     RECT  50.773 98.64 50.929 110.28 ;
     RECT  50.677 137.04 50.965 141.624 ;
     RECT  48.989 54.576 51.008 57.96 ;
     RECT  50.461 62.496 51.008 70.44 ;
     RECT  50.713 75.648 51.008 75.768 ;
     RECT  45.904 77.568 51.008 77.592 ;
     RECT  45.904 78.912 51.008 78.936 ;
     RECT  50.713 79.968 51.008 80.088 ;
     RECT  45.904 82.128 51.008 82.152 ;
     RECT  45.904 83.616 51.008 83.64 ;
     RECT  50.629 85.92 51.008 90.264 ;
     RECT  45.904 92.16 51.008 95.448 ;
     RECT  45.904 96.768 51.008 97.608 ;
     RECT  50.929 98.64 51.008 110.616 ;
     RECT  50.605 112.896 51.008 114.312 ;
     RECT  45.904 116.448 51.008 116.472 ;
     RECT  50.893 117.552 51.008 117.816 ;
     RECT  49.957 119.904 51.008 120.552 ;
     RECT  45.904 123.456 51.008 124.824 ;
     RECT  50.965 137.04 51.008 141.864 ;
     RECT  49.333 170.736 51.008 170.76 ;
     RECT  51.008 2.148 51.112 192.252 ;
     RECT  51.112 2.418 51.304 191.982 ;
     RECT  51.304 134.784 51.401 141.864 ;
     RECT  51.304 77.568 52.163 77.592 ;
     RECT  51.401 134.784 52.297 141.72 ;
     RECT  51.304 92.16 52.441 95.784 ;
     RECT  51.304 96.768 52.441 97.08 ;
     RECT  51.304 75.744 52.513 75.768 ;
     RECT  51.304 85.92 52.513 86.232 ;
     RECT  52.441 92.16 52.549 97.224 ;
     RECT  51.304 130.752 52.549 131.352 ;
     RECT  51.304 59.472 52.585 70.44 ;
     RECT  52.549 130.656 52.585 131.352 ;
     RECT  52.585 130.464 52.621 131.352 ;
     RECT  52.513 75.744 52.739 76.68 ;
     RECT  51.304 78.912 52.765 78.936 ;
     RECT  51.304 80.064 52.765 80.088 ;
     RECT  52.549 92.016 52.765 97.224 ;
     RECT  52.765 78.912 52.787 80.088 ;
     RECT  52.297 134.688 52.801 141.72 ;
     RECT  51.304 74.496 52.837 74.52 ;
     RECT  52.837 132.768 52.873 132.792 ;
     RECT  52.801 134.016 52.873 141.72 ;
     RECT  51.304 116.448 52.933 116.472 ;
     RECT  51.304 117.552 52.933 117.816 ;
     RECT  52.765 92.016 52.945 97.896 ;
     RECT  51.304 98.928 52.945 109.272 ;
     RECT  51.304 110.256 52.981 110.616 ;
     RECT  51.304 82.128 53.017 82.152 ;
     RECT  51.304 83.616 53.017 83.64 ;
     RECT  52.837 73.584 53.057 74.52 ;
     RECT  53.017 82.128 53.089 83.64 ;
     RECT  52.513 85.872 53.089 86.232 ;
     RECT  51.304 87.264 53.089 90.264 ;
     RECT  52.621 130.464 53.125 131.448 ;
     RECT  53.045 80.88 53.129 80.904 ;
     RECT  53.089 82.128 53.173 83.784 ;
     RECT  53.125 130.368 53.557 131.448 ;
     RECT  52.873 132.768 53.557 141.72 ;
     RECT  53.089 85.872 53.603 90.264 ;
     RECT  51.304 112.944 53.633 114.312 ;
     RECT  52.933 116.448 53.705 117.816 ;
     RECT  53.593 168 53.773 168.984 ;
     RECT  52.787 78.912 53.843 79.752 ;
     RECT  52.585 59.184 53.845 70.44 ;
     RECT  53.603 85.872 53.891 85.944 ;
     RECT  52.945 92.016 53.957 109.272 ;
     RECT  53.957 92.016 53.987 108.456 ;
     RECT  53.633 112.944 53.993 114.264 ;
     RECT  53.705 117.552 54.029 117.816 ;
     RECT  53.987 93.312 54.035 108.456 ;
     RECT  52.981 110.256 54.083 110.76 ;
     RECT  53.089 166.656 54.097 166.68 ;
     RECT  53.773 167.904 54.097 168.984 ;
     RECT  51.304 54.672 54.173 57.96 ;
     RECT  54.029 117.552 54.209 117.576 ;
     RECT  51.304 120.528 54.209 120.552 ;
     RECT  54.035 94.368 54.317 108.456 ;
     RECT  54.083 110.496 54.385 110.76 ;
     RECT  53.993 113.952 54.419 114.264 ;
     RECT  54.385 110.496 54.425 111.048 ;
     RECT  52.693 129.36 54.901 129.384 ;
     RECT  54.419 113.952 54.995 113.976 ;
     RECT  53.057 73.584 54.997 73.608 ;
     RECT  54.997 154.08 55.045 157.08 ;
     RECT  54.949 160.224 55.045 160.248 ;
     RECT  53.891 85.872 55.069 85.896 ;
     RECT  53.987 92.016 55.069 92.04 ;
     RECT  54.035 93.312 55.069 93.336 ;
     RECT  54.425 111.024 55.091 111.048 ;
     RECT  53.653 163.152 55.093 163.176 ;
     RECT  52.739 76.656 55.105 76.68 ;
     RECT  53.843 79.728 55.105 79.752 ;
     RECT  53.173 82.128 55.105 82.824 ;
     RECT  55.105 79.728 55.141 80.904 ;
     RECT  55.105 82.128 55.141 83.592 ;
     RECT  55.069 92.016 55.141 93.336 ;
     RECT  54.317 94.368 55.141 108.072 ;
     RECT  53.557 130.368 55.141 141.72 ;
     RECT  54.421 144.864 55.141 144.888 ;
     RECT  53.845 59.088 55.177 70.44 ;
     RECT  54.997 73.008 55.177 73.608 ;
     RECT  55.105 76.656 55.177 77.736 ;
     RECT  55.141 79.728 55.177 83.592 ;
     RECT  55.069 85.008 55.177 85.896 ;
     RECT  53.603 87.264 55.177 90.264 ;
     RECT  55.141 92.016 55.177 108.072 ;
     RECT  55.141 130.368 55.177 144.888 ;
     RECT  55.093 147.936 55.177 150.936 ;
     RECT  55.177 130.368 55.189 150.936 ;
     RECT  55.045 154.08 55.189 160.248 ;
     RECT  55.093 163.008 55.189 163.224 ;
     RECT  54.097 166.368 55.189 169.56 ;
     RECT  54.173 55.488 55.357 55.704 ;
     RECT  54.173 56.832 55.357 57.96 ;
     RECT  55.357 54.672 55.368 57.96 ;
     RECT  55.177 59.088 55.368 108.072 ;
     RECT  54.901 129.312 55.368 129.384 ;
     RECT  55.189 130.368 55.368 169.56 ;
     RECT  51.304 170.736 55.368 170.76 ;
     RECT  55.368 54.672 56.408 108.072 ;
     RECT  53.993 112.944 56.408 112.968 ;
     RECT  53.705 116.448 56.408 116.472 ;
     RECT  51.304 123.456 56.408 124.824 ;
     RECT  56.408 2.148 56.512 127.452 ;
     RECT  56.408 172.788 56.512 192.252 ;
     RECT  56.512 2.418 56.704 127.182 ;
     RECT  56.512 173.058 56.704 191.982 ;
     RECT  56.704 54.672 58.669 108.072 ;
     RECT  55.368 129.312 58.705 170.76 ;
     RECT  58.669 54.576 61.808 108.072 ;
     RECT  56.704 112.944 61.808 112.968 ;
     RECT  56.704 116.448 61.808 116.472 ;
     RECT  56.704 123.456 61.808 124.824 ;
     RECT  61.808 2.148 61.912 127.452 ;
     RECT  61.808 172.788 61.912 192.252 ;
     RECT  61.912 2.418 62.104 127.182 ;
     RECT  61.912 173.058 62.104 191.982 ;
     RECT  66.697 126.48 66.709 126.504 ;
     RECT  66.709 126.48 67.013 126.792 ;
     RECT  62.104 54.576 67.208 108.072 ;
     RECT  62.104 112.944 67.208 112.968 ;
     RECT  62.104 116.448 67.208 116.472 ;
     RECT  62.104 123.456 67.208 124.824 ;
     RECT  67.013 126 67.208 126.792 ;
     RECT  67.208 2.148 67.312 127.452 ;
     RECT  67.208 172.788 67.312 192.252 ;
     RECT  67.312 2.418 67.504 127.182 ;
     RECT  67.312 173.058 67.504 191.982 ;
     RECT  67.504 54.576 72.608 108.072 ;
     RECT  67.504 112.944 72.608 112.968 ;
     RECT  67.504 116.448 72.608 116.472 ;
     RECT  67.504 123.456 72.608 124.824 ;
     RECT  67.504 126.768 72.608 126.792 ;
     RECT  72.608 2.148 72.712 127.452 ;
     RECT  72.608 172.788 72.712 192.252 ;
     RECT  72.712 2.418 72.904 127.182 ;
     RECT  72.712 173.058 72.904 191.982 ;
     RECT  72.904 54.576 78.008 108.072 ;
     RECT  72.904 112.944 78.008 112.968 ;
     RECT  72.904 116.448 78.008 116.472 ;
     RECT  72.904 123.456 78.008 124.824 ;
     RECT  72.904 126.768 78.008 126.792 ;
     RECT  78.008 2.148 78.112 127.452 ;
     RECT  78.008 172.788 78.112 192.252 ;
     RECT  78.112 2.418 78.304 127.182 ;
     RECT  78.112 173.058 78.304 191.982 ;
     RECT  78.304 54.576 83.408 108.072 ;
     RECT  78.304 112.944 83.408 112.968 ;
     RECT  78.304 116.448 83.408 116.472 ;
     RECT  78.304 123.456 83.408 124.824 ;
     RECT  78.304 126.768 83.408 126.792 ;
     RECT  83.408 2.148 83.512 127.452 ;
     RECT  83.408 172.788 83.512 192.252 ;
     RECT  83.512 2.418 83.704 127.182 ;
     RECT  83.512 173.058 83.704 191.982 ;
     RECT  83.704 54.576 88.808 108.072 ;
     RECT  83.704 112.944 88.808 112.968 ;
     RECT  83.704 116.448 88.808 116.472 ;
     RECT  83.704 123.456 88.808 124.824 ;
     RECT  83.704 126.768 88.808 126.792 ;
     RECT  88.808 2.148 88.912 127.452 ;
     RECT  88.808 172.788 88.912 192.252 ;
     RECT  88.912 2.418 89.104 127.182 ;
     RECT  88.912 173.058 89.104 191.982 ;
     RECT  89.104 112.944 91.037 112.968 ;
     RECT  89.104 54.576 94.208 108.072 ;
     RECT  92.545 112.992 94.208 113.016 ;
     RECT  89.104 116.448 94.208 116.472 ;
     RECT  89.104 123.456 94.208 124.824 ;
     RECT  89.104 126.768 94.208 126.792 ;
     RECT  94.208 2.148 94.312 127.452 ;
     RECT  94.208 172.788 94.312 192.252 ;
     RECT  94.312 2.418 94.504 127.182 ;
     RECT  94.312 173.058 94.504 191.982 ;
     RECT  94.504 112.896 94.637 113.016 ;
     RECT  95.857 192.096 96.131 192.12 ;
     RECT  94.504 126.768 96.793 126.792 ;
     RECT  58.705 128.496 96.793 170.76 ;
     RECT  96.721 193.248 96.995 193.272 ;
     RECT  96.937 190.944 97.021 190.968 ;
     RECT  94.504 123.456 97.517 124.824 ;
     RECT  97.693 192.096 97.859 192.12 ;
     RECT  97.909 190.416 98.293 190.44 ;
     RECT  98.293 190.368 98.629 190.44 ;
     RECT  98.629 190.368 98.633 191.256 ;
     RECT  98.449 193.248 98.723 193.272 ;
     RECT  97.517 123.456 98.953 124.056 ;
     RECT  99.313 192.384 99.587 192.408 ;
     RECT  94.504 54.576 99.608 108.072 ;
     RECT  94.637 112.896 99.608 112.92 ;
     RECT  94.504 116.448 99.608 116.472 ;
     RECT  98.953 123.456 99.608 124.248 ;
     RECT  96.793 126.768 99.608 170.76 ;
     RECT  98.965 189.264 99.608 189.288 ;
     RECT  98.633 190.944 99.608 191.256 ;
     RECT  99.608 2.148 99.712 170.76 ;
     RECT  99.608 172.788 99.712 192.252 ;
     RECT  99.712 2.418 99.904 170.76 ;
     RECT  99.712 173.058 99.904 191.982 ;
     RECT  99.904 126.768 100.355 170.76 ;
     RECT  99.904 190.416 100.355 191.544 ;
     RECT  100.897 125.376 100.981 125.4 ;
     RECT  100.355 190.944 101.041 191.544 ;
     RECT  101.041 190.944 101.117 192.12 ;
     RECT  101.117 191.232 101.315 192.12 ;
     RECT  101.315 191.232 101.369 191.544 ;
     RECT  100.355 126.768 101.545 126.792 ;
     RECT  100.355 128.496 101.653 170.76 ;
     RECT  101.545 126.576 101.905 126.792 ;
     RECT  99.904 123.456 102.229 124.056 ;
     RECT  102.133 174.96 102.277 174.984 ;
     RECT  101.905 126.576 102.323 127.032 ;
     RECT  102.277 174.528 102.323 174.984 ;
     RECT  101.369 191.232 102.565 191.256 ;
     RECT  102.565 191.232 102.997 191.928 ;
     RECT  102.229 122.928 103.057 124.056 ;
     RECT  103.057 122.928 103.205 124.104 ;
     RECT  102.997 191.232 103.861 192.072 ;
     RECT  102.323 127.008 104.063 127.032 ;
     RECT  103.205 122.928 104.317 124.056 ;
     RECT  104.063 127.008 104.821 127.272 ;
     RECT  101.653 128.496 104.821 171.336 ;
     RECT  99.904 54.576 105.008 108.072 ;
     RECT  99.904 112.896 105.008 112.92 ;
     RECT  104.101 115.104 105.008 115.128 ;
     RECT  99.904 116.448 105.008 116.472 ;
     RECT  104.317 122.928 105.008 124.104 ;
     RECT  104.821 127.008 105.008 171.336 ;
     RECT  102.323 174.528 105.008 174.552 ;
     RECT  104.425 177.216 105.008 177.24 ;
     RECT  103.861 191.232 105.008 192.648 ;
     RECT  105.008 2.148 105.112 171.336 ;
     RECT  105.008 172.788 105.112 192.648 ;
     RECT  105.112 2.418 105.304 171.336 ;
     RECT  105.112 173.058 105.304 192.648 ;
     RECT  105.304 191.232 106.013 192.648 ;
     RECT  106.013 191.232 107.009 191.256 ;
     RECT  106.013 192.624 107.201 192.648 ;
     RECT  107.009 190.416 107.276 191.256 ;
     RECT  107.276 190.416 107.363 192.12 ;
     RECT  107.363 190.416 107.821 191.544 ;
     RECT  105.304 127.008 107.843 171.336 ;
     RECT  108.181 192.624 108.281 192.648 ;
     RECT  107.821 191.232 108.563 191.544 ;
     RECT  105.304 122.928 108.853 124.056 ;
     RECT  107.843 127.008 108.949 128.52 ;
     RECT  108.949 125.952 109.429 128.52 ;
     RECT  107.843 129.6 109.429 171.336 ;
     RECT  109.429 125.952 109.469 171.336 ;
     RECT  109.469 128.496 109.475 171.336 ;
     RECT  109.475 129.36 109.523 171.336 ;
     RECT  108.853 122.928 109.717 124.824 ;
     RECT  109.523 129.36 110.009 171.288 ;
     RECT  105.304 54.576 110.408 108.072 ;
     RECT  105.304 115.104 110.408 115.128 ;
     RECT  109.813 119.952 110.408 119.976 ;
     RECT  109.717 122.928 110.408 124.872 ;
     RECT  109.469 125.952 110.408 127.452 ;
     RECT  105.304 174.528 110.408 174.552 ;
     RECT  109.429 185.808 110.408 185.832 ;
     RECT  108.563 191.232 110.408 191.256 ;
     RECT  110.408 2.148 110.512 127.452 ;
     RECT  110.408 172.788 110.512 192.252 ;
     RECT  110.512 2.418 110.704 127.182 ;
     RECT  110.512 173.058 110.704 191.982 ;
     RECT  110.009 129.6 110.833 171.288 ;
     RECT  110.704 174.528 111.773 174.552 ;
     RECT  112.237 174.432 112.321 174.456 ;
     RECT  110.833 129.6 112.837 171.576 ;
     RECT  112.837 129.504 112.883 171.576 ;
     RECT  112.883 129.504 112.961 171.288 ;
     RECT  110.704 122.928 113.173 124.824 ;
     RECT  110.704 125.856 113.173 125.88 ;
     RECT  110.704 54.576 115.808 108.072 ;
     RECT  110.704 115.104 115.808 115.128 ;
     RECT  110.704 119.952 115.808 119.976 ;
     RECT  113.173 122.928 115.808 125.88 ;
     RECT  110.704 127.008 115.808 127.032 ;
     RECT  112.261 172.896 115.808 172.92 ;
     RECT  115.808 2.148 115.912 127.452 ;
     RECT  115.808 172.788 115.912 192.252 ;
     RECT  115.912 2.418 116.104 127.182 ;
     RECT  115.912 172.896 116.104 191.982 ;
     RECT  116.104 122.928 118.001 124.824 ;
     RECT  116.104 115.104 119.081 115.128 ;
     RECT  116.104 54.576 121.208 108.072 ;
     RECT  120.589 115.344 121.208 115.368 ;
     RECT  116.104 119.952 121.208 119.976 ;
     RECT  118.001 122.976 121.208 124.824 ;
     RECT  116.104 125.856 121.208 125.88 ;
     RECT  116.104 127.008 121.208 127.032 ;
     RECT  116.104 172.896 121.208 172.92 ;
     RECT  121.208 2.148 121.312 127.452 ;
     RECT  121.208 172.788 121.312 192.252 ;
     RECT  121.312 2.418 121.504 127.32 ;
     RECT  121.312 172.788 121.504 191.982 ;
     RECT  121.504 172.788 121.957 173.4 ;
     RECT  121.957 172.704 122.243 173.4 ;
     RECT  121.504 54.576 126.608 108.072 ;
     RECT  121.504 115.056 126.608 115.368 ;
     RECT  121.504 119.952 126.608 119.976 ;
     RECT  121.504 122.976 126.608 124.824 ;
     RECT  121.504 125.856 126.608 125.88 ;
     RECT  121.504 127.008 126.608 127.32 ;
     RECT  122.243 173.376 126.608 173.4 ;
     RECT  126.608 2.148 126.712 127.452 ;
     RECT  126.608 172.788 126.712 192.252 ;
     RECT  126.712 2.418 126.904 127.32 ;
     RECT  126.712 173.058 126.904 191.982 ;
     RECT  126.904 127.008 130.997 127.32 ;
     RECT  126.904 115.056 131.317 115.368 ;
     RECT  126.904 54.576 132.008 108.072 ;
     RECT  131.317 114.864 132.008 115.368 ;
     RECT  126.904 119.952 132.008 119.976 ;
     RECT  126.904 122.976 132.008 124.824 ;
     RECT  126.904 125.856 132.008 125.88 ;
     RECT  130.997 127.008 132.008 127.128 ;
     RECT  126.904 173.376 132.008 173.4 ;
     RECT  132.008 2.148 132.112 127.452 ;
     RECT  132.008 172.788 132.112 192.252 ;
     RECT  132.112 2.418 132.304 127.182 ;
     RECT  132.112 173.058 132.304 191.982 ;
     RECT  132.304 54.576 137.408 108.072 ;
     RECT  132.304 114.864 137.408 115.368 ;
     RECT  132.304 119.952 137.408 119.976 ;
     RECT  132.304 122.976 137.408 124.824 ;
     RECT  132.304 125.856 137.408 125.88 ;
     RECT  132.304 127.008 137.408 127.032 ;
     RECT  132.304 173.376 137.408 173.4 ;
     RECT  137.408 2.148 137.512 127.452 ;
     RECT  137.408 172.788 137.512 192.252 ;
     RECT  137.512 2.418 137.704 127.182 ;
     RECT  137.512 173.058 137.704 191.982 ;
     RECT  112.961 129.6 139.379 171.288 ;
     RECT  137.704 125.856 139.56 126.648 ;
     RECT  137.704 114.864 140.573 115.368 ;
     RECT  139.56 125.856 142.597 126.792 ;
     RECT  137.704 54.576 142.808 108.072 ;
     RECT  139.333 113.184 142.808 113.208 ;
     RECT  140.573 115.056 142.808 115.368 ;
     RECT  137.704 119.952 142.808 119.976 ;
     RECT  137.704 122.976 142.808 124.824 ;
     RECT  142.597 125.856 142.808 126.984 ;
     RECT  137.704 173.376 142.808 173.4 ;
     RECT  142.808 2.148 142.912 127.452 ;
     RECT  142.808 172.788 142.912 192.252 ;
     RECT  142.912 2.418 143.104 127.182 ;
     RECT  142.912 173.058 143.104 191.982 ;
     RECT  143.104 125.856 144.821 126.984 ;
     RECT  144.821 125.952 146.329 126.984 ;
     RECT  139.885 128.496 146.329 128.52 ;
     RECT  139.379 129.6 146.329 170.76 ;
     RECT  146.329 125.952 146.473 170.76 ;
     RECT  143.104 173.376 146.473 173.4 ;
     RECT  143.104 54.576 146.513 108.072 ;
     RECT  146.473 173.376 146.513 173.496 ;
     RECT  146.513 54.672 148.208 107.928 ;
     RECT  148.021 111.84 148.208 111.864 ;
     RECT  143.104 113.184 148.208 113.208 ;
     RECT  143.104 115.056 148.208 115.368 ;
     RECT  147.541 118.32 148.208 118.344 ;
     RECT  143.104 119.952 148.208 119.976 ;
     RECT  143.104 122.976 148.208 124.824 ;
     RECT  146.473 125.952 148.208 170.856 ;
     RECT  146.513 173.472 148.208 173.496 ;
     RECT  148.208 2.148 148.312 170.856 ;
     RECT  148.208 172.788 148.312 192.252 ;
     RECT  148.312 2.418 148.504 170.856 ;
     RECT  148.312 173.058 148.504 191.982 ;
     RECT  148.504 122.976 148.889 124.824 ;
     RECT  148.889 122.976 149.357 124.008 ;
     RECT  149.357 123.984 149.537 124.008 ;
     RECT  148.504 125.952 149.813 170.856 ;
     RECT  148.504 113.184 149.929 113.208 ;
     RECT  149.813 125.424 149.989 170.856 ;
     RECT  148.504 54.672 150.037 107.928 ;
     RECT  150.037 54.672 150.048 107.976 ;
     RECT  149.989 125.136 150.048 170.856 ;
     RECT  148.504 111.84 150.073 111.864 ;
     RECT  150.073 111.744 150.133 111.864 ;
     RECT  150.048 59.088 150.227 107.976 ;
     RECT  150.048 170.736 150.227 170.856 ;
     RECT  149.929 113.184 150.253 114.024 ;
     RECT  150.048 54.672 150.275 58.104 ;
     RECT  150.001 121.68 150.277 121.704 ;
     RECT  148.504 119.952 150.289 119.976 ;
     RECT  150.275 56.832 150.293 58.104 ;
     RECT  150.227 170.784 150.323 170.856 ;
     RECT  150.133 110.832 150.325 111.864 ;
     RECT  150.253 112.848 150.325 114.024 ;
     RECT  148.504 115.056 150.325 115.368 ;
     RECT  150.181 109.824 150.371 109.848 ;
     RECT  150.325 110.832 150.371 114.024 ;
     RECT  150.277 121.392 150.373 121.704 ;
     RECT  150.325 115.008 150.397 115.368 ;
     RECT  150.323 170.784 150.419 170.808 ;
     RECT  150.373 121.2 150.431 121.704 ;
     RECT  150.371 111.84 150.467 114.024 ;
     RECT  149.357 122.976 150.469 123 ;
     RECT  150.397 115.008 150.48 116.856 ;
     RECT  150.293 56.832 150.515 57.96 ;
     RECT  148.504 173.472 150.515 173.496 ;
     RECT  150.467 112.224 150.517 114.024 ;
     RECT  150.48 115.008 150.517 115.128 ;
     RECT  150.371 110.832 150.541 110.856 ;
     RECT  150.469 122.976 150.553 123.816 ;
     RECT  150.517 112.224 150.653 115.128 ;
     RECT  150.275 54.672 150.755 55.704 ;
     RECT  150.755 54.672 150.851 55.512 ;
     RECT  150.227 59.28 150.865 107.976 ;
     RECT  150.48 116.112 150.865 116.856 ;
     RECT  148.504 118.32 150.865 118.344 ;
     RECT  150.653 112.848 150.869 115.128 ;
     RECT  150.851 55.152 150.899 55.512 ;
     RECT  150.515 56.832 150.947 57.912 ;
     RECT  150.048 125.136 150.973 169.656 ;
     RECT  150.947 57.888 151.043 57.912 ;
     RECT  150.869 113.184 151.049 115.128 ;
     RECT  150.865 116.112 151.121 118.344 ;
     RECT  151.121 117.792 151.297 118.344 ;
     RECT  150.289 119.376 151.297 119.976 ;
     RECT  150.899 55.488 151.331 55.512 ;
     RECT  150.541 110.016 151.337 110.856 ;
     RECT  150.431 120.96 151.369 121.704 ;
     RECT  150.553 122.976 151.369 123.672 ;
     RECT  150.947 56.832 151.379 56.904 ;
     RECT  151.369 120.96 151.409 123.672 ;
     RECT  151.297 117.792 151.429 119.976 ;
     RECT  151.409 120.96 151.429 123 ;
     RECT  151.379 56.88 151.475 56.904 ;
     RECT  151.049 113.184 151.481 114.024 ;
     RECT  151.121 116.112 151.661 116.136 ;
     RECT  150.865 59.28 151.765 108.456 ;
     RECT  151.049 115.056 151.811 115.128 ;
     RECT  150.973 124.8 152.093 169.656 ;
     RECT  151.429 117.792 152.237 123 ;
     RECT  151.811 115.104 152.269 115.128 ;
     RECT  151.481 113.184 152.381 113.208 ;
     RECT  152.237 118.32 152.417 123 ;
     RECT  151.765 59.28 152.489 108.552 ;
     RECT  151.337 110.544 152.557 110.856 ;
     RECT  152.557 110.496 152.629 110.856 ;
     RECT  152.417 121.536 152.953 123 ;
     RECT  152.489 80.592 152.989 108.552 ;
     RECT  152.269 115.104 152.989 115.512 ;
     RECT  152.989 80.592 153.053 109.176 ;
     RECT  152.629 110.496 153.053 111.048 ;
     RECT  153.053 80.592 153.061 111.048 ;
     RECT  152.953 121.536 153.061 123.72 ;
     RECT  152.093 124.8 153.061 125.16 ;
     RECT  153.061 80.592 153.212 111.672 ;
     RECT  153.212 80.592 153.277 111.768 ;
     RECT  152.665 112.848 153.277 112.872 ;
     RECT  152.989 114.72 153.301 115.512 ;
     RECT  153.277 80.592 153.349 112.872 ;
     RECT  153.301 114 153.349 115.512 ;
     RECT  152.417 118.32 153.445 119.976 ;
     RECT  153.349 80.592 153.493 115.512 ;
     RECT  152.489 59.28 153.608 79.56 ;
     RECT  153.493 80.592 153.608 115.752 ;
     RECT  153.445 116.976 153.608 119.976 ;
     RECT  153.061 121.536 153.608 125.16 ;
     RECT  152.093 126.24 153.608 169.656 ;
     RECT  153.608 2.148 153.712 192.252 ;
     RECT  153.712 2.418 153.904 191.982 ;
     RECT  153.904 125.136 153.965 169.656 ;
     RECT  153.965 125.136 154.001 155.448 ;
     RECT  153.904 59.28 154.019 124.056 ;
     RECT  154.019 59.28 154.073 123.72 ;
     RECT  154.001 125.136 154.073 155.352 ;
     RECT  154.073 59.28 154.109 118.488 ;
     RECT  154.073 125.136 154.163 147.528 ;
     RECT  154.109 59.28 154.289 107.88 ;
     RECT  154.109 109.152 154.289 118.488 ;
     RECT  154.289 109.152 154.433 113.496 ;
     RECT  154.163 125.424 154.469 147.528 ;
     RECT  154.289 59.28 154.505 61.128 ;
     RECT  154.289 62.16 154.643 107.88 ;
     RECT  154.289 114.528 154.643 118.488 ;
     RECT  154.433 109.68 154.685 113.496 ;
     RECT  154.685 109.68 154.721 113.4 ;
     RECT  154.073 119.472 154.793 123.72 ;
     RECT  154.793 119.472 154.931 121.512 ;
     RECT  154.643 62.16 154.973 107.352 ;
     RECT  154.973 62.16 155.045 66.264 ;
     RECT  154.505 61.104 155.081 61.128 ;
     RECT  154.973 67.248 155.117 107.352 ;
     RECT  155.045 63.312 155.153 66.264 ;
     RECT  154.073 148.8 155.153 155.352 ;
     RECT  155.117 68.688 155.225 83.352 ;
     RECT  154.469 125.424 155.261 147.336 ;
     RECT  155.153 152.064 155.267 155.352 ;
     RECT  155.117 84.624 155.363 107.352 ;
     RECT  154.793 122.544 155.363 123.72 ;
     RECT  154.643 116.16 155.365 118.488 ;
     RECT  154.931 119.472 155.365 121.464 ;
     RECT  155.261 125.856 155.405 147.336 ;
     RECT  155.267 152.064 155.411 153.72 ;
     RECT  155.153 148.8 155.437 150.552 ;
     RECT  154.721 109.68 155.441 111.576 ;
     RECT  155.405 125.856 155.477 146.568 ;
     RECT  155.437 148.752 155.477 150.552 ;
     RECT  155.477 125.856 155.585 144.888 ;
     RECT  155.477 145.872 155.585 146.568 ;
     RECT  155.477 148.752 155.621 150.504 ;
     RECT  155.411 152.736 155.651 153.72 ;
     RECT  155.045 62.16 155.657 62.328 ;
     RECT  154.643 114.528 155.657 115.176 ;
     RECT  155.365 108.336 155.689 108.696 ;
     RECT  155.441 109.68 155.689 110.52 ;
     RECT  155.657 115.152 155.689 115.176 ;
     RECT  155.365 116.16 155.689 121.464 ;
     RECT  155.585 125.856 155.693 144.792 ;
     RECT  154.721 112.56 155.699 113.4 ;
     RECT  155.689 115.152 155.699 121.464 ;
     RECT  155.621 148.752 155.795 149.448 ;
     RECT  155.621 150.48 155.795 150.504 ;
     RECT  155.657 62.304 155.801 62.328 ;
     RECT  155.225 68.88 155.873 83.352 ;
     RECT  155.651 153.36 155.873 153.72 ;
     RECT  155.699 115.152 155.939 118.104 ;
     RECT  155.699 119.136 155.941 121.464 ;
     RECT  155.939 115.152 155.987 117.864 ;
     RECT  155.153 63.312 156.017 65.832 ;
     RECT  156.017 63.312 156.053 64.392 ;
     RECT  155.117 67.248 156.089 67.704 ;
     RECT  155.873 71.184 156.121 83.352 ;
     RECT  155.363 84.624 156.121 107.256 ;
     RECT  153.965 156.528 156.131 169.656 ;
     RECT  155.795 148.752 156.157 148.776 ;
     RECT  155.873 68.88 156.161 69.768 ;
     RECT  156.161 68.976 156.179 69.768 ;
     RECT  155.699 112.56 156.193 112.968 ;
     RECT  155.693 125.856 156.197 140.52 ;
     RECT  156.131 161.616 156.227 169.656 ;
     RECT  156.197 125.856 156.233 140.328 ;
     RECT  155.585 145.92 156.341 146.568 ;
     RECT  156.017 65.808 156.481 65.832 ;
     RECT  155.693 141.888 156.485 144.792 ;
     RECT  156.341 145.968 156.485 146.568 ;
     RECT  156.157 148.224 156.485 148.776 ;
     RECT  155.689 108.288 156.517 110.52 ;
     RECT  156.485 141.888 156.521 143.64 ;
     RECT  156.517 108.288 156.625 110.856 ;
     RECT  156.193 112.272 156.625 112.968 ;
     RECT  156.053 64.176 156.665 64.392 ;
     RECT  156.179 69.312 156.701 69.768 ;
     RECT  155.941 119.136 156.701 121.56 ;
     RECT  156.233 125.856 156.773 129.672 ;
     RECT  156.701 120.816 156.809 121.56 ;
     RECT  156.809 120.816 156.845 121.464 ;
     RECT  156.131 156.528 156.851 160.44 ;
     RECT  156.665 64.176 156.881 64.2 ;
     RECT  156.625 108.288 156.899 112.968 ;
     RECT  156.227 161.904 156.899 169.656 ;
     RECT  156.481 65.808 156.917 66.12 ;
     RECT  156.521 141.936 156.953 143.64 ;
     RECT  155.987 116.352 156.985 117.864 ;
     RECT  156.701 119.136 156.995 119.736 ;
     RECT  156.953 142.464 156.995 143.64 ;
     RECT  156.899 108.336 156.997 112.968 ;
     RECT  156.265 114 156.997 114.024 ;
     RECT  156.121 71.184 157.025 107.256 ;
     RECT  155.363 122.976 157.025 123.72 ;
     RECT  156.701 69.312 157.091 69.576 ;
     RECT  156.089 67.68 157.132 67.704 ;
     RECT  156.845 120.816 157.139 120.936 ;
     RECT  157.091 69.312 157.205 69.336 ;
     RECT  157.025 74.448 157.205 107.256 ;
     RECT  156.995 142.464 157.205 143.544 ;
     RECT  157.205 142.464 157.277 142.536 ;
     RECT  156.917 65.808 157.313 65.832 ;
     RECT  157.277 142.512 157.349 142.536 ;
     RECT  157.205 74.64 157.379 107.256 ;
     RECT  156.899 165.36 157.427 169.656 ;
     RECT  157.139 120.816 157.571 120.888 ;
     RECT  157.571 120.864 157.601 120.888 ;
     RECT  156.485 144.768 157.601 144.792 ;
     RECT  157.379 74.64 157.612 93.816 ;
     RECT  156.997 108.336 157.619 114.024 ;
     RECT  156.773 125.856 157.637 129.288 ;
     RECT  156.485 145.968 157.637 146.424 ;
     RECT  156.233 130.8 157.705 140.328 ;
     RECT  157.619 108.336 157.715 111.768 ;
     RECT  157.025 71.184 157.745 73.464 ;
     RECT  157.637 145.968 157.745 145.992 ;
     RECT  156.985 116.304 157.763 117.864 ;
     RECT  157.705 130.8 157.763 140.76 ;
     RECT  157.763 116.448 157.765 117.864 ;
     RECT  156.995 119.136 157.765 119.16 ;
     RECT  157.025 122.976 157.777 123 ;
     RECT  157.763 130.8 157.781 135.192 ;
     RECT  157.765 116.448 157.853 119.16 ;
     RECT  157.853 116.448 157.859 118.632 ;
     RECT  157.745 71.184 157.889 73.032 ;
     RECT  156.899 161.904 157.907 164.376 ;
     RECT  157.379 94.848 158.137 107.256 ;
     RECT  157.715 108.336 158.137 110.856 ;
     RECT  157.612 74.64 158.281 75.624 ;
     RECT  157.637 128.832 158.461 129.288 ;
     RECT  156.851 156.528 158.461 160.344 ;
     RECT  158.281 142.464 158.713 142.488 ;
     RECT  158.137 94.848 158.749 110.856 ;
     RECT  154.505 59.28 159.008 59.784 ;
     RECT  157.889 72.096 159.008 73.032 ;
     RECT  158.281 74.496 159.008 75.624 ;
     RECT  157.612 76.848 159.008 93.816 ;
     RECT  158.749 94.848 159.008 111.336 ;
     RECT  157.619 112.848 159.008 114.024 ;
     RECT  155.987 115.152 159.008 115.176 ;
     RECT  157.859 117.408 159.008 118.632 ;
     RECT  157.777 122.544 159.008 123 ;
     RECT  157.637 125.856 159.008 127.704 ;
     RECT  158.461 128.832 159.008 129.384 ;
     RECT  157.781 130.8 159.008 131.112 ;
     RECT  157.781 132.48 159.008 135.192 ;
     RECT  157.763 136.56 159.008 140.76 ;
     RECT  158.713 142.464 159.008 143.112 ;
     RECT  155.873 153.696 159.008 153.72 ;
     RECT  155.267 155.328 159.008 155.352 ;
     RECT  158.461 156.432 159.008 160.344 ;
     RECT  157.907 162.336 159.008 164.376 ;
     RECT  157.427 165.36 159.008 169.416 ;
     RECT  159.008 2.148 159.112 192.252 ;
     RECT  159.112 2.418 159.304 191.982 ;
     RECT  159.304 133.008 159.443 135.192 ;
     RECT  159.304 136.944 159.491 138.696 ;
     RECT  159.304 84.624 159.509 108.696 ;
     RECT  159.304 110.448 159.509 111.336 ;
     RECT  159.304 117.648 159.509 118.632 ;
     RECT  159.304 80.592 159.539 83.352 ;
     RECT  159.509 99.168 159.539 108.696 ;
     RECT  159.304 140.304 159.539 140.76 ;
     RECT  159.509 110.496 159.587 111.336 ;
     RECT  159.539 140.736 159.587 140.76 ;
     RECT  159.304 122.448 159.617 123 ;
     RECT  159.304 125.856 159.653 127.32 ;
     RECT  159.304 77.088 159.683 79.464 ;
     RECT  159.304 128.928 159.683 129.192 ;
     RECT  159.539 81.888 159.731 83.352 ;
     RECT  159.443 133.008 159.731 135.096 ;
     RECT  159.491 136.944 159.779 138.072 ;
     RECT  159.779 137.232 159.827 138.072 ;
     RECT  159.827 137.232 159.923 137.784 ;
     RECT  159.539 107.232 160.019 108.696 ;
     RECT  159.304 130.8 160.019 131.64 ;
     RECT  159.539 99.168 160.067 105.768 ;
     RECT  159.304 59.28 160.211 59.784 ;
     RECT  160.019 130.8 160.211 131.112 ;
     RECT  159.683 77.904 160.259 79.464 ;
     RECT  159.731 81.888 160.307 82.968 ;
     RECT  159.731 133.008 160.307 134.376 ;
     RECT  159.923 137.232 160.355 137.256 ;
     RECT  160.307 133.008 160.403 133.752 ;
     RECT  159.304 115.152 160.451 115.176 ;
     RECT  159.509 117.648 160.481 118.584 ;
     RECT  159.653 125.856 160.481 127.224 ;
     RECT  159.304 153.696 160.481 153.72 ;
     RECT  159.539 80.592 160.499 80.616 ;
     RECT  159.587 110.496 160.499 110.856 ;
     RECT  159.683 129.168 160.517 129.192 ;
     RECT  160.259 79.44 160.553 79.464 ;
     RECT  160.577 153.36 160.661 153.384 ;
     RECT  159.509 84.624 160.883 98.136 ;
     RECT  160.403 133.008 160.883 133.032 ;
     RECT  160.307 81.936 160.931 82.968 ;
     RECT  159.304 113.568 160.981 113.592 ;
     RECT  160.259 77.904 161.027 77.928 ;
     RECT  160.019 108.672 161.027 108.696 ;
     RECT  160.931 82.944 161.029 82.968 ;
     RECT  160.481 117.648 161.093 117.864 ;
     RECT  159.304 162.336 161.123 164.28 ;
     RECT  159.304 155.328 161.125 155.352 ;
     RECT  160.211 59.28 161.165 59.592 ;
     RECT  159.304 156.432 161.219 160.344 ;
     RECT  160.067 99.168 161.267 104.28 ;
     RECT  161.123 162.384 161.363 164.28 ;
     RECT  159.304 165.36 161.603 168.696 ;
     RECT  161.363 162.384 161.651 163.704 ;
     RECT  161.651 163.68 161.699 163.704 ;
     RECT  161.219 156.768 162.035 160.344 ;
     RECT  161.603 165.888 162.083 168.696 ;
     RECT  160.931 81.936 162.131 81.96 ;
     RECT  161.267 99.168 162.131 102.792 ;
     RECT  160.883 84.96 162.133 98.136 ;
     RECT  162.131 99.168 162.133 101.928 ;
     RECT  160.981 113.568 162.173 113.976 ;
     RECT  162.083 165.888 162.227 167.832 ;
     RECT  162.173 113.568 162.245 113.592 ;
     RECT  162.133 84.96 162.323 101.928 ;
     RECT  162.227 165.888 162.371 167.016 ;
     RECT  161.093 117.648 162.457 117.816 ;
     RECT  162.371 165.888 162.467 165.96 ;
     RECT  162.323 84.96 162.497 97.8 ;
     RECT  162.457 117.648 162.497 117.912 ;
     RECT  160.067 105.744 162.515 105.768 ;
     RECT  161.267 103.872 162.533 104.28 ;
     RECT  162.323 99.408 162.563 101.928 ;
     RECT  160.499 110.832 162.659 110.856 ;
     RECT  162.497 84.96 162.707 97.032 ;
     RECT  162.707 87.6 162.755 97.032 ;
     RECT  162.563 99.408 162.755 101.88 ;
     RECT  162.533 103.872 162.755 103.896 ;
     RECT  162.755 99.696 162.785 101.88 ;
     RECT  162.755 89.28 162.821 97.032 ;
     RECT  162.821 92.832 163.043 97.032 ;
     RECT  162.371 166.992 163.043 167.016 ;
     RECT  163.043 92.832 163.181 95.112 ;
     RECT  162.821 89.28 163.187 91.704 ;
     RECT  161.651 162.384 163.187 162.408 ;
     RECT  163.181 93.216 163.283 95.112 ;
     RECT  160.481 127.104 163.283 127.224 ;
     RECT  161.029 82.944 163.361 83.016 ;
     RECT  161.125 155.28 163.361 155.352 ;
     RECT  162.707 84.96 163.379 86.568 ;
     RECT  162.755 87.6 163.427 88.248 ;
     RECT  161.165 59.568 164.408 59.592 ;
     RECT  159.304 75.168 164.408 75.192 ;
     RECT  163.361 82.992 164.408 83.016 ;
     RECT  163.379 84.96 164.408 85.896 ;
     RECT  163.427 87.648 164.408 88.248 ;
     RECT  163.187 89.28 164.408 91.656 ;
     RECT  163.283 93.264 164.408 95.112 ;
     RECT  163.043 96.432 164.408 97.032 ;
     RECT  162.785 99.984 164.408 101.88 ;
     RECT  160.019 107.232 164.408 107.256 ;
     RECT  162.497 117.792 164.408 117.912 ;
     RECT  159.617 122.976 164.408 123 ;
     RECT  160.481 125.856 164.408 125.88 ;
     RECT  163.283 127.2 164.408 127.224 ;
     RECT  160.211 131.088 164.408 131.112 ;
     RECT  163.361 155.28 164.408 155.304 ;
     RECT  162.035 156.768 164.408 159.192 ;
     RECT  162.035 160.32 164.408 160.344 ;
     RECT  162.467 165.936 164.408 165.96 ;
     RECT  164.408 2.148 164.512 192.252 ;
     RECT  164.512 2.418 164.704 191.982 ;
     RECT  164.704 59.568 165.341 59.592 ;
     RECT  164.704 131.088 165.341 131.112 ;
     RECT  164.704 84.96 165.377 84.984 ;
     RECT  164.704 91.392 165.629 91.656 ;
     RECT  164.704 93.264 165.629 93.336 ;
     RECT  165.629 91.632 165.917 91.656 ;
     RECT  165.629 93.264 165.917 93.288 ;
     RECT  164.704 117.792 167.033 117.912 ;
     RECT  164.704 97.008 169.808 97.032 ;
     RECT  167.033 117.792 169.808 117.816 ;
     RECT  164.704 122.976 169.808 123 ;
     RECT  169.808 2.148 169.912 192.252 ;
     RECT  169.912 2.418 170.104 191.982 ;
     RECT  170.104 117.792 172.213 117.816 ;
     RECT  172.213 117.792 172.253 118.056 ;
     RECT  170.104 97.008 175.208 97.032 ;
     RECT  172.253 118.032 175.208 118.056 ;
     RECT  170.104 122.976 175.208 123 ;
     RECT  175.208 2.148 175.312 192.252 ;
     RECT  175.312 2.418 175.504 191.982 ;
     RECT  175.504 97.008 180.608 97.032 ;
     RECT  175.504 118.032 180.608 118.056 ;
     RECT  175.504 122.976 180.608 123 ;
     RECT  180.608 2.148 180.712 192.252 ;
     RECT  180.712 2.418 180.904 191.982 ;
     RECT  180.904 96.432 186.008 97.032 ;
     RECT  180.904 118.032 186.008 118.056 ;
     RECT  180.904 122.976 186.008 123 ;
     RECT  186.008 2.148 186.112 192.252 ;
     RECT  186.112 2.418 186.304 191.982 ;
     RECT  186.304 96.432 191.408 97.032 ;
     RECT  186.304 118.032 191.408 118.056 ;
     RECT  186.304 122.976 191.408 123 ;
     RECT  191.408 2.148 191.512 192.252 ;
     RECT  191.512 2.418 191.704 191.982 ;
     RECT  191.704 118.032 194.353 118.056 ;
     RECT  194.353 118.032 194.393 118.152 ;
     RECT  195.029 90.624 195.061 90.648 ;
     RECT  195.061 89.28 195.113 90.648 ;
     RECT  195.113 89.28 195.148 90.264 ;
     RECT  191.704 96.432 195.181 97.032 ;
     RECT  191.704 122.976 195.469 123 ;
     RECT  194.929 105.312 195.493 105.336 ;
     RECT  195.217 106.752 195.493 106.776 ;
     RECT  195.217 115.488 195.493 115.512 ;
     RECT  195.493 104.832 195.539 106.776 ;
     RECT  195.493 115.392 195.539 115.512 ;
     RECT  195.181 77.52 195.545 77.544 ;
     RECT  195.469 122.592 195.637 123 ;
     RECT  195.539 106.176 195.761 106.776 ;
     RECT  195.073 116.88 195.925 116.904 ;
     RECT  194.393 118.128 195.925 118.152 ;
     RECT  195.181 96.432 196.009 97.464 ;
     RECT  195.721 120.096 196.021 120.12 ;
     RECT  195.829 121.44 196.021 121.464 ;
     RECT  195.433 113.376 196.153 113.4 ;
     RECT  196.009 96.192 196.297 97.464 ;
     RECT  195.145 98.592 196.297 98.616 ;
     RECT  195.073 72.96 196.333 72.984 ;
     RECT  196.153 74.64 196.333 74.664 ;
     RECT  195.925 116.88 196.477 118.152 ;
     RECT  196.333 80.928 196.585 80.952 ;
     RECT  196.333 103.728 196.657 103.752 ;
     RECT  195.289 86.592 196.693 87.336 ;
     RECT  195.649 93.936 196.693 93.96 ;
     RECT  195.761 106.752 196.801 106.776 ;
     RECT  196.333 72.96 196.808 74.664 ;
     RECT  196.657 77.04 196.808 77.064 ;
     RECT  196.585 78.624 196.808 78.648 ;
     RECT  196.585 80.4 196.808 80.952 ;
     RECT  196.765 84.576 196.808 84.6 ;
     RECT  196.693 86.592 196.808 87.864 ;
     RECT  195.148 90.24 196.808 90.264 ;
     RECT  196.477 91.872 196.808 91.896 ;
     RECT  196.693 93.6 196.808 93.96 ;
     RECT  196.297 96.192 196.808 98.616 ;
     RECT  195.073 100.272 196.808 100.296 ;
     RECT  195.073 102.24 196.808 102.264 ;
     RECT  196.657 103.728 196.808 103.848 ;
     RECT  195.539 104.832 196.808 104.856 ;
     RECT  196.801 106.032 196.808 106.776 ;
     RECT  196.297 107.904 196.808 107.928 ;
     RECT  195.037 110.88 196.808 110.904 ;
     RECT  196.153 113.376 196.808 113.88 ;
     RECT  195.539 115.392 196.808 115.416 ;
     RECT  196.477 116.88 196.808 118.2 ;
     RECT  196.021 120.096 196.808 121.464 ;
     RECT  195.637 122.496 196.808 123 ;
     RECT  196.808 2.148 196.912 192.252 ;
     RECT  196.912 2.418 197.104 191.982 ;
     RECT  197.104 91.872 197.219 93.624 ;
     RECT  197.104 87.84 197.267 87.864 ;
     RECT  197.104 80.832 197.309 80.856 ;
     RECT  197.104 82.368 197.315 82.392 ;
     RECT  197.104 95.664 197.315 98.328 ;
     RECT  197.104 107.52 197.315 107.928 ;
     RECT  197.104 118.128 197.315 118.632 ;
     RECT  197.104 120.288 197.353 121.08 ;
     RECT  197.104 73.776 197.417 75.432 ;
     RECT  197.104 88.944 197.417 90.264 ;
     RECT  197.104 112.944 197.417 113.88 ;
     RECT  197.104 109.92 197.453 110.904 ;
     RECT  197.219 91.872 197.596 92.952 ;
     RECT  197.417 74.064 197.633 75.432 ;
     RECT  197.104 77.04 197.633 78.648 ;
     RECT  197.315 118.176 197.633 118.632 ;
     RECT  197.104 85.968 197.644 86.616 ;
     RECT  197.644 86.064 197.651 86.616 ;
     RECT  197.417 89.52 197.651 89.544 ;
     RECT  197.315 97.632 197.74 98.328 ;
     RECT  197.596 91.872 197.741 92.472 ;
     RECT  197.104 84.576 197.849 84.6 ;
     RECT  197.651 86.16 197.957 86.616 ;
     RECT  197.315 95.664 198.029 96.36 ;
     RECT  197.353 120.816 198.065 121.08 ;
     RECT  197.315 107.904 198.085 107.928 ;
     RECT  197.104 103.728 198.097 103.848 ;
     RECT  197.104 105.168 198.097 106.056 ;
     RECT  197.453 109.92 198.131 109.944 ;
     RECT  198.097 103.728 198.137 106.056 ;
     RECT  197.104 122.976 198.137 123 ;
     RECT  197.104 115.344 198.241 116.232 ;
     RECT  197.633 74.064 198.245 74.616 ;
     RECT  197.741 92.448 198.281 92.472 ;
     RECT  197.104 99.456 198.389 100.296 ;
     RECT  198.085 107.904 198.425 108.84 ;
     RECT  197.74 97.632 198.497 97.656 ;
     RECT  198.137 104.208 198.563 106.056 ;
     RECT  197.633 77.424 198.569 78.648 ;
     RECT  197.104 79.68 198.569 79.704 ;
     RECT  198.569 77.424 198.604 77.976 ;
     RECT  198.133 91.2 198.605 91.224 ;
     RECT  198.425 108.816 198.605 108.84 ;
     RECT  198.421 101.424 198.613 101.448 ;
     RECT  198.517 102.48 198.613 103.224 ;
     RECT  198.613 101.424 198.659 103.224 ;
     RECT  198.659 102.096 198.677 103.224 ;
     RECT  198.677 102.096 198.7 102.12 ;
     RECT  198.385 82.8 198.713 82.824 ;
     RECT  197.633 118.608 198.713 118.632 ;
     RECT  198.563 104.304 198.749 106.056 ;
     RECT  197.417 112.944 198.781 112.968 ;
     RECT  198.385 87.12 198.785 87.576 ;
     RECT  198.065 120.816 198.785 120.84 ;
     RECT  198.749 106.032 198.817 106.056 ;
     RECT  198.781 112.944 198.817 113.64 ;
     RECT  198.241 114.72 198.929 116.232 ;
     RECT  198.245 74.064 198.965 74.088 ;
     RECT  198.421 81.168 198.965 81.192 ;
     RECT  198.389 100.272 198.965 100.296 ;
     RECT  198.749 104.304 198.965 104.328 ;
     RECT  198.604 77.952 199.037 77.976 ;
     RECT  198.817 106.032 199.037 106.632 ;
     RECT  198.709 85.488 199.109 85.512 ;
     RECT  198.785 87.12 199.109 87.144 ;
     RECT  198.529 93.456 199.181 93.48 ;
     RECT  198.929 115.536 199.217 116.232 ;
     RECT  198.677 103.2 199.253 103.224 ;
     RECT  198.817 112.752 199.469 113.64 ;
     RECT  199.469 113.616 199.573 113.64 ;
     RECT  198.961 72.384 199.577 72.408 ;
     RECT  199.609 121.488 199.829 121.512 ;
     RECT  199.969 88.32 200.005 88.344 ;
     RECT  199.789 105.936 200.005 105.96 ;
     RECT  199.573 113.616 200.045 113.736 ;
     RECT  199.357 116.592 200.405 116.76 ;
     RECT  200.005 105.936 200.513 106.152 ;
     RECT  200.005 87.408 200.693 88.344 ;
     RECT  200.545 102.384 200.761 102.408 ;
     RECT  199.681 98.592 200.801 98.616 ;
     RECT  201.049 108.72 201.085 108.744 ;
     RECT  200.761 89.712 201.193 89.736 ;
     RECT  200.045 113.712 201.229 113.736 ;
     RECT  200.617 95.664 201.265 95.688 ;
     RECT  200.761 101.424 201.265 102.408 ;
     RECT  200.725 103.536 201.265 103.56 ;
     RECT  199.753 84.336 201.301 84.36 ;
     RECT  201.229 113.712 201.337 114.12 ;
     RECT  199.217 115.536 201.337 115.56 ;
     RECT  200.149 79.92 201.409 79.944 ;
     RECT  201.265 81.072 201.409 81.096 ;
     RECT  201.337 93.744 201.517 93.96 ;
     RECT  201.265 95.28 201.517 95.688 ;
     RECT  200.617 97.392 201.517 97.416 ;
     RECT  201.265 101.424 201.517 103.56 ;
     RECT  200.405 116.592 201.521 116.616 ;
     RECT  201.517 101.04 201.733 103.56 ;
     RECT  201.193 104.88 201.733 104.904 ;
     RECT  201.301 83.376 201.769 84.36 ;
     RECT  201.301 88.56 201.769 88.584 ;
     RECT  201.193 89.712 201.769 90.504 ;
     RECT  201.733 101.04 201.769 104.904 ;
     RECT  200.513 106.032 201.769 106.152 ;
     RECT  201.337 111.024 201.769 111.048 ;
     RECT  201.733 119.472 201.769 119.496 ;
     RECT  200.725 120.816 201.769 120.84 ;
     RECT  201.517 93.744 201.805 95.688 ;
     RECT  201.769 117.936 201.805 117.96 ;
     RECT  201.769 100.848 201.809 106.152 ;
     RECT  201.805 75.888 201.841 75.912 ;
     RECT  201.805 77.232 201.841 77.256 ;
     RECT  200.869 112.56 201.841 112.584 ;
     RECT  201.337 113.712 201.841 115.56 ;
     RECT  201.841 73.584 201.913 73.608 ;
     RECT  201.913 73.584 201.949 73.992 ;
     RECT  201.769 119.472 202.237 120.84 ;
     RECT  201.085 108.336 202.273 108.744 ;
     RECT  201.301 109.872 202.273 109.896 ;
     RECT  201.841 112.56 202.273 115.56 ;
     RECT  202.237 119.472 202.273 121.416 ;
     RECT  201.409 79.92 202.309 81.096 ;
     RECT  201.769 83.376 202.309 85.128 ;
     RECT  201.769 88.56 202.309 91.08 ;
     RECT  201.809 100.848 202.309 106.056 ;
     RECT  202.273 119.472 202.309 121.8 ;
     RECT  201.841 75.888 202.345 77.256 ;
     RECT  201.301 78.384 202.345 78.408 ;
     RECT  202.309 79.92 202.345 81.48 ;
     RECT  200.693 87.408 202.345 87.432 ;
     RECT  202.309 88.56 202.345 91.272 ;
     RECT  201.805 93.168 202.345 95.688 ;
     RECT  201.517 97.392 202.345 97.608 ;
     RECT  201.769 99.312 202.345 99.336 ;
     RECT  202.273 108.336 202.345 109.896 ;
     RECT  201.769 111.024 202.345 111.432 ;
     RECT  202.345 99.12 202.849 99.336 ;
     RECT  202.309 100.656 202.849 106.056 ;
     RECT  202.273 112.56 202.849 115.656 ;
     RECT  201.949 73.584 202.885 74.76 ;
     RECT  202.345 75.888 202.885 81.48 ;
     RECT  202.309 82.8 202.885 85.128 ;
     RECT  202.345 87.024 202.885 87.432 ;
     RECT  202.345 88.56 202.885 97.608 ;
     RECT  202.849 99.12 202.885 106.056 ;
     RECT  202.849 112.56 202.885 116.04 ;
     RECT  201.805 117.168 202.885 117.96 ;
     RECT  202.885 73.584 202.921 85.704 ;
     RECT  202.885 86.832 202.921 97.608 ;
     RECT  202.885 99.12 202.921 107.208 ;
     RECT  202.345 108.336 202.921 111.432 ;
     RECT  202.885 112.56 202.921 117.96 ;
     RECT  202.309 119.088 202.921 121.992 ;
     RECT  202.921 72.816 203.425 97.8 ;
     RECT  202.921 99.12 203.425 111.432 ;
     RECT  202.921 112.56 203.425 121.992 ;
     RECT  203.425 72.816 203.497 121.992 ;
     RECT  203.497 72.432 204.3 121.992 ;
    LAYER M5 ;
     RECT  2.4 2.137 2.52 2.151 ;
     RECT  7.8 2.137 7.92 2.151 ;
     RECT  13.2 2.137 13.32 2.151 ;
     RECT  18.6 2.137 18.72 2.151 ;
     RECT  24 2.137 24.12 2.151 ;
     RECT  29.4 2.137 29.52 2.151 ;
     RECT  34.8 2.137 34.92 2.151 ;
     RECT  40.2 2.137 40.32 2.151 ;
     RECT  45.6 2.137 45.72 2.151 ;
     RECT  51 2.137 51.12 2.151 ;
     RECT  56.4 2.137 56.52 2.151 ;
     RECT  61.8 2.137 61.92 2.151 ;
     RECT  67.2 2.137 67.32 2.151 ;
     RECT  72.6 2.137 72.72 2.151 ;
     RECT  78 2.137 78.12 2.151 ;
     RECT  83.4 2.137 83.52 2.151 ;
     RECT  88.8 2.137 88.92 2.151 ;
     RECT  94.2 2.137 94.32 2.151 ;
     RECT  99.6 2.137 99.72 2.151 ;
     RECT  105 2.137 105.12 2.151 ;
     RECT  110.4 2.137 110.52 2.151 ;
     RECT  115.8 2.137 115.92 2.151 ;
     RECT  121.2 2.137 121.32 2.151 ;
     RECT  126.6 2.137 126.72 2.151 ;
     RECT  132 2.137 132.12 2.151 ;
     RECT  137.4 2.137 137.52 2.151 ;
     RECT  142.8 2.137 142.92 2.151 ;
     RECT  148.2 2.137 148.32 2.151 ;
     RECT  153.6 2.137 153.72 2.151 ;
     RECT  159 2.137 159.12 2.151 ;
     RECT  164.4 2.137 164.52 2.151 ;
     RECT  169.8 2.137 169.92 2.151 ;
     RECT  175.2 2.137 175.32 2.151 ;
     RECT  180.6 2.137 180.72 2.151 ;
     RECT  186 2.137 186.12 2.151 ;
     RECT  191.4 2.137 191.52 2.151 ;
     RECT  196.8 2.137 196.92 2.151 ;
     RECT  7.8 2.151 8.112 54.853 ;
     RECT  150.816 54.661 150.84 54.853 ;
     RECT  7.632 54.853 8.112 55.141 ;
     RECT  150.768 54.853 150.84 55.141 ;
     RECT  7.632 55.141 8.232 55.381 ;
     RECT  9.408 54.565 9.432 55.381 ;
     RECT  150.768 55.141 150.888 55.477 ;
     RECT  150.768 55.477 151.32 55.669 ;
     RECT  6.576 55.669 6.6 55.957 ;
     RECT  7.632 55.381 9.432 55.957 ;
     RECT  150.72 55.669 151.32 55.957 ;
     RECT  150.24 55.957 151.32 56.821 ;
     RECT  45.6 2.151 45.912 56.869 ;
     RECT  150.24 56.821 151.368 56.869 ;
     RECT  6.576 55.957 9.432 57.349 ;
     RECT  150.24 56.869 151.464 57.349 ;
     RECT  40.2 2.151 40.512 57.445 ;
     RECT  149.904 57.349 151.464 57.491 ;
     RECT  6.576 57.349 9.96 57.541 ;
     RECT  44.976 56.869 45.912 57.635 ;
     RECT  6.528 57.541 9.96 57.829 ;
     RECT  40.2 57.445 40.728 57.925 ;
     RECT  115.8 2.151 116.112 57.973 ;
     RECT  150.24 57.491 151.464 59.077 ;
     RECT  153.6 2.151 153.912 59.365 ;
     RECT  51 2.151 51.312 59.653 ;
     RECT  159 2.151 159.312 59.749 ;
     RECT  51 59.653 52.056 59.845 ;
     RECT  51 59.845 52.392 60.133 ;
     RECT  152.832 59.365 153.912 64.405 ;
     RECT  152.832 64.405 154.488 65.941 ;
     RECT  51 60.133 53.304 66.469 ;
     RECT  152.832 65.941 154.776 66.805 ;
     RECT  152.592 66.805 154.776 66.947 ;
     RECT  152.832 66.947 154.776 68.245 ;
     RECT  157.056 67.669 157.08 68.965 ;
     RECT  156.144 68.965 157.08 69.587 ;
     RECT  50.688 66.469 53.304 69.829 ;
     RECT  156.144 69.587 156.168 71.269 ;
     RECT  156.096 71.269 156.168 71.509 ;
     RECT  152.832 68.245 155.016 71.797 ;
     RECT  156.096 71.509 156.792 71.797 ;
     RECT  2.4 2.151 2.712 72.037 ;
     RECT  40.2 57.925 40.824 72.515 ;
     RECT  40.2 72.515 40.728 72.851 ;
     RECT  150.192 59.077 151.464 72.901 ;
     RECT  152.832 71.797 156.792 72.901 ;
     RECT  150.192 72.901 156.792 72.949 ;
     RECT  2.4 72.037 3.384 72.995 ;
     RECT  5.328 57.301 5.352 73.477 ;
     RECT  6.48 57.829 9.96 73.477 ;
     RECT  196.8 2.151 197.112 74.581 ;
     RECT  3.984 74.437 4.008 74.771 ;
     RECT  164.4 2.151 164.712 75.157 ;
     RECT  150.192 72.949 157.272 75.205 ;
     RECT  5.328 73.477 9.96 75.299 ;
     RECT  5.664 75.299 9.96 76.403 ;
     RECT  6.672 76.403 8.808 76.451 ;
     RECT  150.192 75.205 157.848 76.837 ;
     RECT  159 59.749 160.2 76.837 ;
     RECT  54.384 66.757 54.408 76.933 ;
     RECT  7.8 76.451 8.808 76.979 ;
     RECT  54.384 76.933 55.224 77.075 ;
     RECT  6.672 76.451 6.696 77.603 ;
     RECT  150.192 76.837 160.2 77.699 ;
     RECT  150.24 77.699 160.2 77.893 ;
     RECT  198.528 77.413 198.552 77.987 ;
     RECT  5.664 76.403 5.688 78.037 ;
     RECT  196.8 74.581 197.496 78.131 ;
     RECT  3.984 75.781 4.008 78.323 ;
     RECT  7.8 76.979 8.664 78.613 ;
     RECT  50.112 69.829 53.304 78.901 ;
     RECT  54.384 77.075 54.408 78.901 ;
     RECT  5.664 78.037 6.264 79.189 ;
     RECT  7.536 78.613 8.664 79.189 ;
     RECT  9.696 78.037 9.72 79.189 ;
     RECT  150.24 77.893 161.016 80.965 ;
     RECT  9.696 79.189 9.96 81.445 ;
     RECT  5.664 79.189 8.664 82.069 ;
     RECT  50.112 78.901 54.408 82.117 ;
     RECT  150.192 80.965 161.016 82.981 ;
     RECT  5.328 82.069 8.664 83.173 ;
     RECT  9.696 81.445 10.056 83.173 ;
     RECT  5.328 83.173 10.056 84.325 ;
     RECT  21.408 83.749 21.432 84.901 ;
     RECT  150.192 82.981 161.064 85.141 ;
     RECT  162.096 81.925 162.12 85.141 ;
     RECT  150.192 85.141 162.12 85.237 ;
     RECT  163.776 75.157 164.712 85.237 ;
     RECT  196.8 78.131 197.304 85.957 ;
     RECT  196.8 85.957 197.592 86.053 ;
     RECT  50.112 82.117 54.984 88.069 ;
     RECT  50.112 88.069 55.08 88.309 ;
     RECT  196.8 86.053 197.64 89.555 ;
     RECT  5.328 84.325 10.488 89.989 ;
     RECT  195.072 89.269 195.096 90.659 ;
     RECT  150.192 85.237 164.712 91.043 ;
     RECT  4.56 89.989 10.488 91.187 ;
     RECT  150.24 91.043 164.712 91.811 ;
     RECT  196.8 89.555 197.208 91.861 ;
     RECT  150.336 91.811 164.712 92.917 ;
     RECT  196.8 91.861 197.544 92.963 ;
     RECT  150.192 92.917 164.712 93.155 ;
     RECT  3.936 92.293 3.96 93.539 ;
     RECT  196.8 92.963 197.208 93.589 ;
     RECT  196.704 93.589 197.208 93.635 ;
     RECT  5.328 91.187 10.488 94.549 ;
     RECT  4.56 94.549 10.488 94.979 ;
     RECT  150.24 93.155 164.712 95.269 ;
     RECT  150.192 95.269 164.712 95.459 ;
     RECT  196.704 93.635 197.112 96.467 ;
     RECT  196.8 96.467 197.112 96.997 ;
     RECT  196.8 96.997 197.304 97.621 ;
     RECT  5.328 94.979 10.488 97.811 ;
     RECT  196.8 97.621 197.688 98.339 ;
     RECT  5.712 97.811 10.488 98.675 ;
     RECT  148.2 2.151 148.512 99.445 ;
     RECT  150.24 95.459 164.712 99.445 ;
     RECT  56.4 2.151 56.712 99.541 ;
     RECT  67.2 2.151 67.512 99.637 ;
     RECT  146.448 58.069 146.472 99.637 ;
     RECT  50.112 88.309 55.224 100.019 ;
     RECT  66.72 99.637 67.512 100.021 ;
     RECT  148.2 99.445 164.712 100.117 ;
     RECT  61.8 2.151 62.112 100.549 ;
     RECT  66.72 100.021 67.848 100.597 ;
     RECT  22.656 97.717 22.68 100.693 ;
     RECT  24 2.151 24.312 100.741 ;
     RECT  146.448 99.637 146.856 100.789 ;
     RECT  148.08 100.117 164.712 100.789 ;
     RECT  61.68 100.549 62.112 100.837 ;
     RECT  22.656 100.693 22.824 100.883 ;
     RECT  142.8 2.151 143.112 101.125 ;
     RECT  6 98.675 10.488 101.317 ;
     RECT  5.52 101.317 10.488 101.365 ;
     RECT  61.68 100.837 62.232 101.507 ;
     RECT  66.096 100.597 67.848 101.507 ;
     RECT  68.928 100.261 68.952 101.507 ;
     RECT  66.72 101.507 67.848 101.555 ;
     RECT  61.8 101.507 62.232 101.603 ;
     RECT  144.816 101.653 144.84 101.749 ;
     RECT  97.488 101.413 97.512 101.795 ;
     RECT  83.4 2.151 83.712 101.845 ;
     RECT  5.088 101.365 10.488 101.891 ;
     RECT  83.4 101.845 83.976 101.941 ;
     RECT  56.4 99.541 57.096 101.987 ;
     RECT  144.768 101.749 144.84 101.987 ;
     RECT  94.2 2.151 94.512 101.989 ;
     RECT  38.736 100.693 38.76 102.035 ;
     RECT  66.72 101.555 67.512 102.035 ;
     RECT  5.088 101.891 10.056 102.083 ;
     RECT  67.104 102.035 67.512 102.083 ;
     RECT  3.936 101.413 3.96 102.131 ;
     RECT  24 100.741 24.504 102.131 ;
     RECT  198.624 101.413 198.648 102.131 ;
     RECT  5.52 102.083 10.056 102.467 ;
     RECT  6.192 102.467 10.056 102.707 ;
     RECT  47.616 99.685 47.64 102.755 ;
     RECT  61.8 101.603 62.112 102.805 ;
     RECT  144.768 101.987 144.792 102.851 ;
     RECT  6.192 102.707 9.816 102.947 ;
     RECT  83.4 101.941 84.408 102.995 ;
     RECT  83.4 102.995 83.832 103.043 ;
     RECT  58.8 102.949 58.824 103.045 ;
     RECT  86.4 102.565 86.424 103.045 ;
     RECT  58.704 103.045 58.824 103.091 ;
     RECT  61.8 102.805 62.232 103.091 ;
     RECT  58.704 103.091 58.728 103.187 ;
     RECT  70.704 103.045 70.728 103.187 ;
     RECT  86.208 103.045 86.424 103.187 ;
     RECT  21.408 84.901 21.48 103.331 ;
     RECT  9.744 102.947 9.816 103.379 ;
     RECT  99.6 2.151 99.912 103.477 ;
     RECT  99.6 103.477 100.344 103.907 ;
     RECT  94.2 101.989 94.728 104.003 ;
     RECT  146.448 100.789 164.712 104.003 ;
     RECT  21.408 103.331 21.432 104.051 ;
     RECT  6.192 102.947 8.472 104.197 ;
     RECT  198.528 102.469 198.552 104.243 ;
     RECT  86.4 103.187 86.424 104.435 ;
     RECT  50.112 100.019 55.176 105.253 ;
     RECT  50.112 105.253 55.224 105.491 ;
     RECT  5.712 104.197 8.472 105.779 ;
     RECT  198.384 105.397 198.408 106.067 ;
     RECT  50.112 105.491 51.864 106.259 ;
     RECT  9.792 103.379 9.816 106.451 ;
     RECT  195.504 104.821 195.528 106.787 ;
     RECT  0.144 106.885 0.168 107.363 ;
     RECT  99.6 103.907 99.912 107.365 ;
     RECT  7.392 105.779 8.472 107.555 ;
     RECT  196.8 98.339 197.304 107.555 ;
     RECT  5.712 105.779 5.736 107.701 ;
     RECT  5.712 107.701 6.168 107.747 ;
     RECT  105 2.151 105.312 107.797 ;
     RECT  7.8 107.555 8.472 108.083 ;
     RECT  196.8 107.555 197.256 108.805 ;
     RECT  196.8 108.805 198.12 109.955 ;
     RECT  196.8 109.955 197.256 110.099 ;
     RECT  6.144 107.747 6.168 110.197 ;
     RECT  5.952 110.197 6.168 112.261 ;
     RECT  7.8 108.083 8.112 112.261 ;
     RECT  104.544 107.797 105.312 112.885 ;
     RECT  22.656 100.883 22.68 112.931 ;
     RECT  67.2 102.083 67.512 112.933 ;
     RECT  139.632 57.445 139.656 113.173 ;
     RECT  5.952 112.261 8.112 113.365 ;
     RECT  5.52 113.365 8.112 113.747 ;
     RECT  2.4 72.995 2.712 114.517 ;
     RECT  5.952 113.747 8.112 114.611 ;
     RECT  132 2.151 132.312 114.853 ;
     RECT  142.128 101.125 143.112 115.187 ;
     RECT  196.8 110.099 197.112 115.669 ;
     RECT  2.4 114.517 3.624 115.763 ;
     RECT  195.504 115.381 195.528 116.869 ;
     RECT  196.8 115.669 197.304 116.869 ;
     RECT  52.944 105.491 55.224 116.915 ;
     RECT  195.504 116.869 197.304 116.915 ;
     RECT  195.936 116.915 197.304 117.539 ;
     RECT  2.4 115.763 2.712 119.653 ;
     RECT  50.112 106.259 51.312 119.939 ;
     RECT  110.4 2.151 110.712 119.941 ;
     RECT  196.8 117.539 197.304 120.085 ;
     RECT  196.032 120.085 197.304 120.323 ;
     RECT  52.992 116.915 55.224 120.517 ;
     RECT  2.4 119.653 2.808 120.899 ;
     RECT  5.952 114.611 5.976 121.237 ;
     RECT  196.032 120.323 197.112 121.475 ;
     RECT  4.608 121.717 4.632 121.957 ;
     RECT  5.952 121.237 6.168 121.957 ;
     RECT  4.608 121.957 6.168 122.387 ;
     RECT  195.648 122.485 195.672 122.627 ;
     RECT  5.184 122.387 6.168 123.347 ;
     RECT  109.824 119.941 110.712 123.445 ;
     RECT  6.048 123.347 6.168 123.637 ;
     RECT  99.6 107.365 100.824 123.731 ;
     RECT  22.512 122.485 22.536 123.779 ;
     RECT  109.44 123.445 110.712 123.973 ;
     RECT  99.6 123.731 99.912 124.213 ;
     RECT  26.208 123.781 26.232 124.307 ;
     RECT  6.048 123.637 6.408 124.547 ;
     RECT  6.384 124.547 6.408 124.835 ;
     RECT  108.864 123.973 110.712 124.835 ;
     RECT  115.392 57.973 116.112 125.459 ;
     RECT  67.056 112.933 67.512 126.469 ;
     RECT  108.96 124.835 110.712 126.611 ;
     RECT  142.8 115.187 143.112 126.757 ;
     RECT  66.72 126.469 67.512 126.803 ;
     RECT  139.344 113.173 139.656 126.803 ;
     RECT  142.608 126.757 143.112 126.995 ;
     RECT  131.328 114.853 132.312 127.139 ;
     RECT  104.112 112.885 105.312 127.283 ;
     RECT  121.2 2.151 121.512 127.285 ;
     RECT  98.976 124.213 99.912 127.669 ;
     RECT  100.944 125.365 100.968 127.669 ;
     RECT  107.76 123.781 107.784 127.669 ;
     RECT  109.488 126.611 110.712 127.669 ;
     RECT  96.96 127.669 97.944 127.717 ;
     RECT  98.976 127.669 100.968 127.717 ;
     RECT  147.168 104.003 164.712 128.627 ;
     RECT  147.168 128.627 148.68 129.155 ;
     RECT  107.76 127.669 110.712 129.349 ;
     RECT  149.904 128.627 164.712 129.491 ;
     RECT  150.192 129.491 164.712 129.587 ;
     RECT  150.24 129.587 164.712 130.837 ;
     RECT  150.192 130.837 164.712 133.187 ;
     RECT  150.24 133.187 164.712 135.925 ;
     RECT  150.192 135.925 164.712 136.211 ;
     RECT  52.416 120.517 55.224 139.763 ;
     RECT  53.472 139.763 55.224 139.811 ;
     RECT  52.416 139.763 52.44 141.347 ;
     RECT  150.24 136.211 164.712 141.925 ;
     RECT  150.192 141.925 164.712 142.115 ;
     RECT  53.664 139.811 55.224 144.899 ;
     RECT  150.24 142.115 164.712 146.437 ;
     RECT  150.192 146.437 164.712 146.579 ;
     RECT  150.24 146.579 164.712 147.155 ;
     RECT  150.384 147.155 164.712 149.125 ;
     RECT  150.192 149.125 164.712 149.891 ;
     RECT  150.288 149.891 164.712 152.773 ;
     RECT  54.96 144.899 55.224 154.019 ;
     RECT  150.24 152.773 164.712 156.563 ;
     RECT  54.96 154.019 55.08 160.213 ;
     RECT  54.96 160.213 55.224 160.259 ;
     RECT  150.288 156.563 164.712 160.355 ;
     RECT  150.288 160.355 163.176 162.419 ;
     RECT  55.2 160.259 55.224 162.997 ;
     RECT  53.664 144.899 53.688 163.187 ;
     RECT  55.104 162.997 55.224 163.235 ;
     RECT  150.288 162.419 163.032 164.099 ;
     RECT  150.288 164.099 159.312 164.149 ;
     RECT  150.192 164.149 159.312 164.819 ;
     RECT  160.8 164.099 163.032 165.395 ;
     RECT  55.2 163.235 55.224 166.307 ;
     RECT  161.856 165.395 163.032 167.027 ;
     RECT  161.856 167.027 162.216 167.267 ;
     RECT  150.288 164.819 159.312 167.843 ;
     RECT  162.048 167.267 162.216 167.843 ;
     RECT  150.288 167.843 154.536 167.893 ;
     RECT  150.192 167.893 154.536 168.035 ;
     RECT  160.8 165.395 160.824 168.083 ;
     RECT  155.712 167.843 159.312 168.131 ;
     RECT  150.192 168.035 154.056 168.515 ;
     RECT  152.88 168.515 154.056 168.611 ;
     RECT  162.048 167.843 162.072 168.707 ;
     RECT  155.712 168.131 156.312 168.995 ;
     RECT  150.192 168.515 151.32 169.091 ;
     RECT  155.712 168.995 155.928 169.187 ;
     RECT  152.88 168.611 153.912 169.283 ;
     RECT  157.392 168.131 159.312 169.427 ;
     RECT  155.904 169.187 155.928 169.475 ;
     RECT  157.392 169.427 157.416 169.667 ;
     RECT  107.184 129.349 110.712 170.725 ;
     RECT  49.344 145.285 49.368 170.771 ;
     RECT  148.08 129.155 148.68 170.771 ;
     RECT  150.192 169.091 150.504 170.771 ;
     RECT  148.08 170.771 148.512 170.819 ;
     RECT  150.288 170.771 150.504 170.867 ;
     RECT  139.344 126.803 139.368 171.299 ;
     RECT  112.848 129.493 112.872 171.587 ;
     RECT  121.2 127.285 122.232 172.739 ;
     RECT  150.48 170.867 150.504 173.507 ;
     RECT  112.272 172.885 112.296 174.467 ;
     RECT  102.288 126.565 102.312 174.949 ;
     RECT  102.144 174.949 102.312 174.995 ;
     RECT  107.04 170.725 110.712 185.843 ;
     RECT  96.96 127.717 100.968 189.299 ;
     RECT  96.96 189.299 98.328 190.403 ;
     RECT  96.96 190.403 97.944 190.451 ;
     RECT  107.04 185.843 108.552 190.451 ;
     RECT  96.96 190.451 96.984 190.979 ;
     RECT  99.6 189.299 100.968 190.979 ;
     RECT  109.824 185.843 110.712 191.267 ;
     RECT  104.544 127.283 105.312 191.461 ;
     RECT  104.544 191.461 105.624 191.507 ;
     RECT  108.528 190.451 108.552 191.555 ;
     RECT  102.144 174.995 102.168 191.893 ;
     RECT  102.144 191.893 102.6 192.037 ;
     RECT  99.6 190.979 100.44 192.085 ;
     RECT  102.144 192.037 103.032 192.085 ;
     RECT  2.4 120.899 2.712 192.249 ;
     RECT  7.8 114.611 8.112 192.249 ;
     RECT  13.2 2.151 13.512 192.249 ;
     RECT  18.6 2.151 18.912 192.249 ;
     RECT  24 102.131 24.312 192.249 ;
     RECT  29.4 2.151 29.712 192.249 ;
     RECT  34.8 2.151 35.112 192.249 ;
     RECT  40.2 72.851 40.512 192.249 ;
     RECT  45.6 57.635 45.912 192.249 ;
     RECT  51 119.939 51.312 192.249 ;
     RECT  56.4 101.987 56.712 192.249 ;
     RECT  61.8 103.091 62.112 192.249 ;
     RECT  67.2 126.803 67.512 192.249 ;
     RECT  72.6 2.151 72.912 192.249 ;
     RECT  78 2.151 78.312 192.249 ;
     RECT  83.4 103.043 83.712 192.249 ;
     RECT  88.8 2.151 89.112 192.249 ;
     RECT  94.2 104.003 94.512 192.249 ;
     RECT  110.4 191.267 110.712 192.249 ;
     RECT  115.8 125.459 116.112 192.249 ;
     RECT  121.2 172.739 121.512 192.249 ;
     RECT  126.6 2.151 126.912 192.249 ;
     RECT  132 127.139 132.312 192.249 ;
     RECT  137.4 2.151 137.712 192.249 ;
     RECT  142.8 126.995 143.112 192.249 ;
     RECT  148.2 170.819 148.512 192.249 ;
     RECT  153.6 169.283 153.912 192.249 ;
     RECT  159 169.427 159.312 192.249 ;
     RECT  164.4 160.355 164.712 192.249 ;
     RECT  169.8 2.151 170.112 192.249 ;
     RECT  175.2 2.151 175.512 192.249 ;
     RECT  180.6 2.151 180.912 192.249 ;
     RECT  186 2.151 186.312 192.249 ;
     RECT  191.4 2.151 191.712 192.249 ;
     RECT  196.8 121.475 197.112 192.249 ;
     RECT  2.4 192.249 2.52 192.263 ;
     RECT  7.8 192.249 7.92 192.263 ;
     RECT  13.2 192.249 13.32 192.263 ;
     RECT  18.6 192.249 18.72 192.263 ;
     RECT  24 192.249 24.12 192.263 ;
     RECT  29.4 192.249 29.52 192.263 ;
     RECT  34.8 192.249 34.92 192.263 ;
     RECT  40.2 192.249 40.32 192.263 ;
     RECT  45.6 192.249 45.72 192.263 ;
     RECT  51 192.249 51.12 192.263 ;
     RECT  56.4 192.249 56.52 192.263 ;
     RECT  61.8 192.249 61.92 192.263 ;
     RECT  67.2 192.249 67.32 192.263 ;
     RECT  72.6 192.249 72.72 192.263 ;
     RECT  78 192.249 78.12 192.263 ;
     RECT  83.4 192.249 83.52 192.263 ;
     RECT  88.8 192.249 88.92 192.263 ;
     RECT  94.2 192.249 94.32 192.263 ;
     RECT  110.4 192.249 110.52 192.263 ;
     RECT  115.8 192.249 115.92 192.263 ;
     RECT  121.2 192.249 121.32 192.263 ;
     RECT  126.6 192.249 126.72 192.263 ;
     RECT  132 192.249 132.12 192.263 ;
     RECT  137.4 192.249 137.52 192.263 ;
     RECT  142.8 192.249 142.92 192.263 ;
     RECT  148.2 192.249 148.32 192.263 ;
     RECT  153.6 192.249 153.72 192.263 ;
     RECT  159 192.249 159.12 192.263 ;
     RECT  164.4 192.249 164.52 192.263 ;
     RECT  169.8 192.249 169.92 192.263 ;
     RECT  175.2 192.249 175.32 192.263 ;
     RECT  180.6 192.249 180.72 192.263 ;
     RECT  186 192.249 186.12 192.263 ;
     RECT  191.4 192.249 191.52 192.263 ;
     RECT  196.8 192.249 196.92 192.263 ;
     RECT  99.6 192.085 103.032 192.373 ;
     RECT  99.552 192.373 103.032 192.613 ;
     RECT  105 191.507 105.624 192.613 ;
     RECT  107.328 192.085 107.352 192.613 ;
     RECT  96.096 192.085 96.12 193.237 ;
     RECT  97.824 192.085 97.848 193.237 ;
     RECT  99.552 192.613 108.216 193.237 ;
     RECT  96.096 193.237 108.216 194.384 ;
     RECT  8.112 54.565 9.408 55.141 ;
     RECT  8.232 55.141 9.408 55.381 ;
     RECT  6.6 55.669 7.632 55.957 ;
     RECT  5.352 57.301 6.576 57.541 ;
     RECT  148.512 57.349 149.904 57.491 ;
     RECT  5.352 57.541 6.528 57.829 ;
     RECT  5.352 57.829 6.48 73.477 ;
     RECT  151.464 59.365 152.832 66.805 ;
     RECT  53.304 66.757 54.384 78.901 ;
     RECT  151.464 66.805 152.592 66.947 ;
     RECT  151.464 66.947 152.832 72.901 ;
     RECT  155.016 68.965 156.144 71.269 ;
     RECT  155.016 71.269 156.096 71.797 ;
     RECT  2.712 72.995 3.384 74.437 ;
     RECT  2.712 74.437 3.984 74.771 ;
     RECT  4.008 74.437 5.328 74.771 ;
     RECT  2.712 74.771 5.328 75.299 ;
     RECT  157.848 75.205 159 76.837 ;
     RECT  2.712 75.299 4.008 75.781 ;
     RECT  2.712 75.781 3.984 78.323 ;
     RECT  5.688 76.403 6.672 77.603 ;
     RECT  6.696 76.451 7.8 77.603 ;
     RECT  55.224 76.933 56.4 77.075 ;
     RECT  8.664 76.979 8.808 78.037 ;
     RECT  197.496 77.413 198.528 77.987 ;
     RECT  5.688 77.603 7.8 78.037 ;
     RECT  6.264 78.037 7.8 78.613 ;
     RECT  8.664 78.037 9.696 83.173 ;
     RECT  6.264 78.613 7.536 79.189 ;
     RECT  161.016 81.925 162.096 82.981 ;
     RECT  54.984 82.117 56.4 88.069 ;
     RECT  161.064 82.981 162.096 85.141 ;
     RECT  55.08 88.069 56.4 88.309 ;
     RECT  55.224 88.309 56.4 100.019 ;
     RECT  4.56 91.187 5.328 92.293 ;
     RECT  150.24 91.811 150.336 92.917 ;
     RECT  2.712 92.293 3.936 93.539 ;
     RECT  3.96 92.293 5.328 93.539 ;
     RECT  4.56 93.539 5.328 94.549 ;
     RECT  21.48 97.717 22.656 103.331 ;
     RECT  22.68 97.717 24 100.693 ;
     RECT  146.856 99.637 148.2 100.117 ;
     RECT  55.176 100.019 56.4 105.253 ;
     RECT  146.856 100.117 148.08 100.789 ;
     RECT  67.848 100.261 68.928 101.507 ;
     RECT  22.824 100.693 24 100.883 ;
     RECT  38.76 100.693 40.2 102.035 ;
     RECT  22.68 100.883 24 112.931 ;
     RECT  2.712 101.413 3.936 102.131 ;
     RECT  3.96 101.413 5.088 102.083 ;
     RECT  197.304 101.413 198.624 102.131 ;
     RECT  62.112 101.603 62.232 102.805 ;
     RECT  197.304 102.131 198.552 102.469 ;
     RECT  197.304 102.469 198.528 104.243 ;
     RECT  8.472 102.947 9.744 103.379 ;
     RECT  21.432 103.331 22.656 104.051 ;
     RECT  8.472 103.379 9.792 106.451 ;
     RECT  197.304 104.243 198.408 105.397 ;
     RECT  195.528 104.821 196.8 106.787 ;
     RECT  55.224 105.253 56.4 154.019 ;
     RECT  197.304 105.397 198.384 106.067 ;
     RECT  51.864 105.491 52.944 106.259 ;
     RECT  197.256 107.555 197.304 108.805 ;
     RECT  195.528 115.381 196.8 116.869 ;
     RECT  51.312 120.517 52.416 141.347 ;
     RECT  196.032 121.475 196.8 122.485 ;
     RECT  4.632 121.717 5.952 121.957 ;
     RECT  22.536 122.485 24 123.779 ;
     RECT  195.672 122.485 196.8 122.627 ;
     RECT  6.408 123.637 7.8 124.835 ;
     RECT  107.784 123.973 108.864 124.835 ;
     RECT  107.784 124.835 108.96 126.611 ;
     RECT  99.912 125.365 100.944 127.669 ;
     RECT  100.968 126.565 102.288 174.949 ;
     RECT  107.784 126.611 109.488 127.669 ;
     RECT  97.944 127.669 98.976 127.717 ;
     RECT  148.68 128.627 149.904 129.491 ;
     RECT  148.68 129.491 150.192 129.587 ;
     RECT  148.68 129.587 150.24 130.837 ;
     RECT  148.68 130.837 150.192 133.187 ;
     RECT  148.68 135.925 150.192 136.211 ;
     RECT  52.44 139.763 53.472 139.811 ;
     RECT  52.44 139.811 53.664 141.347 ;
     RECT  148.68 141.925 150.192 142.115 ;
     RECT  53.688 144.899 54.96 160.259 ;
     RECT  148.68 146.437 150.192 146.579 ;
     RECT  148.68 149.125 150.192 149.891 ;
     RECT  55.08 154.019 56.4 160.213 ;
     RECT  55.224 160.213 56.4 166.307 ;
     RECT  53.688 160.259 55.2 162.997 ;
     RECT  163.176 160.355 164.4 162.419 ;
     RECT  163.032 162.419 164.4 167.027 ;
     RECT  53.688 162.997 55.104 163.187 ;
     RECT  159.312 164.099 160.8 168.083 ;
     RECT  148.68 164.149 150.192 164.819 ;
     RECT  160.824 165.395 161.856 167.267 ;
     RECT  160.824 167.267 162.048 168.083 ;
     RECT  154.536 167.843 155.712 168.035 ;
     RECT  148.68 167.893 150.192 170.771 ;
     RECT  156.312 168.131 157.392 168.995 ;
     RECT  155.928 168.995 157.392 169.475 ;
     RECT  100.968 174.949 102.144 190.979 ;
     RECT  108.552 185.843 109.824 191.267 ;
     RECT  98.328 189.299 99.6 190.403 ;
     RECT  100.44 190.979 102.144 192.085 ;
     RECT  104.544 191.507 105 192.037 ;
     RECT  103.032 192.037 105 192.613 ;
  END
END ot_hgi_hc_weight_quarter_static
END LIBRARY
